# Generated by gen_sram_macros.py (FakeRAM2.0 extended: 2R1W)
VERSION 5.7 ;
BUSBITCHARS "[]" ;
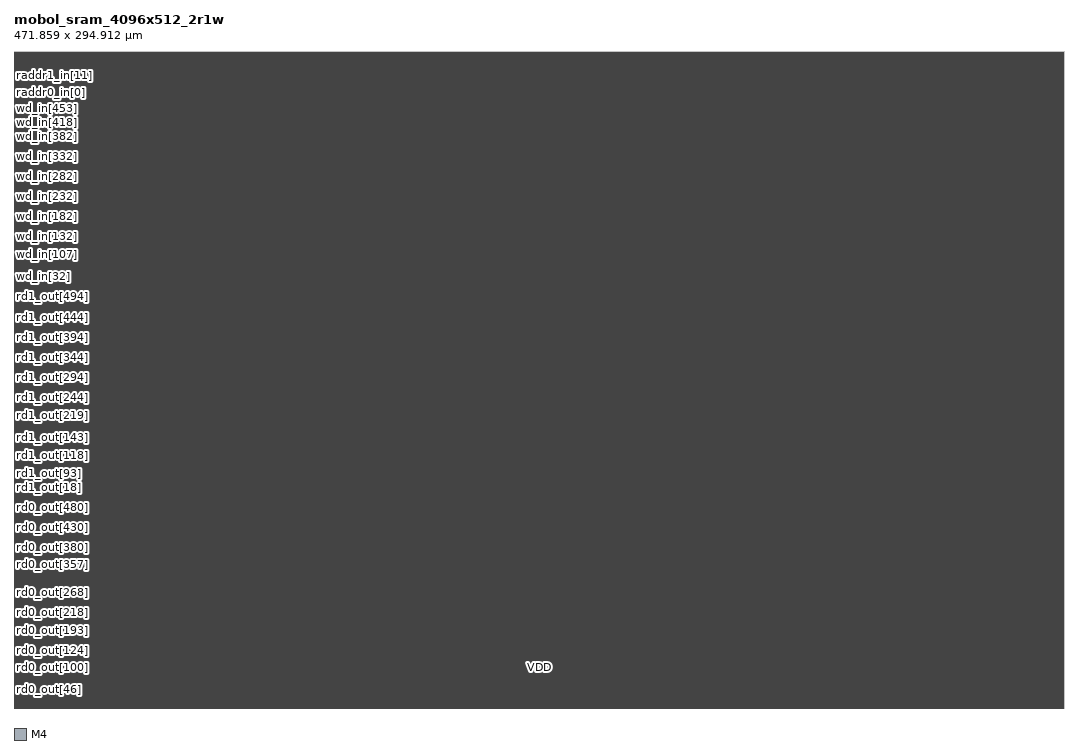
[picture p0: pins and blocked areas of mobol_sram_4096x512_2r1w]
MACRO mobol_sram_4096x512_2r1w
  FOREIGN mobol_sram_4096x512_2r1w 0 0 ;
  SYMMETRY X Y R90 ;
  SIZE 471.859 BY 294.912 ;
  CLASS BLOCK ;
  PIN rd0_out[0]
    DIRECTION OUTPUT ;
    USE SIGNAL ;
    SHAPE ABUTMENT ;
    PORT
      LAYER M4 ;
      RECT 0.000 0.036 0.018 0.054 ;
    END
  END rd0_out[0]
  PIN rd0_out[1]
    DIRECTION OUTPUT ;
    USE SIGNAL ;
    SHAPE ABUTMENT ;
    PORT
      LAYER M4 ;
      RECT 0.000 0.216 0.018 0.234 ;
    END
  END rd0_out[1]
  PIN rd0_out[2]
    DIRECTION OUTPUT ;
    USE SIGNAL ;
    SHAPE ABUTMENT ;
    PORT
      LAYER M4 ;
      RECT 0.000 0.396 0.018 0.414 ;
    END
  END rd0_out[2]
  PIN rd0_out[3]
    DIRECTION OUTPUT ;
    USE SIGNAL ;
    SHAPE ABUTMENT ;
    PORT
      LAYER M4 ;
      RECT 0.000 0.576 0.018 0.594 ;
    END
  END rd0_out[3]
  PIN rd0_out[4]
    DIRECTION OUTPUT ;
    USE SIGNAL ;
    SHAPE ABUTMENT ;
    PORT
      LAYER M4 ;
      RECT 0.000 0.756 0.018 0.774 ;
    END
  END rd0_out[4]
  PIN rd0_out[5]
    DIRECTION OUTPUT ;
    USE SIGNAL ;
    SHAPE ABUTMENT ;
    PORT
      LAYER M4 ;
      RECT 0.000 0.936 0.018 0.954 ;
    END
  END rd0_out[5]
  PIN rd0_out[6]
    DIRECTION OUTPUT ;
    USE SIGNAL ;
    SHAPE ABUTMENT ;
    PORT
      LAYER M4 ;
      RECT 0.000 1.116 0.018 1.134 ;
    END
  END rd0_out[6]
  PIN rd0_out[7]
    DIRECTION OUTPUT ;
    USE SIGNAL ;
    SHAPE ABUTMENT ;
    PORT
      LAYER M4 ;
      RECT 0.000 1.296 0.018 1.314 ;
    END
  END rd0_out[7]
  PIN rd0_out[8]
    DIRECTION OUTPUT ;
    USE SIGNAL ;
    SHAPE ABUTMENT ;
    PORT
      LAYER M4 ;
      RECT 0.000 1.476 0.018 1.494 ;
    END
  END rd0_out[8]
  PIN rd0_out[9]
    DIRECTION OUTPUT ;
    USE SIGNAL ;
    SHAPE ABUTMENT ;
    PORT
      LAYER M4 ;
      RECT 0.000 1.656 0.018 1.674 ;
    END
  END rd0_out[9]
  PIN rd0_out[10]
    DIRECTION OUTPUT ;
    USE SIGNAL ;
    SHAPE ABUTMENT ;
    PORT
      LAYER M4 ;
      RECT 0.000 1.836 0.018 1.854 ;
    END
  END rd0_out[10]
  PIN rd0_out[11]
    DIRECTION OUTPUT ;
    USE SIGNAL ;
    SHAPE ABUTMENT ;
    PORT
      LAYER M4 ;
      RECT 0.000 2.016 0.018 2.034 ;
    END
  END rd0_out[11]
  PIN rd0_out[12]
    DIRECTION OUTPUT ;
    USE SIGNAL ;
    SHAPE ABUTMENT ;
    PORT
      LAYER M4 ;
      RECT 0.000 2.196 0.018 2.214 ;
    END
  END rd0_out[12]
  PIN rd0_out[13]
    DIRECTION OUTPUT ;
    USE SIGNAL ;
    SHAPE ABUTMENT ;
    PORT
      LAYER M4 ;
      RECT 0.000 2.376 0.018 2.394 ;
    END
  END rd0_out[13]
  PIN rd0_out[14]
    DIRECTION OUTPUT ;
    USE SIGNAL ;
    SHAPE ABUTMENT ;
    PORT
      LAYER M4 ;
      RECT 0.000 2.556 0.018 2.574 ;
    END
  END rd0_out[14]
  PIN rd0_out[15]
    DIRECTION OUTPUT ;
    USE SIGNAL ;
    SHAPE ABUTMENT ;
    PORT
      LAYER M4 ;
      RECT 0.000 2.736 0.018 2.754 ;
    END
  END rd0_out[15]
  PIN rd0_out[16]
    DIRECTION OUTPUT ;
    USE SIGNAL ;
    SHAPE ABUTMENT ;
    PORT
      LAYER M4 ;
      RECT 0.000 2.916 0.018 2.934 ;
    END
  END rd0_out[16]
  PIN rd0_out[17]
    DIRECTION OUTPUT ;
    USE SIGNAL ;
    SHAPE ABUTMENT ;
    PORT
      LAYER M4 ;
      RECT 0.000 3.096 0.018 3.114 ;
    END
  END rd0_out[17]
  PIN rd0_out[18]
    DIRECTION OUTPUT ;
    USE SIGNAL ;
    SHAPE ABUTMENT ;
    PORT
      LAYER M4 ;
      RECT 0.000 3.276 0.018 3.294 ;
    END
  END rd0_out[18]
  PIN rd0_out[19]
    DIRECTION OUTPUT ;
    USE SIGNAL ;
    SHAPE ABUTMENT ;
    PORT
      LAYER M4 ;
      RECT 0.000 3.456 0.018 3.474 ;
    END
  END rd0_out[19]
  PIN rd0_out[20]
    DIRECTION OUTPUT ;
    USE SIGNAL ;
    SHAPE ABUTMENT ;
    PORT
      LAYER M4 ;
      RECT 0.000 3.636 0.018 3.654 ;
    END
  END rd0_out[20]
  PIN rd0_out[21]
    DIRECTION OUTPUT ;
    USE SIGNAL ;
    SHAPE ABUTMENT ;
    PORT
      LAYER M4 ;
      RECT 0.000 3.816 0.018 3.834 ;
    END
  END rd0_out[21]
  PIN rd0_out[22]
    DIRECTION OUTPUT ;
    USE SIGNAL ;
    SHAPE ABUTMENT ;
    PORT
      LAYER M4 ;
      RECT 0.000 3.996 0.018 4.014 ;
    END
  END rd0_out[22]
  PIN rd0_out[23]
    DIRECTION OUTPUT ;
    USE SIGNAL ;
    SHAPE ABUTMENT ;
    PORT
      LAYER M4 ;
      RECT 0.000 4.176 0.018 4.194 ;
    END
  END rd0_out[23]
  PIN rd0_out[24]
    DIRECTION OUTPUT ;
    USE SIGNAL ;
    SHAPE ABUTMENT ;
    PORT
      LAYER M4 ;
      RECT 0.000 4.356 0.018 4.374 ;
    END
  END rd0_out[24]
  PIN rd0_out[25]
    DIRECTION OUTPUT ;
    USE SIGNAL ;
    SHAPE ABUTMENT ;
    PORT
      LAYER M4 ;
      RECT 0.000 4.536 0.018 4.554 ;
    END
  END rd0_out[25]
  PIN rd0_out[26]
    DIRECTION OUTPUT ;
    USE SIGNAL ;
    SHAPE ABUTMENT ;
    PORT
      LAYER M4 ;
      RECT 0.000 4.716 0.018 4.734 ;
    END
  END rd0_out[26]
  PIN rd0_out[27]
    DIRECTION OUTPUT ;
    USE SIGNAL ;
    SHAPE ABUTMENT ;
    PORT
      LAYER M4 ;
      RECT 0.000 4.896 0.018 4.914 ;
    END
  END rd0_out[27]
  PIN rd0_out[28]
    DIRECTION OUTPUT ;
    USE SIGNAL ;
    SHAPE ABUTMENT ;
    PORT
      LAYER M4 ;
      RECT 0.000 5.076 0.018 5.094 ;
    END
  END rd0_out[28]
  PIN rd0_out[29]
    DIRECTION OUTPUT ;
    USE SIGNAL ;
    SHAPE ABUTMENT ;
    PORT
      LAYER M4 ;
      RECT 0.000 5.256 0.018 5.274 ;
    END
  END rd0_out[29]
  PIN rd0_out[30]
    DIRECTION OUTPUT ;
    USE SIGNAL ;
    SHAPE ABUTMENT ;
    PORT
      LAYER M4 ;
      RECT 0.000 5.436 0.018 5.454 ;
    END
  END rd0_out[30]
  PIN rd0_out[31]
    DIRECTION OUTPUT ;
    USE SIGNAL ;
    SHAPE ABUTMENT ;
    PORT
      LAYER M4 ;
      RECT 0.000 5.616 0.018 5.634 ;
    END
  END rd0_out[31]
  PIN rd0_out[32]
    DIRECTION OUTPUT ;
    USE SIGNAL ;
    SHAPE ABUTMENT ;
    PORT
      LAYER M4 ;
      RECT 0.000 5.796 0.018 5.814 ;
    END
  END rd0_out[32]
  PIN rd0_out[33]
    DIRECTION OUTPUT ;
    USE SIGNAL ;
    SHAPE ABUTMENT ;
    PORT
      LAYER M4 ;
      RECT 0.000 5.976 0.018 5.994 ;
    END
  END rd0_out[33]
  PIN rd0_out[34]
    DIRECTION OUTPUT ;
    USE SIGNAL ;
    SHAPE ABUTMENT ;
    PORT
      LAYER M4 ;
      RECT 0.000 6.156 0.018 6.174 ;
    END
  END rd0_out[34]
  PIN rd0_out[35]
    DIRECTION OUTPUT ;
    USE SIGNAL ;
    SHAPE ABUTMENT ;
    PORT
      LAYER M4 ;
      RECT 0.000 6.336 0.018 6.354 ;
    END
  END rd0_out[35]
  PIN rd0_out[36]
    DIRECTION OUTPUT ;
    USE SIGNAL ;
    SHAPE ABUTMENT ;
    PORT
      LAYER M4 ;
      RECT 0.000 6.516 0.018 6.534 ;
    END
  END rd0_out[36]
  PIN rd0_out[37]
    DIRECTION OUTPUT ;
    USE SIGNAL ;
    SHAPE ABUTMENT ;
    PORT
      LAYER M4 ;
      RECT 0.000 6.696 0.018 6.714 ;
    END
  END rd0_out[37]
  PIN rd0_out[38]
    DIRECTION OUTPUT ;
    USE SIGNAL ;
    SHAPE ABUTMENT ;
    PORT
      LAYER M4 ;
      RECT 0.000 6.876 0.018 6.894 ;
    END
  END rd0_out[38]
  PIN rd0_out[39]
    DIRECTION OUTPUT ;
    USE SIGNAL ;
    SHAPE ABUTMENT ;
    PORT
      LAYER M4 ;
      RECT 0.000 7.056 0.018 7.074 ;
    END
  END rd0_out[39]
  PIN rd0_out[40]
    DIRECTION OUTPUT ;
    USE SIGNAL ;
    SHAPE ABUTMENT ;
    PORT
      LAYER M4 ;
      RECT 0.000 7.236 0.018 7.254 ;
    END
  END rd0_out[40]
  PIN rd0_out[41]
    DIRECTION OUTPUT ;
    USE SIGNAL ;
    SHAPE ABUTMENT ;
    PORT
      LAYER M4 ;
      RECT 0.000 7.416 0.018 7.434 ;
    END
  END rd0_out[41]
  PIN rd0_out[42]
    DIRECTION OUTPUT ;
    USE SIGNAL ;
    SHAPE ABUTMENT ;
    PORT
      LAYER M4 ;
      RECT 0.000 7.596 0.018 7.614 ;
    END
  END rd0_out[42]
  PIN rd0_out[43]
    DIRECTION OUTPUT ;
    USE SIGNAL ;
    SHAPE ABUTMENT ;
    PORT
      LAYER M4 ;
      RECT 0.000 7.776 0.018 7.794 ;
    END
  END rd0_out[43]
  PIN rd0_out[44]
    DIRECTION OUTPUT ;
    USE SIGNAL ;
    SHAPE ABUTMENT ;
    PORT
      LAYER M4 ;
      RECT 0.000 7.956 0.018 7.974 ;
    END
  END rd0_out[44]
  PIN rd0_out[45]
    DIRECTION OUTPUT ;
    USE SIGNAL ;
    SHAPE ABUTMENT ;
    PORT
      LAYER M4 ;
      RECT 0.000 8.136 0.018 8.154 ;
    END
  END rd0_out[45]
  PIN rd0_out[46]
    DIRECTION OUTPUT ;
    USE SIGNAL ;
    SHAPE ABUTMENT ;
    PORT
      LAYER M4 ;
      RECT 0.000 8.316 0.018 8.334 ;
    END
  END rd0_out[46]
  PIN rd0_out[47]
    DIRECTION OUTPUT ;
    USE SIGNAL ;
    SHAPE ABUTMENT ;
    PORT
      LAYER M4 ;
      RECT 0.000 8.496 0.018 8.514 ;
    END
  END rd0_out[47]
  PIN rd0_out[48]
    DIRECTION OUTPUT ;
    USE SIGNAL ;
    SHAPE ABUTMENT ;
    PORT
      LAYER M4 ;
      RECT 0.000 8.676 0.018 8.694 ;
    END
  END rd0_out[48]
  PIN rd0_out[49]
    DIRECTION OUTPUT ;
    USE SIGNAL ;
    SHAPE ABUTMENT ;
    PORT
      LAYER M4 ;
      RECT 0.000 8.856 0.018 8.874 ;
    END
  END rd0_out[49]
  PIN rd0_out[50]
    DIRECTION OUTPUT ;
    USE SIGNAL ;
    SHAPE ABUTMENT ;
    PORT
      LAYER M4 ;
      RECT 0.000 9.036 0.018 9.054 ;
    END
  END rd0_out[50]
  PIN rd0_out[51]
    DIRECTION OUTPUT ;
    USE SIGNAL ;
    SHAPE ABUTMENT ;
    PORT
      LAYER M4 ;
      RECT 0.000 9.216 0.018 9.234 ;
    END
  END rd0_out[51]
  PIN rd0_out[52]
    DIRECTION OUTPUT ;
    USE SIGNAL ;
    SHAPE ABUTMENT ;
    PORT
      LAYER M4 ;
      RECT 0.000 9.396 0.018 9.414 ;
    END
  END rd0_out[52]
  PIN rd0_out[53]
    DIRECTION OUTPUT ;
    USE SIGNAL ;
    SHAPE ABUTMENT ;
    PORT
      LAYER M4 ;
      RECT 0.000 9.576 0.018 9.594 ;
    END
  END rd0_out[53]
  PIN rd0_out[54]
    DIRECTION OUTPUT ;
    USE SIGNAL ;
    SHAPE ABUTMENT ;
    PORT
      LAYER M4 ;
      RECT 0.000 9.756 0.018 9.774 ;
    END
  END rd0_out[54]
  PIN rd0_out[55]
    DIRECTION OUTPUT ;
    USE SIGNAL ;
    SHAPE ABUTMENT ;
    PORT
      LAYER M4 ;
      RECT 0.000 9.936 0.018 9.954 ;
    END
  END rd0_out[55]
  PIN rd0_out[56]
    DIRECTION OUTPUT ;
    USE SIGNAL ;
    SHAPE ABUTMENT ;
    PORT
      LAYER M4 ;
      RECT 0.000 10.116 0.018 10.134 ;
    END
  END rd0_out[56]
  PIN rd0_out[57]
    DIRECTION OUTPUT ;
    USE SIGNAL ;
    SHAPE ABUTMENT ;
    PORT
      LAYER M4 ;
      RECT 0.000 10.296 0.018 10.314 ;
    END
  END rd0_out[57]
  PIN rd0_out[58]
    DIRECTION OUTPUT ;
    USE SIGNAL ;
    SHAPE ABUTMENT ;
    PORT
      LAYER M4 ;
      RECT 0.000 10.476 0.018 10.494 ;
    END
  END rd0_out[58]
  PIN rd0_out[59]
    DIRECTION OUTPUT ;
    USE SIGNAL ;
    SHAPE ABUTMENT ;
    PORT
      LAYER M4 ;
      RECT 0.000 10.656 0.018 10.674 ;
    END
  END rd0_out[59]
  PIN rd0_out[60]
    DIRECTION OUTPUT ;
    USE SIGNAL ;
    SHAPE ABUTMENT ;
    PORT
      LAYER M4 ;
      RECT 0.000 10.836 0.018 10.854 ;
    END
  END rd0_out[60]
  PIN rd0_out[61]
    DIRECTION OUTPUT ;
    USE SIGNAL ;
    SHAPE ABUTMENT ;
    PORT
      LAYER M4 ;
      RECT 0.000 11.016 0.018 11.034 ;
    END
  END rd0_out[61]
  PIN rd0_out[62]
    DIRECTION OUTPUT ;
    USE SIGNAL ;
    SHAPE ABUTMENT ;
    PORT
      LAYER M4 ;
      RECT 0.000 11.196 0.018 11.214 ;
    END
  END rd0_out[62]
  PIN rd0_out[63]
    DIRECTION OUTPUT ;
    USE SIGNAL ;
    SHAPE ABUTMENT ;
    PORT
      LAYER M4 ;
      RECT 0.000 11.376 0.018 11.394 ;
    END
  END rd0_out[63]
  PIN rd0_out[64]
    DIRECTION OUTPUT ;
    USE SIGNAL ;
    SHAPE ABUTMENT ;
    PORT
      LAYER M4 ;
      RECT 0.000 11.556 0.018 11.574 ;
    END
  END rd0_out[64]
  PIN rd0_out[65]
    DIRECTION OUTPUT ;
    USE SIGNAL ;
    SHAPE ABUTMENT ;
    PORT
      LAYER M4 ;
      RECT 0.000 11.736 0.018 11.754 ;
    END
  END rd0_out[65]
  PIN rd0_out[66]
    DIRECTION OUTPUT ;
    USE SIGNAL ;
    SHAPE ABUTMENT ;
    PORT
      LAYER M4 ;
      RECT 0.000 11.916 0.018 11.934 ;
    END
  END rd0_out[66]
  PIN rd0_out[67]
    DIRECTION OUTPUT ;
    USE SIGNAL ;
    SHAPE ABUTMENT ;
    PORT
      LAYER M4 ;
      RECT 0.000 12.096 0.018 12.114 ;
    END
  END rd0_out[67]
  PIN rd0_out[68]
    DIRECTION OUTPUT ;
    USE SIGNAL ;
    SHAPE ABUTMENT ;
    PORT
      LAYER M4 ;
      RECT 0.000 12.276 0.018 12.294 ;
    END
  END rd0_out[68]
  PIN rd0_out[69]
    DIRECTION OUTPUT ;
    USE SIGNAL ;
    SHAPE ABUTMENT ;
    PORT
      LAYER M4 ;
      RECT 0.000 12.456 0.018 12.474 ;
    END
  END rd0_out[69]
  PIN rd0_out[70]
    DIRECTION OUTPUT ;
    USE SIGNAL ;
    SHAPE ABUTMENT ;
    PORT
      LAYER M4 ;
      RECT 0.000 12.636 0.018 12.654 ;
    END
  END rd0_out[70]
  PIN rd0_out[71]
    DIRECTION OUTPUT ;
    USE SIGNAL ;
    SHAPE ABUTMENT ;
    PORT
      LAYER M4 ;
      RECT 0.000 12.816 0.018 12.834 ;
    END
  END rd0_out[71]
  PIN rd0_out[72]
    DIRECTION OUTPUT ;
    USE SIGNAL ;
    SHAPE ABUTMENT ;
    PORT
      LAYER M4 ;
      RECT 0.000 12.996 0.018 13.014 ;
    END
  END rd0_out[72]
  PIN rd0_out[73]
    DIRECTION OUTPUT ;
    USE SIGNAL ;
    SHAPE ABUTMENT ;
    PORT
      LAYER M4 ;
      RECT 0.000 13.176 0.018 13.194 ;
    END
  END rd0_out[73]
  PIN rd0_out[74]
    DIRECTION OUTPUT ;
    USE SIGNAL ;
    SHAPE ABUTMENT ;
    PORT
      LAYER M4 ;
      RECT 0.000 13.356 0.018 13.374 ;
    END
  END rd0_out[74]
  PIN rd0_out[75]
    DIRECTION OUTPUT ;
    USE SIGNAL ;
    SHAPE ABUTMENT ;
    PORT
      LAYER M4 ;
      RECT 0.000 13.536 0.018 13.554 ;
    END
  END rd0_out[75]
  PIN rd0_out[76]
    DIRECTION OUTPUT ;
    USE SIGNAL ;
    SHAPE ABUTMENT ;
    PORT
      LAYER M4 ;
      RECT 0.000 13.716 0.018 13.734 ;
    END
  END rd0_out[76]
  PIN rd0_out[77]
    DIRECTION OUTPUT ;
    USE SIGNAL ;
    SHAPE ABUTMENT ;
    PORT
      LAYER M4 ;
      RECT 0.000 13.896 0.018 13.914 ;
    END
  END rd0_out[77]
  PIN rd0_out[78]
    DIRECTION OUTPUT ;
    USE SIGNAL ;
    SHAPE ABUTMENT ;
    PORT
      LAYER M4 ;
      RECT 0.000 14.076 0.018 14.094 ;
    END
  END rd0_out[78]
  PIN rd0_out[79]
    DIRECTION OUTPUT ;
    USE SIGNAL ;
    SHAPE ABUTMENT ;
    PORT
      LAYER M4 ;
      RECT 0.000 14.256 0.018 14.274 ;
    END
  END rd0_out[79]
  PIN rd0_out[80]
    DIRECTION OUTPUT ;
    USE SIGNAL ;
    SHAPE ABUTMENT ;
    PORT
      LAYER M4 ;
      RECT 0.000 14.436 0.018 14.454 ;
    END
  END rd0_out[80]
  PIN rd0_out[81]
    DIRECTION OUTPUT ;
    USE SIGNAL ;
    SHAPE ABUTMENT ;
    PORT
      LAYER M4 ;
      RECT 0.000 14.616 0.018 14.634 ;
    END
  END rd0_out[81]
  PIN rd0_out[82]
    DIRECTION OUTPUT ;
    USE SIGNAL ;
    SHAPE ABUTMENT ;
    PORT
      LAYER M4 ;
      RECT 0.000 14.796 0.018 14.814 ;
    END
  END rd0_out[82]
  PIN rd0_out[83]
    DIRECTION OUTPUT ;
    USE SIGNAL ;
    SHAPE ABUTMENT ;
    PORT
      LAYER M4 ;
      RECT 0.000 14.976 0.018 14.994 ;
    END
  END rd0_out[83]
  PIN rd0_out[84]
    DIRECTION OUTPUT ;
    USE SIGNAL ;
    SHAPE ABUTMENT ;
    PORT
      LAYER M4 ;
      RECT 0.000 15.156 0.018 15.174 ;
    END
  END rd0_out[84]
  PIN rd0_out[85]
    DIRECTION OUTPUT ;
    USE SIGNAL ;
    SHAPE ABUTMENT ;
    PORT
      LAYER M4 ;
      RECT 0.000 15.336 0.018 15.354 ;
    END
  END rd0_out[85]
  PIN rd0_out[86]
    DIRECTION OUTPUT ;
    USE SIGNAL ;
    SHAPE ABUTMENT ;
    PORT
      LAYER M4 ;
      RECT 0.000 15.516 0.018 15.534 ;
    END
  END rd0_out[86]
  PIN rd0_out[87]
    DIRECTION OUTPUT ;
    USE SIGNAL ;
    SHAPE ABUTMENT ;
    PORT
      LAYER M4 ;
      RECT 0.000 15.696 0.018 15.714 ;
    END
  END rd0_out[87]
  PIN rd0_out[88]
    DIRECTION OUTPUT ;
    USE SIGNAL ;
    SHAPE ABUTMENT ;
    PORT
      LAYER M4 ;
      RECT 0.000 15.876 0.018 15.894 ;
    END
  END rd0_out[88]
  PIN rd0_out[89]
    DIRECTION OUTPUT ;
    USE SIGNAL ;
    SHAPE ABUTMENT ;
    PORT
      LAYER M4 ;
      RECT 0.000 16.056 0.018 16.074 ;
    END
  END rd0_out[89]
  PIN rd0_out[90]
    DIRECTION OUTPUT ;
    USE SIGNAL ;
    SHAPE ABUTMENT ;
    PORT
      LAYER M4 ;
      RECT 0.000 16.236 0.018 16.254 ;
    END
  END rd0_out[90]
  PIN rd0_out[91]
    DIRECTION OUTPUT ;
    USE SIGNAL ;
    SHAPE ABUTMENT ;
    PORT
      LAYER M4 ;
      RECT 0.000 16.416 0.018 16.434 ;
    END
  END rd0_out[91]
  PIN rd0_out[92]
    DIRECTION OUTPUT ;
    USE SIGNAL ;
    SHAPE ABUTMENT ;
    PORT
      LAYER M4 ;
      RECT 0.000 16.596 0.018 16.614 ;
    END
  END rd0_out[92]
  PIN rd0_out[93]
    DIRECTION OUTPUT ;
    USE SIGNAL ;
    SHAPE ABUTMENT ;
    PORT
      LAYER M4 ;
      RECT 0.000 16.776 0.018 16.794 ;
    END
  END rd0_out[93]
  PIN rd0_out[94]
    DIRECTION OUTPUT ;
    USE SIGNAL ;
    SHAPE ABUTMENT ;
    PORT
      LAYER M4 ;
      RECT 0.000 16.956 0.018 16.974 ;
    END
  END rd0_out[94]
  PIN rd0_out[95]
    DIRECTION OUTPUT ;
    USE SIGNAL ;
    SHAPE ABUTMENT ;
    PORT
      LAYER M4 ;
      RECT 0.000 17.136 0.018 17.154 ;
    END
  END rd0_out[95]
  PIN rd0_out[96]
    DIRECTION OUTPUT ;
    USE SIGNAL ;
    SHAPE ABUTMENT ;
    PORT
      LAYER M4 ;
      RECT 0.000 17.316 0.018 17.334 ;
    END
  END rd0_out[96]
  PIN rd0_out[97]
    DIRECTION OUTPUT ;
    USE SIGNAL ;
    SHAPE ABUTMENT ;
    PORT
      LAYER M4 ;
      RECT 0.000 17.496 0.018 17.514 ;
    END
  END rd0_out[97]
  PIN rd0_out[98]
    DIRECTION OUTPUT ;
    USE SIGNAL ;
    SHAPE ABUTMENT ;
    PORT
      LAYER M4 ;
      RECT 0.000 17.676 0.018 17.694 ;
    END
  END rd0_out[98]
  PIN rd0_out[99]
    DIRECTION OUTPUT ;
    USE SIGNAL ;
    SHAPE ABUTMENT ;
    PORT
      LAYER M4 ;
      RECT 0.000 17.856 0.018 17.874 ;
    END
  END rd0_out[99]
  PIN rd0_out[100]
    DIRECTION OUTPUT ;
    USE SIGNAL ;
    SHAPE ABUTMENT ;
    PORT
      LAYER M4 ;
      RECT 0.000 18.036 0.018 18.054 ;
    END
  END rd0_out[100]
  PIN rd0_out[101]
    DIRECTION OUTPUT ;
    USE SIGNAL ;
    SHAPE ABUTMENT ;
    PORT
      LAYER M4 ;
      RECT 0.000 18.216 0.018 18.234 ;
    END
  END rd0_out[101]
  PIN rd0_out[102]
    DIRECTION OUTPUT ;
    USE SIGNAL ;
    SHAPE ABUTMENT ;
    PORT
      LAYER M4 ;
      RECT 0.000 18.396 0.018 18.414 ;
    END
  END rd0_out[102]
  PIN rd0_out[103]
    DIRECTION OUTPUT ;
    USE SIGNAL ;
    SHAPE ABUTMENT ;
    PORT
      LAYER M4 ;
      RECT 0.000 18.576 0.018 18.594 ;
    END
  END rd0_out[103]
  PIN rd0_out[104]
    DIRECTION OUTPUT ;
    USE SIGNAL ;
    SHAPE ABUTMENT ;
    PORT
      LAYER M4 ;
      RECT 0.000 18.756 0.018 18.774 ;
    END
  END rd0_out[104]
  PIN rd0_out[105]
    DIRECTION OUTPUT ;
    USE SIGNAL ;
    SHAPE ABUTMENT ;
    PORT
      LAYER M4 ;
      RECT 0.000 18.936 0.018 18.954 ;
    END
  END rd0_out[105]
  PIN rd0_out[106]
    DIRECTION OUTPUT ;
    USE SIGNAL ;
    SHAPE ABUTMENT ;
    PORT
      LAYER M4 ;
      RECT 0.000 19.116 0.018 19.134 ;
    END
  END rd0_out[106]
  PIN rd0_out[107]
    DIRECTION OUTPUT ;
    USE SIGNAL ;
    SHAPE ABUTMENT ;
    PORT
      LAYER M4 ;
      RECT 0.000 19.296 0.018 19.314 ;
    END
  END rd0_out[107]
  PIN rd0_out[108]
    DIRECTION OUTPUT ;
    USE SIGNAL ;
    SHAPE ABUTMENT ;
    PORT
      LAYER M4 ;
      RECT 0.000 19.476 0.018 19.494 ;
    END
  END rd0_out[108]
  PIN rd0_out[109]
    DIRECTION OUTPUT ;
    USE SIGNAL ;
    SHAPE ABUTMENT ;
    PORT
      LAYER M4 ;
      RECT 0.000 19.656 0.018 19.674 ;
    END
  END rd0_out[109]
  PIN rd0_out[110]
    DIRECTION OUTPUT ;
    USE SIGNAL ;
    SHAPE ABUTMENT ;
    PORT
      LAYER M4 ;
      RECT 0.000 19.836 0.018 19.854 ;
    END
  END rd0_out[110]
  PIN rd0_out[111]
    DIRECTION OUTPUT ;
    USE SIGNAL ;
    SHAPE ABUTMENT ;
    PORT
      LAYER M4 ;
      RECT 0.000 20.016 0.018 20.034 ;
    END
  END rd0_out[111]
  PIN rd0_out[112]
    DIRECTION OUTPUT ;
    USE SIGNAL ;
    SHAPE ABUTMENT ;
    PORT
      LAYER M4 ;
      RECT 0.000 20.196 0.018 20.214 ;
    END
  END rd0_out[112]
  PIN rd0_out[113]
    DIRECTION OUTPUT ;
    USE SIGNAL ;
    SHAPE ABUTMENT ;
    PORT
      LAYER M4 ;
      RECT 0.000 20.376 0.018 20.394 ;
    END
  END rd0_out[113]
  PIN rd0_out[114]
    DIRECTION OUTPUT ;
    USE SIGNAL ;
    SHAPE ABUTMENT ;
    PORT
      LAYER M4 ;
      RECT 0.000 20.556 0.018 20.574 ;
    END
  END rd0_out[114]
  PIN rd0_out[115]
    DIRECTION OUTPUT ;
    USE SIGNAL ;
    SHAPE ABUTMENT ;
    PORT
      LAYER M4 ;
      RECT 0.000 20.736 0.018 20.754 ;
    END
  END rd0_out[115]
  PIN rd0_out[116]
    DIRECTION OUTPUT ;
    USE SIGNAL ;
    SHAPE ABUTMENT ;
    PORT
      LAYER M4 ;
      RECT 0.000 20.916 0.018 20.934 ;
    END
  END rd0_out[116]
  PIN rd0_out[117]
    DIRECTION OUTPUT ;
    USE SIGNAL ;
    SHAPE ABUTMENT ;
    PORT
      LAYER M4 ;
      RECT 0.000 21.096 0.018 21.114 ;
    END
  END rd0_out[117]
  PIN rd0_out[118]
    DIRECTION OUTPUT ;
    USE SIGNAL ;
    SHAPE ABUTMENT ;
    PORT
      LAYER M4 ;
      RECT 0.000 21.276 0.018 21.294 ;
    END
  END rd0_out[118]
  PIN rd0_out[119]
    DIRECTION OUTPUT ;
    USE SIGNAL ;
    SHAPE ABUTMENT ;
    PORT
      LAYER M4 ;
      RECT 0.000 21.456 0.018 21.474 ;
    END
  END rd0_out[119]
  PIN rd0_out[120]
    DIRECTION OUTPUT ;
    USE SIGNAL ;
    SHAPE ABUTMENT ;
    PORT
      LAYER M4 ;
      RECT 0.000 21.636 0.018 21.654 ;
    END
  END rd0_out[120]
  PIN rd0_out[121]
    DIRECTION OUTPUT ;
    USE SIGNAL ;
    SHAPE ABUTMENT ;
    PORT
      LAYER M4 ;
      RECT 0.000 21.816 0.018 21.834 ;
    END
  END rd0_out[121]
  PIN rd0_out[122]
    DIRECTION OUTPUT ;
    USE SIGNAL ;
    SHAPE ABUTMENT ;
    PORT
      LAYER M4 ;
      RECT 0.000 21.996 0.018 22.014 ;
    END
  END rd0_out[122]
  PIN rd0_out[123]
    DIRECTION OUTPUT ;
    USE SIGNAL ;
    SHAPE ABUTMENT ;
    PORT
      LAYER M4 ;
      RECT 0.000 22.176 0.018 22.194 ;
    END
  END rd0_out[123]
  PIN rd0_out[124]
    DIRECTION OUTPUT ;
    USE SIGNAL ;
    SHAPE ABUTMENT ;
    PORT
      LAYER M4 ;
      RECT 0.000 22.356 0.018 22.374 ;
    END
  END rd0_out[124]
  PIN rd0_out[125]
    DIRECTION OUTPUT ;
    USE SIGNAL ;
    SHAPE ABUTMENT ;
    PORT
      LAYER M4 ;
      RECT 0.000 22.536 0.018 22.554 ;
    END
  END rd0_out[125]
  PIN rd0_out[126]
    DIRECTION OUTPUT ;
    USE SIGNAL ;
    SHAPE ABUTMENT ;
    PORT
      LAYER M4 ;
      RECT 0.000 22.716 0.018 22.734 ;
    END
  END rd0_out[126]
  PIN rd0_out[127]
    DIRECTION OUTPUT ;
    USE SIGNAL ;
    SHAPE ABUTMENT ;
    PORT
      LAYER M4 ;
      RECT 0.000 22.896 0.018 22.914 ;
    END
  END rd0_out[127]
  PIN rd0_out[128]
    DIRECTION OUTPUT ;
    USE SIGNAL ;
    SHAPE ABUTMENT ;
    PORT
      LAYER M4 ;
      RECT 0.000 23.076 0.018 23.094 ;
    END
  END rd0_out[128]
  PIN rd0_out[129]
    DIRECTION OUTPUT ;
    USE SIGNAL ;
    SHAPE ABUTMENT ;
    PORT
      LAYER M4 ;
      RECT 0.000 23.256 0.018 23.274 ;
    END
  END rd0_out[129]
  PIN rd0_out[130]
    DIRECTION OUTPUT ;
    USE SIGNAL ;
    SHAPE ABUTMENT ;
    PORT
      LAYER M4 ;
      RECT 0.000 23.436 0.018 23.454 ;
    END
  END rd0_out[130]
  PIN rd0_out[131]
    DIRECTION OUTPUT ;
    USE SIGNAL ;
    SHAPE ABUTMENT ;
    PORT
      LAYER M4 ;
      RECT 0.000 23.616 0.018 23.634 ;
    END
  END rd0_out[131]
  PIN rd0_out[132]
    DIRECTION OUTPUT ;
    USE SIGNAL ;
    SHAPE ABUTMENT ;
    PORT
      LAYER M4 ;
      RECT 0.000 23.796 0.018 23.814 ;
    END
  END rd0_out[132]
  PIN rd0_out[133]
    DIRECTION OUTPUT ;
    USE SIGNAL ;
    SHAPE ABUTMENT ;
    PORT
      LAYER M4 ;
      RECT 0.000 23.976 0.018 23.994 ;
    END
  END rd0_out[133]
  PIN rd0_out[134]
    DIRECTION OUTPUT ;
    USE SIGNAL ;
    SHAPE ABUTMENT ;
    PORT
      LAYER M4 ;
      RECT 0.000 24.156 0.018 24.174 ;
    END
  END rd0_out[134]
  PIN rd0_out[135]
    DIRECTION OUTPUT ;
    USE SIGNAL ;
    SHAPE ABUTMENT ;
    PORT
      LAYER M4 ;
      RECT 0.000 24.336 0.018 24.354 ;
    END
  END rd0_out[135]
  PIN rd0_out[136]
    DIRECTION OUTPUT ;
    USE SIGNAL ;
    SHAPE ABUTMENT ;
    PORT
      LAYER M4 ;
      RECT 0.000 24.516 0.018 24.534 ;
    END
  END rd0_out[136]
  PIN rd0_out[137]
    DIRECTION OUTPUT ;
    USE SIGNAL ;
    SHAPE ABUTMENT ;
    PORT
      LAYER M4 ;
      RECT 0.000 24.696 0.018 24.714 ;
    END
  END rd0_out[137]
  PIN rd0_out[138]
    DIRECTION OUTPUT ;
    USE SIGNAL ;
    SHAPE ABUTMENT ;
    PORT
      LAYER M4 ;
      RECT 0.000 24.876 0.018 24.894 ;
    END
  END rd0_out[138]
  PIN rd0_out[139]
    DIRECTION OUTPUT ;
    USE SIGNAL ;
    SHAPE ABUTMENT ;
    PORT
      LAYER M4 ;
      RECT 0.000 25.056 0.018 25.074 ;
    END
  END rd0_out[139]
  PIN rd0_out[140]
    DIRECTION OUTPUT ;
    USE SIGNAL ;
    SHAPE ABUTMENT ;
    PORT
      LAYER M4 ;
      RECT 0.000 25.236 0.018 25.254 ;
    END
  END rd0_out[140]
  PIN rd0_out[141]
    DIRECTION OUTPUT ;
    USE SIGNAL ;
    SHAPE ABUTMENT ;
    PORT
      LAYER M4 ;
      RECT 0.000 25.416 0.018 25.434 ;
    END
  END rd0_out[141]
  PIN rd0_out[142]
    DIRECTION OUTPUT ;
    USE SIGNAL ;
    SHAPE ABUTMENT ;
    PORT
      LAYER M4 ;
      RECT 0.000 25.596 0.018 25.614 ;
    END
  END rd0_out[142]
  PIN rd0_out[143]
    DIRECTION OUTPUT ;
    USE SIGNAL ;
    SHAPE ABUTMENT ;
    PORT
      LAYER M4 ;
      RECT 0.000 25.776 0.018 25.794 ;
    END
  END rd0_out[143]
  PIN rd0_out[144]
    DIRECTION OUTPUT ;
    USE SIGNAL ;
    SHAPE ABUTMENT ;
    PORT
      LAYER M4 ;
      RECT 0.000 25.956 0.018 25.974 ;
    END
  END rd0_out[144]
  PIN rd0_out[145]
    DIRECTION OUTPUT ;
    USE SIGNAL ;
    SHAPE ABUTMENT ;
    PORT
      LAYER M4 ;
      RECT 0.000 26.136 0.018 26.154 ;
    END
  END rd0_out[145]
  PIN rd0_out[146]
    DIRECTION OUTPUT ;
    USE SIGNAL ;
    SHAPE ABUTMENT ;
    PORT
      LAYER M4 ;
      RECT 0.000 26.316 0.018 26.334 ;
    END
  END rd0_out[146]
  PIN rd0_out[147]
    DIRECTION OUTPUT ;
    USE SIGNAL ;
    SHAPE ABUTMENT ;
    PORT
      LAYER M4 ;
      RECT 0.000 26.496 0.018 26.514 ;
    END
  END rd0_out[147]
  PIN rd0_out[148]
    DIRECTION OUTPUT ;
    USE SIGNAL ;
    SHAPE ABUTMENT ;
    PORT
      LAYER M4 ;
      RECT 0.000 26.676 0.018 26.694 ;
    END
  END rd0_out[148]
  PIN rd0_out[149]
    DIRECTION OUTPUT ;
    USE SIGNAL ;
    SHAPE ABUTMENT ;
    PORT
      LAYER M4 ;
      RECT 0.000 26.856 0.018 26.874 ;
    END
  END rd0_out[149]
  PIN rd0_out[150]
    DIRECTION OUTPUT ;
    USE SIGNAL ;
    SHAPE ABUTMENT ;
    PORT
      LAYER M4 ;
      RECT 0.000 27.036 0.018 27.054 ;
    END
  END rd0_out[150]
  PIN rd0_out[151]
    DIRECTION OUTPUT ;
    USE SIGNAL ;
    SHAPE ABUTMENT ;
    PORT
      LAYER M4 ;
      RECT 0.000 27.216 0.018 27.234 ;
    END
  END rd0_out[151]
  PIN rd0_out[152]
    DIRECTION OUTPUT ;
    USE SIGNAL ;
    SHAPE ABUTMENT ;
    PORT
      LAYER M4 ;
      RECT 0.000 27.396 0.018 27.414 ;
    END
  END rd0_out[152]
  PIN rd0_out[153]
    DIRECTION OUTPUT ;
    USE SIGNAL ;
    SHAPE ABUTMENT ;
    PORT
      LAYER M4 ;
      RECT 0.000 27.576 0.018 27.594 ;
    END
  END rd0_out[153]
  PIN rd0_out[154]
    DIRECTION OUTPUT ;
    USE SIGNAL ;
    SHAPE ABUTMENT ;
    PORT
      LAYER M4 ;
      RECT 0.000 27.756 0.018 27.774 ;
    END
  END rd0_out[154]
  PIN rd0_out[155]
    DIRECTION OUTPUT ;
    USE SIGNAL ;
    SHAPE ABUTMENT ;
    PORT
      LAYER M4 ;
      RECT 0.000 27.936 0.018 27.954 ;
    END
  END rd0_out[155]
  PIN rd0_out[156]
    DIRECTION OUTPUT ;
    USE SIGNAL ;
    SHAPE ABUTMENT ;
    PORT
      LAYER M4 ;
      RECT 0.000 28.116 0.018 28.134 ;
    END
  END rd0_out[156]
  PIN rd0_out[157]
    DIRECTION OUTPUT ;
    USE SIGNAL ;
    SHAPE ABUTMENT ;
    PORT
      LAYER M4 ;
      RECT 0.000 28.296 0.018 28.314 ;
    END
  END rd0_out[157]
  PIN rd0_out[158]
    DIRECTION OUTPUT ;
    USE SIGNAL ;
    SHAPE ABUTMENT ;
    PORT
      LAYER M4 ;
      RECT 0.000 28.476 0.018 28.494 ;
    END
  END rd0_out[158]
  PIN rd0_out[159]
    DIRECTION OUTPUT ;
    USE SIGNAL ;
    SHAPE ABUTMENT ;
    PORT
      LAYER M4 ;
      RECT 0.000 28.656 0.018 28.674 ;
    END
  END rd0_out[159]
  PIN rd0_out[160]
    DIRECTION OUTPUT ;
    USE SIGNAL ;
    SHAPE ABUTMENT ;
    PORT
      LAYER M4 ;
      RECT 0.000 28.836 0.018 28.854 ;
    END
  END rd0_out[160]
  PIN rd0_out[161]
    DIRECTION OUTPUT ;
    USE SIGNAL ;
    SHAPE ABUTMENT ;
    PORT
      LAYER M4 ;
      RECT 0.000 29.016 0.018 29.034 ;
    END
  END rd0_out[161]
  PIN rd0_out[162]
    DIRECTION OUTPUT ;
    USE SIGNAL ;
    SHAPE ABUTMENT ;
    PORT
      LAYER M4 ;
      RECT 0.000 29.196 0.018 29.214 ;
    END
  END rd0_out[162]
  PIN rd0_out[163]
    DIRECTION OUTPUT ;
    USE SIGNAL ;
    SHAPE ABUTMENT ;
    PORT
      LAYER M4 ;
      RECT 0.000 29.376 0.018 29.394 ;
    END
  END rd0_out[163]
  PIN rd0_out[164]
    DIRECTION OUTPUT ;
    USE SIGNAL ;
    SHAPE ABUTMENT ;
    PORT
      LAYER M4 ;
      RECT 0.000 29.556 0.018 29.574 ;
    END
  END rd0_out[164]
  PIN rd0_out[165]
    DIRECTION OUTPUT ;
    USE SIGNAL ;
    SHAPE ABUTMENT ;
    PORT
      LAYER M4 ;
      RECT 0.000 29.736 0.018 29.754 ;
    END
  END rd0_out[165]
  PIN rd0_out[166]
    DIRECTION OUTPUT ;
    USE SIGNAL ;
    SHAPE ABUTMENT ;
    PORT
      LAYER M4 ;
      RECT 0.000 29.916 0.018 29.934 ;
    END
  END rd0_out[166]
  PIN rd0_out[167]
    DIRECTION OUTPUT ;
    USE SIGNAL ;
    SHAPE ABUTMENT ;
    PORT
      LAYER M4 ;
      RECT 0.000 30.096 0.018 30.114 ;
    END
  END rd0_out[167]
  PIN rd0_out[168]
    DIRECTION OUTPUT ;
    USE SIGNAL ;
    SHAPE ABUTMENT ;
    PORT
      LAYER M4 ;
      RECT 0.000 30.276 0.018 30.294 ;
    END
  END rd0_out[168]
  PIN rd0_out[169]
    DIRECTION OUTPUT ;
    USE SIGNAL ;
    SHAPE ABUTMENT ;
    PORT
      LAYER M4 ;
      RECT 0.000 30.456 0.018 30.474 ;
    END
  END rd0_out[169]
  PIN rd0_out[170]
    DIRECTION OUTPUT ;
    USE SIGNAL ;
    SHAPE ABUTMENT ;
    PORT
      LAYER M4 ;
      RECT 0.000 30.636 0.018 30.654 ;
    END
  END rd0_out[170]
  PIN rd0_out[171]
    DIRECTION OUTPUT ;
    USE SIGNAL ;
    SHAPE ABUTMENT ;
    PORT
      LAYER M4 ;
      RECT 0.000 30.816 0.018 30.834 ;
    END
  END rd0_out[171]
  PIN rd0_out[172]
    DIRECTION OUTPUT ;
    USE SIGNAL ;
    SHAPE ABUTMENT ;
    PORT
      LAYER M4 ;
      RECT 0.000 30.996 0.018 31.014 ;
    END
  END rd0_out[172]
  PIN rd0_out[173]
    DIRECTION OUTPUT ;
    USE SIGNAL ;
    SHAPE ABUTMENT ;
    PORT
      LAYER M4 ;
      RECT 0.000 31.176 0.018 31.194 ;
    END
  END rd0_out[173]
  PIN rd0_out[174]
    DIRECTION OUTPUT ;
    USE SIGNAL ;
    SHAPE ABUTMENT ;
    PORT
      LAYER M4 ;
      RECT 0.000 31.356 0.018 31.374 ;
    END
  END rd0_out[174]
  PIN rd0_out[175]
    DIRECTION OUTPUT ;
    USE SIGNAL ;
    SHAPE ABUTMENT ;
    PORT
      LAYER M4 ;
      RECT 0.000 31.536 0.018 31.554 ;
    END
  END rd0_out[175]
  PIN rd0_out[176]
    DIRECTION OUTPUT ;
    USE SIGNAL ;
    SHAPE ABUTMENT ;
    PORT
      LAYER M4 ;
      RECT 0.000 31.716 0.018 31.734 ;
    END
  END rd0_out[176]
  PIN rd0_out[177]
    DIRECTION OUTPUT ;
    USE SIGNAL ;
    SHAPE ABUTMENT ;
    PORT
      LAYER M4 ;
      RECT 0.000 31.896 0.018 31.914 ;
    END
  END rd0_out[177]
  PIN rd0_out[178]
    DIRECTION OUTPUT ;
    USE SIGNAL ;
    SHAPE ABUTMENT ;
    PORT
      LAYER M4 ;
      RECT 0.000 32.076 0.018 32.094 ;
    END
  END rd0_out[178]
  PIN rd0_out[179]
    DIRECTION OUTPUT ;
    USE SIGNAL ;
    SHAPE ABUTMENT ;
    PORT
      LAYER M4 ;
      RECT 0.000 32.256 0.018 32.274 ;
    END
  END rd0_out[179]
  PIN rd0_out[180]
    DIRECTION OUTPUT ;
    USE SIGNAL ;
    SHAPE ABUTMENT ;
    PORT
      LAYER M4 ;
      RECT 0.000 32.436 0.018 32.454 ;
    END
  END rd0_out[180]
  PIN rd0_out[181]
    DIRECTION OUTPUT ;
    USE SIGNAL ;
    SHAPE ABUTMENT ;
    PORT
      LAYER M4 ;
      RECT 0.000 32.616 0.018 32.634 ;
    END
  END rd0_out[181]
  PIN rd0_out[182]
    DIRECTION OUTPUT ;
    USE SIGNAL ;
    SHAPE ABUTMENT ;
    PORT
      LAYER M4 ;
      RECT 0.000 32.796 0.018 32.814 ;
    END
  END rd0_out[182]
  PIN rd0_out[183]
    DIRECTION OUTPUT ;
    USE SIGNAL ;
    SHAPE ABUTMENT ;
    PORT
      LAYER M4 ;
      RECT 0.000 32.976 0.018 32.994 ;
    END
  END rd0_out[183]
  PIN rd0_out[184]
    DIRECTION OUTPUT ;
    USE SIGNAL ;
    SHAPE ABUTMENT ;
    PORT
      LAYER M4 ;
      RECT 0.000 33.156 0.018 33.174 ;
    END
  END rd0_out[184]
  PIN rd0_out[185]
    DIRECTION OUTPUT ;
    USE SIGNAL ;
    SHAPE ABUTMENT ;
    PORT
      LAYER M4 ;
      RECT 0.000 33.336 0.018 33.354 ;
    END
  END rd0_out[185]
  PIN rd0_out[186]
    DIRECTION OUTPUT ;
    USE SIGNAL ;
    SHAPE ABUTMENT ;
    PORT
      LAYER M4 ;
      RECT 0.000 33.516 0.018 33.534 ;
    END
  END rd0_out[186]
  PIN rd0_out[187]
    DIRECTION OUTPUT ;
    USE SIGNAL ;
    SHAPE ABUTMENT ;
    PORT
      LAYER M4 ;
      RECT 0.000 33.696 0.018 33.714 ;
    END
  END rd0_out[187]
  PIN rd0_out[188]
    DIRECTION OUTPUT ;
    USE SIGNAL ;
    SHAPE ABUTMENT ;
    PORT
      LAYER M4 ;
      RECT 0.000 33.876 0.018 33.894 ;
    END
  END rd0_out[188]
  PIN rd0_out[189]
    DIRECTION OUTPUT ;
    USE SIGNAL ;
    SHAPE ABUTMENT ;
    PORT
      LAYER M4 ;
      RECT 0.000 34.056 0.018 34.074 ;
    END
  END rd0_out[189]
  PIN rd0_out[190]
    DIRECTION OUTPUT ;
    USE SIGNAL ;
    SHAPE ABUTMENT ;
    PORT
      LAYER M4 ;
      RECT 0.000 34.236 0.018 34.254 ;
    END
  END rd0_out[190]
  PIN rd0_out[191]
    DIRECTION OUTPUT ;
    USE SIGNAL ;
    SHAPE ABUTMENT ;
    PORT
      LAYER M4 ;
      RECT 0.000 34.416 0.018 34.434 ;
    END
  END rd0_out[191]
  PIN rd0_out[192]
    DIRECTION OUTPUT ;
    USE SIGNAL ;
    SHAPE ABUTMENT ;
    PORT
      LAYER M4 ;
      RECT 0.000 34.596 0.018 34.614 ;
    END
  END rd0_out[192]
  PIN rd0_out[193]
    DIRECTION OUTPUT ;
    USE SIGNAL ;
    SHAPE ABUTMENT ;
    PORT
      LAYER M4 ;
      RECT 0.000 34.776 0.018 34.794 ;
    END
  END rd0_out[193]
  PIN rd0_out[194]
    DIRECTION OUTPUT ;
    USE SIGNAL ;
    SHAPE ABUTMENT ;
    PORT
      LAYER M4 ;
      RECT 0.000 34.956 0.018 34.974 ;
    END
  END rd0_out[194]
  PIN rd0_out[195]
    DIRECTION OUTPUT ;
    USE SIGNAL ;
    SHAPE ABUTMENT ;
    PORT
      LAYER M4 ;
      RECT 0.000 35.136 0.018 35.154 ;
    END
  END rd0_out[195]
  PIN rd0_out[196]
    DIRECTION OUTPUT ;
    USE SIGNAL ;
    SHAPE ABUTMENT ;
    PORT
      LAYER M4 ;
      RECT 0.000 35.316 0.018 35.334 ;
    END
  END rd0_out[196]
  PIN rd0_out[197]
    DIRECTION OUTPUT ;
    USE SIGNAL ;
    SHAPE ABUTMENT ;
    PORT
      LAYER M4 ;
      RECT 0.000 35.496 0.018 35.514 ;
    END
  END rd0_out[197]
  PIN rd0_out[198]
    DIRECTION OUTPUT ;
    USE SIGNAL ;
    SHAPE ABUTMENT ;
    PORT
      LAYER M4 ;
      RECT 0.000 35.676 0.018 35.694 ;
    END
  END rd0_out[198]
  PIN rd0_out[199]
    DIRECTION OUTPUT ;
    USE SIGNAL ;
    SHAPE ABUTMENT ;
    PORT
      LAYER M4 ;
      RECT 0.000 35.856 0.018 35.874 ;
    END
  END rd0_out[199]
  PIN rd0_out[200]
    DIRECTION OUTPUT ;
    USE SIGNAL ;
    SHAPE ABUTMENT ;
    PORT
      LAYER M4 ;
      RECT 0.000 36.036 0.018 36.054 ;
    END
  END rd0_out[200]
  PIN rd0_out[201]
    DIRECTION OUTPUT ;
    USE SIGNAL ;
    SHAPE ABUTMENT ;
    PORT
      LAYER M4 ;
      RECT 0.000 36.216 0.018 36.234 ;
    END
  END rd0_out[201]
  PIN rd0_out[202]
    DIRECTION OUTPUT ;
    USE SIGNAL ;
    SHAPE ABUTMENT ;
    PORT
      LAYER M4 ;
      RECT 0.000 36.396 0.018 36.414 ;
    END
  END rd0_out[202]
  PIN rd0_out[203]
    DIRECTION OUTPUT ;
    USE SIGNAL ;
    SHAPE ABUTMENT ;
    PORT
      LAYER M4 ;
      RECT 0.000 36.576 0.018 36.594 ;
    END
  END rd0_out[203]
  PIN rd0_out[204]
    DIRECTION OUTPUT ;
    USE SIGNAL ;
    SHAPE ABUTMENT ;
    PORT
      LAYER M4 ;
      RECT 0.000 36.756 0.018 36.774 ;
    END
  END rd0_out[204]
  PIN rd0_out[205]
    DIRECTION OUTPUT ;
    USE SIGNAL ;
    SHAPE ABUTMENT ;
    PORT
      LAYER M4 ;
      RECT 0.000 36.936 0.018 36.954 ;
    END
  END rd0_out[205]
  PIN rd0_out[206]
    DIRECTION OUTPUT ;
    USE SIGNAL ;
    SHAPE ABUTMENT ;
    PORT
      LAYER M4 ;
      RECT 0.000 37.116 0.018 37.134 ;
    END
  END rd0_out[206]
  PIN rd0_out[207]
    DIRECTION OUTPUT ;
    USE SIGNAL ;
    SHAPE ABUTMENT ;
    PORT
      LAYER M4 ;
      RECT 0.000 37.296 0.018 37.314 ;
    END
  END rd0_out[207]
  PIN rd0_out[208]
    DIRECTION OUTPUT ;
    USE SIGNAL ;
    SHAPE ABUTMENT ;
    PORT
      LAYER M4 ;
      RECT 0.000 37.476 0.018 37.494 ;
    END
  END rd0_out[208]
  PIN rd0_out[209]
    DIRECTION OUTPUT ;
    USE SIGNAL ;
    SHAPE ABUTMENT ;
    PORT
      LAYER M4 ;
      RECT 0.000 37.656 0.018 37.674 ;
    END
  END rd0_out[209]
  PIN rd0_out[210]
    DIRECTION OUTPUT ;
    USE SIGNAL ;
    SHAPE ABUTMENT ;
    PORT
      LAYER M4 ;
      RECT 0.000 37.836 0.018 37.854 ;
    END
  END rd0_out[210]
  PIN rd0_out[211]
    DIRECTION OUTPUT ;
    USE SIGNAL ;
    SHAPE ABUTMENT ;
    PORT
      LAYER M4 ;
      RECT 0.000 38.016 0.018 38.034 ;
    END
  END rd0_out[211]
  PIN rd0_out[212]
    DIRECTION OUTPUT ;
    USE SIGNAL ;
    SHAPE ABUTMENT ;
    PORT
      LAYER M4 ;
      RECT 0.000 38.196 0.018 38.214 ;
    END
  END rd0_out[212]
  PIN rd0_out[213]
    DIRECTION OUTPUT ;
    USE SIGNAL ;
    SHAPE ABUTMENT ;
    PORT
      LAYER M4 ;
      RECT 0.000 38.376 0.018 38.394 ;
    END
  END rd0_out[213]
  PIN rd0_out[214]
    DIRECTION OUTPUT ;
    USE SIGNAL ;
    SHAPE ABUTMENT ;
    PORT
      LAYER M4 ;
      RECT 0.000 38.556 0.018 38.574 ;
    END
  END rd0_out[214]
  PIN rd0_out[215]
    DIRECTION OUTPUT ;
    USE SIGNAL ;
    SHAPE ABUTMENT ;
    PORT
      LAYER M4 ;
      RECT 0.000 38.736 0.018 38.754 ;
    END
  END rd0_out[215]
  PIN rd0_out[216]
    DIRECTION OUTPUT ;
    USE SIGNAL ;
    SHAPE ABUTMENT ;
    PORT
      LAYER M4 ;
      RECT 0.000 38.916 0.018 38.934 ;
    END
  END rd0_out[216]
  PIN rd0_out[217]
    DIRECTION OUTPUT ;
    USE SIGNAL ;
    SHAPE ABUTMENT ;
    PORT
      LAYER M4 ;
      RECT 0.000 39.096 0.018 39.114 ;
    END
  END rd0_out[217]
  PIN rd0_out[218]
    DIRECTION OUTPUT ;
    USE SIGNAL ;
    SHAPE ABUTMENT ;
    PORT
      LAYER M4 ;
      RECT 0.000 39.276 0.018 39.294 ;
    END
  END rd0_out[218]
  PIN rd0_out[219]
    DIRECTION OUTPUT ;
    USE SIGNAL ;
    SHAPE ABUTMENT ;
    PORT
      LAYER M4 ;
      RECT 0.000 39.456 0.018 39.474 ;
    END
  END rd0_out[219]
  PIN rd0_out[220]
    DIRECTION OUTPUT ;
    USE SIGNAL ;
    SHAPE ABUTMENT ;
    PORT
      LAYER M4 ;
      RECT 0.000 39.636 0.018 39.654 ;
    END
  END rd0_out[220]
  PIN rd0_out[221]
    DIRECTION OUTPUT ;
    USE SIGNAL ;
    SHAPE ABUTMENT ;
    PORT
      LAYER M4 ;
      RECT 0.000 39.816 0.018 39.834 ;
    END
  END rd0_out[221]
  PIN rd0_out[222]
    DIRECTION OUTPUT ;
    USE SIGNAL ;
    SHAPE ABUTMENT ;
    PORT
      LAYER M4 ;
      RECT 0.000 39.996 0.018 40.014 ;
    END
  END rd0_out[222]
  PIN rd0_out[223]
    DIRECTION OUTPUT ;
    USE SIGNAL ;
    SHAPE ABUTMENT ;
    PORT
      LAYER M4 ;
      RECT 0.000 40.176 0.018 40.194 ;
    END
  END rd0_out[223]
  PIN rd0_out[224]
    DIRECTION OUTPUT ;
    USE SIGNAL ;
    SHAPE ABUTMENT ;
    PORT
      LAYER M4 ;
      RECT 0.000 40.356 0.018 40.374 ;
    END
  END rd0_out[224]
  PIN rd0_out[225]
    DIRECTION OUTPUT ;
    USE SIGNAL ;
    SHAPE ABUTMENT ;
    PORT
      LAYER M4 ;
      RECT 0.000 40.536 0.018 40.554 ;
    END
  END rd0_out[225]
  PIN rd0_out[226]
    DIRECTION OUTPUT ;
    USE SIGNAL ;
    SHAPE ABUTMENT ;
    PORT
      LAYER M4 ;
      RECT 0.000 40.716 0.018 40.734 ;
    END
  END rd0_out[226]
  PIN rd0_out[227]
    DIRECTION OUTPUT ;
    USE SIGNAL ;
    SHAPE ABUTMENT ;
    PORT
      LAYER M4 ;
      RECT 0.000 40.896 0.018 40.914 ;
    END
  END rd0_out[227]
  PIN rd0_out[228]
    DIRECTION OUTPUT ;
    USE SIGNAL ;
    SHAPE ABUTMENT ;
    PORT
      LAYER M4 ;
      RECT 0.000 41.076 0.018 41.094 ;
    END
  END rd0_out[228]
  PIN rd0_out[229]
    DIRECTION OUTPUT ;
    USE SIGNAL ;
    SHAPE ABUTMENT ;
    PORT
      LAYER M4 ;
      RECT 0.000 41.256 0.018 41.274 ;
    END
  END rd0_out[229]
  PIN rd0_out[230]
    DIRECTION OUTPUT ;
    USE SIGNAL ;
    SHAPE ABUTMENT ;
    PORT
      LAYER M4 ;
      RECT 0.000 41.436 0.018 41.454 ;
    END
  END rd0_out[230]
  PIN rd0_out[231]
    DIRECTION OUTPUT ;
    USE SIGNAL ;
    SHAPE ABUTMENT ;
    PORT
      LAYER M4 ;
      RECT 0.000 41.616 0.018 41.634 ;
    END
  END rd0_out[231]
  PIN rd0_out[232]
    DIRECTION OUTPUT ;
    USE SIGNAL ;
    SHAPE ABUTMENT ;
    PORT
      LAYER M4 ;
      RECT 0.000 41.796 0.018 41.814 ;
    END
  END rd0_out[232]
  PIN rd0_out[233]
    DIRECTION OUTPUT ;
    USE SIGNAL ;
    SHAPE ABUTMENT ;
    PORT
      LAYER M4 ;
      RECT 0.000 41.976 0.018 41.994 ;
    END
  END rd0_out[233]
  PIN rd0_out[234]
    DIRECTION OUTPUT ;
    USE SIGNAL ;
    SHAPE ABUTMENT ;
    PORT
      LAYER M4 ;
      RECT 0.000 42.156 0.018 42.174 ;
    END
  END rd0_out[234]
  PIN rd0_out[235]
    DIRECTION OUTPUT ;
    USE SIGNAL ;
    SHAPE ABUTMENT ;
    PORT
      LAYER M4 ;
      RECT 0.000 42.336 0.018 42.354 ;
    END
  END rd0_out[235]
  PIN rd0_out[236]
    DIRECTION OUTPUT ;
    USE SIGNAL ;
    SHAPE ABUTMENT ;
    PORT
      LAYER M4 ;
      RECT 0.000 42.516 0.018 42.534 ;
    END
  END rd0_out[236]
  PIN rd0_out[237]
    DIRECTION OUTPUT ;
    USE SIGNAL ;
    SHAPE ABUTMENT ;
    PORT
      LAYER M4 ;
      RECT 0.000 42.696 0.018 42.714 ;
    END
  END rd0_out[237]
  PIN rd0_out[238]
    DIRECTION OUTPUT ;
    USE SIGNAL ;
    SHAPE ABUTMENT ;
    PORT
      LAYER M4 ;
      RECT 0.000 42.876 0.018 42.894 ;
    END
  END rd0_out[238]
  PIN rd0_out[239]
    DIRECTION OUTPUT ;
    USE SIGNAL ;
    SHAPE ABUTMENT ;
    PORT
      LAYER M4 ;
      RECT 0.000 43.056 0.018 43.074 ;
    END
  END rd0_out[239]
  PIN rd0_out[240]
    DIRECTION OUTPUT ;
    USE SIGNAL ;
    SHAPE ABUTMENT ;
    PORT
      LAYER M4 ;
      RECT 0.000 43.236 0.018 43.254 ;
    END
  END rd0_out[240]
  PIN rd0_out[241]
    DIRECTION OUTPUT ;
    USE SIGNAL ;
    SHAPE ABUTMENT ;
    PORT
      LAYER M4 ;
      RECT 0.000 43.416 0.018 43.434 ;
    END
  END rd0_out[241]
  PIN rd0_out[242]
    DIRECTION OUTPUT ;
    USE SIGNAL ;
    SHAPE ABUTMENT ;
    PORT
      LAYER M4 ;
      RECT 0.000 43.596 0.018 43.614 ;
    END
  END rd0_out[242]
  PIN rd0_out[243]
    DIRECTION OUTPUT ;
    USE SIGNAL ;
    SHAPE ABUTMENT ;
    PORT
      LAYER M4 ;
      RECT 0.000 43.776 0.018 43.794 ;
    END
  END rd0_out[243]
  PIN rd0_out[244]
    DIRECTION OUTPUT ;
    USE SIGNAL ;
    SHAPE ABUTMENT ;
    PORT
      LAYER M4 ;
      RECT 0.000 43.956 0.018 43.974 ;
    END
  END rd0_out[244]
  PIN rd0_out[245]
    DIRECTION OUTPUT ;
    USE SIGNAL ;
    SHAPE ABUTMENT ;
    PORT
      LAYER M4 ;
      RECT 0.000 44.136 0.018 44.154 ;
    END
  END rd0_out[245]
  PIN rd0_out[246]
    DIRECTION OUTPUT ;
    USE SIGNAL ;
    SHAPE ABUTMENT ;
    PORT
      LAYER M4 ;
      RECT 0.000 44.316 0.018 44.334 ;
    END
  END rd0_out[246]
  PIN rd0_out[247]
    DIRECTION OUTPUT ;
    USE SIGNAL ;
    SHAPE ABUTMENT ;
    PORT
      LAYER M4 ;
      RECT 0.000 44.496 0.018 44.514 ;
    END
  END rd0_out[247]
  PIN rd0_out[248]
    DIRECTION OUTPUT ;
    USE SIGNAL ;
    SHAPE ABUTMENT ;
    PORT
      LAYER M4 ;
      RECT 0.000 44.676 0.018 44.694 ;
    END
  END rd0_out[248]
  PIN rd0_out[249]
    DIRECTION OUTPUT ;
    USE SIGNAL ;
    SHAPE ABUTMENT ;
    PORT
      LAYER M4 ;
      RECT 0.000 44.856 0.018 44.874 ;
    END
  END rd0_out[249]
  PIN rd0_out[250]
    DIRECTION OUTPUT ;
    USE SIGNAL ;
    SHAPE ABUTMENT ;
    PORT
      LAYER M4 ;
      RECT 0.000 45.036 0.018 45.054 ;
    END
  END rd0_out[250]
  PIN rd0_out[251]
    DIRECTION OUTPUT ;
    USE SIGNAL ;
    SHAPE ABUTMENT ;
    PORT
      LAYER M4 ;
      RECT 0.000 45.216 0.018 45.234 ;
    END
  END rd0_out[251]
  PIN rd0_out[252]
    DIRECTION OUTPUT ;
    USE SIGNAL ;
    SHAPE ABUTMENT ;
    PORT
      LAYER M4 ;
      RECT 0.000 45.396 0.018 45.414 ;
    END
  END rd0_out[252]
  PIN rd0_out[253]
    DIRECTION OUTPUT ;
    USE SIGNAL ;
    SHAPE ABUTMENT ;
    PORT
      LAYER M4 ;
      RECT 0.000 45.576 0.018 45.594 ;
    END
  END rd0_out[253]
  PIN rd0_out[254]
    DIRECTION OUTPUT ;
    USE SIGNAL ;
    SHAPE ABUTMENT ;
    PORT
      LAYER M4 ;
      RECT 0.000 45.756 0.018 45.774 ;
    END
  END rd0_out[254]
  PIN rd0_out[255]
    DIRECTION OUTPUT ;
    USE SIGNAL ;
    SHAPE ABUTMENT ;
    PORT
      LAYER M4 ;
      RECT 0.000 45.936 0.018 45.954 ;
    END
  END rd0_out[255]
  PIN rd0_out[256]
    DIRECTION OUTPUT ;
    USE SIGNAL ;
    SHAPE ABUTMENT ;
    PORT
      LAYER M4 ;
      RECT 0.000 46.116 0.018 46.134 ;
    END
  END rd0_out[256]
  PIN rd0_out[257]
    DIRECTION OUTPUT ;
    USE SIGNAL ;
    SHAPE ABUTMENT ;
    PORT
      LAYER M4 ;
      RECT 0.000 46.296 0.018 46.314 ;
    END
  END rd0_out[257]
  PIN rd0_out[258]
    DIRECTION OUTPUT ;
    USE SIGNAL ;
    SHAPE ABUTMENT ;
    PORT
      LAYER M4 ;
      RECT 0.000 46.476 0.018 46.494 ;
    END
  END rd0_out[258]
  PIN rd0_out[259]
    DIRECTION OUTPUT ;
    USE SIGNAL ;
    SHAPE ABUTMENT ;
    PORT
      LAYER M4 ;
      RECT 0.000 46.656 0.018 46.674 ;
    END
  END rd0_out[259]
  PIN rd0_out[260]
    DIRECTION OUTPUT ;
    USE SIGNAL ;
    SHAPE ABUTMENT ;
    PORT
      LAYER M4 ;
      RECT 0.000 46.836 0.018 46.854 ;
    END
  END rd0_out[260]
  PIN rd0_out[261]
    DIRECTION OUTPUT ;
    USE SIGNAL ;
    SHAPE ABUTMENT ;
    PORT
      LAYER M4 ;
      RECT 0.000 47.016 0.018 47.034 ;
    END
  END rd0_out[261]
  PIN rd0_out[262]
    DIRECTION OUTPUT ;
    USE SIGNAL ;
    SHAPE ABUTMENT ;
    PORT
      LAYER M4 ;
      RECT 0.000 47.196 0.018 47.214 ;
    END
  END rd0_out[262]
  PIN rd0_out[263]
    DIRECTION OUTPUT ;
    USE SIGNAL ;
    SHAPE ABUTMENT ;
    PORT
      LAYER M4 ;
      RECT 0.000 47.376 0.018 47.394 ;
    END
  END rd0_out[263]
  PIN rd0_out[264]
    DIRECTION OUTPUT ;
    USE SIGNAL ;
    SHAPE ABUTMENT ;
    PORT
      LAYER M4 ;
      RECT 0.000 47.556 0.018 47.574 ;
    END
  END rd0_out[264]
  PIN rd0_out[265]
    DIRECTION OUTPUT ;
    USE SIGNAL ;
    SHAPE ABUTMENT ;
    PORT
      LAYER M4 ;
      RECT 0.000 47.736 0.018 47.754 ;
    END
  END rd0_out[265]
  PIN rd0_out[266]
    DIRECTION OUTPUT ;
    USE SIGNAL ;
    SHAPE ABUTMENT ;
    PORT
      LAYER M4 ;
      RECT 0.000 47.916 0.018 47.934 ;
    END
  END rd0_out[266]
  PIN rd0_out[267]
    DIRECTION OUTPUT ;
    USE SIGNAL ;
    SHAPE ABUTMENT ;
    PORT
      LAYER M4 ;
      RECT 0.000 48.096 0.018 48.114 ;
    END
  END rd0_out[267]
  PIN rd0_out[268]
    DIRECTION OUTPUT ;
    USE SIGNAL ;
    SHAPE ABUTMENT ;
    PORT
      LAYER M4 ;
      RECT 0.000 48.276 0.018 48.294 ;
    END
  END rd0_out[268]
  PIN rd0_out[269]
    DIRECTION OUTPUT ;
    USE SIGNAL ;
    SHAPE ABUTMENT ;
    PORT
      LAYER M4 ;
      RECT 0.000 48.456 0.018 48.474 ;
    END
  END rd0_out[269]
  PIN rd0_out[270]
    DIRECTION OUTPUT ;
    USE SIGNAL ;
    SHAPE ABUTMENT ;
    PORT
      LAYER M4 ;
      RECT 0.000 48.636 0.018 48.654 ;
    END
  END rd0_out[270]
  PIN rd0_out[271]
    DIRECTION OUTPUT ;
    USE SIGNAL ;
    SHAPE ABUTMENT ;
    PORT
      LAYER M4 ;
      RECT 0.000 48.816 0.018 48.834 ;
    END
  END rd0_out[271]
  PIN rd0_out[272]
    DIRECTION OUTPUT ;
    USE SIGNAL ;
    SHAPE ABUTMENT ;
    PORT
      LAYER M4 ;
      RECT 0.000 48.996 0.018 49.014 ;
    END
  END rd0_out[272]
  PIN rd0_out[273]
    DIRECTION OUTPUT ;
    USE SIGNAL ;
    SHAPE ABUTMENT ;
    PORT
      LAYER M4 ;
      RECT 0.000 49.176 0.018 49.194 ;
    END
  END rd0_out[273]
  PIN rd0_out[274]
    DIRECTION OUTPUT ;
    USE SIGNAL ;
    SHAPE ABUTMENT ;
    PORT
      LAYER M4 ;
      RECT 0.000 49.356 0.018 49.374 ;
    END
  END rd0_out[274]
  PIN rd0_out[275]
    DIRECTION OUTPUT ;
    USE SIGNAL ;
    SHAPE ABUTMENT ;
    PORT
      LAYER M4 ;
      RECT 0.000 49.536 0.018 49.554 ;
    END
  END rd0_out[275]
  PIN rd0_out[276]
    DIRECTION OUTPUT ;
    USE SIGNAL ;
    SHAPE ABUTMENT ;
    PORT
      LAYER M4 ;
      RECT 0.000 49.716 0.018 49.734 ;
    END
  END rd0_out[276]
  PIN rd0_out[277]
    DIRECTION OUTPUT ;
    USE SIGNAL ;
    SHAPE ABUTMENT ;
    PORT
      LAYER M4 ;
      RECT 0.000 49.896 0.018 49.914 ;
    END
  END rd0_out[277]
  PIN rd0_out[278]
    DIRECTION OUTPUT ;
    USE SIGNAL ;
    SHAPE ABUTMENT ;
    PORT
      LAYER M4 ;
      RECT 0.000 50.076 0.018 50.094 ;
    END
  END rd0_out[278]
  PIN rd0_out[279]
    DIRECTION OUTPUT ;
    USE SIGNAL ;
    SHAPE ABUTMENT ;
    PORT
      LAYER M4 ;
      RECT 0.000 50.256 0.018 50.274 ;
    END
  END rd0_out[279]
  PIN rd0_out[280]
    DIRECTION OUTPUT ;
    USE SIGNAL ;
    SHAPE ABUTMENT ;
    PORT
      LAYER M4 ;
      RECT 0.000 50.436 0.018 50.454 ;
    END
  END rd0_out[280]
  PIN rd0_out[281]
    DIRECTION OUTPUT ;
    USE SIGNAL ;
    SHAPE ABUTMENT ;
    PORT
      LAYER M4 ;
      RECT 0.000 50.616 0.018 50.634 ;
    END
  END rd0_out[281]
  PIN rd0_out[282]
    DIRECTION OUTPUT ;
    USE SIGNAL ;
    SHAPE ABUTMENT ;
    PORT
      LAYER M4 ;
      RECT 0.000 50.796 0.018 50.814 ;
    END
  END rd0_out[282]
  PIN rd0_out[283]
    DIRECTION OUTPUT ;
    USE SIGNAL ;
    SHAPE ABUTMENT ;
    PORT
      LAYER M4 ;
      RECT 0.000 50.976 0.018 50.994 ;
    END
  END rd0_out[283]
  PIN rd0_out[284]
    DIRECTION OUTPUT ;
    USE SIGNAL ;
    SHAPE ABUTMENT ;
    PORT
      LAYER M4 ;
      RECT 0.000 51.156 0.018 51.174 ;
    END
  END rd0_out[284]
  PIN rd0_out[285]
    DIRECTION OUTPUT ;
    USE SIGNAL ;
    SHAPE ABUTMENT ;
    PORT
      LAYER M4 ;
      RECT 0.000 51.336 0.018 51.354 ;
    END
  END rd0_out[285]
  PIN rd0_out[286]
    DIRECTION OUTPUT ;
    USE SIGNAL ;
    SHAPE ABUTMENT ;
    PORT
      LAYER M4 ;
      RECT 0.000 51.516 0.018 51.534 ;
    END
  END rd0_out[286]
  PIN rd0_out[287]
    DIRECTION OUTPUT ;
    USE SIGNAL ;
    SHAPE ABUTMENT ;
    PORT
      LAYER M4 ;
      RECT 0.000 51.696 0.018 51.714 ;
    END
  END rd0_out[287]
  PIN rd0_out[288]
    DIRECTION OUTPUT ;
    USE SIGNAL ;
    SHAPE ABUTMENT ;
    PORT
      LAYER M4 ;
      RECT 0.000 51.876 0.018 51.894 ;
    END
  END rd0_out[288]
  PIN rd0_out[289]
    DIRECTION OUTPUT ;
    USE SIGNAL ;
    SHAPE ABUTMENT ;
    PORT
      LAYER M4 ;
      RECT 0.000 52.056 0.018 52.074 ;
    END
  END rd0_out[289]
  PIN rd0_out[290]
    DIRECTION OUTPUT ;
    USE SIGNAL ;
    SHAPE ABUTMENT ;
    PORT
      LAYER M4 ;
      RECT 0.000 52.236 0.018 52.254 ;
    END
  END rd0_out[290]
  PIN rd0_out[291]
    DIRECTION OUTPUT ;
    USE SIGNAL ;
    SHAPE ABUTMENT ;
    PORT
      LAYER M4 ;
      RECT 0.000 52.416 0.018 52.434 ;
    END
  END rd0_out[291]
  PIN rd0_out[292]
    DIRECTION OUTPUT ;
    USE SIGNAL ;
    SHAPE ABUTMENT ;
    PORT
      LAYER M4 ;
      RECT 0.000 52.596 0.018 52.614 ;
    END
  END rd0_out[292]
  PIN rd0_out[293]
    DIRECTION OUTPUT ;
    USE SIGNAL ;
    SHAPE ABUTMENT ;
    PORT
      LAYER M4 ;
      RECT 0.000 52.776 0.018 52.794 ;
    END
  END rd0_out[293]
  PIN rd0_out[294]
    DIRECTION OUTPUT ;
    USE SIGNAL ;
    SHAPE ABUTMENT ;
    PORT
      LAYER M4 ;
      RECT 0.000 52.956 0.018 52.974 ;
    END
  END rd0_out[294]
  PIN rd0_out[295]
    DIRECTION OUTPUT ;
    USE SIGNAL ;
    SHAPE ABUTMENT ;
    PORT
      LAYER M4 ;
      RECT 0.000 53.136 0.018 53.154 ;
    END
  END rd0_out[295]
  PIN rd0_out[296]
    DIRECTION OUTPUT ;
    USE SIGNAL ;
    SHAPE ABUTMENT ;
    PORT
      LAYER M4 ;
      RECT 0.000 53.316 0.018 53.334 ;
    END
  END rd0_out[296]
  PIN rd0_out[297]
    DIRECTION OUTPUT ;
    USE SIGNAL ;
    SHAPE ABUTMENT ;
    PORT
      LAYER M4 ;
      RECT 0.000 53.496 0.018 53.514 ;
    END
  END rd0_out[297]
  PIN rd0_out[298]
    DIRECTION OUTPUT ;
    USE SIGNAL ;
    SHAPE ABUTMENT ;
    PORT
      LAYER M4 ;
      RECT 0.000 53.676 0.018 53.694 ;
    END
  END rd0_out[298]
  PIN rd0_out[299]
    DIRECTION OUTPUT ;
    USE SIGNAL ;
    SHAPE ABUTMENT ;
    PORT
      LAYER M4 ;
      RECT 0.000 53.856 0.018 53.874 ;
    END
  END rd0_out[299]
  PIN rd0_out[300]
    DIRECTION OUTPUT ;
    USE SIGNAL ;
    SHAPE ABUTMENT ;
    PORT
      LAYER M4 ;
      RECT 0.000 54.036 0.018 54.054 ;
    END
  END rd0_out[300]
  PIN rd0_out[301]
    DIRECTION OUTPUT ;
    USE SIGNAL ;
    SHAPE ABUTMENT ;
    PORT
      LAYER M4 ;
      RECT 0.000 54.216 0.018 54.234 ;
    END
  END rd0_out[301]
  PIN rd0_out[302]
    DIRECTION OUTPUT ;
    USE SIGNAL ;
    SHAPE ABUTMENT ;
    PORT
      LAYER M4 ;
      RECT 0.000 54.396 0.018 54.414 ;
    END
  END rd0_out[302]
  PIN rd0_out[303]
    DIRECTION OUTPUT ;
    USE SIGNAL ;
    SHAPE ABUTMENT ;
    PORT
      LAYER M4 ;
      RECT 0.000 54.576 0.018 54.594 ;
    END
  END rd0_out[303]
  PIN rd0_out[304]
    DIRECTION OUTPUT ;
    USE SIGNAL ;
    SHAPE ABUTMENT ;
    PORT
      LAYER M4 ;
      RECT 0.000 54.756 0.018 54.774 ;
    END
  END rd0_out[304]
  PIN rd0_out[305]
    DIRECTION OUTPUT ;
    USE SIGNAL ;
    SHAPE ABUTMENT ;
    PORT
      LAYER M4 ;
      RECT 0.000 54.936 0.018 54.954 ;
    END
  END rd0_out[305]
  PIN rd0_out[306]
    DIRECTION OUTPUT ;
    USE SIGNAL ;
    SHAPE ABUTMENT ;
    PORT
      LAYER M4 ;
      RECT 0.000 55.116 0.018 55.134 ;
    END
  END rd0_out[306]
  PIN rd0_out[307]
    DIRECTION OUTPUT ;
    USE SIGNAL ;
    SHAPE ABUTMENT ;
    PORT
      LAYER M4 ;
      RECT 0.000 55.296 0.018 55.314 ;
    END
  END rd0_out[307]
  PIN rd0_out[308]
    DIRECTION OUTPUT ;
    USE SIGNAL ;
    SHAPE ABUTMENT ;
    PORT
      LAYER M4 ;
      RECT 0.000 55.476 0.018 55.494 ;
    END
  END rd0_out[308]
  PIN rd0_out[309]
    DIRECTION OUTPUT ;
    USE SIGNAL ;
    SHAPE ABUTMENT ;
    PORT
      LAYER M4 ;
      RECT 0.000 55.656 0.018 55.674 ;
    END
  END rd0_out[309]
  PIN rd0_out[310]
    DIRECTION OUTPUT ;
    USE SIGNAL ;
    SHAPE ABUTMENT ;
    PORT
      LAYER M4 ;
      RECT 0.000 55.836 0.018 55.854 ;
    END
  END rd0_out[310]
  PIN rd0_out[311]
    DIRECTION OUTPUT ;
    USE SIGNAL ;
    SHAPE ABUTMENT ;
    PORT
      LAYER M4 ;
      RECT 0.000 56.016 0.018 56.034 ;
    END
  END rd0_out[311]
  PIN rd0_out[312]
    DIRECTION OUTPUT ;
    USE SIGNAL ;
    SHAPE ABUTMENT ;
    PORT
      LAYER M4 ;
      RECT 0.000 56.196 0.018 56.214 ;
    END
  END rd0_out[312]
  PIN rd0_out[313]
    DIRECTION OUTPUT ;
    USE SIGNAL ;
    SHAPE ABUTMENT ;
    PORT
      LAYER M4 ;
      RECT 0.000 56.376 0.018 56.394 ;
    END
  END rd0_out[313]
  PIN rd0_out[314]
    DIRECTION OUTPUT ;
    USE SIGNAL ;
    SHAPE ABUTMENT ;
    PORT
      LAYER M4 ;
      RECT 0.000 56.556 0.018 56.574 ;
    END
  END rd0_out[314]
  PIN rd0_out[315]
    DIRECTION OUTPUT ;
    USE SIGNAL ;
    SHAPE ABUTMENT ;
    PORT
      LAYER M4 ;
      RECT 0.000 56.736 0.018 56.754 ;
    END
  END rd0_out[315]
  PIN rd0_out[316]
    DIRECTION OUTPUT ;
    USE SIGNAL ;
    SHAPE ABUTMENT ;
    PORT
      LAYER M4 ;
      RECT 0.000 56.916 0.018 56.934 ;
    END
  END rd0_out[316]
  PIN rd0_out[317]
    DIRECTION OUTPUT ;
    USE SIGNAL ;
    SHAPE ABUTMENT ;
    PORT
      LAYER M4 ;
      RECT 0.000 57.096 0.018 57.114 ;
    END
  END rd0_out[317]
  PIN rd0_out[318]
    DIRECTION OUTPUT ;
    USE SIGNAL ;
    SHAPE ABUTMENT ;
    PORT
      LAYER M4 ;
      RECT 0.000 57.276 0.018 57.294 ;
    END
  END rd0_out[318]
  PIN rd0_out[319]
    DIRECTION OUTPUT ;
    USE SIGNAL ;
    SHAPE ABUTMENT ;
    PORT
      LAYER M4 ;
      RECT 0.000 57.456 0.018 57.474 ;
    END
  END rd0_out[319]
  PIN rd0_out[320]
    DIRECTION OUTPUT ;
    USE SIGNAL ;
    SHAPE ABUTMENT ;
    PORT
      LAYER M4 ;
      RECT 0.000 57.636 0.018 57.654 ;
    END
  END rd0_out[320]
  PIN rd0_out[321]
    DIRECTION OUTPUT ;
    USE SIGNAL ;
    SHAPE ABUTMENT ;
    PORT
      LAYER M4 ;
      RECT 0.000 57.816 0.018 57.834 ;
    END
  END rd0_out[321]
  PIN rd0_out[322]
    DIRECTION OUTPUT ;
    USE SIGNAL ;
    SHAPE ABUTMENT ;
    PORT
      LAYER M4 ;
      RECT 0.000 57.996 0.018 58.014 ;
    END
  END rd0_out[322]
  PIN rd0_out[323]
    DIRECTION OUTPUT ;
    USE SIGNAL ;
    SHAPE ABUTMENT ;
    PORT
      LAYER M4 ;
      RECT 0.000 58.176 0.018 58.194 ;
    END
  END rd0_out[323]
  PIN rd0_out[324]
    DIRECTION OUTPUT ;
    USE SIGNAL ;
    SHAPE ABUTMENT ;
    PORT
      LAYER M4 ;
      RECT 0.000 58.356 0.018 58.374 ;
    END
  END rd0_out[324]
  PIN rd0_out[325]
    DIRECTION OUTPUT ;
    USE SIGNAL ;
    SHAPE ABUTMENT ;
    PORT
      LAYER M4 ;
      RECT 0.000 58.536 0.018 58.554 ;
    END
  END rd0_out[325]
  PIN rd0_out[326]
    DIRECTION OUTPUT ;
    USE SIGNAL ;
    SHAPE ABUTMENT ;
    PORT
      LAYER M4 ;
      RECT 0.000 58.716 0.018 58.734 ;
    END
  END rd0_out[326]
  PIN rd0_out[327]
    DIRECTION OUTPUT ;
    USE SIGNAL ;
    SHAPE ABUTMENT ;
    PORT
      LAYER M4 ;
      RECT 0.000 58.896 0.018 58.914 ;
    END
  END rd0_out[327]
  PIN rd0_out[328]
    DIRECTION OUTPUT ;
    USE SIGNAL ;
    SHAPE ABUTMENT ;
    PORT
      LAYER M4 ;
      RECT 0.000 59.076 0.018 59.094 ;
    END
  END rd0_out[328]
  PIN rd0_out[329]
    DIRECTION OUTPUT ;
    USE SIGNAL ;
    SHAPE ABUTMENT ;
    PORT
      LAYER M4 ;
      RECT 0.000 59.256 0.018 59.274 ;
    END
  END rd0_out[329]
  PIN rd0_out[330]
    DIRECTION OUTPUT ;
    USE SIGNAL ;
    SHAPE ABUTMENT ;
    PORT
      LAYER M4 ;
      RECT 0.000 59.436 0.018 59.454 ;
    END
  END rd0_out[330]
  PIN rd0_out[331]
    DIRECTION OUTPUT ;
    USE SIGNAL ;
    SHAPE ABUTMENT ;
    PORT
      LAYER M4 ;
      RECT 0.000 59.616 0.018 59.634 ;
    END
  END rd0_out[331]
  PIN rd0_out[332]
    DIRECTION OUTPUT ;
    USE SIGNAL ;
    SHAPE ABUTMENT ;
    PORT
      LAYER M4 ;
      RECT 0.000 59.796 0.018 59.814 ;
    END
  END rd0_out[332]
  PIN rd0_out[333]
    DIRECTION OUTPUT ;
    USE SIGNAL ;
    SHAPE ABUTMENT ;
    PORT
      LAYER M4 ;
      RECT 0.000 59.976 0.018 59.994 ;
    END
  END rd0_out[333]
  PIN rd0_out[334]
    DIRECTION OUTPUT ;
    USE SIGNAL ;
    SHAPE ABUTMENT ;
    PORT
      LAYER M4 ;
      RECT 0.000 60.156 0.018 60.174 ;
    END
  END rd0_out[334]
  PIN rd0_out[335]
    DIRECTION OUTPUT ;
    USE SIGNAL ;
    SHAPE ABUTMENT ;
    PORT
      LAYER M4 ;
      RECT 0.000 60.336 0.018 60.354 ;
    END
  END rd0_out[335]
  PIN rd0_out[336]
    DIRECTION OUTPUT ;
    USE SIGNAL ;
    SHAPE ABUTMENT ;
    PORT
      LAYER M4 ;
      RECT 0.000 60.516 0.018 60.534 ;
    END
  END rd0_out[336]
  PIN rd0_out[337]
    DIRECTION OUTPUT ;
    USE SIGNAL ;
    SHAPE ABUTMENT ;
    PORT
      LAYER M4 ;
      RECT 0.000 60.696 0.018 60.714 ;
    END
  END rd0_out[337]
  PIN rd0_out[338]
    DIRECTION OUTPUT ;
    USE SIGNAL ;
    SHAPE ABUTMENT ;
    PORT
      LAYER M4 ;
      RECT 0.000 60.876 0.018 60.894 ;
    END
  END rd0_out[338]
  PIN rd0_out[339]
    DIRECTION OUTPUT ;
    USE SIGNAL ;
    SHAPE ABUTMENT ;
    PORT
      LAYER M4 ;
      RECT 0.000 61.056 0.018 61.074 ;
    END
  END rd0_out[339]
  PIN rd0_out[340]
    DIRECTION OUTPUT ;
    USE SIGNAL ;
    SHAPE ABUTMENT ;
    PORT
      LAYER M4 ;
      RECT 0.000 61.236 0.018 61.254 ;
    END
  END rd0_out[340]
  PIN rd0_out[341]
    DIRECTION OUTPUT ;
    USE SIGNAL ;
    SHAPE ABUTMENT ;
    PORT
      LAYER M4 ;
      RECT 0.000 61.416 0.018 61.434 ;
    END
  END rd0_out[341]
  PIN rd0_out[342]
    DIRECTION OUTPUT ;
    USE SIGNAL ;
    SHAPE ABUTMENT ;
    PORT
      LAYER M4 ;
      RECT 0.000 61.596 0.018 61.614 ;
    END
  END rd0_out[342]
  PIN rd0_out[343]
    DIRECTION OUTPUT ;
    USE SIGNAL ;
    SHAPE ABUTMENT ;
    PORT
      LAYER M4 ;
      RECT 0.000 61.776 0.018 61.794 ;
    END
  END rd0_out[343]
  PIN rd0_out[344]
    DIRECTION OUTPUT ;
    USE SIGNAL ;
    SHAPE ABUTMENT ;
    PORT
      LAYER M4 ;
      RECT 0.000 61.956 0.018 61.974 ;
    END
  END rd0_out[344]
  PIN rd0_out[345]
    DIRECTION OUTPUT ;
    USE SIGNAL ;
    SHAPE ABUTMENT ;
    PORT
      LAYER M4 ;
      RECT 0.000 62.136 0.018 62.154 ;
    END
  END rd0_out[345]
  PIN rd0_out[346]
    DIRECTION OUTPUT ;
    USE SIGNAL ;
    SHAPE ABUTMENT ;
    PORT
      LAYER M4 ;
      RECT 0.000 62.316 0.018 62.334 ;
    END
  END rd0_out[346]
  PIN rd0_out[347]
    DIRECTION OUTPUT ;
    USE SIGNAL ;
    SHAPE ABUTMENT ;
    PORT
      LAYER M4 ;
      RECT 0.000 62.496 0.018 62.514 ;
    END
  END rd0_out[347]
  PIN rd0_out[348]
    DIRECTION OUTPUT ;
    USE SIGNAL ;
    SHAPE ABUTMENT ;
    PORT
      LAYER M4 ;
      RECT 0.000 62.676 0.018 62.694 ;
    END
  END rd0_out[348]
  PIN rd0_out[349]
    DIRECTION OUTPUT ;
    USE SIGNAL ;
    SHAPE ABUTMENT ;
    PORT
      LAYER M4 ;
      RECT 0.000 62.856 0.018 62.874 ;
    END
  END rd0_out[349]
  PIN rd0_out[350]
    DIRECTION OUTPUT ;
    USE SIGNAL ;
    SHAPE ABUTMENT ;
    PORT
      LAYER M4 ;
      RECT 0.000 63.036 0.018 63.054 ;
    END
  END rd0_out[350]
  PIN rd0_out[351]
    DIRECTION OUTPUT ;
    USE SIGNAL ;
    SHAPE ABUTMENT ;
    PORT
      LAYER M4 ;
      RECT 0.000 63.216 0.018 63.234 ;
    END
  END rd0_out[351]
  PIN rd0_out[352]
    DIRECTION OUTPUT ;
    USE SIGNAL ;
    SHAPE ABUTMENT ;
    PORT
      LAYER M4 ;
      RECT 0.000 63.396 0.018 63.414 ;
    END
  END rd0_out[352]
  PIN rd0_out[353]
    DIRECTION OUTPUT ;
    USE SIGNAL ;
    SHAPE ABUTMENT ;
    PORT
      LAYER M4 ;
      RECT 0.000 63.576 0.018 63.594 ;
    END
  END rd0_out[353]
  PIN rd0_out[354]
    DIRECTION OUTPUT ;
    USE SIGNAL ;
    SHAPE ABUTMENT ;
    PORT
      LAYER M4 ;
      RECT 0.000 63.756 0.018 63.774 ;
    END
  END rd0_out[354]
  PIN rd0_out[355]
    DIRECTION OUTPUT ;
    USE SIGNAL ;
    SHAPE ABUTMENT ;
    PORT
      LAYER M4 ;
      RECT 0.000 63.936 0.018 63.954 ;
    END
  END rd0_out[355]
  PIN rd0_out[356]
    DIRECTION OUTPUT ;
    USE SIGNAL ;
    SHAPE ABUTMENT ;
    PORT
      LAYER M4 ;
      RECT 0.000 64.116 0.018 64.134 ;
    END
  END rd0_out[356]
  PIN rd0_out[357]
    DIRECTION OUTPUT ;
    USE SIGNAL ;
    SHAPE ABUTMENT ;
    PORT
      LAYER M4 ;
      RECT 0.000 64.296 0.018 64.314 ;
    END
  END rd0_out[357]
  PIN rd0_out[358]
    DIRECTION OUTPUT ;
    USE SIGNAL ;
    SHAPE ABUTMENT ;
    PORT
      LAYER M4 ;
      RECT 0.000 64.476 0.018 64.494 ;
    END
  END rd0_out[358]
  PIN rd0_out[359]
    DIRECTION OUTPUT ;
    USE SIGNAL ;
    SHAPE ABUTMENT ;
    PORT
      LAYER M4 ;
      RECT 0.000 64.656 0.018 64.674 ;
    END
  END rd0_out[359]
  PIN rd0_out[360]
    DIRECTION OUTPUT ;
    USE SIGNAL ;
    SHAPE ABUTMENT ;
    PORT
      LAYER M4 ;
      RECT 0.000 64.836 0.018 64.854 ;
    END
  END rd0_out[360]
  PIN rd0_out[361]
    DIRECTION OUTPUT ;
    USE SIGNAL ;
    SHAPE ABUTMENT ;
    PORT
      LAYER M4 ;
      RECT 0.000 65.016 0.018 65.034 ;
    END
  END rd0_out[361]
  PIN rd0_out[362]
    DIRECTION OUTPUT ;
    USE SIGNAL ;
    SHAPE ABUTMENT ;
    PORT
      LAYER M4 ;
      RECT 0.000 65.196 0.018 65.214 ;
    END
  END rd0_out[362]
  PIN rd0_out[363]
    DIRECTION OUTPUT ;
    USE SIGNAL ;
    SHAPE ABUTMENT ;
    PORT
      LAYER M4 ;
      RECT 0.000 65.376 0.018 65.394 ;
    END
  END rd0_out[363]
  PIN rd0_out[364]
    DIRECTION OUTPUT ;
    USE SIGNAL ;
    SHAPE ABUTMENT ;
    PORT
      LAYER M4 ;
      RECT 0.000 65.556 0.018 65.574 ;
    END
  END rd0_out[364]
  PIN rd0_out[365]
    DIRECTION OUTPUT ;
    USE SIGNAL ;
    SHAPE ABUTMENT ;
    PORT
      LAYER M4 ;
      RECT 0.000 65.736 0.018 65.754 ;
    END
  END rd0_out[365]
  PIN rd0_out[366]
    DIRECTION OUTPUT ;
    USE SIGNAL ;
    SHAPE ABUTMENT ;
    PORT
      LAYER M4 ;
      RECT 0.000 65.916 0.018 65.934 ;
    END
  END rd0_out[366]
  PIN rd0_out[367]
    DIRECTION OUTPUT ;
    USE SIGNAL ;
    SHAPE ABUTMENT ;
    PORT
      LAYER M4 ;
      RECT 0.000 66.096 0.018 66.114 ;
    END
  END rd0_out[367]
  PIN rd0_out[368]
    DIRECTION OUTPUT ;
    USE SIGNAL ;
    SHAPE ABUTMENT ;
    PORT
      LAYER M4 ;
      RECT 0.000 66.276 0.018 66.294 ;
    END
  END rd0_out[368]
  PIN rd0_out[369]
    DIRECTION OUTPUT ;
    USE SIGNAL ;
    SHAPE ABUTMENT ;
    PORT
      LAYER M4 ;
      RECT 0.000 66.456 0.018 66.474 ;
    END
  END rd0_out[369]
  PIN rd0_out[370]
    DIRECTION OUTPUT ;
    USE SIGNAL ;
    SHAPE ABUTMENT ;
    PORT
      LAYER M4 ;
      RECT 0.000 66.636 0.018 66.654 ;
    END
  END rd0_out[370]
  PIN rd0_out[371]
    DIRECTION OUTPUT ;
    USE SIGNAL ;
    SHAPE ABUTMENT ;
    PORT
      LAYER M4 ;
      RECT 0.000 66.816 0.018 66.834 ;
    END
  END rd0_out[371]
  PIN rd0_out[372]
    DIRECTION OUTPUT ;
    USE SIGNAL ;
    SHAPE ABUTMENT ;
    PORT
      LAYER M4 ;
      RECT 0.000 66.996 0.018 67.014 ;
    END
  END rd0_out[372]
  PIN rd0_out[373]
    DIRECTION OUTPUT ;
    USE SIGNAL ;
    SHAPE ABUTMENT ;
    PORT
      LAYER M4 ;
      RECT 0.000 67.176 0.018 67.194 ;
    END
  END rd0_out[373]
  PIN rd0_out[374]
    DIRECTION OUTPUT ;
    USE SIGNAL ;
    SHAPE ABUTMENT ;
    PORT
      LAYER M4 ;
      RECT 0.000 67.356 0.018 67.374 ;
    END
  END rd0_out[374]
  PIN rd0_out[375]
    DIRECTION OUTPUT ;
    USE SIGNAL ;
    SHAPE ABUTMENT ;
    PORT
      LAYER M4 ;
      RECT 0.000 67.536 0.018 67.554 ;
    END
  END rd0_out[375]
  PIN rd0_out[376]
    DIRECTION OUTPUT ;
    USE SIGNAL ;
    SHAPE ABUTMENT ;
    PORT
      LAYER M4 ;
      RECT 0.000 67.716 0.018 67.734 ;
    END
  END rd0_out[376]
  PIN rd0_out[377]
    DIRECTION OUTPUT ;
    USE SIGNAL ;
    SHAPE ABUTMENT ;
    PORT
      LAYER M4 ;
      RECT 0.000 67.896 0.018 67.914 ;
    END
  END rd0_out[377]
  PIN rd0_out[378]
    DIRECTION OUTPUT ;
    USE SIGNAL ;
    SHAPE ABUTMENT ;
    PORT
      LAYER M4 ;
      RECT 0.000 68.076 0.018 68.094 ;
    END
  END rd0_out[378]
  PIN rd0_out[379]
    DIRECTION OUTPUT ;
    USE SIGNAL ;
    SHAPE ABUTMENT ;
    PORT
      LAYER M4 ;
      RECT 0.000 68.256 0.018 68.274 ;
    END
  END rd0_out[379]
  PIN rd0_out[380]
    DIRECTION OUTPUT ;
    USE SIGNAL ;
    SHAPE ABUTMENT ;
    PORT
      LAYER M4 ;
      RECT 0.000 68.436 0.018 68.454 ;
    END
  END rd0_out[380]
  PIN rd0_out[381]
    DIRECTION OUTPUT ;
    USE SIGNAL ;
    SHAPE ABUTMENT ;
    PORT
      LAYER M4 ;
      RECT 0.000 68.616 0.018 68.634 ;
    END
  END rd0_out[381]
  PIN rd0_out[382]
    DIRECTION OUTPUT ;
    USE SIGNAL ;
    SHAPE ABUTMENT ;
    PORT
      LAYER M4 ;
      RECT 0.000 68.796 0.018 68.814 ;
    END
  END rd0_out[382]
  PIN rd0_out[383]
    DIRECTION OUTPUT ;
    USE SIGNAL ;
    SHAPE ABUTMENT ;
    PORT
      LAYER M4 ;
      RECT 0.000 68.976 0.018 68.994 ;
    END
  END rd0_out[383]
  PIN rd0_out[384]
    DIRECTION OUTPUT ;
    USE SIGNAL ;
    SHAPE ABUTMENT ;
    PORT
      LAYER M4 ;
      RECT 0.000 69.156 0.018 69.174 ;
    END
  END rd0_out[384]
  PIN rd0_out[385]
    DIRECTION OUTPUT ;
    USE SIGNAL ;
    SHAPE ABUTMENT ;
    PORT
      LAYER M4 ;
      RECT 0.000 69.336 0.018 69.354 ;
    END
  END rd0_out[385]
  PIN rd0_out[386]
    DIRECTION OUTPUT ;
    USE SIGNAL ;
    SHAPE ABUTMENT ;
    PORT
      LAYER M4 ;
      RECT 0.000 69.516 0.018 69.534 ;
    END
  END rd0_out[386]
  PIN rd0_out[387]
    DIRECTION OUTPUT ;
    USE SIGNAL ;
    SHAPE ABUTMENT ;
    PORT
      LAYER M4 ;
      RECT 0.000 69.696 0.018 69.714 ;
    END
  END rd0_out[387]
  PIN rd0_out[388]
    DIRECTION OUTPUT ;
    USE SIGNAL ;
    SHAPE ABUTMENT ;
    PORT
      LAYER M4 ;
      RECT 0.000 69.876 0.018 69.894 ;
    END
  END rd0_out[388]
  PIN rd0_out[389]
    DIRECTION OUTPUT ;
    USE SIGNAL ;
    SHAPE ABUTMENT ;
    PORT
      LAYER M4 ;
      RECT 0.000 70.056 0.018 70.074 ;
    END
  END rd0_out[389]
  PIN rd0_out[390]
    DIRECTION OUTPUT ;
    USE SIGNAL ;
    SHAPE ABUTMENT ;
    PORT
      LAYER M4 ;
      RECT 0.000 70.236 0.018 70.254 ;
    END
  END rd0_out[390]
  PIN rd0_out[391]
    DIRECTION OUTPUT ;
    USE SIGNAL ;
    SHAPE ABUTMENT ;
    PORT
      LAYER M4 ;
      RECT 0.000 70.416 0.018 70.434 ;
    END
  END rd0_out[391]
  PIN rd0_out[392]
    DIRECTION OUTPUT ;
    USE SIGNAL ;
    SHAPE ABUTMENT ;
    PORT
      LAYER M4 ;
      RECT 0.000 70.596 0.018 70.614 ;
    END
  END rd0_out[392]
  PIN rd0_out[393]
    DIRECTION OUTPUT ;
    USE SIGNAL ;
    SHAPE ABUTMENT ;
    PORT
      LAYER M4 ;
      RECT 0.000 70.776 0.018 70.794 ;
    END
  END rd0_out[393]
  PIN rd0_out[394]
    DIRECTION OUTPUT ;
    USE SIGNAL ;
    SHAPE ABUTMENT ;
    PORT
      LAYER M4 ;
      RECT 0.000 70.956 0.018 70.974 ;
    END
  END rd0_out[394]
  PIN rd0_out[395]
    DIRECTION OUTPUT ;
    USE SIGNAL ;
    SHAPE ABUTMENT ;
    PORT
      LAYER M4 ;
      RECT 0.000 71.136 0.018 71.154 ;
    END
  END rd0_out[395]
  PIN rd0_out[396]
    DIRECTION OUTPUT ;
    USE SIGNAL ;
    SHAPE ABUTMENT ;
    PORT
      LAYER M4 ;
      RECT 0.000 71.316 0.018 71.334 ;
    END
  END rd0_out[396]
  PIN rd0_out[397]
    DIRECTION OUTPUT ;
    USE SIGNAL ;
    SHAPE ABUTMENT ;
    PORT
      LAYER M4 ;
      RECT 0.000 71.496 0.018 71.514 ;
    END
  END rd0_out[397]
  PIN rd0_out[398]
    DIRECTION OUTPUT ;
    USE SIGNAL ;
    SHAPE ABUTMENT ;
    PORT
      LAYER M4 ;
      RECT 0.000 71.676 0.018 71.694 ;
    END
  END rd0_out[398]
  PIN rd0_out[399]
    DIRECTION OUTPUT ;
    USE SIGNAL ;
    SHAPE ABUTMENT ;
    PORT
      LAYER M4 ;
      RECT 0.000 71.856 0.018 71.874 ;
    END
  END rd0_out[399]
  PIN rd0_out[400]
    DIRECTION OUTPUT ;
    USE SIGNAL ;
    SHAPE ABUTMENT ;
    PORT
      LAYER M4 ;
      RECT 0.000 72.036 0.018 72.054 ;
    END
  END rd0_out[400]
  PIN rd0_out[401]
    DIRECTION OUTPUT ;
    USE SIGNAL ;
    SHAPE ABUTMENT ;
    PORT
      LAYER M4 ;
      RECT 0.000 72.216 0.018 72.234 ;
    END
  END rd0_out[401]
  PIN rd0_out[402]
    DIRECTION OUTPUT ;
    USE SIGNAL ;
    SHAPE ABUTMENT ;
    PORT
      LAYER M4 ;
      RECT 0.000 72.396 0.018 72.414 ;
    END
  END rd0_out[402]
  PIN rd0_out[403]
    DIRECTION OUTPUT ;
    USE SIGNAL ;
    SHAPE ABUTMENT ;
    PORT
      LAYER M4 ;
      RECT 0.000 72.576 0.018 72.594 ;
    END
  END rd0_out[403]
  PIN rd0_out[404]
    DIRECTION OUTPUT ;
    USE SIGNAL ;
    SHAPE ABUTMENT ;
    PORT
      LAYER M4 ;
      RECT 0.000 72.756 0.018 72.774 ;
    END
  END rd0_out[404]
  PIN rd0_out[405]
    DIRECTION OUTPUT ;
    USE SIGNAL ;
    SHAPE ABUTMENT ;
    PORT
      LAYER M4 ;
      RECT 0.000 72.936 0.018 72.954 ;
    END
  END rd0_out[405]
  PIN rd0_out[406]
    DIRECTION OUTPUT ;
    USE SIGNAL ;
    SHAPE ABUTMENT ;
    PORT
      LAYER M4 ;
      RECT 0.000 73.116 0.018 73.134 ;
    END
  END rd0_out[406]
  PIN rd0_out[407]
    DIRECTION OUTPUT ;
    USE SIGNAL ;
    SHAPE ABUTMENT ;
    PORT
      LAYER M4 ;
      RECT 0.000 73.296 0.018 73.314 ;
    END
  END rd0_out[407]
  PIN rd0_out[408]
    DIRECTION OUTPUT ;
    USE SIGNAL ;
    SHAPE ABUTMENT ;
    PORT
      LAYER M4 ;
      RECT 0.000 73.476 0.018 73.494 ;
    END
  END rd0_out[408]
  PIN rd0_out[409]
    DIRECTION OUTPUT ;
    USE SIGNAL ;
    SHAPE ABUTMENT ;
    PORT
      LAYER M4 ;
      RECT 0.000 73.656 0.018 73.674 ;
    END
  END rd0_out[409]
  PIN rd0_out[410]
    DIRECTION OUTPUT ;
    USE SIGNAL ;
    SHAPE ABUTMENT ;
    PORT
      LAYER M4 ;
      RECT 0.000 73.836 0.018 73.854 ;
    END
  END rd0_out[410]
  PIN rd0_out[411]
    DIRECTION OUTPUT ;
    USE SIGNAL ;
    SHAPE ABUTMENT ;
    PORT
      LAYER M4 ;
      RECT 0.000 74.016 0.018 74.034 ;
    END
  END rd0_out[411]
  PIN rd0_out[412]
    DIRECTION OUTPUT ;
    USE SIGNAL ;
    SHAPE ABUTMENT ;
    PORT
      LAYER M4 ;
      RECT 0.000 74.196 0.018 74.214 ;
    END
  END rd0_out[412]
  PIN rd0_out[413]
    DIRECTION OUTPUT ;
    USE SIGNAL ;
    SHAPE ABUTMENT ;
    PORT
      LAYER M4 ;
      RECT 0.000 74.376 0.018 74.394 ;
    END
  END rd0_out[413]
  PIN rd0_out[414]
    DIRECTION OUTPUT ;
    USE SIGNAL ;
    SHAPE ABUTMENT ;
    PORT
      LAYER M4 ;
      RECT 0.000 74.556 0.018 74.574 ;
    END
  END rd0_out[414]
  PIN rd0_out[415]
    DIRECTION OUTPUT ;
    USE SIGNAL ;
    SHAPE ABUTMENT ;
    PORT
      LAYER M4 ;
      RECT 0.000 74.736 0.018 74.754 ;
    END
  END rd0_out[415]
  PIN rd0_out[416]
    DIRECTION OUTPUT ;
    USE SIGNAL ;
    SHAPE ABUTMENT ;
    PORT
      LAYER M4 ;
      RECT 0.000 74.916 0.018 74.934 ;
    END
  END rd0_out[416]
  PIN rd0_out[417]
    DIRECTION OUTPUT ;
    USE SIGNAL ;
    SHAPE ABUTMENT ;
    PORT
      LAYER M4 ;
      RECT 0.000 75.096 0.018 75.114 ;
    END
  END rd0_out[417]
  PIN rd0_out[418]
    DIRECTION OUTPUT ;
    USE SIGNAL ;
    SHAPE ABUTMENT ;
    PORT
      LAYER M4 ;
      RECT 0.000 75.276 0.018 75.294 ;
    END
  END rd0_out[418]
  PIN rd0_out[419]
    DIRECTION OUTPUT ;
    USE SIGNAL ;
    SHAPE ABUTMENT ;
    PORT
      LAYER M4 ;
      RECT 0.000 75.456 0.018 75.474 ;
    END
  END rd0_out[419]
  PIN rd0_out[420]
    DIRECTION OUTPUT ;
    USE SIGNAL ;
    SHAPE ABUTMENT ;
    PORT
      LAYER M4 ;
      RECT 0.000 75.636 0.018 75.654 ;
    END
  END rd0_out[420]
  PIN rd0_out[421]
    DIRECTION OUTPUT ;
    USE SIGNAL ;
    SHAPE ABUTMENT ;
    PORT
      LAYER M4 ;
      RECT 0.000 75.816 0.018 75.834 ;
    END
  END rd0_out[421]
  PIN rd0_out[422]
    DIRECTION OUTPUT ;
    USE SIGNAL ;
    SHAPE ABUTMENT ;
    PORT
      LAYER M4 ;
      RECT 0.000 75.996 0.018 76.014 ;
    END
  END rd0_out[422]
  PIN rd0_out[423]
    DIRECTION OUTPUT ;
    USE SIGNAL ;
    SHAPE ABUTMENT ;
    PORT
      LAYER M4 ;
      RECT 0.000 76.176 0.018 76.194 ;
    END
  END rd0_out[423]
  PIN rd0_out[424]
    DIRECTION OUTPUT ;
    USE SIGNAL ;
    SHAPE ABUTMENT ;
    PORT
      LAYER M4 ;
      RECT 0.000 76.356 0.018 76.374 ;
    END
  END rd0_out[424]
  PIN rd0_out[425]
    DIRECTION OUTPUT ;
    USE SIGNAL ;
    SHAPE ABUTMENT ;
    PORT
      LAYER M4 ;
      RECT 0.000 76.536 0.018 76.554 ;
    END
  END rd0_out[425]
  PIN rd0_out[426]
    DIRECTION OUTPUT ;
    USE SIGNAL ;
    SHAPE ABUTMENT ;
    PORT
      LAYER M4 ;
      RECT 0.000 76.716 0.018 76.734 ;
    END
  END rd0_out[426]
  PIN rd0_out[427]
    DIRECTION OUTPUT ;
    USE SIGNAL ;
    SHAPE ABUTMENT ;
    PORT
      LAYER M4 ;
      RECT 0.000 76.896 0.018 76.914 ;
    END
  END rd0_out[427]
  PIN rd0_out[428]
    DIRECTION OUTPUT ;
    USE SIGNAL ;
    SHAPE ABUTMENT ;
    PORT
      LAYER M4 ;
      RECT 0.000 77.076 0.018 77.094 ;
    END
  END rd0_out[428]
  PIN rd0_out[429]
    DIRECTION OUTPUT ;
    USE SIGNAL ;
    SHAPE ABUTMENT ;
    PORT
      LAYER M4 ;
      RECT 0.000 77.256 0.018 77.274 ;
    END
  END rd0_out[429]
  PIN rd0_out[430]
    DIRECTION OUTPUT ;
    USE SIGNAL ;
    SHAPE ABUTMENT ;
    PORT
      LAYER M4 ;
      RECT 0.000 77.436 0.018 77.454 ;
    END
  END rd0_out[430]
  PIN rd0_out[431]
    DIRECTION OUTPUT ;
    USE SIGNAL ;
    SHAPE ABUTMENT ;
    PORT
      LAYER M4 ;
      RECT 0.000 77.616 0.018 77.634 ;
    END
  END rd0_out[431]
  PIN rd0_out[432]
    DIRECTION OUTPUT ;
    USE SIGNAL ;
    SHAPE ABUTMENT ;
    PORT
      LAYER M4 ;
      RECT 0.000 77.796 0.018 77.814 ;
    END
  END rd0_out[432]
  PIN rd0_out[433]
    DIRECTION OUTPUT ;
    USE SIGNAL ;
    SHAPE ABUTMENT ;
    PORT
      LAYER M4 ;
      RECT 0.000 77.976 0.018 77.994 ;
    END
  END rd0_out[433]
  PIN rd0_out[434]
    DIRECTION OUTPUT ;
    USE SIGNAL ;
    SHAPE ABUTMENT ;
    PORT
      LAYER M4 ;
      RECT 0.000 78.156 0.018 78.174 ;
    END
  END rd0_out[434]
  PIN rd0_out[435]
    DIRECTION OUTPUT ;
    USE SIGNAL ;
    SHAPE ABUTMENT ;
    PORT
      LAYER M4 ;
      RECT 0.000 78.336 0.018 78.354 ;
    END
  END rd0_out[435]
  PIN rd0_out[436]
    DIRECTION OUTPUT ;
    USE SIGNAL ;
    SHAPE ABUTMENT ;
    PORT
      LAYER M4 ;
      RECT 0.000 78.516 0.018 78.534 ;
    END
  END rd0_out[436]
  PIN rd0_out[437]
    DIRECTION OUTPUT ;
    USE SIGNAL ;
    SHAPE ABUTMENT ;
    PORT
      LAYER M4 ;
      RECT 0.000 78.696 0.018 78.714 ;
    END
  END rd0_out[437]
  PIN rd0_out[438]
    DIRECTION OUTPUT ;
    USE SIGNAL ;
    SHAPE ABUTMENT ;
    PORT
      LAYER M4 ;
      RECT 0.000 78.876 0.018 78.894 ;
    END
  END rd0_out[438]
  PIN rd0_out[439]
    DIRECTION OUTPUT ;
    USE SIGNAL ;
    SHAPE ABUTMENT ;
    PORT
      LAYER M4 ;
      RECT 0.000 79.056 0.018 79.074 ;
    END
  END rd0_out[439]
  PIN rd0_out[440]
    DIRECTION OUTPUT ;
    USE SIGNAL ;
    SHAPE ABUTMENT ;
    PORT
      LAYER M4 ;
      RECT 0.000 79.236 0.018 79.254 ;
    END
  END rd0_out[440]
  PIN rd0_out[441]
    DIRECTION OUTPUT ;
    USE SIGNAL ;
    SHAPE ABUTMENT ;
    PORT
      LAYER M4 ;
      RECT 0.000 79.416 0.018 79.434 ;
    END
  END rd0_out[441]
  PIN rd0_out[442]
    DIRECTION OUTPUT ;
    USE SIGNAL ;
    SHAPE ABUTMENT ;
    PORT
      LAYER M4 ;
      RECT 0.000 79.596 0.018 79.614 ;
    END
  END rd0_out[442]
  PIN rd0_out[443]
    DIRECTION OUTPUT ;
    USE SIGNAL ;
    SHAPE ABUTMENT ;
    PORT
      LAYER M4 ;
      RECT 0.000 79.776 0.018 79.794 ;
    END
  END rd0_out[443]
  PIN rd0_out[444]
    DIRECTION OUTPUT ;
    USE SIGNAL ;
    SHAPE ABUTMENT ;
    PORT
      LAYER M4 ;
      RECT 0.000 79.956 0.018 79.974 ;
    END
  END rd0_out[444]
  PIN rd0_out[445]
    DIRECTION OUTPUT ;
    USE SIGNAL ;
    SHAPE ABUTMENT ;
    PORT
      LAYER M4 ;
      RECT 0.000 80.136 0.018 80.154 ;
    END
  END rd0_out[445]
  PIN rd0_out[446]
    DIRECTION OUTPUT ;
    USE SIGNAL ;
    SHAPE ABUTMENT ;
    PORT
      LAYER M4 ;
      RECT 0.000 80.316 0.018 80.334 ;
    END
  END rd0_out[446]
  PIN rd0_out[447]
    DIRECTION OUTPUT ;
    USE SIGNAL ;
    SHAPE ABUTMENT ;
    PORT
      LAYER M4 ;
      RECT 0.000 80.496 0.018 80.514 ;
    END
  END rd0_out[447]
  PIN rd0_out[448]
    DIRECTION OUTPUT ;
    USE SIGNAL ;
    SHAPE ABUTMENT ;
    PORT
      LAYER M4 ;
      RECT 0.000 80.676 0.018 80.694 ;
    END
  END rd0_out[448]
  PIN rd0_out[449]
    DIRECTION OUTPUT ;
    USE SIGNAL ;
    SHAPE ABUTMENT ;
    PORT
      LAYER M4 ;
      RECT 0.000 80.856 0.018 80.874 ;
    END
  END rd0_out[449]
  PIN rd0_out[450]
    DIRECTION OUTPUT ;
    USE SIGNAL ;
    SHAPE ABUTMENT ;
    PORT
      LAYER M4 ;
      RECT 0.000 81.036 0.018 81.054 ;
    END
  END rd0_out[450]
  PIN rd0_out[451]
    DIRECTION OUTPUT ;
    USE SIGNAL ;
    SHAPE ABUTMENT ;
    PORT
      LAYER M4 ;
      RECT 0.000 81.216 0.018 81.234 ;
    END
  END rd0_out[451]
  PIN rd0_out[452]
    DIRECTION OUTPUT ;
    USE SIGNAL ;
    SHAPE ABUTMENT ;
    PORT
      LAYER M4 ;
      RECT 0.000 81.396 0.018 81.414 ;
    END
  END rd0_out[452]
  PIN rd0_out[453]
    DIRECTION OUTPUT ;
    USE SIGNAL ;
    SHAPE ABUTMENT ;
    PORT
      LAYER M4 ;
      RECT 0.000 81.576 0.018 81.594 ;
    END
  END rd0_out[453]
  PIN rd0_out[454]
    DIRECTION OUTPUT ;
    USE SIGNAL ;
    SHAPE ABUTMENT ;
    PORT
      LAYER M4 ;
      RECT 0.000 81.756 0.018 81.774 ;
    END
  END rd0_out[454]
  PIN rd0_out[455]
    DIRECTION OUTPUT ;
    USE SIGNAL ;
    SHAPE ABUTMENT ;
    PORT
      LAYER M4 ;
      RECT 0.000 81.936 0.018 81.954 ;
    END
  END rd0_out[455]
  PIN rd0_out[456]
    DIRECTION OUTPUT ;
    USE SIGNAL ;
    SHAPE ABUTMENT ;
    PORT
      LAYER M4 ;
      RECT 0.000 82.116 0.018 82.134 ;
    END
  END rd0_out[456]
  PIN rd0_out[457]
    DIRECTION OUTPUT ;
    USE SIGNAL ;
    SHAPE ABUTMENT ;
    PORT
      LAYER M4 ;
      RECT 0.000 82.296 0.018 82.314 ;
    END
  END rd0_out[457]
  PIN rd0_out[458]
    DIRECTION OUTPUT ;
    USE SIGNAL ;
    SHAPE ABUTMENT ;
    PORT
      LAYER M4 ;
      RECT 0.000 82.476 0.018 82.494 ;
    END
  END rd0_out[458]
  PIN rd0_out[459]
    DIRECTION OUTPUT ;
    USE SIGNAL ;
    SHAPE ABUTMENT ;
    PORT
      LAYER M4 ;
      RECT 0.000 82.656 0.018 82.674 ;
    END
  END rd0_out[459]
  PIN rd0_out[460]
    DIRECTION OUTPUT ;
    USE SIGNAL ;
    SHAPE ABUTMENT ;
    PORT
      LAYER M4 ;
      RECT 0.000 82.836 0.018 82.854 ;
    END
  END rd0_out[460]
  PIN rd0_out[461]
    DIRECTION OUTPUT ;
    USE SIGNAL ;
    SHAPE ABUTMENT ;
    PORT
      LAYER M4 ;
      RECT 0.000 83.016 0.018 83.034 ;
    END
  END rd0_out[461]
  PIN rd0_out[462]
    DIRECTION OUTPUT ;
    USE SIGNAL ;
    SHAPE ABUTMENT ;
    PORT
      LAYER M4 ;
      RECT 0.000 83.196 0.018 83.214 ;
    END
  END rd0_out[462]
  PIN rd0_out[463]
    DIRECTION OUTPUT ;
    USE SIGNAL ;
    SHAPE ABUTMENT ;
    PORT
      LAYER M4 ;
      RECT 0.000 83.376 0.018 83.394 ;
    END
  END rd0_out[463]
  PIN rd0_out[464]
    DIRECTION OUTPUT ;
    USE SIGNAL ;
    SHAPE ABUTMENT ;
    PORT
      LAYER M4 ;
      RECT 0.000 83.556 0.018 83.574 ;
    END
  END rd0_out[464]
  PIN rd0_out[465]
    DIRECTION OUTPUT ;
    USE SIGNAL ;
    SHAPE ABUTMENT ;
    PORT
      LAYER M4 ;
      RECT 0.000 83.736 0.018 83.754 ;
    END
  END rd0_out[465]
  PIN rd0_out[466]
    DIRECTION OUTPUT ;
    USE SIGNAL ;
    SHAPE ABUTMENT ;
    PORT
      LAYER M4 ;
      RECT 0.000 83.916 0.018 83.934 ;
    END
  END rd0_out[466]
  PIN rd0_out[467]
    DIRECTION OUTPUT ;
    USE SIGNAL ;
    SHAPE ABUTMENT ;
    PORT
      LAYER M4 ;
      RECT 0.000 84.096 0.018 84.114 ;
    END
  END rd0_out[467]
  PIN rd0_out[468]
    DIRECTION OUTPUT ;
    USE SIGNAL ;
    SHAPE ABUTMENT ;
    PORT
      LAYER M4 ;
      RECT 0.000 84.276 0.018 84.294 ;
    END
  END rd0_out[468]
  PIN rd0_out[469]
    DIRECTION OUTPUT ;
    USE SIGNAL ;
    SHAPE ABUTMENT ;
    PORT
      LAYER M4 ;
      RECT 0.000 84.456 0.018 84.474 ;
    END
  END rd0_out[469]
  PIN rd0_out[470]
    DIRECTION OUTPUT ;
    USE SIGNAL ;
    SHAPE ABUTMENT ;
    PORT
      LAYER M4 ;
      RECT 0.000 84.636 0.018 84.654 ;
    END
  END rd0_out[470]
  PIN rd0_out[471]
    DIRECTION OUTPUT ;
    USE SIGNAL ;
    SHAPE ABUTMENT ;
    PORT
      LAYER M4 ;
      RECT 0.000 84.816 0.018 84.834 ;
    END
  END rd0_out[471]
  PIN rd0_out[472]
    DIRECTION OUTPUT ;
    USE SIGNAL ;
    SHAPE ABUTMENT ;
    PORT
      LAYER M4 ;
      RECT 0.000 84.996 0.018 85.014 ;
    END
  END rd0_out[472]
  PIN rd0_out[473]
    DIRECTION OUTPUT ;
    USE SIGNAL ;
    SHAPE ABUTMENT ;
    PORT
      LAYER M4 ;
      RECT 0.000 85.176 0.018 85.194 ;
    END
  END rd0_out[473]
  PIN rd0_out[474]
    DIRECTION OUTPUT ;
    USE SIGNAL ;
    SHAPE ABUTMENT ;
    PORT
      LAYER M4 ;
      RECT 0.000 85.356 0.018 85.374 ;
    END
  END rd0_out[474]
  PIN rd0_out[475]
    DIRECTION OUTPUT ;
    USE SIGNAL ;
    SHAPE ABUTMENT ;
    PORT
      LAYER M4 ;
      RECT 0.000 85.536 0.018 85.554 ;
    END
  END rd0_out[475]
  PIN rd0_out[476]
    DIRECTION OUTPUT ;
    USE SIGNAL ;
    SHAPE ABUTMENT ;
    PORT
      LAYER M4 ;
      RECT 0.000 85.716 0.018 85.734 ;
    END
  END rd0_out[476]
  PIN rd0_out[477]
    DIRECTION OUTPUT ;
    USE SIGNAL ;
    SHAPE ABUTMENT ;
    PORT
      LAYER M4 ;
      RECT 0.000 85.896 0.018 85.914 ;
    END
  END rd0_out[477]
  PIN rd0_out[478]
    DIRECTION OUTPUT ;
    USE SIGNAL ;
    SHAPE ABUTMENT ;
    PORT
      LAYER M4 ;
      RECT 0.000 86.076 0.018 86.094 ;
    END
  END rd0_out[478]
  PIN rd0_out[479]
    DIRECTION OUTPUT ;
    USE SIGNAL ;
    SHAPE ABUTMENT ;
    PORT
      LAYER M4 ;
      RECT 0.000 86.256 0.018 86.274 ;
    END
  END rd0_out[479]
  PIN rd0_out[480]
    DIRECTION OUTPUT ;
    USE SIGNAL ;
    SHAPE ABUTMENT ;
    PORT
      LAYER M4 ;
      RECT 0.000 86.436 0.018 86.454 ;
    END
  END rd0_out[480]
  PIN rd0_out[481]
    DIRECTION OUTPUT ;
    USE SIGNAL ;
    SHAPE ABUTMENT ;
    PORT
      LAYER M4 ;
      RECT 0.000 86.616 0.018 86.634 ;
    END
  END rd0_out[481]
  PIN rd0_out[482]
    DIRECTION OUTPUT ;
    USE SIGNAL ;
    SHAPE ABUTMENT ;
    PORT
      LAYER M4 ;
      RECT 0.000 86.796 0.018 86.814 ;
    END
  END rd0_out[482]
  PIN rd0_out[483]
    DIRECTION OUTPUT ;
    USE SIGNAL ;
    SHAPE ABUTMENT ;
    PORT
      LAYER M4 ;
      RECT 0.000 86.976 0.018 86.994 ;
    END
  END rd0_out[483]
  PIN rd0_out[484]
    DIRECTION OUTPUT ;
    USE SIGNAL ;
    SHAPE ABUTMENT ;
    PORT
      LAYER M4 ;
      RECT 0.000 87.156 0.018 87.174 ;
    END
  END rd0_out[484]
  PIN rd0_out[485]
    DIRECTION OUTPUT ;
    USE SIGNAL ;
    SHAPE ABUTMENT ;
    PORT
      LAYER M4 ;
      RECT 0.000 87.336 0.018 87.354 ;
    END
  END rd0_out[485]
  PIN rd0_out[486]
    DIRECTION OUTPUT ;
    USE SIGNAL ;
    SHAPE ABUTMENT ;
    PORT
      LAYER M4 ;
      RECT 0.000 87.516 0.018 87.534 ;
    END
  END rd0_out[486]
  PIN rd0_out[487]
    DIRECTION OUTPUT ;
    USE SIGNAL ;
    SHAPE ABUTMENT ;
    PORT
      LAYER M4 ;
      RECT 0.000 87.696 0.018 87.714 ;
    END
  END rd0_out[487]
  PIN rd0_out[488]
    DIRECTION OUTPUT ;
    USE SIGNAL ;
    SHAPE ABUTMENT ;
    PORT
      LAYER M4 ;
      RECT 0.000 87.876 0.018 87.894 ;
    END
  END rd0_out[488]
  PIN rd0_out[489]
    DIRECTION OUTPUT ;
    USE SIGNAL ;
    SHAPE ABUTMENT ;
    PORT
      LAYER M4 ;
      RECT 0.000 88.056 0.018 88.074 ;
    END
  END rd0_out[489]
  PIN rd0_out[490]
    DIRECTION OUTPUT ;
    USE SIGNAL ;
    SHAPE ABUTMENT ;
    PORT
      LAYER M4 ;
      RECT 0.000 88.236 0.018 88.254 ;
    END
  END rd0_out[490]
  PIN rd0_out[491]
    DIRECTION OUTPUT ;
    USE SIGNAL ;
    SHAPE ABUTMENT ;
    PORT
      LAYER M4 ;
      RECT 0.000 88.416 0.018 88.434 ;
    END
  END rd0_out[491]
  PIN rd0_out[492]
    DIRECTION OUTPUT ;
    USE SIGNAL ;
    SHAPE ABUTMENT ;
    PORT
      LAYER M4 ;
      RECT 0.000 88.596 0.018 88.614 ;
    END
  END rd0_out[492]
  PIN rd0_out[493]
    DIRECTION OUTPUT ;
    USE SIGNAL ;
    SHAPE ABUTMENT ;
    PORT
      LAYER M4 ;
      RECT 0.000 88.776 0.018 88.794 ;
    END
  END rd0_out[493]
  PIN rd0_out[494]
    DIRECTION OUTPUT ;
    USE SIGNAL ;
    SHAPE ABUTMENT ;
    PORT
      LAYER M4 ;
      RECT 0.000 88.956 0.018 88.974 ;
    END
  END rd0_out[494]
  PIN rd0_out[495]
    DIRECTION OUTPUT ;
    USE SIGNAL ;
    SHAPE ABUTMENT ;
    PORT
      LAYER M4 ;
      RECT 0.000 89.136 0.018 89.154 ;
    END
  END rd0_out[495]
  PIN rd0_out[496]
    DIRECTION OUTPUT ;
    USE SIGNAL ;
    SHAPE ABUTMENT ;
    PORT
      LAYER M4 ;
      RECT 0.000 89.316 0.018 89.334 ;
    END
  END rd0_out[496]
  PIN rd0_out[497]
    DIRECTION OUTPUT ;
    USE SIGNAL ;
    SHAPE ABUTMENT ;
    PORT
      LAYER M4 ;
      RECT 0.000 89.496 0.018 89.514 ;
    END
  END rd0_out[497]
  PIN rd0_out[498]
    DIRECTION OUTPUT ;
    USE SIGNAL ;
    SHAPE ABUTMENT ;
    PORT
      LAYER M4 ;
      RECT 0.000 89.676 0.018 89.694 ;
    END
  END rd0_out[498]
  PIN rd0_out[499]
    DIRECTION OUTPUT ;
    USE SIGNAL ;
    SHAPE ABUTMENT ;
    PORT
      LAYER M4 ;
      RECT 0.000 89.856 0.018 89.874 ;
    END
  END rd0_out[499]
  PIN rd0_out[500]
    DIRECTION OUTPUT ;
    USE SIGNAL ;
    SHAPE ABUTMENT ;
    PORT
      LAYER M4 ;
      RECT 0.000 90.036 0.018 90.054 ;
    END
  END rd0_out[500]
  PIN rd0_out[501]
    DIRECTION OUTPUT ;
    USE SIGNAL ;
    SHAPE ABUTMENT ;
    PORT
      LAYER M4 ;
      RECT 0.000 90.216 0.018 90.234 ;
    END
  END rd0_out[501]
  PIN rd0_out[502]
    DIRECTION OUTPUT ;
    USE SIGNAL ;
    SHAPE ABUTMENT ;
    PORT
      LAYER M4 ;
      RECT 0.000 90.396 0.018 90.414 ;
    END
  END rd0_out[502]
  PIN rd0_out[503]
    DIRECTION OUTPUT ;
    USE SIGNAL ;
    SHAPE ABUTMENT ;
    PORT
      LAYER M4 ;
      RECT 0.000 90.576 0.018 90.594 ;
    END
  END rd0_out[503]
  PIN rd0_out[504]
    DIRECTION OUTPUT ;
    USE SIGNAL ;
    SHAPE ABUTMENT ;
    PORT
      LAYER M4 ;
      RECT 0.000 90.756 0.018 90.774 ;
    END
  END rd0_out[504]
  PIN rd0_out[505]
    DIRECTION OUTPUT ;
    USE SIGNAL ;
    SHAPE ABUTMENT ;
    PORT
      LAYER M4 ;
      RECT 0.000 90.936 0.018 90.954 ;
    END
  END rd0_out[505]
  PIN rd0_out[506]
    DIRECTION OUTPUT ;
    USE SIGNAL ;
    SHAPE ABUTMENT ;
    PORT
      LAYER M4 ;
      RECT 0.000 91.116 0.018 91.134 ;
    END
  END rd0_out[506]
  PIN rd0_out[507]
    DIRECTION OUTPUT ;
    USE SIGNAL ;
    SHAPE ABUTMENT ;
    PORT
      LAYER M4 ;
      RECT 0.000 91.296 0.018 91.314 ;
    END
  END rd0_out[507]
  PIN rd0_out[508]
    DIRECTION OUTPUT ;
    USE SIGNAL ;
    SHAPE ABUTMENT ;
    PORT
      LAYER M4 ;
      RECT 0.000 91.476 0.018 91.494 ;
    END
  END rd0_out[508]
  PIN rd0_out[509]
    DIRECTION OUTPUT ;
    USE SIGNAL ;
    SHAPE ABUTMENT ;
    PORT
      LAYER M4 ;
      RECT 0.000 91.656 0.018 91.674 ;
    END
  END rd0_out[509]
  PIN rd0_out[510]
    DIRECTION OUTPUT ;
    USE SIGNAL ;
    SHAPE ABUTMENT ;
    PORT
      LAYER M4 ;
      RECT 0.000 91.836 0.018 91.854 ;
    END
  END rd0_out[510]
  PIN rd0_out[511]
    DIRECTION OUTPUT ;
    USE SIGNAL ;
    SHAPE ABUTMENT ;
    PORT
      LAYER M4 ;
      RECT 0.000 92.016 0.018 92.034 ;
    END
  END rd0_out[511]
  PIN rd1_out[0]
    DIRECTION OUTPUT ;
    USE SIGNAL ;
    SHAPE ABUTMENT ;
    PORT
      LAYER M4 ;
      RECT 0.000 92.196 0.018 92.214 ;
    END
  END rd1_out[0]
  PIN rd1_out[1]
    DIRECTION OUTPUT ;
    USE SIGNAL ;
    SHAPE ABUTMENT ;
    PORT
      LAYER M4 ;
      RECT 0.000 92.376 0.018 92.394 ;
    END
  END rd1_out[1]
  PIN rd1_out[2]
    DIRECTION OUTPUT ;
    USE SIGNAL ;
    SHAPE ABUTMENT ;
    PORT
      LAYER M4 ;
      RECT 0.000 92.556 0.018 92.574 ;
    END
  END rd1_out[2]
  PIN rd1_out[3]
    DIRECTION OUTPUT ;
    USE SIGNAL ;
    SHAPE ABUTMENT ;
    PORT
      LAYER M4 ;
      RECT 0.000 92.736 0.018 92.754 ;
    END
  END rd1_out[3]
  PIN rd1_out[4]
    DIRECTION OUTPUT ;
    USE SIGNAL ;
    SHAPE ABUTMENT ;
    PORT
      LAYER M4 ;
      RECT 0.000 92.916 0.018 92.934 ;
    END
  END rd1_out[4]
  PIN rd1_out[5]
    DIRECTION OUTPUT ;
    USE SIGNAL ;
    SHAPE ABUTMENT ;
    PORT
      LAYER M4 ;
      RECT 0.000 93.096 0.018 93.114 ;
    END
  END rd1_out[5]
  PIN rd1_out[6]
    DIRECTION OUTPUT ;
    USE SIGNAL ;
    SHAPE ABUTMENT ;
    PORT
      LAYER M4 ;
      RECT 0.000 93.276 0.018 93.294 ;
    END
  END rd1_out[6]
  PIN rd1_out[7]
    DIRECTION OUTPUT ;
    USE SIGNAL ;
    SHAPE ABUTMENT ;
    PORT
      LAYER M4 ;
      RECT 0.000 93.456 0.018 93.474 ;
    END
  END rd1_out[7]
  PIN rd1_out[8]
    DIRECTION OUTPUT ;
    USE SIGNAL ;
    SHAPE ABUTMENT ;
    PORT
      LAYER M4 ;
      RECT 0.000 93.636 0.018 93.654 ;
    END
  END rd1_out[8]
  PIN rd1_out[9]
    DIRECTION OUTPUT ;
    USE SIGNAL ;
    SHAPE ABUTMENT ;
    PORT
      LAYER M4 ;
      RECT 0.000 93.816 0.018 93.834 ;
    END
  END rd1_out[9]
  PIN rd1_out[10]
    DIRECTION OUTPUT ;
    USE SIGNAL ;
    SHAPE ABUTMENT ;
    PORT
      LAYER M4 ;
      RECT 0.000 93.996 0.018 94.014 ;
    END
  END rd1_out[10]
  PIN rd1_out[11]
    DIRECTION OUTPUT ;
    USE SIGNAL ;
    SHAPE ABUTMENT ;
    PORT
      LAYER M4 ;
      RECT 0.000 94.176 0.018 94.194 ;
    END
  END rd1_out[11]
  PIN rd1_out[12]
    DIRECTION OUTPUT ;
    USE SIGNAL ;
    SHAPE ABUTMENT ;
    PORT
      LAYER M4 ;
      RECT 0.000 94.356 0.018 94.374 ;
    END
  END rd1_out[12]
  PIN rd1_out[13]
    DIRECTION OUTPUT ;
    USE SIGNAL ;
    SHAPE ABUTMENT ;
    PORT
      LAYER M4 ;
      RECT 0.000 94.536 0.018 94.554 ;
    END
  END rd1_out[13]
  PIN rd1_out[14]
    DIRECTION OUTPUT ;
    USE SIGNAL ;
    SHAPE ABUTMENT ;
    PORT
      LAYER M4 ;
      RECT 0.000 94.716 0.018 94.734 ;
    END
  END rd1_out[14]
  PIN rd1_out[15]
    DIRECTION OUTPUT ;
    USE SIGNAL ;
    SHAPE ABUTMENT ;
    PORT
      LAYER M4 ;
      RECT 0.000 94.896 0.018 94.914 ;
    END
  END rd1_out[15]
  PIN rd1_out[16]
    DIRECTION OUTPUT ;
    USE SIGNAL ;
    SHAPE ABUTMENT ;
    PORT
      LAYER M4 ;
      RECT 0.000 95.076 0.018 95.094 ;
    END
  END rd1_out[16]
  PIN rd1_out[17]
    DIRECTION OUTPUT ;
    USE SIGNAL ;
    SHAPE ABUTMENT ;
    PORT
      LAYER M4 ;
      RECT 0.000 95.256 0.018 95.274 ;
    END
  END rd1_out[17]
  PIN rd1_out[18]
    DIRECTION OUTPUT ;
    USE SIGNAL ;
    SHAPE ABUTMENT ;
    PORT
      LAYER M4 ;
      RECT 0.000 95.436 0.018 95.454 ;
    END
  END rd1_out[18]
  PIN rd1_out[19]
    DIRECTION OUTPUT ;
    USE SIGNAL ;
    SHAPE ABUTMENT ;
    PORT
      LAYER M4 ;
      RECT 0.000 95.616 0.018 95.634 ;
    END
  END rd1_out[19]
  PIN rd1_out[20]
    DIRECTION OUTPUT ;
    USE SIGNAL ;
    SHAPE ABUTMENT ;
    PORT
      LAYER M4 ;
      RECT 0.000 95.796 0.018 95.814 ;
    END
  END rd1_out[20]
  PIN rd1_out[21]
    DIRECTION OUTPUT ;
    USE SIGNAL ;
    SHAPE ABUTMENT ;
    PORT
      LAYER M4 ;
      RECT 0.000 95.976 0.018 95.994 ;
    END
  END rd1_out[21]
  PIN rd1_out[22]
    DIRECTION OUTPUT ;
    USE SIGNAL ;
    SHAPE ABUTMENT ;
    PORT
      LAYER M4 ;
      RECT 0.000 96.156 0.018 96.174 ;
    END
  END rd1_out[22]
  PIN rd1_out[23]
    DIRECTION OUTPUT ;
    USE SIGNAL ;
    SHAPE ABUTMENT ;
    PORT
      LAYER M4 ;
      RECT 0.000 96.336 0.018 96.354 ;
    END
  END rd1_out[23]
  PIN rd1_out[24]
    DIRECTION OUTPUT ;
    USE SIGNAL ;
    SHAPE ABUTMENT ;
    PORT
      LAYER M4 ;
      RECT 0.000 96.516 0.018 96.534 ;
    END
  END rd1_out[24]
  PIN rd1_out[25]
    DIRECTION OUTPUT ;
    USE SIGNAL ;
    SHAPE ABUTMENT ;
    PORT
      LAYER M4 ;
      RECT 0.000 96.696 0.018 96.714 ;
    END
  END rd1_out[25]
  PIN rd1_out[26]
    DIRECTION OUTPUT ;
    USE SIGNAL ;
    SHAPE ABUTMENT ;
    PORT
      LAYER M4 ;
      RECT 0.000 96.876 0.018 96.894 ;
    END
  END rd1_out[26]
  PIN rd1_out[27]
    DIRECTION OUTPUT ;
    USE SIGNAL ;
    SHAPE ABUTMENT ;
    PORT
      LAYER M4 ;
      RECT 0.000 97.056 0.018 97.074 ;
    END
  END rd1_out[27]
  PIN rd1_out[28]
    DIRECTION OUTPUT ;
    USE SIGNAL ;
    SHAPE ABUTMENT ;
    PORT
      LAYER M4 ;
      RECT 0.000 97.236 0.018 97.254 ;
    END
  END rd1_out[28]
  PIN rd1_out[29]
    DIRECTION OUTPUT ;
    USE SIGNAL ;
    SHAPE ABUTMENT ;
    PORT
      LAYER M4 ;
      RECT 0.000 97.416 0.018 97.434 ;
    END
  END rd1_out[29]
  PIN rd1_out[30]
    DIRECTION OUTPUT ;
    USE SIGNAL ;
    SHAPE ABUTMENT ;
    PORT
      LAYER M4 ;
      RECT 0.000 97.596 0.018 97.614 ;
    END
  END rd1_out[30]
  PIN rd1_out[31]
    DIRECTION OUTPUT ;
    USE SIGNAL ;
    SHAPE ABUTMENT ;
    PORT
      LAYER M4 ;
      RECT 0.000 97.776 0.018 97.794 ;
    END
  END rd1_out[31]
  PIN rd1_out[32]
    DIRECTION OUTPUT ;
    USE SIGNAL ;
    SHAPE ABUTMENT ;
    PORT
      LAYER M4 ;
      RECT 0.000 97.956 0.018 97.974 ;
    END
  END rd1_out[32]
  PIN rd1_out[33]
    DIRECTION OUTPUT ;
    USE SIGNAL ;
    SHAPE ABUTMENT ;
    PORT
      LAYER M4 ;
      RECT 0.000 98.136 0.018 98.154 ;
    END
  END rd1_out[33]
  PIN rd1_out[34]
    DIRECTION OUTPUT ;
    USE SIGNAL ;
    SHAPE ABUTMENT ;
    PORT
      LAYER M4 ;
      RECT 0.000 98.316 0.018 98.334 ;
    END
  END rd1_out[34]
  PIN rd1_out[35]
    DIRECTION OUTPUT ;
    USE SIGNAL ;
    SHAPE ABUTMENT ;
    PORT
      LAYER M4 ;
      RECT 0.000 98.496 0.018 98.514 ;
    END
  END rd1_out[35]
  PIN rd1_out[36]
    DIRECTION OUTPUT ;
    USE SIGNAL ;
    SHAPE ABUTMENT ;
    PORT
      LAYER M4 ;
      RECT 0.000 98.676 0.018 98.694 ;
    END
  END rd1_out[36]
  PIN rd1_out[37]
    DIRECTION OUTPUT ;
    USE SIGNAL ;
    SHAPE ABUTMENT ;
    PORT
      LAYER M4 ;
      RECT 0.000 98.856 0.018 98.874 ;
    END
  END rd1_out[37]
  PIN rd1_out[38]
    DIRECTION OUTPUT ;
    USE SIGNAL ;
    SHAPE ABUTMENT ;
    PORT
      LAYER M4 ;
      RECT 0.000 99.036 0.018 99.054 ;
    END
  END rd1_out[38]
  PIN rd1_out[39]
    DIRECTION OUTPUT ;
    USE SIGNAL ;
    SHAPE ABUTMENT ;
    PORT
      LAYER M4 ;
      RECT 0.000 99.216 0.018 99.234 ;
    END
  END rd1_out[39]
  PIN rd1_out[40]
    DIRECTION OUTPUT ;
    USE SIGNAL ;
    SHAPE ABUTMENT ;
    PORT
      LAYER M4 ;
      RECT 0.000 99.396 0.018 99.414 ;
    END
  END rd1_out[40]
  PIN rd1_out[41]
    DIRECTION OUTPUT ;
    USE SIGNAL ;
    SHAPE ABUTMENT ;
    PORT
      LAYER M4 ;
      RECT 0.000 99.576 0.018 99.594 ;
    END
  END rd1_out[41]
  PIN rd1_out[42]
    DIRECTION OUTPUT ;
    USE SIGNAL ;
    SHAPE ABUTMENT ;
    PORT
      LAYER M4 ;
      RECT 0.000 99.756 0.018 99.774 ;
    END
  END rd1_out[42]
  PIN rd1_out[43]
    DIRECTION OUTPUT ;
    USE SIGNAL ;
    SHAPE ABUTMENT ;
    PORT
      LAYER M4 ;
      RECT 0.000 99.936 0.018 99.954 ;
    END
  END rd1_out[43]
  PIN rd1_out[44]
    DIRECTION OUTPUT ;
    USE SIGNAL ;
    SHAPE ABUTMENT ;
    PORT
      LAYER M4 ;
      RECT 0.000 100.116 0.018 100.134 ;
    END
  END rd1_out[44]
  PIN rd1_out[45]
    DIRECTION OUTPUT ;
    USE SIGNAL ;
    SHAPE ABUTMENT ;
    PORT
      LAYER M4 ;
      RECT 0.000 100.296 0.018 100.314 ;
    END
  END rd1_out[45]
  PIN rd1_out[46]
    DIRECTION OUTPUT ;
    USE SIGNAL ;
    SHAPE ABUTMENT ;
    PORT
      LAYER M4 ;
      RECT 0.000 100.476 0.018 100.494 ;
    END
  END rd1_out[46]
  PIN rd1_out[47]
    DIRECTION OUTPUT ;
    USE SIGNAL ;
    SHAPE ABUTMENT ;
    PORT
      LAYER M4 ;
      RECT 0.000 100.656 0.018 100.674 ;
    END
  END rd1_out[47]
  PIN rd1_out[48]
    DIRECTION OUTPUT ;
    USE SIGNAL ;
    SHAPE ABUTMENT ;
    PORT
      LAYER M4 ;
      RECT 0.000 100.836 0.018 100.854 ;
    END
  END rd1_out[48]
  PIN rd1_out[49]
    DIRECTION OUTPUT ;
    USE SIGNAL ;
    SHAPE ABUTMENT ;
    PORT
      LAYER M4 ;
      RECT 0.000 101.016 0.018 101.034 ;
    END
  END rd1_out[49]
  PIN rd1_out[50]
    DIRECTION OUTPUT ;
    USE SIGNAL ;
    SHAPE ABUTMENT ;
    PORT
      LAYER M4 ;
      RECT 0.000 101.196 0.018 101.214 ;
    END
  END rd1_out[50]
  PIN rd1_out[51]
    DIRECTION OUTPUT ;
    USE SIGNAL ;
    SHAPE ABUTMENT ;
    PORT
      LAYER M4 ;
      RECT 0.000 101.376 0.018 101.394 ;
    END
  END rd1_out[51]
  PIN rd1_out[52]
    DIRECTION OUTPUT ;
    USE SIGNAL ;
    SHAPE ABUTMENT ;
    PORT
      LAYER M4 ;
      RECT 0.000 101.556 0.018 101.574 ;
    END
  END rd1_out[52]
  PIN rd1_out[53]
    DIRECTION OUTPUT ;
    USE SIGNAL ;
    SHAPE ABUTMENT ;
    PORT
      LAYER M4 ;
      RECT 0.000 101.736 0.018 101.754 ;
    END
  END rd1_out[53]
  PIN rd1_out[54]
    DIRECTION OUTPUT ;
    USE SIGNAL ;
    SHAPE ABUTMENT ;
    PORT
      LAYER M4 ;
      RECT 0.000 101.916 0.018 101.934 ;
    END
  END rd1_out[54]
  PIN rd1_out[55]
    DIRECTION OUTPUT ;
    USE SIGNAL ;
    SHAPE ABUTMENT ;
    PORT
      LAYER M4 ;
      RECT 0.000 102.096 0.018 102.114 ;
    END
  END rd1_out[55]
  PIN rd1_out[56]
    DIRECTION OUTPUT ;
    USE SIGNAL ;
    SHAPE ABUTMENT ;
    PORT
      LAYER M4 ;
      RECT 0.000 102.276 0.018 102.294 ;
    END
  END rd1_out[56]
  PIN rd1_out[57]
    DIRECTION OUTPUT ;
    USE SIGNAL ;
    SHAPE ABUTMENT ;
    PORT
      LAYER M4 ;
      RECT 0.000 102.456 0.018 102.474 ;
    END
  END rd1_out[57]
  PIN rd1_out[58]
    DIRECTION OUTPUT ;
    USE SIGNAL ;
    SHAPE ABUTMENT ;
    PORT
      LAYER M4 ;
      RECT 0.000 102.636 0.018 102.654 ;
    END
  END rd1_out[58]
  PIN rd1_out[59]
    DIRECTION OUTPUT ;
    USE SIGNAL ;
    SHAPE ABUTMENT ;
    PORT
      LAYER M4 ;
      RECT 0.000 102.816 0.018 102.834 ;
    END
  END rd1_out[59]
  PIN rd1_out[60]
    DIRECTION OUTPUT ;
    USE SIGNAL ;
    SHAPE ABUTMENT ;
    PORT
      LAYER M4 ;
      RECT 0.000 102.996 0.018 103.014 ;
    END
  END rd1_out[60]
  PIN rd1_out[61]
    DIRECTION OUTPUT ;
    USE SIGNAL ;
    SHAPE ABUTMENT ;
    PORT
      LAYER M4 ;
      RECT 0.000 103.176 0.018 103.194 ;
    END
  END rd1_out[61]
  PIN rd1_out[62]
    DIRECTION OUTPUT ;
    USE SIGNAL ;
    SHAPE ABUTMENT ;
    PORT
      LAYER M4 ;
      RECT 0.000 103.356 0.018 103.374 ;
    END
  END rd1_out[62]
  PIN rd1_out[63]
    DIRECTION OUTPUT ;
    USE SIGNAL ;
    SHAPE ABUTMENT ;
    PORT
      LAYER M4 ;
      RECT 0.000 103.536 0.018 103.554 ;
    END
  END rd1_out[63]
  PIN rd1_out[64]
    DIRECTION OUTPUT ;
    USE SIGNAL ;
    SHAPE ABUTMENT ;
    PORT
      LAYER M4 ;
      RECT 0.000 103.716 0.018 103.734 ;
    END
  END rd1_out[64]
  PIN rd1_out[65]
    DIRECTION OUTPUT ;
    USE SIGNAL ;
    SHAPE ABUTMENT ;
    PORT
      LAYER M4 ;
      RECT 0.000 103.896 0.018 103.914 ;
    END
  END rd1_out[65]
  PIN rd1_out[66]
    DIRECTION OUTPUT ;
    USE SIGNAL ;
    SHAPE ABUTMENT ;
    PORT
      LAYER M4 ;
      RECT 0.000 104.076 0.018 104.094 ;
    END
  END rd1_out[66]
  PIN rd1_out[67]
    DIRECTION OUTPUT ;
    USE SIGNAL ;
    SHAPE ABUTMENT ;
    PORT
      LAYER M4 ;
      RECT 0.000 104.256 0.018 104.274 ;
    END
  END rd1_out[67]
  PIN rd1_out[68]
    DIRECTION OUTPUT ;
    USE SIGNAL ;
    SHAPE ABUTMENT ;
    PORT
      LAYER M4 ;
      RECT 0.000 104.436 0.018 104.454 ;
    END
  END rd1_out[68]
  PIN rd1_out[69]
    DIRECTION OUTPUT ;
    USE SIGNAL ;
    SHAPE ABUTMENT ;
    PORT
      LAYER M4 ;
      RECT 0.000 104.616 0.018 104.634 ;
    END
  END rd1_out[69]
  PIN rd1_out[70]
    DIRECTION OUTPUT ;
    USE SIGNAL ;
    SHAPE ABUTMENT ;
    PORT
      LAYER M4 ;
      RECT 0.000 104.796 0.018 104.814 ;
    END
  END rd1_out[70]
  PIN rd1_out[71]
    DIRECTION OUTPUT ;
    USE SIGNAL ;
    SHAPE ABUTMENT ;
    PORT
      LAYER M4 ;
      RECT 0.000 104.976 0.018 104.994 ;
    END
  END rd1_out[71]
  PIN rd1_out[72]
    DIRECTION OUTPUT ;
    USE SIGNAL ;
    SHAPE ABUTMENT ;
    PORT
      LAYER M4 ;
      RECT 0.000 105.156 0.018 105.174 ;
    END
  END rd1_out[72]
  PIN rd1_out[73]
    DIRECTION OUTPUT ;
    USE SIGNAL ;
    SHAPE ABUTMENT ;
    PORT
      LAYER M4 ;
      RECT 0.000 105.336 0.018 105.354 ;
    END
  END rd1_out[73]
  PIN rd1_out[74]
    DIRECTION OUTPUT ;
    USE SIGNAL ;
    SHAPE ABUTMENT ;
    PORT
      LAYER M4 ;
      RECT 0.000 105.516 0.018 105.534 ;
    END
  END rd1_out[74]
  PIN rd1_out[75]
    DIRECTION OUTPUT ;
    USE SIGNAL ;
    SHAPE ABUTMENT ;
    PORT
      LAYER M4 ;
      RECT 0.000 105.696 0.018 105.714 ;
    END
  END rd1_out[75]
  PIN rd1_out[76]
    DIRECTION OUTPUT ;
    USE SIGNAL ;
    SHAPE ABUTMENT ;
    PORT
      LAYER M4 ;
      RECT 0.000 105.876 0.018 105.894 ;
    END
  END rd1_out[76]
  PIN rd1_out[77]
    DIRECTION OUTPUT ;
    USE SIGNAL ;
    SHAPE ABUTMENT ;
    PORT
      LAYER M4 ;
      RECT 0.000 106.056 0.018 106.074 ;
    END
  END rd1_out[77]
  PIN rd1_out[78]
    DIRECTION OUTPUT ;
    USE SIGNAL ;
    SHAPE ABUTMENT ;
    PORT
      LAYER M4 ;
      RECT 0.000 106.236 0.018 106.254 ;
    END
  END rd1_out[78]
  PIN rd1_out[79]
    DIRECTION OUTPUT ;
    USE SIGNAL ;
    SHAPE ABUTMENT ;
    PORT
      LAYER M4 ;
      RECT 0.000 106.416 0.018 106.434 ;
    END
  END rd1_out[79]
  PIN rd1_out[80]
    DIRECTION OUTPUT ;
    USE SIGNAL ;
    SHAPE ABUTMENT ;
    PORT
      LAYER M4 ;
      RECT 0.000 106.596 0.018 106.614 ;
    END
  END rd1_out[80]
  PIN rd1_out[81]
    DIRECTION OUTPUT ;
    USE SIGNAL ;
    SHAPE ABUTMENT ;
    PORT
      LAYER M4 ;
      RECT 0.000 106.776 0.018 106.794 ;
    END
  END rd1_out[81]
  PIN rd1_out[82]
    DIRECTION OUTPUT ;
    USE SIGNAL ;
    SHAPE ABUTMENT ;
    PORT
      LAYER M4 ;
      RECT 0.000 106.956 0.018 106.974 ;
    END
  END rd1_out[82]
  PIN rd1_out[83]
    DIRECTION OUTPUT ;
    USE SIGNAL ;
    SHAPE ABUTMENT ;
    PORT
      LAYER M4 ;
      RECT 0.000 107.136 0.018 107.154 ;
    END
  END rd1_out[83]
  PIN rd1_out[84]
    DIRECTION OUTPUT ;
    USE SIGNAL ;
    SHAPE ABUTMENT ;
    PORT
      LAYER M4 ;
      RECT 0.000 107.316 0.018 107.334 ;
    END
  END rd1_out[84]
  PIN rd1_out[85]
    DIRECTION OUTPUT ;
    USE SIGNAL ;
    SHAPE ABUTMENT ;
    PORT
      LAYER M4 ;
      RECT 0.000 107.496 0.018 107.514 ;
    END
  END rd1_out[85]
  PIN rd1_out[86]
    DIRECTION OUTPUT ;
    USE SIGNAL ;
    SHAPE ABUTMENT ;
    PORT
      LAYER M4 ;
      RECT 0.000 107.676 0.018 107.694 ;
    END
  END rd1_out[86]
  PIN rd1_out[87]
    DIRECTION OUTPUT ;
    USE SIGNAL ;
    SHAPE ABUTMENT ;
    PORT
      LAYER M4 ;
      RECT 0.000 107.856 0.018 107.874 ;
    END
  END rd1_out[87]
  PIN rd1_out[88]
    DIRECTION OUTPUT ;
    USE SIGNAL ;
    SHAPE ABUTMENT ;
    PORT
      LAYER M4 ;
      RECT 0.000 108.036 0.018 108.054 ;
    END
  END rd1_out[88]
  PIN rd1_out[89]
    DIRECTION OUTPUT ;
    USE SIGNAL ;
    SHAPE ABUTMENT ;
    PORT
      LAYER M4 ;
      RECT 0.000 108.216 0.018 108.234 ;
    END
  END rd1_out[89]
  PIN rd1_out[90]
    DIRECTION OUTPUT ;
    USE SIGNAL ;
    SHAPE ABUTMENT ;
    PORT
      LAYER M4 ;
      RECT 0.000 108.396 0.018 108.414 ;
    END
  END rd1_out[90]
  PIN rd1_out[91]
    DIRECTION OUTPUT ;
    USE SIGNAL ;
    SHAPE ABUTMENT ;
    PORT
      LAYER M4 ;
      RECT 0.000 108.576 0.018 108.594 ;
    END
  END rd1_out[91]
  PIN rd1_out[92]
    DIRECTION OUTPUT ;
    USE SIGNAL ;
    SHAPE ABUTMENT ;
    PORT
      LAYER M4 ;
      RECT 0.000 108.756 0.018 108.774 ;
    END
  END rd1_out[92]
  PIN rd1_out[93]
    DIRECTION OUTPUT ;
    USE SIGNAL ;
    SHAPE ABUTMENT ;
    PORT
      LAYER M4 ;
      RECT 0.000 108.936 0.018 108.954 ;
    END
  END rd1_out[93]
  PIN rd1_out[94]
    DIRECTION OUTPUT ;
    USE SIGNAL ;
    SHAPE ABUTMENT ;
    PORT
      LAYER M4 ;
      RECT 0.000 109.116 0.018 109.134 ;
    END
  END rd1_out[94]
  PIN rd1_out[95]
    DIRECTION OUTPUT ;
    USE SIGNAL ;
    SHAPE ABUTMENT ;
    PORT
      LAYER M4 ;
      RECT 0.000 109.296 0.018 109.314 ;
    END
  END rd1_out[95]
  PIN rd1_out[96]
    DIRECTION OUTPUT ;
    USE SIGNAL ;
    SHAPE ABUTMENT ;
    PORT
      LAYER M4 ;
      RECT 0.000 109.476 0.018 109.494 ;
    END
  END rd1_out[96]
  PIN rd1_out[97]
    DIRECTION OUTPUT ;
    USE SIGNAL ;
    SHAPE ABUTMENT ;
    PORT
      LAYER M4 ;
      RECT 0.000 109.656 0.018 109.674 ;
    END
  END rd1_out[97]
  PIN rd1_out[98]
    DIRECTION OUTPUT ;
    USE SIGNAL ;
    SHAPE ABUTMENT ;
    PORT
      LAYER M4 ;
      RECT 0.000 109.836 0.018 109.854 ;
    END
  END rd1_out[98]
  PIN rd1_out[99]
    DIRECTION OUTPUT ;
    USE SIGNAL ;
    SHAPE ABUTMENT ;
    PORT
      LAYER M4 ;
      RECT 0.000 110.016 0.018 110.034 ;
    END
  END rd1_out[99]
  PIN rd1_out[100]
    DIRECTION OUTPUT ;
    USE SIGNAL ;
    SHAPE ABUTMENT ;
    PORT
      LAYER M4 ;
      RECT 0.000 110.196 0.018 110.214 ;
    END
  END rd1_out[100]
  PIN rd1_out[101]
    DIRECTION OUTPUT ;
    USE SIGNAL ;
    SHAPE ABUTMENT ;
    PORT
      LAYER M4 ;
      RECT 0.000 110.376 0.018 110.394 ;
    END
  END rd1_out[101]
  PIN rd1_out[102]
    DIRECTION OUTPUT ;
    USE SIGNAL ;
    SHAPE ABUTMENT ;
    PORT
      LAYER M4 ;
      RECT 0.000 110.556 0.018 110.574 ;
    END
  END rd1_out[102]
  PIN rd1_out[103]
    DIRECTION OUTPUT ;
    USE SIGNAL ;
    SHAPE ABUTMENT ;
    PORT
      LAYER M4 ;
      RECT 0.000 110.736 0.018 110.754 ;
    END
  END rd1_out[103]
  PIN rd1_out[104]
    DIRECTION OUTPUT ;
    USE SIGNAL ;
    SHAPE ABUTMENT ;
    PORT
      LAYER M4 ;
      RECT 0.000 110.916 0.018 110.934 ;
    END
  END rd1_out[104]
  PIN rd1_out[105]
    DIRECTION OUTPUT ;
    USE SIGNAL ;
    SHAPE ABUTMENT ;
    PORT
      LAYER M4 ;
      RECT 0.000 111.096 0.018 111.114 ;
    END
  END rd1_out[105]
  PIN rd1_out[106]
    DIRECTION OUTPUT ;
    USE SIGNAL ;
    SHAPE ABUTMENT ;
    PORT
      LAYER M4 ;
      RECT 0.000 111.276 0.018 111.294 ;
    END
  END rd1_out[106]
  PIN rd1_out[107]
    DIRECTION OUTPUT ;
    USE SIGNAL ;
    SHAPE ABUTMENT ;
    PORT
      LAYER M4 ;
      RECT 0.000 111.456 0.018 111.474 ;
    END
  END rd1_out[107]
  PIN rd1_out[108]
    DIRECTION OUTPUT ;
    USE SIGNAL ;
    SHAPE ABUTMENT ;
    PORT
      LAYER M4 ;
      RECT 0.000 111.636 0.018 111.654 ;
    END
  END rd1_out[108]
  PIN rd1_out[109]
    DIRECTION OUTPUT ;
    USE SIGNAL ;
    SHAPE ABUTMENT ;
    PORT
      LAYER M4 ;
      RECT 0.000 111.816 0.018 111.834 ;
    END
  END rd1_out[109]
  PIN rd1_out[110]
    DIRECTION OUTPUT ;
    USE SIGNAL ;
    SHAPE ABUTMENT ;
    PORT
      LAYER M4 ;
      RECT 0.000 111.996 0.018 112.014 ;
    END
  END rd1_out[110]
  PIN rd1_out[111]
    DIRECTION OUTPUT ;
    USE SIGNAL ;
    SHAPE ABUTMENT ;
    PORT
      LAYER M4 ;
      RECT 0.000 112.176 0.018 112.194 ;
    END
  END rd1_out[111]
  PIN rd1_out[112]
    DIRECTION OUTPUT ;
    USE SIGNAL ;
    SHAPE ABUTMENT ;
    PORT
      LAYER M4 ;
      RECT 0.000 112.356 0.018 112.374 ;
    END
  END rd1_out[112]
  PIN rd1_out[113]
    DIRECTION OUTPUT ;
    USE SIGNAL ;
    SHAPE ABUTMENT ;
    PORT
      LAYER M4 ;
      RECT 0.000 112.536 0.018 112.554 ;
    END
  END rd1_out[113]
  PIN rd1_out[114]
    DIRECTION OUTPUT ;
    USE SIGNAL ;
    SHAPE ABUTMENT ;
    PORT
      LAYER M4 ;
      RECT 0.000 112.716 0.018 112.734 ;
    END
  END rd1_out[114]
  PIN rd1_out[115]
    DIRECTION OUTPUT ;
    USE SIGNAL ;
    SHAPE ABUTMENT ;
    PORT
      LAYER M4 ;
      RECT 0.000 112.896 0.018 112.914 ;
    END
  END rd1_out[115]
  PIN rd1_out[116]
    DIRECTION OUTPUT ;
    USE SIGNAL ;
    SHAPE ABUTMENT ;
    PORT
      LAYER M4 ;
      RECT 0.000 113.076 0.018 113.094 ;
    END
  END rd1_out[116]
  PIN rd1_out[117]
    DIRECTION OUTPUT ;
    USE SIGNAL ;
    SHAPE ABUTMENT ;
    PORT
      LAYER M4 ;
      RECT 0.000 113.256 0.018 113.274 ;
    END
  END rd1_out[117]
  PIN rd1_out[118]
    DIRECTION OUTPUT ;
    USE SIGNAL ;
    SHAPE ABUTMENT ;
    PORT
      LAYER M4 ;
      RECT 0.000 113.436 0.018 113.454 ;
    END
  END rd1_out[118]
  PIN rd1_out[119]
    DIRECTION OUTPUT ;
    USE SIGNAL ;
    SHAPE ABUTMENT ;
    PORT
      LAYER M4 ;
      RECT 0.000 113.616 0.018 113.634 ;
    END
  END rd1_out[119]
  PIN rd1_out[120]
    DIRECTION OUTPUT ;
    USE SIGNAL ;
    SHAPE ABUTMENT ;
    PORT
      LAYER M4 ;
      RECT 0.000 113.796 0.018 113.814 ;
    END
  END rd1_out[120]
  PIN rd1_out[121]
    DIRECTION OUTPUT ;
    USE SIGNAL ;
    SHAPE ABUTMENT ;
    PORT
      LAYER M4 ;
      RECT 0.000 113.976 0.018 113.994 ;
    END
  END rd1_out[121]
  PIN rd1_out[122]
    DIRECTION OUTPUT ;
    USE SIGNAL ;
    SHAPE ABUTMENT ;
    PORT
      LAYER M4 ;
      RECT 0.000 114.156 0.018 114.174 ;
    END
  END rd1_out[122]
  PIN rd1_out[123]
    DIRECTION OUTPUT ;
    USE SIGNAL ;
    SHAPE ABUTMENT ;
    PORT
      LAYER M4 ;
      RECT 0.000 114.336 0.018 114.354 ;
    END
  END rd1_out[123]
  PIN rd1_out[124]
    DIRECTION OUTPUT ;
    USE SIGNAL ;
    SHAPE ABUTMENT ;
    PORT
      LAYER M4 ;
      RECT 0.000 114.516 0.018 114.534 ;
    END
  END rd1_out[124]
  PIN rd1_out[125]
    DIRECTION OUTPUT ;
    USE SIGNAL ;
    SHAPE ABUTMENT ;
    PORT
      LAYER M4 ;
      RECT 0.000 114.696 0.018 114.714 ;
    END
  END rd1_out[125]
  PIN rd1_out[126]
    DIRECTION OUTPUT ;
    USE SIGNAL ;
    SHAPE ABUTMENT ;
    PORT
      LAYER M4 ;
      RECT 0.000 114.876 0.018 114.894 ;
    END
  END rd1_out[126]
  PIN rd1_out[127]
    DIRECTION OUTPUT ;
    USE SIGNAL ;
    SHAPE ABUTMENT ;
    PORT
      LAYER M4 ;
      RECT 0.000 115.056 0.018 115.074 ;
    END
  END rd1_out[127]
  PIN rd1_out[128]
    DIRECTION OUTPUT ;
    USE SIGNAL ;
    SHAPE ABUTMENT ;
    PORT
      LAYER M4 ;
      RECT 0.000 115.236 0.018 115.254 ;
    END
  END rd1_out[128]
  PIN rd1_out[129]
    DIRECTION OUTPUT ;
    USE SIGNAL ;
    SHAPE ABUTMENT ;
    PORT
      LAYER M4 ;
      RECT 0.000 115.416 0.018 115.434 ;
    END
  END rd1_out[129]
  PIN rd1_out[130]
    DIRECTION OUTPUT ;
    USE SIGNAL ;
    SHAPE ABUTMENT ;
    PORT
      LAYER M4 ;
      RECT 0.000 115.596 0.018 115.614 ;
    END
  END rd1_out[130]
  PIN rd1_out[131]
    DIRECTION OUTPUT ;
    USE SIGNAL ;
    SHAPE ABUTMENT ;
    PORT
      LAYER M4 ;
      RECT 0.000 115.776 0.018 115.794 ;
    END
  END rd1_out[131]
  PIN rd1_out[132]
    DIRECTION OUTPUT ;
    USE SIGNAL ;
    SHAPE ABUTMENT ;
    PORT
      LAYER M4 ;
      RECT 0.000 115.956 0.018 115.974 ;
    END
  END rd1_out[132]
  PIN rd1_out[133]
    DIRECTION OUTPUT ;
    USE SIGNAL ;
    SHAPE ABUTMENT ;
    PORT
      LAYER M4 ;
      RECT 0.000 116.136 0.018 116.154 ;
    END
  END rd1_out[133]
  PIN rd1_out[134]
    DIRECTION OUTPUT ;
    USE SIGNAL ;
    SHAPE ABUTMENT ;
    PORT
      LAYER M4 ;
      RECT 0.000 116.316 0.018 116.334 ;
    END
  END rd1_out[134]
  PIN rd1_out[135]
    DIRECTION OUTPUT ;
    USE SIGNAL ;
    SHAPE ABUTMENT ;
    PORT
      LAYER M4 ;
      RECT 0.000 116.496 0.018 116.514 ;
    END
  END rd1_out[135]
  PIN rd1_out[136]
    DIRECTION OUTPUT ;
    USE SIGNAL ;
    SHAPE ABUTMENT ;
    PORT
      LAYER M4 ;
      RECT 0.000 116.676 0.018 116.694 ;
    END
  END rd1_out[136]
  PIN rd1_out[137]
    DIRECTION OUTPUT ;
    USE SIGNAL ;
    SHAPE ABUTMENT ;
    PORT
      LAYER M4 ;
      RECT 0.000 116.856 0.018 116.874 ;
    END
  END rd1_out[137]
  PIN rd1_out[138]
    DIRECTION OUTPUT ;
    USE SIGNAL ;
    SHAPE ABUTMENT ;
    PORT
      LAYER M4 ;
      RECT 0.000 117.036 0.018 117.054 ;
    END
  END rd1_out[138]
  PIN rd1_out[139]
    DIRECTION OUTPUT ;
    USE SIGNAL ;
    SHAPE ABUTMENT ;
    PORT
      LAYER M4 ;
      RECT 0.000 117.216 0.018 117.234 ;
    END
  END rd1_out[139]
  PIN rd1_out[140]
    DIRECTION OUTPUT ;
    USE SIGNAL ;
    SHAPE ABUTMENT ;
    PORT
      LAYER M4 ;
      RECT 0.000 117.396 0.018 117.414 ;
    END
  END rd1_out[140]
  PIN rd1_out[141]
    DIRECTION OUTPUT ;
    USE SIGNAL ;
    SHAPE ABUTMENT ;
    PORT
      LAYER M4 ;
      RECT 0.000 117.576 0.018 117.594 ;
    END
  END rd1_out[141]
  PIN rd1_out[142]
    DIRECTION OUTPUT ;
    USE SIGNAL ;
    SHAPE ABUTMENT ;
    PORT
      LAYER M4 ;
      RECT 0.000 117.756 0.018 117.774 ;
    END
  END rd1_out[142]
  PIN rd1_out[143]
    DIRECTION OUTPUT ;
    USE SIGNAL ;
    SHAPE ABUTMENT ;
    PORT
      LAYER M4 ;
      RECT 0.000 117.936 0.018 117.954 ;
    END
  END rd1_out[143]
  PIN rd1_out[144]
    DIRECTION OUTPUT ;
    USE SIGNAL ;
    SHAPE ABUTMENT ;
    PORT
      LAYER M4 ;
      RECT 0.000 118.116 0.018 118.134 ;
    END
  END rd1_out[144]
  PIN rd1_out[145]
    DIRECTION OUTPUT ;
    USE SIGNAL ;
    SHAPE ABUTMENT ;
    PORT
      LAYER M4 ;
      RECT 0.000 118.296 0.018 118.314 ;
    END
  END rd1_out[145]
  PIN rd1_out[146]
    DIRECTION OUTPUT ;
    USE SIGNAL ;
    SHAPE ABUTMENT ;
    PORT
      LAYER M4 ;
      RECT 0.000 118.476 0.018 118.494 ;
    END
  END rd1_out[146]
  PIN rd1_out[147]
    DIRECTION OUTPUT ;
    USE SIGNAL ;
    SHAPE ABUTMENT ;
    PORT
      LAYER M4 ;
      RECT 0.000 118.656 0.018 118.674 ;
    END
  END rd1_out[147]
  PIN rd1_out[148]
    DIRECTION OUTPUT ;
    USE SIGNAL ;
    SHAPE ABUTMENT ;
    PORT
      LAYER M4 ;
      RECT 0.000 118.836 0.018 118.854 ;
    END
  END rd1_out[148]
  PIN rd1_out[149]
    DIRECTION OUTPUT ;
    USE SIGNAL ;
    SHAPE ABUTMENT ;
    PORT
      LAYER M4 ;
      RECT 0.000 119.016 0.018 119.034 ;
    END
  END rd1_out[149]
  PIN rd1_out[150]
    DIRECTION OUTPUT ;
    USE SIGNAL ;
    SHAPE ABUTMENT ;
    PORT
      LAYER M4 ;
      RECT 0.000 119.196 0.018 119.214 ;
    END
  END rd1_out[150]
  PIN rd1_out[151]
    DIRECTION OUTPUT ;
    USE SIGNAL ;
    SHAPE ABUTMENT ;
    PORT
      LAYER M4 ;
      RECT 0.000 119.376 0.018 119.394 ;
    END
  END rd1_out[151]
  PIN rd1_out[152]
    DIRECTION OUTPUT ;
    USE SIGNAL ;
    SHAPE ABUTMENT ;
    PORT
      LAYER M4 ;
      RECT 0.000 119.556 0.018 119.574 ;
    END
  END rd1_out[152]
  PIN rd1_out[153]
    DIRECTION OUTPUT ;
    USE SIGNAL ;
    SHAPE ABUTMENT ;
    PORT
      LAYER M4 ;
      RECT 0.000 119.736 0.018 119.754 ;
    END
  END rd1_out[153]
  PIN rd1_out[154]
    DIRECTION OUTPUT ;
    USE SIGNAL ;
    SHAPE ABUTMENT ;
    PORT
      LAYER M4 ;
      RECT 0.000 119.916 0.018 119.934 ;
    END
  END rd1_out[154]
  PIN rd1_out[155]
    DIRECTION OUTPUT ;
    USE SIGNAL ;
    SHAPE ABUTMENT ;
    PORT
      LAYER M4 ;
      RECT 0.000 120.096 0.018 120.114 ;
    END
  END rd1_out[155]
  PIN rd1_out[156]
    DIRECTION OUTPUT ;
    USE SIGNAL ;
    SHAPE ABUTMENT ;
    PORT
      LAYER M4 ;
      RECT 0.000 120.276 0.018 120.294 ;
    END
  END rd1_out[156]
  PIN rd1_out[157]
    DIRECTION OUTPUT ;
    USE SIGNAL ;
    SHAPE ABUTMENT ;
    PORT
      LAYER M4 ;
      RECT 0.000 120.456 0.018 120.474 ;
    END
  END rd1_out[157]
  PIN rd1_out[158]
    DIRECTION OUTPUT ;
    USE SIGNAL ;
    SHAPE ABUTMENT ;
    PORT
      LAYER M4 ;
      RECT 0.000 120.636 0.018 120.654 ;
    END
  END rd1_out[158]
  PIN rd1_out[159]
    DIRECTION OUTPUT ;
    USE SIGNAL ;
    SHAPE ABUTMENT ;
    PORT
      LAYER M4 ;
      RECT 0.000 120.816 0.018 120.834 ;
    END
  END rd1_out[159]
  PIN rd1_out[160]
    DIRECTION OUTPUT ;
    USE SIGNAL ;
    SHAPE ABUTMENT ;
    PORT
      LAYER M4 ;
      RECT 0.000 120.996 0.018 121.014 ;
    END
  END rd1_out[160]
  PIN rd1_out[161]
    DIRECTION OUTPUT ;
    USE SIGNAL ;
    SHAPE ABUTMENT ;
    PORT
      LAYER M4 ;
      RECT 0.000 121.176 0.018 121.194 ;
    END
  END rd1_out[161]
  PIN rd1_out[162]
    DIRECTION OUTPUT ;
    USE SIGNAL ;
    SHAPE ABUTMENT ;
    PORT
      LAYER M4 ;
      RECT 0.000 121.356 0.018 121.374 ;
    END
  END rd1_out[162]
  PIN rd1_out[163]
    DIRECTION OUTPUT ;
    USE SIGNAL ;
    SHAPE ABUTMENT ;
    PORT
      LAYER M4 ;
      RECT 0.000 121.536 0.018 121.554 ;
    END
  END rd1_out[163]
  PIN rd1_out[164]
    DIRECTION OUTPUT ;
    USE SIGNAL ;
    SHAPE ABUTMENT ;
    PORT
      LAYER M4 ;
      RECT 0.000 121.716 0.018 121.734 ;
    END
  END rd1_out[164]
  PIN rd1_out[165]
    DIRECTION OUTPUT ;
    USE SIGNAL ;
    SHAPE ABUTMENT ;
    PORT
      LAYER M4 ;
      RECT 0.000 121.896 0.018 121.914 ;
    END
  END rd1_out[165]
  PIN rd1_out[166]
    DIRECTION OUTPUT ;
    USE SIGNAL ;
    SHAPE ABUTMENT ;
    PORT
      LAYER M4 ;
      RECT 0.000 122.076 0.018 122.094 ;
    END
  END rd1_out[166]
  PIN rd1_out[167]
    DIRECTION OUTPUT ;
    USE SIGNAL ;
    SHAPE ABUTMENT ;
    PORT
      LAYER M4 ;
      RECT 0.000 122.256 0.018 122.274 ;
    END
  END rd1_out[167]
  PIN rd1_out[168]
    DIRECTION OUTPUT ;
    USE SIGNAL ;
    SHAPE ABUTMENT ;
    PORT
      LAYER M4 ;
      RECT 0.000 122.436 0.018 122.454 ;
    END
  END rd1_out[168]
  PIN rd1_out[169]
    DIRECTION OUTPUT ;
    USE SIGNAL ;
    SHAPE ABUTMENT ;
    PORT
      LAYER M4 ;
      RECT 0.000 122.616 0.018 122.634 ;
    END
  END rd1_out[169]
  PIN rd1_out[170]
    DIRECTION OUTPUT ;
    USE SIGNAL ;
    SHAPE ABUTMENT ;
    PORT
      LAYER M4 ;
      RECT 0.000 122.796 0.018 122.814 ;
    END
  END rd1_out[170]
  PIN rd1_out[171]
    DIRECTION OUTPUT ;
    USE SIGNAL ;
    SHAPE ABUTMENT ;
    PORT
      LAYER M4 ;
      RECT 0.000 122.976 0.018 122.994 ;
    END
  END rd1_out[171]
  PIN rd1_out[172]
    DIRECTION OUTPUT ;
    USE SIGNAL ;
    SHAPE ABUTMENT ;
    PORT
      LAYER M4 ;
      RECT 0.000 123.156 0.018 123.174 ;
    END
  END rd1_out[172]
  PIN rd1_out[173]
    DIRECTION OUTPUT ;
    USE SIGNAL ;
    SHAPE ABUTMENT ;
    PORT
      LAYER M4 ;
      RECT 0.000 123.336 0.018 123.354 ;
    END
  END rd1_out[173]
  PIN rd1_out[174]
    DIRECTION OUTPUT ;
    USE SIGNAL ;
    SHAPE ABUTMENT ;
    PORT
      LAYER M4 ;
      RECT 0.000 123.516 0.018 123.534 ;
    END
  END rd1_out[174]
  PIN rd1_out[175]
    DIRECTION OUTPUT ;
    USE SIGNAL ;
    SHAPE ABUTMENT ;
    PORT
      LAYER M4 ;
      RECT 0.000 123.696 0.018 123.714 ;
    END
  END rd1_out[175]
  PIN rd1_out[176]
    DIRECTION OUTPUT ;
    USE SIGNAL ;
    SHAPE ABUTMENT ;
    PORT
      LAYER M4 ;
      RECT 0.000 123.876 0.018 123.894 ;
    END
  END rd1_out[176]
  PIN rd1_out[177]
    DIRECTION OUTPUT ;
    USE SIGNAL ;
    SHAPE ABUTMENT ;
    PORT
      LAYER M4 ;
      RECT 0.000 124.056 0.018 124.074 ;
    END
  END rd1_out[177]
  PIN rd1_out[178]
    DIRECTION OUTPUT ;
    USE SIGNAL ;
    SHAPE ABUTMENT ;
    PORT
      LAYER M4 ;
      RECT 0.000 124.236 0.018 124.254 ;
    END
  END rd1_out[178]
  PIN rd1_out[179]
    DIRECTION OUTPUT ;
    USE SIGNAL ;
    SHAPE ABUTMENT ;
    PORT
      LAYER M4 ;
      RECT 0.000 124.416 0.018 124.434 ;
    END
  END rd1_out[179]
  PIN rd1_out[180]
    DIRECTION OUTPUT ;
    USE SIGNAL ;
    SHAPE ABUTMENT ;
    PORT
      LAYER M4 ;
      RECT 0.000 124.596 0.018 124.614 ;
    END
  END rd1_out[180]
  PIN rd1_out[181]
    DIRECTION OUTPUT ;
    USE SIGNAL ;
    SHAPE ABUTMENT ;
    PORT
      LAYER M4 ;
      RECT 0.000 124.776 0.018 124.794 ;
    END
  END rd1_out[181]
  PIN rd1_out[182]
    DIRECTION OUTPUT ;
    USE SIGNAL ;
    SHAPE ABUTMENT ;
    PORT
      LAYER M4 ;
      RECT 0.000 124.956 0.018 124.974 ;
    END
  END rd1_out[182]
  PIN rd1_out[183]
    DIRECTION OUTPUT ;
    USE SIGNAL ;
    SHAPE ABUTMENT ;
    PORT
      LAYER M4 ;
      RECT 0.000 125.136 0.018 125.154 ;
    END
  END rd1_out[183]
  PIN rd1_out[184]
    DIRECTION OUTPUT ;
    USE SIGNAL ;
    SHAPE ABUTMENT ;
    PORT
      LAYER M4 ;
      RECT 0.000 125.316 0.018 125.334 ;
    END
  END rd1_out[184]
  PIN rd1_out[185]
    DIRECTION OUTPUT ;
    USE SIGNAL ;
    SHAPE ABUTMENT ;
    PORT
      LAYER M4 ;
      RECT 0.000 125.496 0.018 125.514 ;
    END
  END rd1_out[185]
  PIN rd1_out[186]
    DIRECTION OUTPUT ;
    USE SIGNAL ;
    SHAPE ABUTMENT ;
    PORT
      LAYER M4 ;
      RECT 0.000 125.676 0.018 125.694 ;
    END
  END rd1_out[186]
  PIN rd1_out[187]
    DIRECTION OUTPUT ;
    USE SIGNAL ;
    SHAPE ABUTMENT ;
    PORT
      LAYER M4 ;
      RECT 0.000 125.856 0.018 125.874 ;
    END
  END rd1_out[187]
  PIN rd1_out[188]
    DIRECTION OUTPUT ;
    USE SIGNAL ;
    SHAPE ABUTMENT ;
    PORT
      LAYER M4 ;
      RECT 0.000 126.036 0.018 126.054 ;
    END
  END rd1_out[188]
  PIN rd1_out[189]
    DIRECTION OUTPUT ;
    USE SIGNAL ;
    SHAPE ABUTMENT ;
    PORT
      LAYER M4 ;
      RECT 0.000 126.216 0.018 126.234 ;
    END
  END rd1_out[189]
  PIN rd1_out[190]
    DIRECTION OUTPUT ;
    USE SIGNAL ;
    SHAPE ABUTMENT ;
    PORT
      LAYER M4 ;
      RECT 0.000 126.396 0.018 126.414 ;
    END
  END rd1_out[190]
  PIN rd1_out[191]
    DIRECTION OUTPUT ;
    USE SIGNAL ;
    SHAPE ABUTMENT ;
    PORT
      LAYER M4 ;
      RECT 0.000 126.576 0.018 126.594 ;
    END
  END rd1_out[191]
  PIN rd1_out[192]
    DIRECTION OUTPUT ;
    USE SIGNAL ;
    SHAPE ABUTMENT ;
    PORT
      LAYER M4 ;
      RECT 0.000 126.756 0.018 126.774 ;
    END
  END rd1_out[192]
  PIN rd1_out[193]
    DIRECTION OUTPUT ;
    USE SIGNAL ;
    SHAPE ABUTMENT ;
    PORT
      LAYER M4 ;
      RECT 0.000 126.936 0.018 126.954 ;
    END
  END rd1_out[193]
  PIN rd1_out[194]
    DIRECTION OUTPUT ;
    USE SIGNAL ;
    SHAPE ABUTMENT ;
    PORT
      LAYER M4 ;
      RECT 0.000 127.116 0.018 127.134 ;
    END
  END rd1_out[194]
  PIN rd1_out[195]
    DIRECTION OUTPUT ;
    USE SIGNAL ;
    SHAPE ABUTMENT ;
    PORT
      LAYER M4 ;
      RECT 0.000 127.296 0.018 127.314 ;
    END
  END rd1_out[195]
  PIN rd1_out[196]
    DIRECTION OUTPUT ;
    USE SIGNAL ;
    SHAPE ABUTMENT ;
    PORT
      LAYER M4 ;
      RECT 0.000 127.476 0.018 127.494 ;
    END
  END rd1_out[196]
  PIN rd1_out[197]
    DIRECTION OUTPUT ;
    USE SIGNAL ;
    SHAPE ABUTMENT ;
    PORT
      LAYER M4 ;
      RECT 0.000 127.656 0.018 127.674 ;
    END
  END rd1_out[197]
  PIN rd1_out[198]
    DIRECTION OUTPUT ;
    USE SIGNAL ;
    SHAPE ABUTMENT ;
    PORT
      LAYER M4 ;
      RECT 0.000 127.836 0.018 127.854 ;
    END
  END rd1_out[198]
  PIN rd1_out[199]
    DIRECTION OUTPUT ;
    USE SIGNAL ;
    SHAPE ABUTMENT ;
    PORT
      LAYER M4 ;
      RECT 0.000 128.016 0.018 128.034 ;
    END
  END rd1_out[199]
  PIN rd1_out[200]
    DIRECTION OUTPUT ;
    USE SIGNAL ;
    SHAPE ABUTMENT ;
    PORT
      LAYER M4 ;
      RECT 0.000 128.196 0.018 128.214 ;
    END
  END rd1_out[200]
  PIN rd1_out[201]
    DIRECTION OUTPUT ;
    USE SIGNAL ;
    SHAPE ABUTMENT ;
    PORT
      LAYER M4 ;
      RECT 0.000 128.376 0.018 128.394 ;
    END
  END rd1_out[201]
  PIN rd1_out[202]
    DIRECTION OUTPUT ;
    USE SIGNAL ;
    SHAPE ABUTMENT ;
    PORT
      LAYER M4 ;
      RECT 0.000 128.556 0.018 128.574 ;
    END
  END rd1_out[202]
  PIN rd1_out[203]
    DIRECTION OUTPUT ;
    USE SIGNAL ;
    SHAPE ABUTMENT ;
    PORT
      LAYER M4 ;
      RECT 0.000 128.736 0.018 128.754 ;
    END
  END rd1_out[203]
  PIN rd1_out[204]
    DIRECTION OUTPUT ;
    USE SIGNAL ;
    SHAPE ABUTMENT ;
    PORT
      LAYER M4 ;
      RECT 0.000 128.916 0.018 128.934 ;
    END
  END rd1_out[204]
  PIN rd1_out[205]
    DIRECTION OUTPUT ;
    USE SIGNAL ;
    SHAPE ABUTMENT ;
    PORT
      LAYER M4 ;
      RECT 0.000 129.096 0.018 129.114 ;
    END
  END rd1_out[205]
  PIN rd1_out[206]
    DIRECTION OUTPUT ;
    USE SIGNAL ;
    SHAPE ABUTMENT ;
    PORT
      LAYER M4 ;
      RECT 0.000 129.276 0.018 129.294 ;
    END
  END rd1_out[206]
  PIN rd1_out[207]
    DIRECTION OUTPUT ;
    USE SIGNAL ;
    SHAPE ABUTMENT ;
    PORT
      LAYER M4 ;
      RECT 0.000 129.456 0.018 129.474 ;
    END
  END rd1_out[207]
  PIN rd1_out[208]
    DIRECTION OUTPUT ;
    USE SIGNAL ;
    SHAPE ABUTMENT ;
    PORT
      LAYER M4 ;
      RECT 0.000 129.636 0.018 129.654 ;
    END
  END rd1_out[208]
  PIN rd1_out[209]
    DIRECTION OUTPUT ;
    USE SIGNAL ;
    SHAPE ABUTMENT ;
    PORT
      LAYER M4 ;
      RECT 0.000 129.816 0.018 129.834 ;
    END
  END rd1_out[209]
  PIN rd1_out[210]
    DIRECTION OUTPUT ;
    USE SIGNAL ;
    SHAPE ABUTMENT ;
    PORT
      LAYER M4 ;
      RECT 0.000 129.996 0.018 130.014 ;
    END
  END rd1_out[210]
  PIN rd1_out[211]
    DIRECTION OUTPUT ;
    USE SIGNAL ;
    SHAPE ABUTMENT ;
    PORT
      LAYER M4 ;
      RECT 0.000 130.176 0.018 130.194 ;
    END
  END rd1_out[211]
  PIN rd1_out[212]
    DIRECTION OUTPUT ;
    USE SIGNAL ;
    SHAPE ABUTMENT ;
    PORT
      LAYER M4 ;
      RECT 0.000 130.356 0.018 130.374 ;
    END
  END rd1_out[212]
  PIN rd1_out[213]
    DIRECTION OUTPUT ;
    USE SIGNAL ;
    SHAPE ABUTMENT ;
    PORT
      LAYER M4 ;
      RECT 0.000 130.536 0.018 130.554 ;
    END
  END rd1_out[213]
  PIN rd1_out[214]
    DIRECTION OUTPUT ;
    USE SIGNAL ;
    SHAPE ABUTMENT ;
    PORT
      LAYER M4 ;
      RECT 0.000 130.716 0.018 130.734 ;
    END
  END rd1_out[214]
  PIN rd1_out[215]
    DIRECTION OUTPUT ;
    USE SIGNAL ;
    SHAPE ABUTMENT ;
    PORT
      LAYER M4 ;
      RECT 0.000 130.896 0.018 130.914 ;
    END
  END rd1_out[215]
  PIN rd1_out[216]
    DIRECTION OUTPUT ;
    USE SIGNAL ;
    SHAPE ABUTMENT ;
    PORT
      LAYER M4 ;
      RECT 0.000 131.076 0.018 131.094 ;
    END
  END rd1_out[216]
  PIN rd1_out[217]
    DIRECTION OUTPUT ;
    USE SIGNAL ;
    SHAPE ABUTMENT ;
    PORT
      LAYER M4 ;
      RECT 0.000 131.256 0.018 131.274 ;
    END
  END rd1_out[217]
  PIN rd1_out[218]
    DIRECTION OUTPUT ;
    USE SIGNAL ;
    SHAPE ABUTMENT ;
    PORT
      LAYER M4 ;
      RECT 0.000 131.436 0.018 131.454 ;
    END
  END rd1_out[218]
  PIN rd1_out[219]
    DIRECTION OUTPUT ;
    USE SIGNAL ;
    SHAPE ABUTMENT ;
    PORT
      LAYER M4 ;
      RECT 0.000 131.616 0.018 131.634 ;
    END
  END rd1_out[219]
  PIN rd1_out[220]
    DIRECTION OUTPUT ;
    USE SIGNAL ;
    SHAPE ABUTMENT ;
    PORT
      LAYER M4 ;
      RECT 0.000 131.796 0.018 131.814 ;
    END
  END rd1_out[220]
  PIN rd1_out[221]
    DIRECTION OUTPUT ;
    USE SIGNAL ;
    SHAPE ABUTMENT ;
    PORT
      LAYER M4 ;
      RECT 0.000 131.976 0.018 131.994 ;
    END
  END rd1_out[221]
  PIN rd1_out[222]
    DIRECTION OUTPUT ;
    USE SIGNAL ;
    SHAPE ABUTMENT ;
    PORT
      LAYER M4 ;
      RECT 0.000 132.156 0.018 132.174 ;
    END
  END rd1_out[222]
  PIN rd1_out[223]
    DIRECTION OUTPUT ;
    USE SIGNAL ;
    SHAPE ABUTMENT ;
    PORT
      LAYER M4 ;
      RECT 0.000 132.336 0.018 132.354 ;
    END
  END rd1_out[223]
  PIN rd1_out[224]
    DIRECTION OUTPUT ;
    USE SIGNAL ;
    SHAPE ABUTMENT ;
    PORT
      LAYER M4 ;
      RECT 0.000 132.516 0.018 132.534 ;
    END
  END rd1_out[224]
  PIN rd1_out[225]
    DIRECTION OUTPUT ;
    USE SIGNAL ;
    SHAPE ABUTMENT ;
    PORT
      LAYER M4 ;
      RECT 0.000 132.696 0.018 132.714 ;
    END
  END rd1_out[225]
  PIN rd1_out[226]
    DIRECTION OUTPUT ;
    USE SIGNAL ;
    SHAPE ABUTMENT ;
    PORT
      LAYER M4 ;
      RECT 0.000 132.876 0.018 132.894 ;
    END
  END rd1_out[226]
  PIN rd1_out[227]
    DIRECTION OUTPUT ;
    USE SIGNAL ;
    SHAPE ABUTMENT ;
    PORT
      LAYER M4 ;
      RECT 0.000 133.056 0.018 133.074 ;
    END
  END rd1_out[227]
  PIN rd1_out[228]
    DIRECTION OUTPUT ;
    USE SIGNAL ;
    SHAPE ABUTMENT ;
    PORT
      LAYER M4 ;
      RECT 0.000 133.236 0.018 133.254 ;
    END
  END rd1_out[228]
  PIN rd1_out[229]
    DIRECTION OUTPUT ;
    USE SIGNAL ;
    SHAPE ABUTMENT ;
    PORT
      LAYER M4 ;
      RECT 0.000 133.416 0.018 133.434 ;
    END
  END rd1_out[229]
  PIN rd1_out[230]
    DIRECTION OUTPUT ;
    USE SIGNAL ;
    SHAPE ABUTMENT ;
    PORT
      LAYER M4 ;
      RECT 0.000 133.596 0.018 133.614 ;
    END
  END rd1_out[230]
  PIN rd1_out[231]
    DIRECTION OUTPUT ;
    USE SIGNAL ;
    SHAPE ABUTMENT ;
    PORT
      LAYER M4 ;
      RECT 0.000 133.776 0.018 133.794 ;
    END
  END rd1_out[231]
  PIN rd1_out[232]
    DIRECTION OUTPUT ;
    USE SIGNAL ;
    SHAPE ABUTMENT ;
    PORT
      LAYER M4 ;
      RECT 0.000 133.956 0.018 133.974 ;
    END
  END rd1_out[232]
  PIN rd1_out[233]
    DIRECTION OUTPUT ;
    USE SIGNAL ;
    SHAPE ABUTMENT ;
    PORT
      LAYER M4 ;
      RECT 0.000 134.136 0.018 134.154 ;
    END
  END rd1_out[233]
  PIN rd1_out[234]
    DIRECTION OUTPUT ;
    USE SIGNAL ;
    SHAPE ABUTMENT ;
    PORT
      LAYER M4 ;
      RECT 0.000 134.316 0.018 134.334 ;
    END
  END rd1_out[234]
  PIN rd1_out[235]
    DIRECTION OUTPUT ;
    USE SIGNAL ;
    SHAPE ABUTMENT ;
    PORT
      LAYER M4 ;
      RECT 0.000 134.496 0.018 134.514 ;
    END
  END rd1_out[235]
  PIN rd1_out[236]
    DIRECTION OUTPUT ;
    USE SIGNAL ;
    SHAPE ABUTMENT ;
    PORT
      LAYER M4 ;
      RECT 0.000 134.676 0.018 134.694 ;
    END
  END rd1_out[236]
  PIN rd1_out[237]
    DIRECTION OUTPUT ;
    USE SIGNAL ;
    SHAPE ABUTMENT ;
    PORT
      LAYER M4 ;
      RECT 0.000 134.856 0.018 134.874 ;
    END
  END rd1_out[237]
  PIN rd1_out[238]
    DIRECTION OUTPUT ;
    USE SIGNAL ;
    SHAPE ABUTMENT ;
    PORT
      LAYER M4 ;
      RECT 0.000 135.036 0.018 135.054 ;
    END
  END rd1_out[238]
  PIN rd1_out[239]
    DIRECTION OUTPUT ;
    USE SIGNAL ;
    SHAPE ABUTMENT ;
    PORT
      LAYER M4 ;
      RECT 0.000 135.216 0.018 135.234 ;
    END
  END rd1_out[239]
  PIN rd1_out[240]
    DIRECTION OUTPUT ;
    USE SIGNAL ;
    SHAPE ABUTMENT ;
    PORT
      LAYER M4 ;
      RECT 0.000 135.396 0.018 135.414 ;
    END
  END rd1_out[240]
  PIN rd1_out[241]
    DIRECTION OUTPUT ;
    USE SIGNAL ;
    SHAPE ABUTMENT ;
    PORT
      LAYER M4 ;
      RECT 0.000 135.576 0.018 135.594 ;
    END
  END rd1_out[241]
  PIN rd1_out[242]
    DIRECTION OUTPUT ;
    USE SIGNAL ;
    SHAPE ABUTMENT ;
    PORT
      LAYER M4 ;
      RECT 0.000 135.756 0.018 135.774 ;
    END
  END rd1_out[242]
  PIN rd1_out[243]
    DIRECTION OUTPUT ;
    USE SIGNAL ;
    SHAPE ABUTMENT ;
    PORT
      LAYER M4 ;
      RECT 0.000 135.936 0.018 135.954 ;
    END
  END rd1_out[243]
  PIN rd1_out[244]
    DIRECTION OUTPUT ;
    USE SIGNAL ;
    SHAPE ABUTMENT ;
    PORT
      LAYER M4 ;
      RECT 0.000 136.116 0.018 136.134 ;
    END
  END rd1_out[244]
  PIN rd1_out[245]
    DIRECTION OUTPUT ;
    USE SIGNAL ;
    SHAPE ABUTMENT ;
    PORT
      LAYER M4 ;
      RECT 0.000 136.296 0.018 136.314 ;
    END
  END rd1_out[245]
  PIN rd1_out[246]
    DIRECTION OUTPUT ;
    USE SIGNAL ;
    SHAPE ABUTMENT ;
    PORT
      LAYER M4 ;
      RECT 0.000 136.476 0.018 136.494 ;
    END
  END rd1_out[246]
  PIN rd1_out[247]
    DIRECTION OUTPUT ;
    USE SIGNAL ;
    SHAPE ABUTMENT ;
    PORT
      LAYER M4 ;
      RECT 0.000 136.656 0.018 136.674 ;
    END
  END rd1_out[247]
  PIN rd1_out[248]
    DIRECTION OUTPUT ;
    USE SIGNAL ;
    SHAPE ABUTMENT ;
    PORT
      LAYER M4 ;
      RECT 0.000 136.836 0.018 136.854 ;
    END
  END rd1_out[248]
  PIN rd1_out[249]
    DIRECTION OUTPUT ;
    USE SIGNAL ;
    SHAPE ABUTMENT ;
    PORT
      LAYER M4 ;
      RECT 0.000 137.016 0.018 137.034 ;
    END
  END rd1_out[249]
  PIN rd1_out[250]
    DIRECTION OUTPUT ;
    USE SIGNAL ;
    SHAPE ABUTMENT ;
    PORT
      LAYER M4 ;
      RECT 0.000 137.196 0.018 137.214 ;
    END
  END rd1_out[250]
  PIN rd1_out[251]
    DIRECTION OUTPUT ;
    USE SIGNAL ;
    SHAPE ABUTMENT ;
    PORT
      LAYER M4 ;
      RECT 0.000 137.376 0.018 137.394 ;
    END
  END rd1_out[251]
  PIN rd1_out[252]
    DIRECTION OUTPUT ;
    USE SIGNAL ;
    SHAPE ABUTMENT ;
    PORT
      LAYER M4 ;
      RECT 0.000 137.556 0.018 137.574 ;
    END
  END rd1_out[252]
  PIN rd1_out[253]
    DIRECTION OUTPUT ;
    USE SIGNAL ;
    SHAPE ABUTMENT ;
    PORT
      LAYER M4 ;
      RECT 0.000 137.736 0.018 137.754 ;
    END
  END rd1_out[253]
  PIN rd1_out[254]
    DIRECTION OUTPUT ;
    USE SIGNAL ;
    SHAPE ABUTMENT ;
    PORT
      LAYER M4 ;
      RECT 0.000 137.916 0.018 137.934 ;
    END
  END rd1_out[254]
  PIN rd1_out[255]
    DIRECTION OUTPUT ;
    USE SIGNAL ;
    SHAPE ABUTMENT ;
    PORT
      LAYER M4 ;
      RECT 0.000 138.096 0.018 138.114 ;
    END
  END rd1_out[255]
  PIN rd1_out[256]
    DIRECTION OUTPUT ;
    USE SIGNAL ;
    SHAPE ABUTMENT ;
    PORT
      LAYER M4 ;
      RECT 0.000 138.276 0.018 138.294 ;
    END
  END rd1_out[256]
  PIN rd1_out[257]
    DIRECTION OUTPUT ;
    USE SIGNAL ;
    SHAPE ABUTMENT ;
    PORT
      LAYER M4 ;
      RECT 0.000 138.456 0.018 138.474 ;
    END
  END rd1_out[257]
  PIN rd1_out[258]
    DIRECTION OUTPUT ;
    USE SIGNAL ;
    SHAPE ABUTMENT ;
    PORT
      LAYER M4 ;
      RECT 0.000 138.636 0.018 138.654 ;
    END
  END rd1_out[258]
  PIN rd1_out[259]
    DIRECTION OUTPUT ;
    USE SIGNAL ;
    SHAPE ABUTMENT ;
    PORT
      LAYER M4 ;
      RECT 0.000 138.816 0.018 138.834 ;
    END
  END rd1_out[259]
  PIN rd1_out[260]
    DIRECTION OUTPUT ;
    USE SIGNAL ;
    SHAPE ABUTMENT ;
    PORT
      LAYER M4 ;
      RECT 0.000 138.996 0.018 139.014 ;
    END
  END rd1_out[260]
  PIN rd1_out[261]
    DIRECTION OUTPUT ;
    USE SIGNAL ;
    SHAPE ABUTMENT ;
    PORT
      LAYER M4 ;
      RECT 0.000 139.176 0.018 139.194 ;
    END
  END rd1_out[261]
  PIN rd1_out[262]
    DIRECTION OUTPUT ;
    USE SIGNAL ;
    SHAPE ABUTMENT ;
    PORT
      LAYER M4 ;
      RECT 0.000 139.356 0.018 139.374 ;
    END
  END rd1_out[262]
  PIN rd1_out[263]
    DIRECTION OUTPUT ;
    USE SIGNAL ;
    SHAPE ABUTMENT ;
    PORT
      LAYER M4 ;
      RECT 0.000 139.536 0.018 139.554 ;
    END
  END rd1_out[263]
  PIN rd1_out[264]
    DIRECTION OUTPUT ;
    USE SIGNAL ;
    SHAPE ABUTMENT ;
    PORT
      LAYER M4 ;
      RECT 0.000 139.716 0.018 139.734 ;
    END
  END rd1_out[264]
  PIN rd1_out[265]
    DIRECTION OUTPUT ;
    USE SIGNAL ;
    SHAPE ABUTMENT ;
    PORT
      LAYER M4 ;
      RECT 0.000 139.896 0.018 139.914 ;
    END
  END rd1_out[265]
  PIN rd1_out[266]
    DIRECTION OUTPUT ;
    USE SIGNAL ;
    SHAPE ABUTMENT ;
    PORT
      LAYER M4 ;
      RECT 0.000 140.076 0.018 140.094 ;
    END
  END rd1_out[266]
  PIN rd1_out[267]
    DIRECTION OUTPUT ;
    USE SIGNAL ;
    SHAPE ABUTMENT ;
    PORT
      LAYER M4 ;
      RECT 0.000 140.256 0.018 140.274 ;
    END
  END rd1_out[267]
  PIN rd1_out[268]
    DIRECTION OUTPUT ;
    USE SIGNAL ;
    SHAPE ABUTMENT ;
    PORT
      LAYER M4 ;
      RECT 0.000 140.436 0.018 140.454 ;
    END
  END rd1_out[268]
  PIN rd1_out[269]
    DIRECTION OUTPUT ;
    USE SIGNAL ;
    SHAPE ABUTMENT ;
    PORT
      LAYER M4 ;
      RECT 0.000 140.616 0.018 140.634 ;
    END
  END rd1_out[269]
  PIN rd1_out[270]
    DIRECTION OUTPUT ;
    USE SIGNAL ;
    SHAPE ABUTMENT ;
    PORT
      LAYER M4 ;
      RECT 0.000 140.796 0.018 140.814 ;
    END
  END rd1_out[270]
  PIN rd1_out[271]
    DIRECTION OUTPUT ;
    USE SIGNAL ;
    SHAPE ABUTMENT ;
    PORT
      LAYER M4 ;
      RECT 0.000 140.976 0.018 140.994 ;
    END
  END rd1_out[271]
  PIN rd1_out[272]
    DIRECTION OUTPUT ;
    USE SIGNAL ;
    SHAPE ABUTMENT ;
    PORT
      LAYER M4 ;
      RECT 0.000 141.156 0.018 141.174 ;
    END
  END rd1_out[272]
  PIN rd1_out[273]
    DIRECTION OUTPUT ;
    USE SIGNAL ;
    SHAPE ABUTMENT ;
    PORT
      LAYER M4 ;
      RECT 0.000 141.336 0.018 141.354 ;
    END
  END rd1_out[273]
  PIN rd1_out[274]
    DIRECTION OUTPUT ;
    USE SIGNAL ;
    SHAPE ABUTMENT ;
    PORT
      LAYER M4 ;
      RECT 0.000 141.516 0.018 141.534 ;
    END
  END rd1_out[274]
  PIN rd1_out[275]
    DIRECTION OUTPUT ;
    USE SIGNAL ;
    SHAPE ABUTMENT ;
    PORT
      LAYER M4 ;
      RECT 0.000 141.696 0.018 141.714 ;
    END
  END rd1_out[275]
  PIN rd1_out[276]
    DIRECTION OUTPUT ;
    USE SIGNAL ;
    SHAPE ABUTMENT ;
    PORT
      LAYER M4 ;
      RECT 0.000 141.876 0.018 141.894 ;
    END
  END rd1_out[276]
  PIN rd1_out[277]
    DIRECTION OUTPUT ;
    USE SIGNAL ;
    SHAPE ABUTMENT ;
    PORT
      LAYER M4 ;
      RECT 0.000 142.056 0.018 142.074 ;
    END
  END rd1_out[277]
  PIN rd1_out[278]
    DIRECTION OUTPUT ;
    USE SIGNAL ;
    SHAPE ABUTMENT ;
    PORT
      LAYER M4 ;
      RECT 0.000 142.236 0.018 142.254 ;
    END
  END rd1_out[278]
  PIN rd1_out[279]
    DIRECTION OUTPUT ;
    USE SIGNAL ;
    SHAPE ABUTMENT ;
    PORT
      LAYER M4 ;
      RECT 0.000 142.416 0.018 142.434 ;
    END
  END rd1_out[279]
  PIN rd1_out[280]
    DIRECTION OUTPUT ;
    USE SIGNAL ;
    SHAPE ABUTMENT ;
    PORT
      LAYER M4 ;
      RECT 0.000 142.596 0.018 142.614 ;
    END
  END rd1_out[280]
  PIN rd1_out[281]
    DIRECTION OUTPUT ;
    USE SIGNAL ;
    SHAPE ABUTMENT ;
    PORT
      LAYER M4 ;
      RECT 0.000 142.776 0.018 142.794 ;
    END
  END rd1_out[281]
  PIN rd1_out[282]
    DIRECTION OUTPUT ;
    USE SIGNAL ;
    SHAPE ABUTMENT ;
    PORT
      LAYER M4 ;
      RECT 0.000 142.956 0.018 142.974 ;
    END
  END rd1_out[282]
  PIN rd1_out[283]
    DIRECTION OUTPUT ;
    USE SIGNAL ;
    SHAPE ABUTMENT ;
    PORT
      LAYER M4 ;
      RECT 0.000 143.136 0.018 143.154 ;
    END
  END rd1_out[283]
  PIN rd1_out[284]
    DIRECTION OUTPUT ;
    USE SIGNAL ;
    SHAPE ABUTMENT ;
    PORT
      LAYER M4 ;
      RECT 0.000 143.316 0.018 143.334 ;
    END
  END rd1_out[284]
  PIN rd1_out[285]
    DIRECTION OUTPUT ;
    USE SIGNAL ;
    SHAPE ABUTMENT ;
    PORT
      LAYER M4 ;
      RECT 0.000 143.496 0.018 143.514 ;
    END
  END rd1_out[285]
  PIN rd1_out[286]
    DIRECTION OUTPUT ;
    USE SIGNAL ;
    SHAPE ABUTMENT ;
    PORT
      LAYER M4 ;
      RECT 0.000 143.676 0.018 143.694 ;
    END
  END rd1_out[286]
  PIN rd1_out[287]
    DIRECTION OUTPUT ;
    USE SIGNAL ;
    SHAPE ABUTMENT ;
    PORT
      LAYER M4 ;
      RECT 0.000 143.856 0.018 143.874 ;
    END
  END rd1_out[287]
  PIN rd1_out[288]
    DIRECTION OUTPUT ;
    USE SIGNAL ;
    SHAPE ABUTMENT ;
    PORT
      LAYER M4 ;
      RECT 0.000 144.036 0.018 144.054 ;
    END
  END rd1_out[288]
  PIN rd1_out[289]
    DIRECTION OUTPUT ;
    USE SIGNAL ;
    SHAPE ABUTMENT ;
    PORT
      LAYER M4 ;
      RECT 0.000 144.216 0.018 144.234 ;
    END
  END rd1_out[289]
  PIN rd1_out[290]
    DIRECTION OUTPUT ;
    USE SIGNAL ;
    SHAPE ABUTMENT ;
    PORT
      LAYER M4 ;
      RECT 0.000 144.396 0.018 144.414 ;
    END
  END rd1_out[290]
  PIN rd1_out[291]
    DIRECTION OUTPUT ;
    USE SIGNAL ;
    SHAPE ABUTMENT ;
    PORT
      LAYER M4 ;
      RECT 0.000 144.576 0.018 144.594 ;
    END
  END rd1_out[291]
  PIN rd1_out[292]
    DIRECTION OUTPUT ;
    USE SIGNAL ;
    SHAPE ABUTMENT ;
    PORT
      LAYER M4 ;
      RECT 0.000 144.756 0.018 144.774 ;
    END
  END rd1_out[292]
  PIN rd1_out[293]
    DIRECTION OUTPUT ;
    USE SIGNAL ;
    SHAPE ABUTMENT ;
    PORT
      LAYER M4 ;
      RECT 0.000 144.936 0.018 144.954 ;
    END
  END rd1_out[293]
  PIN rd1_out[294]
    DIRECTION OUTPUT ;
    USE SIGNAL ;
    SHAPE ABUTMENT ;
    PORT
      LAYER M4 ;
      RECT 0.000 145.116 0.018 145.134 ;
    END
  END rd1_out[294]
  PIN rd1_out[295]
    DIRECTION OUTPUT ;
    USE SIGNAL ;
    SHAPE ABUTMENT ;
    PORT
      LAYER M4 ;
      RECT 0.000 145.296 0.018 145.314 ;
    END
  END rd1_out[295]
  PIN rd1_out[296]
    DIRECTION OUTPUT ;
    USE SIGNAL ;
    SHAPE ABUTMENT ;
    PORT
      LAYER M4 ;
      RECT 0.000 145.476 0.018 145.494 ;
    END
  END rd1_out[296]
  PIN rd1_out[297]
    DIRECTION OUTPUT ;
    USE SIGNAL ;
    SHAPE ABUTMENT ;
    PORT
      LAYER M4 ;
      RECT 0.000 145.656 0.018 145.674 ;
    END
  END rd1_out[297]
  PIN rd1_out[298]
    DIRECTION OUTPUT ;
    USE SIGNAL ;
    SHAPE ABUTMENT ;
    PORT
      LAYER M4 ;
      RECT 0.000 145.836 0.018 145.854 ;
    END
  END rd1_out[298]
  PIN rd1_out[299]
    DIRECTION OUTPUT ;
    USE SIGNAL ;
    SHAPE ABUTMENT ;
    PORT
      LAYER M4 ;
      RECT 0.000 146.016 0.018 146.034 ;
    END
  END rd1_out[299]
  PIN rd1_out[300]
    DIRECTION OUTPUT ;
    USE SIGNAL ;
    SHAPE ABUTMENT ;
    PORT
      LAYER M4 ;
      RECT 0.000 146.196 0.018 146.214 ;
    END
  END rd1_out[300]
  PIN rd1_out[301]
    DIRECTION OUTPUT ;
    USE SIGNAL ;
    SHAPE ABUTMENT ;
    PORT
      LAYER M4 ;
      RECT 0.000 146.376 0.018 146.394 ;
    END
  END rd1_out[301]
  PIN rd1_out[302]
    DIRECTION OUTPUT ;
    USE SIGNAL ;
    SHAPE ABUTMENT ;
    PORT
      LAYER M4 ;
      RECT 0.000 146.556 0.018 146.574 ;
    END
  END rd1_out[302]
  PIN rd1_out[303]
    DIRECTION OUTPUT ;
    USE SIGNAL ;
    SHAPE ABUTMENT ;
    PORT
      LAYER M4 ;
      RECT 0.000 146.736 0.018 146.754 ;
    END
  END rd1_out[303]
  PIN rd1_out[304]
    DIRECTION OUTPUT ;
    USE SIGNAL ;
    SHAPE ABUTMENT ;
    PORT
      LAYER M4 ;
      RECT 0.000 146.916 0.018 146.934 ;
    END
  END rd1_out[304]
  PIN rd1_out[305]
    DIRECTION OUTPUT ;
    USE SIGNAL ;
    SHAPE ABUTMENT ;
    PORT
      LAYER M4 ;
      RECT 0.000 147.096 0.018 147.114 ;
    END
  END rd1_out[305]
  PIN rd1_out[306]
    DIRECTION OUTPUT ;
    USE SIGNAL ;
    SHAPE ABUTMENT ;
    PORT
      LAYER M4 ;
      RECT 0.000 147.276 0.018 147.294 ;
    END
  END rd1_out[306]
  PIN rd1_out[307]
    DIRECTION OUTPUT ;
    USE SIGNAL ;
    SHAPE ABUTMENT ;
    PORT
      LAYER M4 ;
      RECT 0.000 147.456 0.018 147.474 ;
    END
  END rd1_out[307]
  PIN rd1_out[308]
    DIRECTION OUTPUT ;
    USE SIGNAL ;
    SHAPE ABUTMENT ;
    PORT
      LAYER M4 ;
      RECT 0.000 147.636 0.018 147.654 ;
    END
  END rd1_out[308]
  PIN rd1_out[309]
    DIRECTION OUTPUT ;
    USE SIGNAL ;
    SHAPE ABUTMENT ;
    PORT
      LAYER M4 ;
      RECT 0.000 147.816 0.018 147.834 ;
    END
  END rd1_out[309]
  PIN rd1_out[310]
    DIRECTION OUTPUT ;
    USE SIGNAL ;
    SHAPE ABUTMENT ;
    PORT
      LAYER M4 ;
      RECT 0.000 147.996 0.018 148.014 ;
    END
  END rd1_out[310]
  PIN rd1_out[311]
    DIRECTION OUTPUT ;
    USE SIGNAL ;
    SHAPE ABUTMENT ;
    PORT
      LAYER M4 ;
      RECT 0.000 148.176 0.018 148.194 ;
    END
  END rd1_out[311]
  PIN rd1_out[312]
    DIRECTION OUTPUT ;
    USE SIGNAL ;
    SHAPE ABUTMENT ;
    PORT
      LAYER M4 ;
      RECT 0.000 148.356 0.018 148.374 ;
    END
  END rd1_out[312]
  PIN rd1_out[313]
    DIRECTION OUTPUT ;
    USE SIGNAL ;
    SHAPE ABUTMENT ;
    PORT
      LAYER M4 ;
      RECT 0.000 148.536 0.018 148.554 ;
    END
  END rd1_out[313]
  PIN rd1_out[314]
    DIRECTION OUTPUT ;
    USE SIGNAL ;
    SHAPE ABUTMENT ;
    PORT
      LAYER M4 ;
      RECT 0.000 148.716 0.018 148.734 ;
    END
  END rd1_out[314]
  PIN rd1_out[315]
    DIRECTION OUTPUT ;
    USE SIGNAL ;
    SHAPE ABUTMENT ;
    PORT
      LAYER M4 ;
      RECT 0.000 148.896 0.018 148.914 ;
    END
  END rd1_out[315]
  PIN rd1_out[316]
    DIRECTION OUTPUT ;
    USE SIGNAL ;
    SHAPE ABUTMENT ;
    PORT
      LAYER M4 ;
      RECT 0.000 149.076 0.018 149.094 ;
    END
  END rd1_out[316]
  PIN rd1_out[317]
    DIRECTION OUTPUT ;
    USE SIGNAL ;
    SHAPE ABUTMENT ;
    PORT
      LAYER M4 ;
      RECT 0.000 149.256 0.018 149.274 ;
    END
  END rd1_out[317]
  PIN rd1_out[318]
    DIRECTION OUTPUT ;
    USE SIGNAL ;
    SHAPE ABUTMENT ;
    PORT
      LAYER M4 ;
      RECT 0.000 149.436 0.018 149.454 ;
    END
  END rd1_out[318]
  PIN rd1_out[319]
    DIRECTION OUTPUT ;
    USE SIGNAL ;
    SHAPE ABUTMENT ;
    PORT
      LAYER M4 ;
      RECT 0.000 149.616 0.018 149.634 ;
    END
  END rd1_out[319]
  PIN rd1_out[320]
    DIRECTION OUTPUT ;
    USE SIGNAL ;
    SHAPE ABUTMENT ;
    PORT
      LAYER M4 ;
      RECT 0.000 149.796 0.018 149.814 ;
    END
  END rd1_out[320]
  PIN rd1_out[321]
    DIRECTION OUTPUT ;
    USE SIGNAL ;
    SHAPE ABUTMENT ;
    PORT
      LAYER M4 ;
      RECT 0.000 149.976 0.018 149.994 ;
    END
  END rd1_out[321]
  PIN rd1_out[322]
    DIRECTION OUTPUT ;
    USE SIGNAL ;
    SHAPE ABUTMENT ;
    PORT
      LAYER M4 ;
      RECT 0.000 150.156 0.018 150.174 ;
    END
  END rd1_out[322]
  PIN rd1_out[323]
    DIRECTION OUTPUT ;
    USE SIGNAL ;
    SHAPE ABUTMENT ;
    PORT
      LAYER M4 ;
      RECT 0.000 150.336 0.018 150.354 ;
    END
  END rd1_out[323]
  PIN rd1_out[324]
    DIRECTION OUTPUT ;
    USE SIGNAL ;
    SHAPE ABUTMENT ;
    PORT
      LAYER M4 ;
      RECT 0.000 150.516 0.018 150.534 ;
    END
  END rd1_out[324]
  PIN rd1_out[325]
    DIRECTION OUTPUT ;
    USE SIGNAL ;
    SHAPE ABUTMENT ;
    PORT
      LAYER M4 ;
      RECT 0.000 150.696 0.018 150.714 ;
    END
  END rd1_out[325]
  PIN rd1_out[326]
    DIRECTION OUTPUT ;
    USE SIGNAL ;
    SHAPE ABUTMENT ;
    PORT
      LAYER M4 ;
      RECT 0.000 150.876 0.018 150.894 ;
    END
  END rd1_out[326]
  PIN rd1_out[327]
    DIRECTION OUTPUT ;
    USE SIGNAL ;
    SHAPE ABUTMENT ;
    PORT
      LAYER M4 ;
      RECT 0.000 151.056 0.018 151.074 ;
    END
  END rd1_out[327]
  PIN rd1_out[328]
    DIRECTION OUTPUT ;
    USE SIGNAL ;
    SHAPE ABUTMENT ;
    PORT
      LAYER M4 ;
      RECT 0.000 151.236 0.018 151.254 ;
    END
  END rd1_out[328]
  PIN rd1_out[329]
    DIRECTION OUTPUT ;
    USE SIGNAL ;
    SHAPE ABUTMENT ;
    PORT
      LAYER M4 ;
      RECT 0.000 151.416 0.018 151.434 ;
    END
  END rd1_out[329]
  PIN rd1_out[330]
    DIRECTION OUTPUT ;
    USE SIGNAL ;
    SHAPE ABUTMENT ;
    PORT
      LAYER M4 ;
      RECT 0.000 151.596 0.018 151.614 ;
    END
  END rd1_out[330]
  PIN rd1_out[331]
    DIRECTION OUTPUT ;
    USE SIGNAL ;
    SHAPE ABUTMENT ;
    PORT
      LAYER M4 ;
      RECT 0.000 151.776 0.018 151.794 ;
    END
  END rd1_out[331]
  PIN rd1_out[332]
    DIRECTION OUTPUT ;
    USE SIGNAL ;
    SHAPE ABUTMENT ;
    PORT
      LAYER M4 ;
      RECT 0.000 151.956 0.018 151.974 ;
    END
  END rd1_out[332]
  PIN rd1_out[333]
    DIRECTION OUTPUT ;
    USE SIGNAL ;
    SHAPE ABUTMENT ;
    PORT
      LAYER M4 ;
      RECT 0.000 152.136 0.018 152.154 ;
    END
  END rd1_out[333]
  PIN rd1_out[334]
    DIRECTION OUTPUT ;
    USE SIGNAL ;
    SHAPE ABUTMENT ;
    PORT
      LAYER M4 ;
      RECT 0.000 152.316 0.018 152.334 ;
    END
  END rd1_out[334]
  PIN rd1_out[335]
    DIRECTION OUTPUT ;
    USE SIGNAL ;
    SHAPE ABUTMENT ;
    PORT
      LAYER M4 ;
      RECT 0.000 152.496 0.018 152.514 ;
    END
  END rd1_out[335]
  PIN rd1_out[336]
    DIRECTION OUTPUT ;
    USE SIGNAL ;
    SHAPE ABUTMENT ;
    PORT
      LAYER M4 ;
      RECT 0.000 152.676 0.018 152.694 ;
    END
  END rd1_out[336]
  PIN rd1_out[337]
    DIRECTION OUTPUT ;
    USE SIGNAL ;
    SHAPE ABUTMENT ;
    PORT
      LAYER M4 ;
      RECT 0.000 152.856 0.018 152.874 ;
    END
  END rd1_out[337]
  PIN rd1_out[338]
    DIRECTION OUTPUT ;
    USE SIGNAL ;
    SHAPE ABUTMENT ;
    PORT
      LAYER M4 ;
      RECT 0.000 153.036 0.018 153.054 ;
    END
  END rd1_out[338]
  PIN rd1_out[339]
    DIRECTION OUTPUT ;
    USE SIGNAL ;
    SHAPE ABUTMENT ;
    PORT
      LAYER M4 ;
      RECT 0.000 153.216 0.018 153.234 ;
    END
  END rd1_out[339]
  PIN rd1_out[340]
    DIRECTION OUTPUT ;
    USE SIGNAL ;
    SHAPE ABUTMENT ;
    PORT
      LAYER M4 ;
      RECT 0.000 153.396 0.018 153.414 ;
    END
  END rd1_out[340]
  PIN rd1_out[341]
    DIRECTION OUTPUT ;
    USE SIGNAL ;
    SHAPE ABUTMENT ;
    PORT
      LAYER M4 ;
      RECT 0.000 153.576 0.018 153.594 ;
    END
  END rd1_out[341]
  PIN rd1_out[342]
    DIRECTION OUTPUT ;
    USE SIGNAL ;
    SHAPE ABUTMENT ;
    PORT
      LAYER M4 ;
      RECT 0.000 153.756 0.018 153.774 ;
    END
  END rd1_out[342]
  PIN rd1_out[343]
    DIRECTION OUTPUT ;
    USE SIGNAL ;
    SHAPE ABUTMENT ;
    PORT
      LAYER M4 ;
      RECT 0.000 153.936 0.018 153.954 ;
    END
  END rd1_out[343]
  PIN rd1_out[344]
    DIRECTION OUTPUT ;
    USE SIGNAL ;
    SHAPE ABUTMENT ;
    PORT
      LAYER M4 ;
      RECT 0.000 154.116 0.018 154.134 ;
    END
  END rd1_out[344]
  PIN rd1_out[345]
    DIRECTION OUTPUT ;
    USE SIGNAL ;
    SHAPE ABUTMENT ;
    PORT
      LAYER M4 ;
      RECT 0.000 154.296 0.018 154.314 ;
    END
  END rd1_out[345]
  PIN rd1_out[346]
    DIRECTION OUTPUT ;
    USE SIGNAL ;
    SHAPE ABUTMENT ;
    PORT
      LAYER M4 ;
      RECT 0.000 154.476 0.018 154.494 ;
    END
  END rd1_out[346]
  PIN rd1_out[347]
    DIRECTION OUTPUT ;
    USE SIGNAL ;
    SHAPE ABUTMENT ;
    PORT
      LAYER M4 ;
      RECT 0.000 154.656 0.018 154.674 ;
    END
  END rd1_out[347]
  PIN rd1_out[348]
    DIRECTION OUTPUT ;
    USE SIGNAL ;
    SHAPE ABUTMENT ;
    PORT
      LAYER M4 ;
      RECT 0.000 154.836 0.018 154.854 ;
    END
  END rd1_out[348]
  PIN rd1_out[349]
    DIRECTION OUTPUT ;
    USE SIGNAL ;
    SHAPE ABUTMENT ;
    PORT
      LAYER M4 ;
      RECT 0.000 155.016 0.018 155.034 ;
    END
  END rd1_out[349]
  PIN rd1_out[350]
    DIRECTION OUTPUT ;
    USE SIGNAL ;
    SHAPE ABUTMENT ;
    PORT
      LAYER M4 ;
      RECT 0.000 155.196 0.018 155.214 ;
    END
  END rd1_out[350]
  PIN rd1_out[351]
    DIRECTION OUTPUT ;
    USE SIGNAL ;
    SHAPE ABUTMENT ;
    PORT
      LAYER M4 ;
      RECT 0.000 155.376 0.018 155.394 ;
    END
  END rd1_out[351]
  PIN rd1_out[352]
    DIRECTION OUTPUT ;
    USE SIGNAL ;
    SHAPE ABUTMENT ;
    PORT
      LAYER M4 ;
      RECT 0.000 155.556 0.018 155.574 ;
    END
  END rd1_out[352]
  PIN rd1_out[353]
    DIRECTION OUTPUT ;
    USE SIGNAL ;
    SHAPE ABUTMENT ;
    PORT
      LAYER M4 ;
      RECT 0.000 155.736 0.018 155.754 ;
    END
  END rd1_out[353]
  PIN rd1_out[354]
    DIRECTION OUTPUT ;
    USE SIGNAL ;
    SHAPE ABUTMENT ;
    PORT
      LAYER M4 ;
      RECT 0.000 155.916 0.018 155.934 ;
    END
  END rd1_out[354]
  PIN rd1_out[355]
    DIRECTION OUTPUT ;
    USE SIGNAL ;
    SHAPE ABUTMENT ;
    PORT
      LAYER M4 ;
      RECT 0.000 156.096 0.018 156.114 ;
    END
  END rd1_out[355]
  PIN rd1_out[356]
    DIRECTION OUTPUT ;
    USE SIGNAL ;
    SHAPE ABUTMENT ;
    PORT
      LAYER M4 ;
      RECT 0.000 156.276 0.018 156.294 ;
    END
  END rd1_out[356]
  PIN rd1_out[357]
    DIRECTION OUTPUT ;
    USE SIGNAL ;
    SHAPE ABUTMENT ;
    PORT
      LAYER M4 ;
      RECT 0.000 156.456 0.018 156.474 ;
    END
  END rd1_out[357]
  PIN rd1_out[358]
    DIRECTION OUTPUT ;
    USE SIGNAL ;
    SHAPE ABUTMENT ;
    PORT
      LAYER M4 ;
      RECT 0.000 156.636 0.018 156.654 ;
    END
  END rd1_out[358]
  PIN rd1_out[359]
    DIRECTION OUTPUT ;
    USE SIGNAL ;
    SHAPE ABUTMENT ;
    PORT
      LAYER M4 ;
      RECT 0.000 156.816 0.018 156.834 ;
    END
  END rd1_out[359]
  PIN rd1_out[360]
    DIRECTION OUTPUT ;
    USE SIGNAL ;
    SHAPE ABUTMENT ;
    PORT
      LAYER M4 ;
      RECT 0.000 156.996 0.018 157.014 ;
    END
  END rd1_out[360]
  PIN rd1_out[361]
    DIRECTION OUTPUT ;
    USE SIGNAL ;
    SHAPE ABUTMENT ;
    PORT
      LAYER M4 ;
      RECT 0.000 157.176 0.018 157.194 ;
    END
  END rd1_out[361]
  PIN rd1_out[362]
    DIRECTION OUTPUT ;
    USE SIGNAL ;
    SHAPE ABUTMENT ;
    PORT
      LAYER M4 ;
      RECT 0.000 157.356 0.018 157.374 ;
    END
  END rd1_out[362]
  PIN rd1_out[363]
    DIRECTION OUTPUT ;
    USE SIGNAL ;
    SHAPE ABUTMENT ;
    PORT
      LAYER M4 ;
      RECT 0.000 157.536 0.018 157.554 ;
    END
  END rd1_out[363]
  PIN rd1_out[364]
    DIRECTION OUTPUT ;
    USE SIGNAL ;
    SHAPE ABUTMENT ;
    PORT
      LAYER M4 ;
      RECT 0.000 157.716 0.018 157.734 ;
    END
  END rd1_out[364]
  PIN rd1_out[365]
    DIRECTION OUTPUT ;
    USE SIGNAL ;
    SHAPE ABUTMENT ;
    PORT
      LAYER M4 ;
      RECT 0.000 157.896 0.018 157.914 ;
    END
  END rd1_out[365]
  PIN rd1_out[366]
    DIRECTION OUTPUT ;
    USE SIGNAL ;
    SHAPE ABUTMENT ;
    PORT
      LAYER M4 ;
      RECT 0.000 158.076 0.018 158.094 ;
    END
  END rd1_out[366]
  PIN rd1_out[367]
    DIRECTION OUTPUT ;
    USE SIGNAL ;
    SHAPE ABUTMENT ;
    PORT
      LAYER M4 ;
      RECT 0.000 158.256 0.018 158.274 ;
    END
  END rd1_out[367]
  PIN rd1_out[368]
    DIRECTION OUTPUT ;
    USE SIGNAL ;
    SHAPE ABUTMENT ;
    PORT
      LAYER M4 ;
      RECT 0.000 158.436 0.018 158.454 ;
    END
  END rd1_out[368]
  PIN rd1_out[369]
    DIRECTION OUTPUT ;
    USE SIGNAL ;
    SHAPE ABUTMENT ;
    PORT
      LAYER M4 ;
      RECT 0.000 158.616 0.018 158.634 ;
    END
  END rd1_out[369]
  PIN rd1_out[370]
    DIRECTION OUTPUT ;
    USE SIGNAL ;
    SHAPE ABUTMENT ;
    PORT
      LAYER M4 ;
      RECT 0.000 158.796 0.018 158.814 ;
    END
  END rd1_out[370]
  PIN rd1_out[371]
    DIRECTION OUTPUT ;
    USE SIGNAL ;
    SHAPE ABUTMENT ;
    PORT
      LAYER M4 ;
      RECT 0.000 158.976 0.018 158.994 ;
    END
  END rd1_out[371]
  PIN rd1_out[372]
    DIRECTION OUTPUT ;
    USE SIGNAL ;
    SHAPE ABUTMENT ;
    PORT
      LAYER M4 ;
      RECT 0.000 159.156 0.018 159.174 ;
    END
  END rd1_out[372]
  PIN rd1_out[373]
    DIRECTION OUTPUT ;
    USE SIGNAL ;
    SHAPE ABUTMENT ;
    PORT
      LAYER M4 ;
      RECT 0.000 159.336 0.018 159.354 ;
    END
  END rd1_out[373]
  PIN rd1_out[374]
    DIRECTION OUTPUT ;
    USE SIGNAL ;
    SHAPE ABUTMENT ;
    PORT
      LAYER M4 ;
      RECT 0.000 159.516 0.018 159.534 ;
    END
  END rd1_out[374]
  PIN rd1_out[375]
    DIRECTION OUTPUT ;
    USE SIGNAL ;
    SHAPE ABUTMENT ;
    PORT
      LAYER M4 ;
      RECT 0.000 159.696 0.018 159.714 ;
    END
  END rd1_out[375]
  PIN rd1_out[376]
    DIRECTION OUTPUT ;
    USE SIGNAL ;
    SHAPE ABUTMENT ;
    PORT
      LAYER M4 ;
      RECT 0.000 159.876 0.018 159.894 ;
    END
  END rd1_out[376]
  PIN rd1_out[377]
    DIRECTION OUTPUT ;
    USE SIGNAL ;
    SHAPE ABUTMENT ;
    PORT
      LAYER M4 ;
      RECT 0.000 160.056 0.018 160.074 ;
    END
  END rd1_out[377]
  PIN rd1_out[378]
    DIRECTION OUTPUT ;
    USE SIGNAL ;
    SHAPE ABUTMENT ;
    PORT
      LAYER M4 ;
      RECT 0.000 160.236 0.018 160.254 ;
    END
  END rd1_out[378]
  PIN rd1_out[379]
    DIRECTION OUTPUT ;
    USE SIGNAL ;
    SHAPE ABUTMENT ;
    PORT
      LAYER M4 ;
      RECT 0.000 160.416 0.018 160.434 ;
    END
  END rd1_out[379]
  PIN rd1_out[380]
    DIRECTION OUTPUT ;
    USE SIGNAL ;
    SHAPE ABUTMENT ;
    PORT
      LAYER M4 ;
      RECT 0.000 160.596 0.018 160.614 ;
    END
  END rd1_out[380]
  PIN rd1_out[381]
    DIRECTION OUTPUT ;
    USE SIGNAL ;
    SHAPE ABUTMENT ;
    PORT
      LAYER M4 ;
      RECT 0.000 160.776 0.018 160.794 ;
    END
  END rd1_out[381]
  PIN rd1_out[382]
    DIRECTION OUTPUT ;
    USE SIGNAL ;
    SHAPE ABUTMENT ;
    PORT
      LAYER M4 ;
      RECT 0.000 160.956 0.018 160.974 ;
    END
  END rd1_out[382]
  PIN rd1_out[383]
    DIRECTION OUTPUT ;
    USE SIGNAL ;
    SHAPE ABUTMENT ;
    PORT
      LAYER M4 ;
      RECT 0.000 161.136 0.018 161.154 ;
    END
  END rd1_out[383]
  PIN rd1_out[384]
    DIRECTION OUTPUT ;
    USE SIGNAL ;
    SHAPE ABUTMENT ;
    PORT
      LAYER M4 ;
      RECT 0.000 161.316 0.018 161.334 ;
    END
  END rd1_out[384]
  PIN rd1_out[385]
    DIRECTION OUTPUT ;
    USE SIGNAL ;
    SHAPE ABUTMENT ;
    PORT
      LAYER M4 ;
      RECT 0.000 161.496 0.018 161.514 ;
    END
  END rd1_out[385]
  PIN rd1_out[386]
    DIRECTION OUTPUT ;
    USE SIGNAL ;
    SHAPE ABUTMENT ;
    PORT
      LAYER M4 ;
      RECT 0.000 161.676 0.018 161.694 ;
    END
  END rd1_out[386]
  PIN rd1_out[387]
    DIRECTION OUTPUT ;
    USE SIGNAL ;
    SHAPE ABUTMENT ;
    PORT
      LAYER M4 ;
      RECT 0.000 161.856 0.018 161.874 ;
    END
  END rd1_out[387]
  PIN rd1_out[388]
    DIRECTION OUTPUT ;
    USE SIGNAL ;
    SHAPE ABUTMENT ;
    PORT
      LAYER M4 ;
      RECT 0.000 162.036 0.018 162.054 ;
    END
  END rd1_out[388]
  PIN rd1_out[389]
    DIRECTION OUTPUT ;
    USE SIGNAL ;
    SHAPE ABUTMENT ;
    PORT
      LAYER M4 ;
      RECT 0.000 162.216 0.018 162.234 ;
    END
  END rd1_out[389]
  PIN rd1_out[390]
    DIRECTION OUTPUT ;
    USE SIGNAL ;
    SHAPE ABUTMENT ;
    PORT
      LAYER M4 ;
      RECT 0.000 162.396 0.018 162.414 ;
    END
  END rd1_out[390]
  PIN rd1_out[391]
    DIRECTION OUTPUT ;
    USE SIGNAL ;
    SHAPE ABUTMENT ;
    PORT
      LAYER M4 ;
      RECT 0.000 162.576 0.018 162.594 ;
    END
  END rd1_out[391]
  PIN rd1_out[392]
    DIRECTION OUTPUT ;
    USE SIGNAL ;
    SHAPE ABUTMENT ;
    PORT
      LAYER M4 ;
      RECT 0.000 162.756 0.018 162.774 ;
    END
  END rd1_out[392]
  PIN rd1_out[393]
    DIRECTION OUTPUT ;
    USE SIGNAL ;
    SHAPE ABUTMENT ;
    PORT
      LAYER M4 ;
      RECT 0.000 162.936 0.018 162.954 ;
    END
  END rd1_out[393]
  PIN rd1_out[394]
    DIRECTION OUTPUT ;
    USE SIGNAL ;
    SHAPE ABUTMENT ;
    PORT
      LAYER M4 ;
      RECT 0.000 163.116 0.018 163.134 ;
    END
  END rd1_out[394]
  PIN rd1_out[395]
    DIRECTION OUTPUT ;
    USE SIGNAL ;
    SHAPE ABUTMENT ;
    PORT
      LAYER M4 ;
      RECT 0.000 163.296 0.018 163.314 ;
    END
  END rd1_out[395]
  PIN rd1_out[396]
    DIRECTION OUTPUT ;
    USE SIGNAL ;
    SHAPE ABUTMENT ;
    PORT
      LAYER M4 ;
      RECT 0.000 163.476 0.018 163.494 ;
    END
  END rd1_out[396]
  PIN rd1_out[397]
    DIRECTION OUTPUT ;
    USE SIGNAL ;
    SHAPE ABUTMENT ;
    PORT
      LAYER M4 ;
      RECT 0.000 163.656 0.018 163.674 ;
    END
  END rd1_out[397]
  PIN rd1_out[398]
    DIRECTION OUTPUT ;
    USE SIGNAL ;
    SHAPE ABUTMENT ;
    PORT
      LAYER M4 ;
      RECT 0.000 163.836 0.018 163.854 ;
    END
  END rd1_out[398]
  PIN rd1_out[399]
    DIRECTION OUTPUT ;
    USE SIGNAL ;
    SHAPE ABUTMENT ;
    PORT
      LAYER M4 ;
      RECT 0.000 164.016 0.018 164.034 ;
    END
  END rd1_out[399]
  PIN rd1_out[400]
    DIRECTION OUTPUT ;
    USE SIGNAL ;
    SHAPE ABUTMENT ;
    PORT
      LAYER M4 ;
      RECT 0.000 164.196 0.018 164.214 ;
    END
  END rd1_out[400]
  PIN rd1_out[401]
    DIRECTION OUTPUT ;
    USE SIGNAL ;
    SHAPE ABUTMENT ;
    PORT
      LAYER M4 ;
      RECT 0.000 164.376 0.018 164.394 ;
    END
  END rd1_out[401]
  PIN rd1_out[402]
    DIRECTION OUTPUT ;
    USE SIGNAL ;
    SHAPE ABUTMENT ;
    PORT
      LAYER M4 ;
      RECT 0.000 164.556 0.018 164.574 ;
    END
  END rd1_out[402]
  PIN rd1_out[403]
    DIRECTION OUTPUT ;
    USE SIGNAL ;
    SHAPE ABUTMENT ;
    PORT
      LAYER M4 ;
      RECT 0.000 164.736 0.018 164.754 ;
    END
  END rd1_out[403]
  PIN rd1_out[404]
    DIRECTION OUTPUT ;
    USE SIGNAL ;
    SHAPE ABUTMENT ;
    PORT
      LAYER M4 ;
      RECT 0.000 164.916 0.018 164.934 ;
    END
  END rd1_out[404]
  PIN rd1_out[405]
    DIRECTION OUTPUT ;
    USE SIGNAL ;
    SHAPE ABUTMENT ;
    PORT
      LAYER M4 ;
      RECT 0.000 165.096 0.018 165.114 ;
    END
  END rd1_out[405]
  PIN rd1_out[406]
    DIRECTION OUTPUT ;
    USE SIGNAL ;
    SHAPE ABUTMENT ;
    PORT
      LAYER M4 ;
      RECT 0.000 165.276 0.018 165.294 ;
    END
  END rd1_out[406]
  PIN rd1_out[407]
    DIRECTION OUTPUT ;
    USE SIGNAL ;
    SHAPE ABUTMENT ;
    PORT
      LAYER M4 ;
      RECT 0.000 165.456 0.018 165.474 ;
    END
  END rd1_out[407]
  PIN rd1_out[408]
    DIRECTION OUTPUT ;
    USE SIGNAL ;
    SHAPE ABUTMENT ;
    PORT
      LAYER M4 ;
      RECT 0.000 165.636 0.018 165.654 ;
    END
  END rd1_out[408]
  PIN rd1_out[409]
    DIRECTION OUTPUT ;
    USE SIGNAL ;
    SHAPE ABUTMENT ;
    PORT
      LAYER M4 ;
      RECT 0.000 165.816 0.018 165.834 ;
    END
  END rd1_out[409]
  PIN rd1_out[410]
    DIRECTION OUTPUT ;
    USE SIGNAL ;
    SHAPE ABUTMENT ;
    PORT
      LAYER M4 ;
      RECT 0.000 165.996 0.018 166.014 ;
    END
  END rd1_out[410]
  PIN rd1_out[411]
    DIRECTION OUTPUT ;
    USE SIGNAL ;
    SHAPE ABUTMENT ;
    PORT
      LAYER M4 ;
      RECT 0.000 166.176 0.018 166.194 ;
    END
  END rd1_out[411]
  PIN rd1_out[412]
    DIRECTION OUTPUT ;
    USE SIGNAL ;
    SHAPE ABUTMENT ;
    PORT
      LAYER M4 ;
      RECT 0.000 166.356 0.018 166.374 ;
    END
  END rd1_out[412]
  PIN rd1_out[413]
    DIRECTION OUTPUT ;
    USE SIGNAL ;
    SHAPE ABUTMENT ;
    PORT
      LAYER M4 ;
      RECT 0.000 166.536 0.018 166.554 ;
    END
  END rd1_out[413]
  PIN rd1_out[414]
    DIRECTION OUTPUT ;
    USE SIGNAL ;
    SHAPE ABUTMENT ;
    PORT
      LAYER M4 ;
      RECT 0.000 166.716 0.018 166.734 ;
    END
  END rd1_out[414]
  PIN rd1_out[415]
    DIRECTION OUTPUT ;
    USE SIGNAL ;
    SHAPE ABUTMENT ;
    PORT
      LAYER M4 ;
      RECT 0.000 166.896 0.018 166.914 ;
    END
  END rd1_out[415]
  PIN rd1_out[416]
    DIRECTION OUTPUT ;
    USE SIGNAL ;
    SHAPE ABUTMENT ;
    PORT
      LAYER M4 ;
      RECT 0.000 167.076 0.018 167.094 ;
    END
  END rd1_out[416]
  PIN rd1_out[417]
    DIRECTION OUTPUT ;
    USE SIGNAL ;
    SHAPE ABUTMENT ;
    PORT
      LAYER M4 ;
      RECT 0.000 167.256 0.018 167.274 ;
    END
  END rd1_out[417]
  PIN rd1_out[418]
    DIRECTION OUTPUT ;
    USE SIGNAL ;
    SHAPE ABUTMENT ;
    PORT
      LAYER M4 ;
      RECT 0.000 167.436 0.018 167.454 ;
    END
  END rd1_out[418]
  PIN rd1_out[419]
    DIRECTION OUTPUT ;
    USE SIGNAL ;
    SHAPE ABUTMENT ;
    PORT
      LAYER M4 ;
      RECT 0.000 167.616 0.018 167.634 ;
    END
  END rd1_out[419]
  PIN rd1_out[420]
    DIRECTION OUTPUT ;
    USE SIGNAL ;
    SHAPE ABUTMENT ;
    PORT
      LAYER M4 ;
      RECT 0.000 167.796 0.018 167.814 ;
    END
  END rd1_out[420]
  PIN rd1_out[421]
    DIRECTION OUTPUT ;
    USE SIGNAL ;
    SHAPE ABUTMENT ;
    PORT
      LAYER M4 ;
      RECT 0.000 167.976 0.018 167.994 ;
    END
  END rd1_out[421]
  PIN rd1_out[422]
    DIRECTION OUTPUT ;
    USE SIGNAL ;
    SHAPE ABUTMENT ;
    PORT
      LAYER M4 ;
      RECT 0.000 168.156 0.018 168.174 ;
    END
  END rd1_out[422]
  PIN rd1_out[423]
    DIRECTION OUTPUT ;
    USE SIGNAL ;
    SHAPE ABUTMENT ;
    PORT
      LAYER M4 ;
      RECT 0.000 168.336 0.018 168.354 ;
    END
  END rd1_out[423]
  PIN rd1_out[424]
    DIRECTION OUTPUT ;
    USE SIGNAL ;
    SHAPE ABUTMENT ;
    PORT
      LAYER M4 ;
      RECT 0.000 168.516 0.018 168.534 ;
    END
  END rd1_out[424]
  PIN rd1_out[425]
    DIRECTION OUTPUT ;
    USE SIGNAL ;
    SHAPE ABUTMENT ;
    PORT
      LAYER M4 ;
      RECT 0.000 168.696 0.018 168.714 ;
    END
  END rd1_out[425]
  PIN rd1_out[426]
    DIRECTION OUTPUT ;
    USE SIGNAL ;
    SHAPE ABUTMENT ;
    PORT
      LAYER M4 ;
      RECT 0.000 168.876 0.018 168.894 ;
    END
  END rd1_out[426]
  PIN rd1_out[427]
    DIRECTION OUTPUT ;
    USE SIGNAL ;
    SHAPE ABUTMENT ;
    PORT
      LAYER M4 ;
      RECT 0.000 169.056 0.018 169.074 ;
    END
  END rd1_out[427]
  PIN rd1_out[428]
    DIRECTION OUTPUT ;
    USE SIGNAL ;
    SHAPE ABUTMENT ;
    PORT
      LAYER M4 ;
      RECT 0.000 169.236 0.018 169.254 ;
    END
  END rd1_out[428]
  PIN rd1_out[429]
    DIRECTION OUTPUT ;
    USE SIGNAL ;
    SHAPE ABUTMENT ;
    PORT
      LAYER M4 ;
      RECT 0.000 169.416 0.018 169.434 ;
    END
  END rd1_out[429]
  PIN rd1_out[430]
    DIRECTION OUTPUT ;
    USE SIGNAL ;
    SHAPE ABUTMENT ;
    PORT
      LAYER M4 ;
      RECT 0.000 169.596 0.018 169.614 ;
    END
  END rd1_out[430]
  PIN rd1_out[431]
    DIRECTION OUTPUT ;
    USE SIGNAL ;
    SHAPE ABUTMENT ;
    PORT
      LAYER M4 ;
      RECT 0.000 169.776 0.018 169.794 ;
    END
  END rd1_out[431]
  PIN rd1_out[432]
    DIRECTION OUTPUT ;
    USE SIGNAL ;
    SHAPE ABUTMENT ;
    PORT
      LAYER M4 ;
      RECT 0.000 169.956 0.018 169.974 ;
    END
  END rd1_out[432]
  PIN rd1_out[433]
    DIRECTION OUTPUT ;
    USE SIGNAL ;
    SHAPE ABUTMENT ;
    PORT
      LAYER M4 ;
      RECT 0.000 170.136 0.018 170.154 ;
    END
  END rd1_out[433]
  PIN rd1_out[434]
    DIRECTION OUTPUT ;
    USE SIGNAL ;
    SHAPE ABUTMENT ;
    PORT
      LAYER M4 ;
      RECT 0.000 170.316 0.018 170.334 ;
    END
  END rd1_out[434]
  PIN rd1_out[435]
    DIRECTION OUTPUT ;
    USE SIGNAL ;
    SHAPE ABUTMENT ;
    PORT
      LAYER M4 ;
      RECT 0.000 170.496 0.018 170.514 ;
    END
  END rd1_out[435]
  PIN rd1_out[436]
    DIRECTION OUTPUT ;
    USE SIGNAL ;
    SHAPE ABUTMENT ;
    PORT
      LAYER M4 ;
      RECT 0.000 170.676 0.018 170.694 ;
    END
  END rd1_out[436]
  PIN rd1_out[437]
    DIRECTION OUTPUT ;
    USE SIGNAL ;
    SHAPE ABUTMENT ;
    PORT
      LAYER M4 ;
      RECT 0.000 170.856 0.018 170.874 ;
    END
  END rd1_out[437]
  PIN rd1_out[438]
    DIRECTION OUTPUT ;
    USE SIGNAL ;
    SHAPE ABUTMENT ;
    PORT
      LAYER M4 ;
      RECT 0.000 171.036 0.018 171.054 ;
    END
  END rd1_out[438]
  PIN rd1_out[439]
    DIRECTION OUTPUT ;
    USE SIGNAL ;
    SHAPE ABUTMENT ;
    PORT
      LAYER M4 ;
      RECT 0.000 171.216 0.018 171.234 ;
    END
  END rd1_out[439]
  PIN rd1_out[440]
    DIRECTION OUTPUT ;
    USE SIGNAL ;
    SHAPE ABUTMENT ;
    PORT
      LAYER M4 ;
      RECT 0.000 171.396 0.018 171.414 ;
    END
  END rd1_out[440]
  PIN rd1_out[441]
    DIRECTION OUTPUT ;
    USE SIGNAL ;
    SHAPE ABUTMENT ;
    PORT
      LAYER M4 ;
      RECT 0.000 171.576 0.018 171.594 ;
    END
  END rd1_out[441]
  PIN rd1_out[442]
    DIRECTION OUTPUT ;
    USE SIGNAL ;
    SHAPE ABUTMENT ;
    PORT
      LAYER M4 ;
      RECT 0.000 171.756 0.018 171.774 ;
    END
  END rd1_out[442]
  PIN rd1_out[443]
    DIRECTION OUTPUT ;
    USE SIGNAL ;
    SHAPE ABUTMENT ;
    PORT
      LAYER M4 ;
      RECT 0.000 171.936 0.018 171.954 ;
    END
  END rd1_out[443]
  PIN rd1_out[444]
    DIRECTION OUTPUT ;
    USE SIGNAL ;
    SHAPE ABUTMENT ;
    PORT
      LAYER M4 ;
      RECT 0.000 172.116 0.018 172.134 ;
    END
  END rd1_out[444]
  PIN rd1_out[445]
    DIRECTION OUTPUT ;
    USE SIGNAL ;
    SHAPE ABUTMENT ;
    PORT
      LAYER M4 ;
      RECT 0.000 172.296 0.018 172.314 ;
    END
  END rd1_out[445]
  PIN rd1_out[446]
    DIRECTION OUTPUT ;
    USE SIGNAL ;
    SHAPE ABUTMENT ;
    PORT
      LAYER M4 ;
      RECT 0.000 172.476 0.018 172.494 ;
    END
  END rd1_out[446]
  PIN rd1_out[447]
    DIRECTION OUTPUT ;
    USE SIGNAL ;
    SHAPE ABUTMENT ;
    PORT
      LAYER M4 ;
      RECT 0.000 172.656 0.018 172.674 ;
    END
  END rd1_out[447]
  PIN rd1_out[448]
    DIRECTION OUTPUT ;
    USE SIGNAL ;
    SHAPE ABUTMENT ;
    PORT
      LAYER M4 ;
      RECT 0.000 172.836 0.018 172.854 ;
    END
  END rd1_out[448]
  PIN rd1_out[449]
    DIRECTION OUTPUT ;
    USE SIGNAL ;
    SHAPE ABUTMENT ;
    PORT
      LAYER M4 ;
      RECT 0.000 173.016 0.018 173.034 ;
    END
  END rd1_out[449]
  PIN rd1_out[450]
    DIRECTION OUTPUT ;
    USE SIGNAL ;
    SHAPE ABUTMENT ;
    PORT
      LAYER M4 ;
      RECT 0.000 173.196 0.018 173.214 ;
    END
  END rd1_out[450]
  PIN rd1_out[451]
    DIRECTION OUTPUT ;
    USE SIGNAL ;
    SHAPE ABUTMENT ;
    PORT
      LAYER M4 ;
      RECT 0.000 173.376 0.018 173.394 ;
    END
  END rd1_out[451]
  PIN rd1_out[452]
    DIRECTION OUTPUT ;
    USE SIGNAL ;
    SHAPE ABUTMENT ;
    PORT
      LAYER M4 ;
      RECT 0.000 173.556 0.018 173.574 ;
    END
  END rd1_out[452]
  PIN rd1_out[453]
    DIRECTION OUTPUT ;
    USE SIGNAL ;
    SHAPE ABUTMENT ;
    PORT
      LAYER M4 ;
      RECT 0.000 173.736 0.018 173.754 ;
    END
  END rd1_out[453]
  PIN rd1_out[454]
    DIRECTION OUTPUT ;
    USE SIGNAL ;
    SHAPE ABUTMENT ;
    PORT
      LAYER M4 ;
      RECT 0.000 173.916 0.018 173.934 ;
    END
  END rd1_out[454]
  PIN rd1_out[455]
    DIRECTION OUTPUT ;
    USE SIGNAL ;
    SHAPE ABUTMENT ;
    PORT
      LAYER M4 ;
      RECT 0.000 174.096 0.018 174.114 ;
    END
  END rd1_out[455]
  PIN rd1_out[456]
    DIRECTION OUTPUT ;
    USE SIGNAL ;
    SHAPE ABUTMENT ;
    PORT
      LAYER M4 ;
      RECT 0.000 174.276 0.018 174.294 ;
    END
  END rd1_out[456]
  PIN rd1_out[457]
    DIRECTION OUTPUT ;
    USE SIGNAL ;
    SHAPE ABUTMENT ;
    PORT
      LAYER M4 ;
      RECT 0.000 174.456 0.018 174.474 ;
    END
  END rd1_out[457]
  PIN rd1_out[458]
    DIRECTION OUTPUT ;
    USE SIGNAL ;
    SHAPE ABUTMENT ;
    PORT
      LAYER M4 ;
      RECT 0.000 174.636 0.018 174.654 ;
    END
  END rd1_out[458]
  PIN rd1_out[459]
    DIRECTION OUTPUT ;
    USE SIGNAL ;
    SHAPE ABUTMENT ;
    PORT
      LAYER M4 ;
      RECT 0.000 174.816 0.018 174.834 ;
    END
  END rd1_out[459]
  PIN rd1_out[460]
    DIRECTION OUTPUT ;
    USE SIGNAL ;
    SHAPE ABUTMENT ;
    PORT
      LAYER M4 ;
      RECT 0.000 174.996 0.018 175.014 ;
    END
  END rd1_out[460]
  PIN rd1_out[461]
    DIRECTION OUTPUT ;
    USE SIGNAL ;
    SHAPE ABUTMENT ;
    PORT
      LAYER M4 ;
      RECT 0.000 175.176 0.018 175.194 ;
    END
  END rd1_out[461]
  PIN rd1_out[462]
    DIRECTION OUTPUT ;
    USE SIGNAL ;
    SHAPE ABUTMENT ;
    PORT
      LAYER M4 ;
      RECT 0.000 175.356 0.018 175.374 ;
    END
  END rd1_out[462]
  PIN rd1_out[463]
    DIRECTION OUTPUT ;
    USE SIGNAL ;
    SHAPE ABUTMENT ;
    PORT
      LAYER M4 ;
      RECT 0.000 175.536 0.018 175.554 ;
    END
  END rd1_out[463]
  PIN rd1_out[464]
    DIRECTION OUTPUT ;
    USE SIGNAL ;
    SHAPE ABUTMENT ;
    PORT
      LAYER M4 ;
      RECT 0.000 175.716 0.018 175.734 ;
    END
  END rd1_out[464]
  PIN rd1_out[465]
    DIRECTION OUTPUT ;
    USE SIGNAL ;
    SHAPE ABUTMENT ;
    PORT
      LAYER M4 ;
      RECT 0.000 175.896 0.018 175.914 ;
    END
  END rd1_out[465]
  PIN rd1_out[466]
    DIRECTION OUTPUT ;
    USE SIGNAL ;
    SHAPE ABUTMENT ;
    PORT
      LAYER M4 ;
      RECT 0.000 176.076 0.018 176.094 ;
    END
  END rd1_out[466]
  PIN rd1_out[467]
    DIRECTION OUTPUT ;
    USE SIGNAL ;
    SHAPE ABUTMENT ;
    PORT
      LAYER M4 ;
      RECT 0.000 176.256 0.018 176.274 ;
    END
  END rd1_out[467]
  PIN rd1_out[468]
    DIRECTION OUTPUT ;
    USE SIGNAL ;
    SHAPE ABUTMENT ;
    PORT
      LAYER M4 ;
      RECT 0.000 176.436 0.018 176.454 ;
    END
  END rd1_out[468]
  PIN rd1_out[469]
    DIRECTION OUTPUT ;
    USE SIGNAL ;
    SHAPE ABUTMENT ;
    PORT
      LAYER M4 ;
      RECT 0.000 176.616 0.018 176.634 ;
    END
  END rd1_out[469]
  PIN rd1_out[470]
    DIRECTION OUTPUT ;
    USE SIGNAL ;
    SHAPE ABUTMENT ;
    PORT
      LAYER M4 ;
      RECT 0.000 176.796 0.018 176.814 ;
    END
  END rd1_out[470]
  PIN rd1_out[471]
    DIRECTION OUTPUT ;
    USE SIGNAL ;
    SHAPE ABUTMENT ;
    PORT
      LAYER M4 ;
      RECT 0.000 176.976 0.018 176.994 ;
    END
  END rd1_out[471]
  PIN rd1_out[472]
    DIRECTION OUTPUT ;
    USE SIGNAL ;
    SHAPE ABUTMENT ;
    PORT
      LAYER M4 ;
      RECT 0.000 177.156 0.018 177.174 ;
    END
  END rd1_out[472]
  PIN rd1_out[473]
    DIRECTION OUTPUT ;
    USE SIGNAL ;
    SHAPE ABUTMENT ;
    PORT
      LAYER M4 ;
      RECT 0.000 177.336 0.018 177.354 ;
    END
  END rd1_out[473]
  PIN rd1_out[474]
    DIRECTION OUTPUT ;
    USE SIGNAL ;
    SHAPE ABUTMENT ;
    PORT
      LAYER M4 ;
      RECT 0.000 177.516 0.018 177.534 ;
    END
  END rd1_out[474]
  PIN rd1_out[475]
    DIRECTION OUTPUT ;
    USE SIGNAL ;
    SHAPE ABUTMENT ;
    PORT
      LAYER M4 ;
      RECT 0.000 177.696 0.018 177.714 ;
    END
  END rd1_out[475]
  PIN rd1_out[476]
    DIRECTION OUTPUT ;
    USE SIGNAL ;
    SHAPE ABUTMENT ;
    PORT
      LAYER M4 ;
      RECT 0.000 177.876 0.018 177.894 ;
    END
  END rd1_out[476]
  PIN rd1_out[477]
    DIRECTION OUTPUT ;
    USE SIGNAL ;
    SHAPE ABUTMENT ;
    PORT
      LAYER M4 ;
      RECT 0.000 178.056 0.018 178.074 ;
    END
  END rd1_out[477]
  PIN rd1_out[478]
    DIRECTION OUTPUT ;
    USE SIGNAL ;
    SHAPE ABUTMENT ;
    PORT
      LAYER M4 ;
      RECT 0.000 178.236 0.018 178.254 ;
    END
  END rd1_out[478]
  PIN rd1_out[479]
    DIRECTION OUTPUT ;
    USE SIGNAL ;
    SHAPE ABUTMENT ;
    PORT
      LAYER M4 ;
      RECT 0.000 178.416 0.018 178.434 ;
    END
  END rd1_out[479]
  PIN rd1_out[480]
    DIRECTION OUTPUT ;
    USE SIGNAL ;
    SHAPE ABUTMENT ;
    PORT
      LAYER M4 ;
      RECT 0.000 178.596 0.018 178.614 ;
    END
  END rd1_out[480]
  PIN rd1_out[481]
    DIRECTION OUTPUT ;
    USE SIGNAL ;
    SHAPE ABUTMENT ;
    PORT
      LAYER M4 ;
      RECT 0.000 178.776 0.018 178.794 ;
    END
  END rd1_out[481]
  PIN rd1_out[482]
    DIRECTION OUTPUT ;
    USE SIGNAL ;
    SHAPE ABUTMENT ;
    PORT
      LAYER M4 ;
      RECT 0.000 178.956 0.018 178.974 ;
    END
  END rd1_out[482]
  PIN rd1_out[483]
    DIRECTION OUTPUT ;
    USE SIGNAL ;
    SHAPE ABUTMENT ;
    PORT
      LAYER M4 ;
      RECT 0.000 179.136 0.018 179.154 ;
    END
  END rd1_out[483]
  PIN rd1_out[484]
    DIRECTION OUTPUT ;
    USE SIGNAL ;
    SHAPE ABUTMENT ;
    PORT
      LAYER M4 ;
      RECT 0.000 179.316 0.018 179.334 ;
    END
  END rd1_out[484]
  PIN rd1_out[485]
    DIRECTION OUTPUT ;
    USE SIGNAL ;
    SHAPE ABUTMENT ;
    PORT
      LAYER M4 ;
      RECT 0.000 179.496 0.018 179.514 ;
    END
  END rd1_out[485]
  PIN rd1_out[486]
    DIRECTION OUTPUT ;
    USE SIGNAL ;
    SHAPE ABUTMENT ;
    PORT
      LAYER M4 ;
      RECT 0.000 179.676 0.018 179.694 ;
    END
  END rd1_out[486]
  PIN rd1_out[487]
    DIRECTION OUTPUT ;
    USE SIGNAL ;
    SHAPE ABUTMENT ;
    PORT
      LAYER M4 ;
      RECT 0.000 179.856 0.018 179.874 ;
    END
  END rd1_out[487]
  PIN rd1_out[488]
    DIRECTION OUTPUT ;
    USE SIGNAL ;
    SHAPE ABUTMENT ;
    PORT
      LAYER M4 ;
      RECT 0.000 180.036 0.018 180.054 ;
    END
  END rd1_out[488]
  PIN rd1_out[489]
    DIRECTION OUTPUT ;
    USE SIGNAL ;
    SHAPE ABUTMENT ;
    PORT
      LAYER M4 ;
      RECT 0.000 180.216 0.018 180.234 ;
    END
  END rd1_out[489]
  PIN rd1_out[490]
    DIRECTION OUTPUT ;
    USE SIGNAL ;
    SHAPE ABUTMENT ;
    PORT
      LAYER M4 ;
      RECT 0.000 180.396 0.018 180.414 ;
    END
  END rd1_out[490]
  PIN rd1_out[491]
    DIRECTION OUTPUT ;
    USE SIGNAL ;
    SHAPE ABUTMENT ;
    PORT
      LAYER M4 ;
      RECT 0.000 180.576 0.018 180.594 ;
    END
  END rd1_out[491]
  PIN rd1_out[492]
    DIRECTION OUTPUT ;
    USE SIGNAL ;
    SHAPE ABUTMENT ;
    PORT
      LAYER M4 ;
      RECT 0.000 180.756 0.018 180.774 ;
    END
  END rd1_out[492]
  PIN rd1_out[493]
    DIRECTION OUTPUT ;
    USE SIGNAL ;
    SHAPE ABUTMENT ;
    PORT
      LAYER M4 ;
      RECT 0.000 180.936 0.018 180.954 ;
    END
  END rd1_out[493]
  PIN rd1_out[494]
    DIRECTION OUTPUT ;
    USE SIGNAL ;
    SHAPE ABUTMENT ;
    PORT
      LAYER M4 ;
      RECT 0.000 181.116 0.018 181.134 ;
    END
  END rd1_out[494]
  PIN rd1_out[495]
    DIRECTION OUTPUT ;
    USE SIGNAL ;
    SHAPE ABUTMENT ;
    PORT
      LAYER M4 ;
      RECT 0.000 181.296 0.018 181.314 ;
    END
  END rd1_out[495]
  PIN rd1_out[496]
    DIRECTION OUTPUT ;
    USE SIGNAL ;
    SHAPE ABUTMENT ;
    PORT
      LAYER M4 ;
      RECT 0.000 181.476 0.018 181.494 ;
    END
  END rd1_out[496]
  PIN rd1_out[497]
    DIRECTION OUTPUT ;
    USE SIGNAL ;
    SHAPE ABUTMENT ;
    PORT
      LAYER M4 ;
      RECT 0.000 181.656 0.018 181.674 ;
    END
  END rd1_out[497]
  PIN rd1_out[498]
    DIRECTION OUTPUT ;
    USE SIGNAL ;
    SHAPE ABUTMENT ;
    PORT
      LAYER M4 ;
      RECT 0.000 181.836 0.018 181.854 ;
    END
  END rd1_out[498]
  PIN rd1_out[499]
    DIRECTION OUTPUT ;
    USE SIGNAL ;
    SHAPE ABUTMENT ;
    PORT
      LAYER M4 ;
      RECT 0.000 182.016 0.018 182.034 ;
    END
  END rd1_out[499]
  PIN rd1_out[500]
    DIRECTION OUTPUT ;
    USE SIGNAL ;
    SHAPE ABUTMENT ;
    PORT
      LAYER M4 ;
      RECT 0.000 182.196 0.018 182.214 ;
    END
  END rd1_out[500]
  PIN rd1_out[501]
    DIRECTION OUTPUT ;
    USE SIGNAL ;
    SHAPE ABUTMENT ;
    PORT
      LAYER M4 ;
      RECT 0.000 182.376 0.018 182.394 ;
    END
  END rd1_out[501]
  PIN rd1_out[502]
    DIRECTION OUTPUT ;
    USE SIGNAL ;
    SHAPE ABUTMENT ;
    PORT
      LAYER M4 ;
      RECT 0.000 182.556 0.018 182.574 ;
    END
  END rd1_out[502]
  PIN rd1_out[503]
    DIRECTION OUTPUT ;
    USE SIGNAL ;
    SHAPE ABUTMENT ;
    PORT
      LAYER M4 ;
      RECT 0.000 182.736 0.018 182.754 ;
    END
  END rd1_out[503]
  PIN rd1_out[504]
    DIRECTION OUTPUT ;
    USE SIGNAL ;
    SHAPE ABUTMENT ;
    PORT
      LAYER M4 ;
      RECT 0.000 182.916 0.018 182.934 ;
    END
  END rd1_out[504]
  PIN rd1_out[505]
    DIRECTION OUTPUT ;
    USE SIGNAL ;
    SHAPE ABUTMENT ;
    PORT
      LAYER M4 ;
      RECT 0.000 183.096 0.018 183.114 ;
    END
  END rd1_out[505]
  PIN rd1_out[506]
    DIRECTION OUTPUT ;
    USE SIGNAL ;
    SHAPE ABUTMENT ;
    PORT
      LAYER M4 ;
      RECT 0.000 183.276 0.018 183.294 ;
    END
  END rd1_out[506]
  PIN rd1_out[507]
    DIRECTION OUTPUT ;
    USE SIGNAL ;
    SHAPE ABUTMENT ;
    PORT
      LAYER M4 ;
      RECT 0.000 183.456 0.018 183.474 ;
    END
  END rd1_out[507]
  PIN rd1_out[508]
    DIRECTION OUTPUT ;
    USE SIGNAL ;
    SHAPE ABUTMENT ;
    PORT
      LAYER M4 ;
      RECT 0.000 183.636 0.018 183.654 ;
    END
  END rd1_out[508]
  PIN rd1_out[509]
    DIRECTION OUTPUT ;
    USE SIGNAL ;
    SHAPE ABUTMENT ;
    PORT
      LAYER M4 ;
      RECT 0.000 183.816 0.018 183.834 ;
    END
  END rd1_out[509]
  PIN rd1_out[510]
    DIRECTION OUTPUT ;
    USE SIGNAL ;
    SHAPE ABUTMENT ;
    PORT
      LAYER M4 ;
      RECT 0.000 183.996 0.018 184.014 ;
    END
  END rd1_out[510]
  PIN rd1_out[511]
    DIRECTION OUTPUT ;
    USE SIGNAL ;
    SHAPE ABUTMENT ;
    PORT
      LAYER M4 ;
      RECT 0.000 184.176 0.018 184.194 ;
    END
  END rd1_out[511]
  PIN wd_in[0]
    DIRECTION INPUT ;
    USE SIGNAL ;
    SHAPE ABUTMENT ;
    PORT
      LAYER M4 ;
      RECT 0.000 184.356 0.018 184.374 ;
    END
  END wd_in[0]
  PIN wd_in[1]
    DIRECTION INPUT ;
    USE SIGNAL ;
    SHAPE ABUTMENT ;
    PORT
      LAYER M4 ;
      RECT 0.000 184.536 0.018 184.554 ;
    END
  END wd_in[1]
  PIN wd_in[2]
    DIRECTION INPUT ;
    USE SIGNAL ;
    SHAPE ABUTMENT ;
    PORT
      LAYER M4 ;
      RECT 0.000 184.716 0.018 184.734 ;
    END
  END wd_in[2]
  PIN wd_in[3]
    DIRECTION INPUT ;
    USE SIGNAL ;
    SHAPE ABUTMENT ;
    PORT
      LAYER M4 ;
      RECT 0.000 184.896 0.018 184.914 ;
    END
  END wd_in[3]
  PIN wd_in[4]
    DIRECTION INPUT ;
    USE SIGNAL ;
    SHAPE ABUTMENT ;
    PORT
      LAYER M4 ;
      RECT 0.000 185.076 0.018 185.094 ;
    END
  END wd_in[4]
  PIN wd_in[5]
    DIRECTION INPUT ;
    USE SIGNAL ;
    SHAPE ABUTMENT ;
    PORT
      LAYER M4 ;
      RECT 0.000 185.256 0.018 185.274 ;
    END
  END wd_in[5]
  PIN wd_in[6]
    DIRECTION INPUT ;
    USE SIGNAL ;
    SHAPE ABUTMENT ;
    PORT
      LAYER M4 ;
      RECT 0.000 185.436 0.018 185.454 ;
    END
  END wd_in[6]
  PIN wd_in[7]
    DIRECTION INPUT ;
    USE SIGNAL ;
    SHAPE ABUTMENT ;
    PORT
      LAYER M4 ;
      RECT 0.000 185.616 0.018 185.634 ;
    END
  END wd_in[7]
  PIN wd_in[8]
    DIRECTION INPUT ;
    USE SIGNAL ;
    SHAPE ABUTMENT ;
    PORT
      LAYER M4 ;
      RECT 0.000 185.796 0.018 185.814 ;
    END
  END wd_in[8]
  PIN wd_in[9]
    DIRECTION INPUT ;
    USE SIGNAL ;
    SHAPE ABUTMENT ;
    PORT
      LAYER M4 ;
      RECT 0.000 185.976 0.018 185.994 ;
    END
  END wd_in[9]
  PIN wd_in[10]
    DIRECTION INPUT ;
    USE SIGNAL ;
    SHAPE ABUTMENT ;
    PORT
      LAYER M4 ;
      RECT 0.000 186.156 0.018 186.174 ;
    END
  END wd_in[10]
  PIN wd_in[11]
    DIRECTION INPUT ;
    USE SIGNAL ;
    SHAPE ABUTMENT ;
    PORT
      LAYER M4 ;
      RECT 0.000 186.336 0.018 186.354 ;
    END
  END wd_in[11]
  PIN wd_in[12]
    DIRECTION INPUT ;
    USE SIGNAL ;
    SHAPE ABUTMENT ;
    PORT
      LAYER M4 ;
      RECT 0.000 186.516 0.018 186.534 ;
    END
  END wd_in[12]
  PIN wd_in[13]
    DIRECTION INPUT ;
    USE SIGNAL ;
    SHAPE ABUTMENT ;
    PORT
      LAYER M4 ;
      RECT 0.000 186.696 0.018 186.714 ;
    END
  END wd_in[13]
  PIN wd_in[14]
    DIRECTION INPUT ;
    USE SIGNAL ;
    SHAPE ABUTMENT ;
    PORT
      LAYER M4 ;
      RECT 0.000 186.876 0.018 186.894 ;
    END
  END wd_in[14]
  PIN wd_in[15]
    DIRECTION INPUT ;
    USE SIGNAL ;
    SHAPE ABUTMENT ;
    PORT
      LAYER M4 ;
      RECT 0.000 187.056 0.018 187.074 ;
    END
  END wd_in[15]
  PIN wd_in[16]
    DIRECTION INPUT ;
    USE SIGNAL ;
    SHAPE ABUTMENT ;
    PORT
      LAYER M4 ;
      RECT 0.000 187.236 0.018 187.254 ;
    END
  END wd_in[16]
  PIN wd_in[17]
    DIRECTION INPUT ;
    USE SIGNAL ;
    SHAPE ABUTMENT ;
    PORT
      LAYER M4 ;
      RECT 0.000 187.416 0.018 187.434 ;
    END
  END wd_in[17]
  PIN wd_in[18]
    DIRECTION INPUT ;
    USE SIGNAL ;
    SHAPE ABUTMENT ;
    PORT
      LAYER M4 ;
      RECT 0.000 187.596 0.018 187.614 ;
    END
  END wd_in[18]
  PIN wd_in[19]
    DIRECTION INPUT ;
    USE SIGNAL ;
    SHAPE ABUTMENT ;
    PORT
      LAYER M4 ;
      RECT 0.000 187.776 0.018 187.794 ;
    END
  END wd_in[19]
  PIN wd_in[20]
    DIRECTION INPUT ;
    USE SIGNAL ;
    SHAPE ABUTMENT ;
    PORT
      LAYER M4 ;
      RECT 0.000 187.956 0.018 187.974 ;
    END
  END wd_in[20]
  PIN wd_in[21]
    DIRECTION INPUT ;
    USE SIGNAL ;
    SHAPE ABUTMENT ;
    PORT
      LAYER M4 ;
      RECT 0.000 188.136 0.018 188.154 ;
    END
  END wd_in[21]
  PIN wd_in[22]
    DIRECTION INPUT ;
    USE SIGNAL ;
    SHAPE ABUTMENT ;
    PORT
      LAYER M4 ;
      RECT 0.000 188.316 0.018 188.334 ;
    END
  END wd_in[22]
  PIN wd_in[23]
    DIRECTION INPUT ;
    USE SIGNAL ;
    SHAPE ABUTMENT ;
    PORT
      LAYER M4 ;
      RECT 0.000 188.496 0.018 188.514 ;
    END
  END wd_in[23]
  PIN wd_in[24]
    DIRECTION INPUT ;
    USE SIGNAL ;
    SHAPE ABUTMENT ;
    PORT
      LAYER M4 ;
      RECT 0.000 188.676 0.018 188.694 ;
    END
  END wd_in[24]
  PIN wd_in[25]
    DIRECTION INPUT ;
    USE SIGNAL ;
    SHAPE ABUTMENT ;
    PORT
      LAYER M4 ;
      RECT 0.000 188.856 0.018 188.874 ;
    END
  END wd_in[25]
  PIN wd_in[26]
    DIRECTION INPUT ;
    USE SIGNAL ;
    SHAPE ABUTMENT ;
    PORT
      LAYER M4 ;
      RECT 0.000 189.036 0.018 189.054 ;
    END
  END wd_in[26]
  PIN wd_in[27]
    DIRECTION INPUT ;
    USE SIGNAL ;
    SHAPE ABUTMENT ;
    PORT
      LAYER M4 ;
      RECT 0.000 189.216 0.018 189.234 ;
    END
  END wd_in[27]
  PIN wd_in[28]
    DIRECTION INPUT ;
    USE SIGNAL ;
    SHAPE ABUTMENT ;
    PORT
      LAYER M4 ;
      RECT 0.000 189.396 0.018 189.414 ;
    END
  END wd_in[28]
  PIN wd_in[29]
    DIRECTION INPUT ;
    USE SIGNAL ;
    SHAPE ABUTMENT ;
    PORT
      LAYER M4 ;
      RECT 0.000 189.576 0.018 189.594 ;
    END
  END wd_in[29]
  PIN wd_in[30]
    DIRECTION INPUT ;
    USE SIGNAL ;
    SHAPE ABUTMENT ;
    PORT
      LAYER M4 ;
      RECT 0.000 189.756 0.018 189.774 ;
    END
  END wd_in[30]
  PIN wd_in[31]
    DIRECTION INPUT ;
    USE SIGNAL ;
    SHAPE ABUTMENT ;
    PORT
      LAYER M4 ;
      RECT 0.000 189.936 0.018 189.954 ;
    END
  END wd_in[31]
  PIN wd_in[32]
    DIRECTION INPUT ;
    USE SIGNAL ;
    SHAPE ABUTMENT ;
    PORT
      LAYER M4 ;
      RECT 0.000 190.116 0.018 190.134 ;
    END
  END wd_in[32]
  PIN wd_in[33]
    DIRECTION INPUT ;
    USE SIGNAL ;
    SHAPE ABUTMENT ;
    PORT
      LAYER M4 ;
      RECT 0.000 190.296 0.018 190.314 ;
    END
  END wd_in[33]
  PIN wd_in[34]
    DIRECTION INPUT ;
    USE SIGNAL ;
    SHAPE ABUTMENT ;
    PORT
      LAYER M4 ;
      RECT 0.000 190.476 0.018 190.494 ;
    END
  END wd_in[34]
  PIN wd_in[35]
    DIRECTION INPUT ;
    USE SIGNAL ;
    SHAPE ABUTMENT ;
    PORT
      LAYER M4 ;
      RECT 0.000 190.656 0.018 190.674 ;
    END
  END wd_in[35]
  PIN wd_in[36]
    DIRECTION INPUT ;
    USE SIGNAL ;
    SHAPE ABUTMENT ;
    PORT
      LAYER M4 ;
      RECT 0.000 190.836 0.018 190.854 ;
    END
  END wd_in[36]
  PIN wd_in[37]
    DIRECTION INPUT ;
    USE SIGNAL ;
    SHAPE ABUTMENT ;
    PORT
      LAYER M4 ;
      RECT 0.000 191.016 0.018 191.034 ;
    END
  END wd_in[37]
  PIN wd_in[38]
    DIRECTION INPUT ;
    USE SIGNAL ;
    SHAPE ABUTMENT ;
    PORT
      LAYER M4 ;
      RECT 0.000 191.196 0.018 191.214 ;
    END
  END wd_in[38]
  PIN wd_in[39]
    DIRECTION INPUT ;
    USE SIGNAL ;
    SHAPE ABUTMENT ;
    PORT
      LAYER M4 ;
      RECT 0.000 191.376 0.018 191.394 ;
    END
  END wd_in[39]
  PIN wd_in[40]
    DIRECTION INPUT ;
    USE SIGNAL ;
    SHAPE ABUTMENT ;
    PORT
      LAYER M4 ;
      RECT 0.000 191.556 0.018 191.574 ;
    END
  END wd_in[40]
  PIN wd_in[41]
    DIRECTION INPUT ;
    USE SIGNAL ;
    SHAPE ABUTMENT ;
    PORT
      LAYER M4 ;
      RECT 0.000 191.736 0.018 191.754 ;
    END
  END wd_in[41]
  PIN wd_in[42]
    DIRECTION INPUT ;
    USE SIGNAL ;
    SHAPE ABUTMENT ;
    PORT
      LAYER M4 ;
      RECT 0.000 191.916 0.018 191.934 ;
    END
  END wd_in[42]
  PIN wd_in[43]
    DIRECTION INPUT ;
    USE SIGNAL ;
    SHAPE ABUTMENT ;
    PORT
      LAYER M4 ;
      RECT 0.000 192.096 0.018 192.114 ;
    END
  END wd_in[43]
  PIN wd_in[44]
    DIRECTION INPUT ;
    USE SIGNAL ;
    SHAPE ABUTMENT ;
    PORT
      LAYER M4 ;
      RECT 0.000 192.276 0.018 192.294 ;
    END
  END wd_in[44]
  PIN wd_in[45]
    DIRECTION INPUT ;
    USE SIGNAL ;
    SHAPE ABUTMENT ;
    PORT
      LAYER M4 ;
      RECT 0.000 192.456 0.018 192.474 ;
    END
  END wd_in[45]
  PIN wd_in[46]
    DIRECTION INPUT ;
    USE SIGNAL ;
    SHAPE ABUTMENT ;
    PORT
      LAYER M4 ;
      RECT 0.000 192.636 0.018 192.654 ;
    END
  END wd_in[46]
  PIN wd_in[47]
    DIRECTION INPUT ;
    USE SIGNAL ;
    SHAPE ABUTMENT ;
    PORT
      LAYER M4 ;
      RECT 0.000 192.816 0.018 192.834 ;
    END
  END wd_in[47]
  PIN wd_in[48]
    DIRECTION INPUT ;
    USE SIGNAL ;
    SHAPE ABUTMENT ;
    PORT
      LAYER M4 ;
      RECT 0.000 192.996 0.018 193.014 ;
    END
  END wd_in[48]
  PIN wd_in[49]
    DIRECTION INPUT ;
    USE SIGNAL ;
    SHAPE ABUTMENT ;
    PORT
      LAYER M4 ;
      RECT 0.000 193.176 0.018 193.194 ;
    END
  END wd_in[49]
  PIN wd_in[50]
    DIRECTION INPUT ;
    USE SIGNAL ;
    SHAPE ABUTMENT ;
    PORT
      LAYER M4 ;
      RECT 0.000 193.356 0.018 193.374 ;
    END
  END wd_in[50]
  PIN wd_in[51]
    DIRECTION INPUT ;
    USE SIGNAL ;
    SHAPE ABUTMENT ;
    PORT
      LAYER M4 ;
      RECT 0.000 193.536 0.018 193.554 ;
    END
  END wd_in[51]
  PIN wd_in[52]
    DIRECTION INPUT ;
    USE SIGNAL ;
    SHAPE ABUTMENT ;
    PORT
      LAYER M4 ;
      RECT 0.000 193.716 0.018 193.734 ;
    END
  END wd_in[52]
  PIN wd_in[53]
    DIRECTION INPUT ;
    USE SIGNAL ;
    SHAPE ABUTMENT ;
    PORT
      LAYER M4 ;
      RECT 0.000 193.896 0.018 193.914 ;
    END
  END wd_in[53]
  PIN wd_in[54]
    DIRECTION INPUT ;
    USE SIGNAL ;
    SHAPE ABUTMENT ;
    PORT
      LAYER M4 ;
      RECT 0.000 194.076 0.018 194.094 ;
    END
  END wd_in[54]
  PIN wd_in[55]
    DIRECTION INPUT ;
    USE SIGNAL ;
    SHAPE ABUTMENT ;
    PORT
      LAYER M4 ;
      RECT 0.000 194.256 0.018 194.274 ;
    END
  END wd_in[55]
  PIN wd_in[56]
    DIRECTION INPUT ;
    USE SIGNAL ;
    SHAPE ABUTMENT ;
    PORT
      LAYER M4 ;
      RECT 0.000 194.436 0.018 194.454 ;
    END
  END wd_in[56]
  PIN wd_in[57]
    DIRECTION INPUT ;
    USE SIGNAL ;
    SHAPE ABUTMENT ;
    PORT
      LAYER M4 ;
      RECT 0.000 194.616 0.018 194.634 ;
    END
  END wd_in[57]
  PIN wd_in[58]
    DIRECTION INPUT ;
    USE SIGNAL ;
    SHAPE ABUTMENT ;
    PORT
      LAYER M4 ;
      RECT 0.000 194.796 0.018 194.814 ;
    END
  END wd_in[58]
  PIN wd_in[59]
    DIRECTION INPUT ;
    USE SIGNAL ;
    SHAPE ABUTMENT ;
    PORT
      LAYER M4 ;
      RECT 0.000 194.976 0.018 194.994 ;
    END
  END wd_in[59]
  PIN wd_in[60]
    DIRECTION INPUT ;
    USE SIGNAL ;
    SHAPE ABUTMENT ;
    PORT
      LAYER M4 ;
      RECT 0.000 195.156 0.018 195.174 ;
    END
  END wd_in[60]
  PIN wd_in[61]
    DIRECTION INPUT ;
    USE SIGNAL ;
    SHAPE ABUTMENT ;
    PORT
      LAYER M4 ;
      RECT 0.000 195.336 0.018 195.354 ;
    END
  END wd_in[61]
  PIN wd_in[62]
    DIRECTION INPUT ;
    USE SIGNAL ;
    SHAPE ABUTMENT ;
    PORT
      LAYER M4 ;
      RECT 0.000 195.516 0.018 195.534 ;
    END
  END wd_in[62]
  PIN wd_in[63]
    DIRECTION INPUT ;
    USE SIGNAL ;
    SHAPE ABUTMENT ;
    PORT
      LAYER M4 ;
      RECT 0.000 195.696 0.018 195.714 ;
    END
  END wd_in[63]
  PIN wd_in[64]
    DIRECTION INPUT ;
    USE SIGNAL ;
    SHAPE ABUTMENT ;
    PORT
      LAYER M4 ;
      RECT 0.000 195.876 0.018 195.894 ;
    END
  END wd_in[64]
  PIN wd_in[65]
    DIRECTION INPUT ;
    USE SIGNAL ;
    SHAPE ABUTMENT ;
    PORT
      LAYER M4 ;
      RECT 0.000 196.056 0.018 196.074 ;
    END
  END wd_in[65]
  PIN wd_in[66]
    DIRECTION INPUT ;
    USE SIGNAL ;
    SHAPE ABUTMENT ;
    PORT
      LAYER M4 ;
      RECT 0.000 196.236 0.018 196.254 ;
    END
  END wd_in[66]
  PIN wd_in[67]
    DIRECTION INPUT ;
    USE SIGNAL ;
    SHAPE ABUTMENT ;
    PORT
      LAYER M4 ;
      RECT 0.000 196.416 0.018 196.434 ;
    END
  END wd_in[67]
  PIN wd_in[68]
    DIRECTION INPUT ;
    USE SIGNAL ;
    SHAPE ABUTMENT ;
    PORT
      LAYER M4 ;
      RECT 0.000 196.596 0.018 196.614 ;
    END
  END wd_in[68]
  PIN wd_in[69]
    DIRECTION INPUT ;
    USE SIGNAL ;
    SHAPE ABUTMENT ;
    PORT
      LAYER M4 ;
      RECT 0.000 196.776 0.018 196.794 ;
    END
  END wd_in[69]
  PIN wd_in[70]
    DIRECTION INPUT ;
    USE SIGNAL ;
    SHAPE ABUTMENT ;
    PORT
      LAYER M4 ;
      RECT 0.000 196.956 0.018 196.974 ;
    END
  END wd_in[70]
  PIN wd_in[71]
    DIRECTION INPUT ;
    USE SIGNAL ;
    SHAPE ABUTMENT ;
    PORT
      LAYER M4 ;
      RECT 0.000 197.136 0.018 197.154 ;
    END
  END wd_in[71]
  PIN wd_in[72]
    DIRECTION INPUT ;
    USE SIGNAL ;
    SHAPE ABUTMENT ;
    PORT
      LAYER M4 ;
      RECT 0.000 197.316 0.018 197.334 ;
    END
  END wd_in[72]
  PIN wd_in[73]
    DIRECTION INPUT ;
    USE SIGNAL ;
    SHAPE ABUTMENT ;
    PORT
      LAYER M4 ;
      RECT 0.000 197.496 0.018 197.514 ;
    END
  END wd_in[73]
  PIN wd_in[74]
    DIRECTION INPUT ;
    USE SIGNAL ;
    SHAPE ABUTMENT ;
    PORT
      LAYER M4 ;
      RECT 0.000 197.676 0.018 197.694 ;
    END
  END wd_in[74]
  PIN wd_in[75]
    DIRECTION INPUT ;
    USE SIGNAL ;
    SHAPE ABUTMENT ;
    PORT
      LAYER M4 ;
      RECT 0.000 197.856 0.018 197.874 ;
    END
  END wd_in[75]
  PIN wd_in[76]
    DIRECTION INPUT ;
    USE SIGNAL ;
    SHAPE ABUTMENT ;
    PORT
      LAYER M4 ;
      RECT 0.000 198.036 0.018 198.054 ;
    END
  END wd_in[76]
  PIN wd_in[77]
    DIRECTION INPUT ;
    USE SIGNAL ;
    SHAPE ABUTMENT ;
    PORT
      LAYER M4 ;
      RECT 0.000 198.216 0.018 198.234 ;
    END
  END wd_in[77]
  PIN wd_in[78]
    DIRECTION INPUT ;
    USE SIGNAL ;
    SHAPE ABUTMENT ;
    PORT
      LAYER M4 ;
      RECT 0.000 198.396 0.018 198.414 ;
    END
  END wd_in[78]
  PIN wd_in[79]
    DIRECTION INPUT ;
    USE SIGNAL ;
    SHAPE ABUTMENT ;
    PORT
      LAYER M4 ;
      RECT 0.000 198.576 0.018 198.594 ;
    END
  END wd_in[79]
  PIN wd_in[80]
    DIRECTION INPUT ;
    USE SIGNAL ;
    SHAPE ABUTMENT ;
    PORT
      LAYER M4 ;
      RECT 0.000 198.756 0.018 198.774 ;
    END
  END wd_in[80]
  PIN wd_in[81]
    DIRECTION INPUT ;
    USE SIGNAL ;
    SHAPE ABUTMENT ;
    PORT
      LAYER M4 ;
      RECT 0.000 198.936 0.018 198.954 ;
    END
  END wd_in[81]
  PIN wd_in[82]
    DIRECTION INPUT ;
    USE SIGNAL ;
    SHAPE ABUTMENT ;
    PORT
      LAYER M4 ;
      RECT 0.000 199.116 0.018 199.134 ;
    END
  END wd_in[82]
  PIN wd_in[83]
    DIRECTION INPUT ;
    USE SIGNAL ;
    SHAPE ABUTMENT ;
    PORT
      LAYER M4 ;
      RECT 0.000 199.296 0.018 199.314 ;
    END
  END wd_in[83]
  PIN wd_in[84]
    DIRECTION INPUT ;
    USE SIGNAL ;
    SHAPE ABUTMENT ;
    PORT
      LAYER M4 ;
      RECT 0.000 199.476 0.018 199.494 ;
    END
  END wd_in[84]
  PIN wd_in[85]
    DIRECTION INPUT ;
    USE SIGNAL ;
    SHAPE ABUTMENT ;
    PORT
      LAYER M4 ;
      RECT 0.000 199.656 0.018 199.674 ;
    END
  END wd_in[85]
  PIN wd_in[86]
    DIRECTION INPUT ;
    USE SIGNAL ;
    SHAPE ABUTMENT ;
    PORT
      LAYER M4 ;
      RECT 0.000 199.836 0.018 199.854 ;
    END
  END wd_in[86]
  PIN wd_in[87]
    DIRECTION INPUT ;
    USE SIGNAL ;
    SHAPE ABUTMENT ;
    PORT
      LAYER M4 ;
      RECT 0.000 200.016 0.018 200.034 ;
    END
  END wd_in[87]
  PIN wd_in[88]
    DIRECTION INPUT ;
    USE SIGNAL ;
    SHAPE ABUTMENT ;
    PORT
      LAYER M4 ;
      RECT 0.000 200.196 0.018 200.214 ;
    END
  END wd_in[88]
  PIN wd_in[89]
    DIRECTION INPUT ;
    USE SIGNAL ;
    SHAPE ABUTMENT ;
    PORT
      LAYER M4 ;
      RECT 0.000 200.376 0.018 200.394 ;
    END
  END wd_in[89]
  PIN wd_in[90]
    DIRECTION INPUT ;
    USE SIGNAL ;
    SHAPE ABUTMENT ;
    PORT
      LAYER M4 ;
      RECT 0.000 200.556 0.018 200.574 ;
    END
  END wd_in[90]
  PIN wd_in[91]
    DIRECTION INPUT ;
    USE SIGNAL ;
    SHAPE ABUTMENT ;
    PORT
      LAYER M4 ;
      RECT 0.000 200.736 0.018 200.754 ;
    END
  END wd_in[91]
  PIN wd_in[92]
    DIRECTION INPUT ;
    USE SIGNAL ;
    SHAPE ABUTMENT ;
    PORT
      LAYER M4 ;
      RECT 0.000 200.916 0.018 200.934 ;
    END
  END wd_in[92]
  PIN wd_in[93]
    DIRECTION INPUT ;
    USE SIGNAL ;
    SHAPE ABUTMENT ;
    PORT
      LAYER M4 ;
      RECT 0.000 201.096 0.018 201.114 ;
    END
  END wd_in[93]
  PIN wd_in[94]
    DIRECTION INPUT ;
    USE SIGNAL ;
    SHAPE ABUTMENT ;
    PORT
      LAYER M4 ;
      RECT 0.000 201.276 0.018 201.294 ;
    END
  END wd_in[94]
  PIN wd_in[95]
    DIRECTION INPUT ;
    USE SIGNAL ;
    SHAPE ABUTMENT ;
    PORT
      LAYER M4 ;
      RECT 0.000 201.456 0.018 201.474 ;
    END
  END wd_in[95]
  PIN wd_in[96]
    DIRECTION INPUT ;
    USE SIGNAL ;
    SHAPE ABUTMENT ;
    PORT
      LAYER M4 ;
      RECT 0.000 201.636 0.018 201.654 ;
    END
  END wd_in[96]
  PIN wd_in[97]
    DIRECTION INPUT ;
    USE SIGNAL ;
    SHAPE ABUTMENT ;
    PORT
      LAYER M4 ;
      RECT 0.000 201.816 0.018 201.834 ;
    END
  END wd_in[97]
  PIN wd_in[98]
    DIRECTION INPUT ;
    USE SIGNAL ;
    SHAPE ABUTMENT ;
    PORT
      LAYER M4 ;
      RECT 0.000 201.996 0.018 202.014 ;
    END
  END wd_in[98]
  PIN wd_in[99]
    DIRECTION INPUT ;
    USE SIGNAL ;
    SHAPE ABUTMENT ;
    PORT
      LAYER M4 ;
      RECT 0.000 202.176 0.018 202.194 ;
    END
  END wd_in[99]
  PIN wd_in[100]
    DIRECTION INPUT ;
    USE SIGNAL ;
    SHAPE ABUTMENT ;
    PORT
      LAYER M4 ;
      RECT 0.000 202.356 0.018 202.374 ;
    END
  END wd_in[100]
  PIN wd_in[101]
    DIRECTION INPUT ;
    USE SIGNAL ;
    SHAPE ABUTMENT ;
    PORT
      LAYER M4 ;
      RECT 0.000 202.536 0.018 202.554 ;
    END
  END wd_in[101]
  PIN wd_in[102]
    DIRECTION INPUT ;
    USE SIGNAL ;
    SHAPE ABUTMENT ;
    PORT
      LAYER M4 ;
      RECT 0.000 202.716 0.018 202.734 ;
    END
  END wd_in[102]
  PIN wd_in[103]
    DIRECTION INPUT ;
    USE SIGNAL ;
    SHAPE ABUTMENT ;
    PORT
      LAYER M4 ;
      RECT 0.000 202.896 0.018 202.914 ;
    END
  END wd_in[103]
  PIN wd_in[104]
    DIRECTION INPUT ;
    USE SIGNAL ;
    SHAPE ABUTMENT ;
    PORT
      LAYER M4 ;
      RECT 0.000 203.076 0.018 203.094 ;
    END
  END wd_in[104]
  PIN wd_in[105]
    DIRECTION INPUT ;
    USE SIGNAL ;
    SHAPE ABUTMENT ;
    PORT
      LAYER M4 ;
      RECT 0.000 203.256 0.018 203.274 ;
    END
  END wd_in[105]
  PIN wd_in[106]
    DIRECTION INPUT ;
    USE SIGNAL ;
    SHAPE ABUTMENT ;
    PORT
      LAYER M4 ;
      RECT 0.000 203.436 0.018 203.454 ;
    END
  END wd_in[106]
  PIN wd_in[107]
    DIRECTION INPUT ;
    USE SIGNAL ;
    SHAPE ABUTMENT ;
    PORT
      LAYER M4 ;
      RECT 0.000 203.616 0.018 203.634 ;
    END
  END wd_in[107]
  PIN wd_in[108]
    DIRECTION INPUT ;
    USE SIGNAL ;
    SHAPE ABUTMENT ;
    PORT
      LAYER M4 ;
      RECT 0.000 203.796 0.018 203.814 ;
    END
  END wd_in[108]
  PIN wd_in[109]
    DIRECTION INPUT ;
    USE SIGNAL ;
    SHAPE ABUTMENT ;
    PORT
      LAYER M4 ;
      RECT 0.000 203.976 0.018 203.994 ;
    END
  END wd_in[109]
  PIN wd_in[110]
    DIRECTION INPUT ;
    USE SIGNAL ;
    SHAPE ABUTMENT ;
    PORT
      LAYER M4 ;
      RECT 0.000 204.156 0.018 204.174 ;
    END
  END wd_in[110]
  PIN wd_in[111]
    DIRECTION INPUT ;
    USE SIGNAL ;
    SHAPE ABUTMENT ;
    PORT
      LAYER M4 ;
      RECT 0.000 204.336 0.018 204.354 ;
    END
  END wd_in[111]
  PIN wd_in[112]
    DIRECTION INPUT ;
    USE SIGNAL ;
    SHAPE ABUTMENT ;
    PORT
      LAYER M4 ;
      RECT 0.000 204.516 0.018 204.534 ;
    END
  END wd_in[112]
  PIN wd_in[113]
    DIRECTION INPUT ;
    USE SIGNAL ;
    SHAPE ABUTMENT ;
    PORT
      LAYER M4 ;
      RECT 0.000 204.696 0.018 204.714 ;
    END
  END wd_in[113]
  PIN wd_in[114]
    DIRECTION INPUT ;
    USE SIGNAL ;
    SHAPE ABUTMENT ;
    PORT
      LAYER M4 ;
      RECT 0.000 204.876 0.018 204.894 ;
    END
  END wd_in[114]
  PIN wd_in[115]
    DIRECTION INPUT ;
    USE SIGNAL ;
    SHAPE ABUTMENT ;
    PORT
      LAYER M4 ;
      RECT 0.000 205.056 0.018 205.074 ;
    END
  END wd_in[115]
  PIN wd_in[116]
    DIRECTION INPUT ;
    USE SIGNAL ;
    SHAPE ABUTMENT ;
    PORT
      LAYER M4 ;
      RECT 0.000 205.236 0.018 205.254 ;
    END
  END wd_in[116]
  PIN wd_in[117]
    DIRECTION INPUT ;
    USE SIGNAL ;
    SHAPE ABUTMENT ;
    PORT
      LAYER M4 ;
      RECT 0.000 205.416 0.018 205.434 ;
    END
  END wd_in[117]
  PIN wd_in[118]
    DIRECTION INPUT ;
    USE SIGNAL ;
    SHAPE ABUTMENT ;
    PORT
      LAYER M4 ;
      RECT 0.000 205.596 0.018 205.614 ;
    END
  END wd_in[118]
  PIN wd_in[119]
    DIRECTION INPUT ;
    USE SIGNAL ;
    SHAPE ABUTMENT ;
    PORT
      LAYER M4 ;
      RECT 0.000 205.776 0.018 205.794 ;
    END
  END wd_in[119]
  PIN wd_in[120]
    DIRECTION INPUT ;
    USE SIGNAL ;
    SHAPE ABUTMENT ;
    PORT
      LAYER M4 ;
      RECT 0.000 205.956 0.018 205.974 ;
    END
  END wd_in[120]
  PIN wd_in[121]
    DIRECTION INPUT ;
    USE SIGNAL ;
    SHAPE ABUTMENT ;
    PORT
      LAYER M4 ;
      RECT 0.000 206.136 0.018 206.154 ;
    END
  END wd_in[121]
  PIN wd_in[122]
    DIRECTION INPUT ;
    USE SIGNAL ;
    SHAPE ABUTMENT ;
    PORT
      LAYER M4 ;
      RECT 0.000 206.316 0.018 206.334 ;
    END
  END wd_in[122]
  PIN wd_in[123]
    DIRECTION INPUT ;
    USE SIGNAL ;
    SHAPE ABUTMENT ;
    PORT
      LAYER M4 ;
      RECT 0.000 206.496 0.018 206.514 ;
    END
  END wd_in[123]
  PIN wd_in[124]
    DIRECTION INPUT ;
    USE SIGNAL ;
    SHAPE ABUTMENT ;
    PORT
      LAYER M4 ;
      RECT 0.000 206.676 0.018 206.694 ;
    END
  END wd_in[124]
  PIN wd_in[125]
    DIRECTION INPUT ;
    USE SIGNAL ;
    SHAPE ABUTMENT ;
    PORT
      LAYER M4 ;
      RECT 0.000 206.856 0.018 206.874 ;
    END
  END wd_in[125]
  PIN wd_in[126]
    DIRECTION INPUT ;
    USE SIGNAL ;
    SHAPE ABUTMENT ;
    PORT
      LAYER M4 ;
      RECT 0.000 207.036 0.018 207.054 ;
    END
  END wd_in[126]
  PIN wd_in[127]
    DIRECTION INPUT ;
    USE SIGNAL ;
    SHAPE ABUTMENT ;
    PORT
      LAYER M4 ;
      RECT 0.000 207.216 0.018 207.234 ;
    END
  END wd_in[127]
  PIN wd_in[128]
    DIRECTION INPUT ;
    USE SIGNAL ;
    SHAPE ABUTMENT ;
    PORT
      LAYER M4 ;
      RECT 0.000 207.396 0.018 207.414 ;
    END
  END wd_in[128]
  PIN wd_in[129]
    DIRECTION INPUT ;
    USE SIGNAL ;
    SHAPE ABUTMENT ;
    PORT
      LAYER M4 ;
      RECT 0.000 207.576 0.018 207.594 ;
    END
  END wd_in[129]
  PIN wd_in[130]
    DIRECTION INPUT ;
    USE SIGNAL ;
    SHAPE ABUTMENT ;
    PORT
      LAYER M4 ;
      RECT 0.000 207.756 0.018 207.774 ;
    END
  END wd_in[130]
  PIN wd_in[131]
    DIRECTION INPUT ;
    USE SIGNAL ;
    SHAPE ABUTMENT ;
    PORT
      LAYER M4 ;
      RECT 0.000 207.936 0.018 207.954 ;
    END
  END wd_in[131]
  PIN wd_in[132]
    DIRECTION INPUT ;
    USE SIGNAL ;
    SHAPE ABUTMENT ;
    PORT
      LAYER M4 ;
      RECT 0.000 208.116 0.018 208.134 ;
    END
  END wd_in[132]
  PIN wd_in[133]
    DIRECTION INPUT ;
    USE SIGNAL ;
    SHAPE ABUTMENT ;
    PORT
      LAYER M4 ;
      RECT 0.000 208.296 0.018 208.314 ;
    END
  END wd_in[133]
  PIN wd_in[134]
    DIRECTION INPUT ;
    USE SIGNAL ;
    SHAPE ABUTMENT ;
    PORT
      LAYER M4 ;
      RECT 0.000 208.476 0.018 208.494 ;
    END
  END wd_in[134]
  PIN wd_in[135]
    DIRECTION INPUT ;
    USE SIGNAL ;
    SHAPE ABUTMENT ;
    PORT
      LAYER M4 ;
      RECT 0.000 208.656 0.018 208.674 ;
    END
  END wd_in[135]
  PIN wd_in[136]
    DIRECTION INPUT ;
    USE SIGNAL ;
    SHAPE ABUTMENT ;
    PORT
      LAYER M4 ;
      RECT 0.000 208.836 0.018 208.854 ;
    END
  END wd_in[136]
  PIN wd_in[137]
    DIRECTION INPUT ;
    USE SIGNAL ;
    SHAPE ABUTMENT ;
    PORT
      LAYER M4 ;
      RECT 0.000 209.016 0.018 209.034 ;
    END
  END wd_in[137]
  PIN wd_in[138]
    DIRECTION INPUT ;
    USE SIGNAL ;
    SHAPE ABUTMENT ;
    PORT
      LAYER M4 ;
      RECT 0.000 209.196 0.018 209.214 ;
    END
  END wd_in[138]
  PIN wd_in[139]
    DIRECTION INPUT ;
    USE SIGNAL ;
    SHAPE ABUTMENT ;
    PORT
      LAYER M4 ;
      RECT 0.000 209.376 0.018 209.394 ;
    END
  END wd_in[139]
  PIN wd_in[140]
    DIRECTION INPUT ;
    USE SIGNAL ;
    SHAPE ABUTMENT ;
    PORT
      LAYER M4 ;
      RECT 0.000 209.556 0.018 209.574 ;
    END
  END wd_in[140]
  PIN wd_in[141]
    DIRECTION INPUT ;
    USE SIGNAL ;
    SHAPE ABUTMENT ;
    PORT
      LAYER M4 ;
      RECT 0.000 209.736 0.018 209.754 ;
    END
  END wd_in[141]
  PIN wd_in[142]
    DIRECTION INPUT ;
    USE SIGNAL ;
    SHAPE ABUTMENT ;
    PORT
      LAYER M4 ;
      RECT 0.000 209.916 0.018 209.934 ;
    END
  END wd_in[142]
  PIN wd_in[143]
    DIRECTION INPUT ;
    USE SIGNAL ;
    SHAPE ABUTMENT ;
    PORT
      LAYER M4 ;
      RECT 0.000 210.096 0.018 210.114 ;
    END
  END wd_in[143]
  PIN wd_in[144]
    DIRECTION INPUT ;
    USE SIGNAL ;
    SHAPE ABUTMENT ;
    PORT
      LAYER M4 ;
      RECT 0.000 210.276 0.018 210.294 ;
    END
  END wd_in[144]
  PIN wd_in[145]
    DIRECTION INPUT ;
    USE SIGNAL ;
    SHAPE ABUTMENT ;
    PORT
      LAYER M4 ;
      RECT 0.000 210.456 0.018 210.474 ;
    END
  END wd_in[145]
  PIN wd_in[146]
    DIRECTION INPUT ;
    USE SIGNAL ;
    SHAPE ABUTMENT ;
    PORT
      LAYER M4 ;
      RECT 0.000 210.636 0.018 210.654 ;
    END
  END wd_in[146]
  PIN wd_in[147]
    DIRECTION INPUT ;
    USE SIGNAL ;
    SHAPE ABUTMENT ;
    PORT
      LAYER M4 ;
      RECT 0.000 210.816 0.018 210.834 ;
    END
  END wd_in[147]
  PIN wd_in[148]
    DIRECTION INPUT ;
    USE SIGNAL ;
    SHAPE ABUTMENT ;
    PORT
      LAYER M4 ;
      RECT 0.000 210.996 0.018 211.014 ;
    END
  END wd_in[148]
  PIN wd_in[149]
    DIRECTION INPUT ;
    USE SIGNAL ;
    SHAPE ABUTMENT ;
    PORT
      LAYER M4 ;
      RECT 0.000 211.176 0.018 211.194 ;
    END
  END wd_in[149]
  PIN wd_in[150]
    DIRECTION INPUT ;
    USE SIGNAL ;
    SHAPE ABUTMENT ;
    PORT
      LAYER M4 ;
      RECT 0.000 211.356 0.018 211.374 ;
    END
  END wd_in[150]
  PIN wd_in[151]
    DIRECTION INPUT ;
    USE SIGNAL ;
    SHAPE ABUTMENT ;
    PORT
      LAYER M4 ;
      RECT 0.000 211.536 0.018 211.554 ;
    END
  END wd_in[151]
  PIN wd_in[152]
    DIRECTION INPUT ;
    USE SIGNAL ;
    SHAPE ABUTMENT ;
    PORT
      LAYER M4 ;
      RECT 0.000 211.716 0.018 211.734 ;
    END
  END wd_in[152]
  PIN wd_in[153]
    DIRECTION INPUT ;
    USE SIGNAL ;
    SHAPE ABUTMENT ;
    PORT
      LAYER M4 ;
      RECT 0.000 211.896 0.018 211.914 ;
    END
  END wd_in[153]
  PIN wd_in[154]
    DIRECTION INPUT ;
    USE SIGNAL ;
    SHAPE ABUTMENT ;
    PORT
      LAYER M4 ;
      RECT 0.000 212.076 0.018 212.094 ;
    END
  END wd_in[154]
  PIN wd_in[155]
    DIRECTION INPUT ;
    USE SIGNAL ;
    SHAPE ABUTMENT ;
    PORT
      LAYER M4 ;
      RECT 0.000 212.256 0.018 212.274 ;
    END
  END wd_in[155]
  PIN wd_in[156]
    DIRECTION INPUT ;
    USE SIGNAL ;
    SHAPE ABUTMENT ;
    PORT
      LAYER M4 ;
      RECT 0.000 212.436 0.018 212.454 ;
    END
  END wd_in[156]
  PIN wd_in[157]
    DIRECTION INPUT ;
    USE SIGNAL ;
    SHAPE ABUTMENT ;
    PORT
      LAYER M4 ;
      RECT 0.000 212.616 0.018 212.634 ;
    END
  END wd_in[157]
  PIN wd_in[158]
    DIRECTION INPUT ;
    USE SIGNAL ;
    SHAPE ABUTMENT ;
    PORT
      LAYER M4 ;
      RECT 0.000 212.796 0.018 212.814 ;
    END
  END wd_in[158]
  PIN wd_in[159]
    DIRECTION INPUT ;
    USE SIGNAL ;
    SHAPE ABUTMENT ;
    PORT
      LAYER M4 ;
      RECT 0.000 212.976 0.018 212.994 ;
    END
  END wd_in[159]
  PIN wd_in[160]
    DIRECTION INPUT ;
    USE SIGNAL ;
    SHAPE ABUTMENT ;
    PORT
      LAYER M4 ;
      RECT 0.000 213.156 0.018 213.174 ;
    END
  END wd_in[160]
  PIN wd_in[161]
    DIRECTION INPUT ;
    USE SIGNAL ;
    SHAPE ABUTMENT ;
    PORT
      LAYER M4 ;
      RECT 0.000 213.336 0.018 213.354 ;
    END
  END wd_in[161]
  PIN wd_in[162]
    DIRECTION INPUT ;
    USE SIGNAL ;
    SHAPE ABUTMENT ;
    PORT
      LAYER M4 ;
      RECT 0.000 213.516 0.018 213.534 ;
    END
  END wd_in[162]
  PIN wd_in[163]
    DIRECTION INPUT ;
    USE SIGNAL ;
    SHAPE ABUTMENT ;
    PORT
      LAYER M4 ;
      RECT 0.000 213.696 0.018 213.714 ;
    END
  END wd_in[163]
  PIN wd_in[164]
    DIRECTION INPUT ;
    USE SIGNAL ;
    SHAPE ABUTMENT ;
    PORT
      LAYER M4 ;
      RECT 0.000 213.876 0.018 213.894 ;
    END
  END wd_in[164]
  PIN wd_in[165]
    DIRECTION INPUT ;
    USE SIGNAL ;
    SHAPE ABUTMENT ;
    PORT
      LAYER M4 ;
      RECT 0.000 214.056 0.018 214.074 ;
    END
  END wd_in[165]
  PIN wd_in[166]
    DIRECTION INPUT ;
    USE SIGNAL ;
    SHAPE ABUTMENT ;
    PORT
      LAYER M4 ;
      RECT 0.000 214.236 0.018 214.254 ;
    END
  END wd_in[166]
  PIN wd_in[167]
    DIRECTION INPUT ;
    USE SIGNAL ;
    SHAPE ABUTMENT ;
    PORT
      LAYER M4 ;
      RECT 0.000 214.416 0.018 214.434 ;
    END
  END wd_in[167]
  PIN wd_in[168]
    DIRECTION INPUT ;
    USE SIGNAL ;
    SHAPE ABUTMENT ;
    PORT
      LAYER M4 ;
      RECT 0.000 214.596 0.018 214.614 ;
    END
  END wd_in[168]
  PIN wd_in[169]
    DIRECTION INPUT ;
    USE SIGNAL ;
    SHAPE ABUTMENT ;
    PORT
      LAYER M4 ;
      RECT 0.000 214.776 0.018 214.794 ;
    END
  END wd_in[169]
  PIN wd_in[170]
    DIRECTION INPUT ;
    USE SIGNAL ;
    SHAPE ABUTMENT ;
    PORT
      LAYER M4 ;
      RECT 0.000 214.956 0.018 214.974 ;
    END
  END wd_in[170]
  PIN wd_in[171]
    DIRECTION INPUT ;
    USE SIGNAL ;
    SHAPE ABUTMENT ;
    PORT
      LAYER M4 ;
      RECT 0.000 215.136 0.018 215.154 ;
    END
  END wd_in[171]
  PIN wd_in[172]
    DIRECTION INPUT ;
    USE SIGNAL ;
    SHAPE ABUTMENT ;
    PORT
      LAYER M4 ;
      RECT 0.000 215.316 0.018 215.334 ;
    END
  END wd_in[172]
  PIN wd_in[173]
    DIRECTION INPUT ;
    USE SIGNAL ;
    SHAPE ABUTMENT ;
    PORT
      LAYER M4 ;
      RECT 0.000 215.496 0.018 215.514 ;
    END
  END wd_in[173]
  PIN wd_in[174]
    DIRECTION INPUT ;
    USE SIGNAL ;
    SHAPE ABUTMENT ;
    PORT
      LAYER M4 ;
      RECT 0.000 215.676 0.018 215.694 ;
    END
  END wd_in[174]
  PIN wd_in[175]
    DIRECTION INPUT ;
    USE SIGNAL ;
    SHAPE ABUTMENT ;
    PORT
      LAYER M4 ;
      RECT 0.000 215.856 0.018 215.874 ;
    END
  END wd_in[175]
  PIN wd_in[176]
    DIRECTION INPUT ;
    USE SIGNAL ;
    SHAPE ABUTMENT ;
    PORT
      LAYER M4 ;
      RECT 0.000 216.036 0.018 216.054 ;
    END
  END wd_in[176]
  PIN wd_in[177]
    DIRECTION INPUT ;
    USE SIGNAL ;
    SHAPE ABUTMENT ;
    PORT
      LAYER M4 ;
      RECT 0.000 216.216 0.018 216.234 ;
    END
  END wd_in[177]
  PIN wd_in[178]
    DIRECTION INPUT ;
    USE SIGNAL ;
    SHAPE ABUTMENT ;
    PORT
      LAYER M4 ;
      RECT 0.000 216.396 0.018 216.414 ;
    END
  END wd_in[178]
  PIN wd_in[179]
    DIRECTION INPUT ;
    USE SIGNAL ;
    SHAPE ABUTMENT ;
    PORT
      LAYER M4 ;
      RECT 0.000 216.576 0.018 216.594 ;
    END
  END wd_in[179]
  PIN wd_in[180]
    DIRECTION INPUT ;
    USE SIGNAL ;
    SHAPE ABUTMENT ;
    PORT
      LAYER M4 ;
      RECT 0.000 216.756 0.018 216.774 ;
    END
  END wd_in[180]
  PIN wd_in[181]
    DIRECTION INPUT ;
    USE SIGNAL ;
    SHAPE ABUTMENT ;
    PORT
      LAYER M4 ;
      RECT 0.000 216.936 0.018 216.954 ;
    END
  END wd_in[181]
  PIN wd_in[182]
    DIRECTION INPUT ;
    USE SIGNAL ;
    SHAPE ABUTMENT ;
    PORT
      LAYER M4 ;
      RECT 0.000 217.116 0.018 217.134 ;
    END
  END wd_in[182]
  PIN wd_in[183]
    DIRECTION INPUT ;
    USE SIGNAL ;
    SHAPE ABUTMENT ;
    PORT
      LAYER M4 ;
      RECT 0.000 217.296 0.018 217.314 ;
    END
  END wd_in[183]
  PIN wd_in[184]
    DIRECTION INPUT ;
    USE SIGNAL ;
    SHAPE ABUTMENT ;
    PORT
      LAYER M4 ;
      RECT 0.000 217.476 0.018 217.494 ;
    END
  END wd_in[184]
  PIN wd_in[185]
    DIRECTION INPUT ;
    USE SIGNAL ;
    SHAPE ABUTMENT ;
    PORT
      LAYER M4 ;
      RECT 0.000 217.656 0.018 217.674 ;
    END
  END wd_in[185]
  PIN wd_in[186]
    DIRECTION INPUT ;
    USE SIGNAL ;
    SHAPE ABUTMENT ;
    PORT
      LAYER M4 ;
      RECT 0.000 217.836 0.018 217.854 ;
    END
  END wd_in[186]
  PIN wd_in[187]
    DIRECTION INPUT ;
    USE SIGNAL ;
    SHAPE ABUTMENT ;
    PORT
      LAYER M4 ;
      RECT 0.000 218.016 0.018 218.034 ;
    END
  END wd_in[187]
  PIN wd_in[188]
    DIRECTION INPUT ;
    USE SIGNAL ;
    SHAPE ABUTMENT ;
    PORT
      LAYER M4 ;
      RECT 0.000 218.196 0.018 218.214 ;
    END
  END wd_in[188]
  PIN wd_in[189]
    DIRECTION INPUT ;
    USE SIGNAL ;
    SHAPE ABUTMENT ;
    PORT
      LAYER M4 ;
      RECT 0.000 218.376 0.018 218.394 ;
    END
  END wd_in[189]
  PIN wd_in[190]
    DIRECTION INPUT ;
    USE SIGNAL ;
    SHAPE ABUTMENT ;
    PORT
      LAYER M4 ;
      RECT 0.000 218.556 0.018 218.574 ;
    END
  END wd_in[190]
  PIN wd_in[191]
    DIRECTION INPUT ;
    USE SIGNAL ;
    SHAPE ABUTMENT ;
    PORT
      LAYER M4 ;
      RECT 0.000 218.736 0.018 218.754 ;
    END
  END wd_in[191]
  PIN wd_in[192]
    DIRECTION INPUT ;
    USE SIGNAL ;
    SHAPE ABUTMENT ;
    PORT
      LAYER M4 ;
      RECT 0.000 218.916 0.018 218.934 ;
    END
  END wd_in[192]
  PIN wd_in[193]
    DIRECTION INPUT ;
    USE SIGNAL ;
    SHAPE ABUTMENT ;
    PORT
      LAYER M4 ;
      RECT 0.000 219.096 0.018 219.114 ;
    END
  END wd_in[193]
  PIN wd_in[194]
    DIRECTION INPUT ;
    USE SIGNAL ;
    SHAPE ABUTMENT ;
    PORT
      LAYER M4 ;
      RECT 0.000 219.276 0.018 219.294 ;
    END
  END wd_in[194]
  PIN wd_in[195]
    DIRECTION INPUT ;
    USE SIGNAL ;
    SHAPE ABUTMENT ;
    PORT
      LAYER M4 ;
      RECT 0.000 219.456 0.018 219.474 ;
    END
  END wd_in[195]
  PIN wd_in[196]
    DIRECTION INPUT ;
    USE SIGNAL ;
    SHAPE ABUTMENT ;
    PORT
      LAYER M4 ;
      RECT 0.000 219.636 0.018 219.654 ;
    END
  END wd_in[196]
  PIN wd_in[197]
    DIRECTION INPUT ;
    USE SIGNAL ;
    SHAPE ABUTMENT ;
    PORT
      LAYER M4 ;
      RECT 0.000 219.816 0.018 219.834 ;
    END
  END wd_in[197]
  PIN wd_in[198]
    DIRECTION INPUT ;
    USE SIGNAL ;
    SHAPE ABUTMENT ;
    PORT
      LAYER M4 ;
      RECT 0.000 219.996 0.018 220.014 ;
    END
  END wd_in[198]
  PIN wd_in[199]
    DIRECTION INPUT ;
    USE SIGNAL ;
    SHAPE ABUTMENT ;
    PORT
      LAYER M4 ;
      RECT 0.000 220.176 0.018 220.194 ;
    END
  END wd_in[199]
  PIN wd_in[200]
    DIRECTION INPUT ;
    USE SIGNAL ;
    SHAPE ABUTMENT ;
    PORT
      LAYER M4 ;
      RECT 0.000 220.356 0.018 220.374 ;
    END
  END wd_in[200]
  PIN wd_in[201]
    DIRECTION INPUT ;
    USE SIGNAL ;
    SHAPE ABUTMENT ;
    PORT
      LAYER M4 ;
      RECT 0.000 220.536 0.018 220.554 ;
    END
  END wd_in[201]
  PIN wd_in[202]
    DIRECTION INPUT ;
    USE SIGNAL ;
    SHAPE ABUTMENT ;
    PORT
      LAYER M4 ;
      RECT 0.000 220.716 0.018 220.734 ;
    END
  END wd_in[202]
  PIN wd_in[203]
    DIRECTION INPUT ;
    USE SIGNAL ;
    SHAPE ABUTMENT ;
    PORT
      LAYER M4 ;
      RECT 0.000 220.896 0.018 220.914 ;
    END
  END wd_in[203]
  PIN wd_in[204]
    DIRECTION INPUT ;
    USE SIGNAL ;
    SHAPE ABUTMENT ;
    PORT
      LAYER M4 ;
      RECT 0.000 221.076 0.018 221.094 ;
    END
  END wd_in[204]
  PIN wd_in[205]
    DIRECTION INPUT ;
    USE SIGNAL ;
    SHAPE ABUTMENT ;
    PORT
      LAYER M4 ;
      RECT 0.000 221.256 0.018 221.274 ;
    END
  END wd_in[205]
  PIN wd_in[206]
    DIRECTION INPUT ;
    USE SIGNAL ;
    SHAPE ABUTMENT ;
    PORT
      LAYER M4 ;
      RECT 0.000 221.436 0.018 221.454 ;
    END
  END wd_in[206]
  PIN wd_in[207]
    DIRECTION INPUT ;
    USE SIGNAL ;
    SHAPE ABUTMENT ;
    PORT
      LAYER M4 ;
      RECT 0.000 221.616 0.018 221.634 ;
    END
  END wd_in[207]
  PIN wd_in[208]
    DIRECTION INPUT ;
    USE SIGNAL ;
    SHAPE ABUTMENT ;
    PORT
      LAYER M4 ;
      RECT 0.000 221.796 0.018 221.814 ;
    END
  END wd_in[208]
  PIN wd_in[209]
    DIRECTION INPUT ;
    USE SIGNAL ;
    SHAPE ABUTMENT ;
    PORT
      LAYER M4 ;
      RECT 0.000 221.976 0.018 221.994 ;
    END
  END wd_in[209]
  PIN wd_in[210]
    DIRECTION INPUT ;
    USE SIGNAL ;
    SHAPE ABUTMENT ;
    PORT
      LAYER M4 ;
      RECT 0.000 222.156 0.018 222.174 ;
    END
  END wd_in[210]
  PIN wd_in[211]
    DIRECTION INPUT ;
    USE SIGNAL ;
    SHAPE ABUTMENT ;
    PORT
      LAYER M4 ;
      RECT 0.000 222.336 0.018 222.354 ;
    END
  END wd_in[211]
  PIN wd_in[212]
    DIRECTION INPUT ;
    USE SIGNAL ;
    SHAPE ABUTMENT ;
    PORT
      LAYER M4 ;
      RECT 0.000 222.516 0.018 222.534 ;
    END
  END wd_in[212]
  PIN wd_in[213]
    DIRECTION INPUT ;
    USE SIGNAL ;
    SHAPE ABUTMENT ;
    PORT
      LAYER M4 ;
      RECT 0.000 222.696 0.018 222.714 ;
    END
  END wd_in[213]
  PIN wd_in[214]
    DIRECTION INPUT ;
    USE SIGNAL ;
    SHAPE ABUTMENT ;
    PORT
      LAYER M4 ;
      RECT 0.000 222.876 0.018 222.894 ;
    END
  END wd_in[214]
  PIN wd_in[215]
    DIRECTION INPUT ;
    USE SIGNAL ;
    SHAPE ABUTMENT ;
    PORT
      LAYER M4 ;
      RECT 0.000 223.056 0.018 223.074 ;
    END
  END wd_in[215]
  PIN wd_in[216]
    DIRECTION INPUT ;
    USE SIGNAL ;
    SHAPE ABUTMENT ;
    PORT
      LAYER M4 ;
      RECT 0.000 223.236 0.018 223.254 ;
    END
  END wd_in[216]
  PIN wd_in[217]
    DIRECTION INPUT ;
    USE SIGNAL ;
    SHAPE ABUTMENT ;
    PORT
      LAYER M4 ;
      RECT 0.000 223.416 0.018 223.434 ;
    END
  END wd_in[217]
  PIN wd_in[218]
    DIRECTION INPUT ;
    USE SIGNAL ;
    SHAPE ABUTMENT ;
    PORT
      LAYER M4 ;
      RECT 0.000 223.596 0.018 223.614 ;
    END
  END wd_in[218]
  PIN wd_in[219]
    DIRECTION INPUT ;
    USE SIGNAL ;
    SHAPE ABUTMENT ;
    PORT
      LAYER M4 ;
      RECT 0.000 223.776 0.018 223.794 ;
    END
  END wd_in[219]
  PIN wd_in[220]
    DIRECTION INPUT ;
    USE SIGNAL ;
    SHAPE ABUTMENT ;
    PORT
      LAYER M4 ;
      RECT 0.000 223.956 0.018 223.974 ;
    END
  END wd_in[220]
  PIN wd_in[221]
    DIRECTION INPUT ;
    USE SIGNAL ;
    SHAPE ABUTMENT ;
    PORT
      LAYER M4 ;
      RECT 0.000 224.136 0.018 224.154 ;
    END
  END wd_in[221]
  PIN wd_in[222]
    DIRECTION INPUT ;
    USE SIGNAL ;
    SHAPE ABUTMENT ;
    PORT
      LAYER M4 ;
      RECT 0.000 224.316 0.018 224.334 ;
    END
  END wd_in[222]
  PIN wd_in[223]
    DIRECTION INPUT ;
    USE SIGNAL ;
    SHAPE ABUTMENT ;
    PORT
      LAYER M4 ;
      RECT 0.000 224.496 0.018 224.514 ;
    END
  END wd_in[223]
  PIN wd_in[224]
    DIRECTION INPUT ;
    USE SIGNAL ;
    SHAPE ABUTMENT ;
    PORT
      LAYER M4 ;
      RECT 0.000 224.676 0.018 224.694 ;
    END
  END wd_in[224]
  PIN wd_in[225]
    DIRECTION INPUT ;
    USE SIGNAL ;
    SHAPE ABUTMENT ;
    PORT
      LAYER M4 ;
      RECT 0.000 224.856 0.018 224.874 ;
    END
  END wd_in[225]
  PIN wd_in[226]
    DIRECTION INPUT ;
    USE SIGNAL ;
    SHAPE ABUTMENT ;
    PORT
      LAYER M4 ;
      RECT 0.000 225.036 0.018 225.054 ;
    END
  END wd_in[226]
  PIN wd_in[227]
    DIRECTION INPUT ;
    USE SIGNAL ;
    SHAPE ABUTMENT ;
    PORT
      LAYER M4 ;
      RECT 0.000 225.216 0.018 225.234 ;
    END
  END wd_in[227]
  PIN wd_in[228]
    DIRECTION INPUT ;
    USE SIGNAL ;
    SHAPE ABUTMENT ;
    PORT
      LAYER M4 ;
      RECT 0.000 225.396 0.018 225.414 ;
    END
  END wd_in[228]
  PIN wd_in[229]
    DIRECTION INPUT ;
    USE SIGNAL ;
    SHAPE ABUTMENT ;
    PORT
      LAYER M4 ;
      RECT 0.000 225.576 0.018 225.594 ;
    END
  END wd_in[229]
  PIN wd_in[230]
    DIRECTION INPUT ;
    USE SIGNAL ;
    SHAPE ABUTMENT ;
    PORT
      LAYER M4 ;
      RECT 0.000 225.756 0.018 225.774 ;
    END
  END wd_in[230]
  PIN wd_in[231]
    DIRECTION INPUT ;
    USE SIGNAL ;
    SHAPE ABUTMENT ;
    PORT
      LAYER M4 ;
      RECT 0.000 225.936 0.018 225.954 ;
    END
  END wd_in[231]
  PIN wd_in[232]
    DIRECTION INPUT ;
    USE SIGNAL ;
    SHAPE ABUTMENT ;
    PORT
      LAYER M4 ;
      RECT 0.000 226.116 0.018 226.134 ;
    END
  END wd_in[232]
  PIN wd_in[233]
    DIRECTION INPUT ;
    USE SIGNAL ;
    SHAPE ABUTMENT ;
    PORT
      LAYER M4 ;
      RECT 0.000 226.296 0.018 226.314 ;
    END
  END wd_in[233]
  PIN wd_in[234]
    DIRECTION INPUT ;
    USE SIGNAL ;
    SHAPE ABUTMENT ;
    PORT
      LAYER M4 ;
      RECT 0.000 226.476 0.018 226.494 ;
    END
  END wd_in[234]
  PIN wd_in[235]
    DIRECTION INPUT ;
    USE SIGNAL ;
    SHAPE ABUTMENT ;
    PORT
      LAYER M4 ;
      RECT 0.000 226.656 0.018 226.674 ;
    END
  END wd_in[235]
  PIN wd_in[236]
    DIRECTION INPUT ;
    USE SIGNAL ;
    SHAPE ABUTMENT ;
    PORT
      LAYER M4 ;
      RECT 0.000 226.836 0.018 226.854 ;
    END
  END wd_in[236]
  PIN wd_in[237]
    DIRECTION INPUT ;
    USE SIGNAL ;
    SHAPE ABUTMENT ;
    PORT
      LAYER M4 ;
      RECT 0.000 227.016 0.018 227.034 ;
    END
  END wd_in[237]
  PIN wd_in[238]
    DIRECTION INPUT ;
    USE SIGNAL ;
    SHAPE ABUTMENT ;
    PORT
      LAYER M4 ;
      RECT 0.000 227.196 0.018 227.214 ;
    END
  END wd_in[238]
  PIN wd_in[239]
    DIRECTION INPUT ;
    USE SIGNAL ;
    SHAPE ABUTMENT ;
    PORT
      LAYER M4 ;
      RECT 0.000 227.376 0.018 227.394 ;
    END
  END wd_in[239]
  PIN wd_in[240]
    DIRECTION INPUT ;
    USE SIGNAL ;
    SHAPE ABUTMENT ;
    PORT
      LAYER M4 ;
      RECT 0.000 227.556 0.018 227.574 ;
    END
  END wd_in[240]
  PIN wd_in[241]
    DIRECTION INPUT ;
    USE SIGNAL ;
    SHAPE ABUTMENT ;
    PORT
      LAYER M4 ;
      RECT 0.000 227.736 0.018 227.754 ;
    END
  END wd_in[241]
  PIN wd_in[242]
    DIRECTION INPUT ;
    USE SIGNAL ;
    SHAPE ABUTMENT ;
    PORT
      LAYER M4 ;
      RECT 0.000 227.916 0.018 227.934 ;
    END
  END wd_in[242]
  PIN wd_in[243]
    DIRECTION INPUT ;
    USE SIGNAL ;
    SHAPE ABUTMENT ;
    PORT
      LAYER M4 ;
      RECT 0.000 228.096 0.018 228.114 ;
    END
  END wd_in[243]
  PIN wd_in[244]
    DIRECTION INPUT ;
    USE SIGNAL ;
    SHAPE ABUTMENT ;
    PORT
      LAYER M4 ;
      RECT 0.000 228.276 0.018 228.294 ;
    END
  END wd_in[244]
  PIN wd_in[245]
    DIRECTION INPUT ;
    USE SIGNAL ;
    SHAPE ABUTMENT ;
    PORT
      LAYER M4 ;
      RECT 0.000 228.456 0.018 228.474 ;
    END
  END wd_in[245]
  PIN wd_in[246]
    DIRECTION INPUT ;
    USE SIGNAL ;
    SHAPE ABUTMENT ;
    PORT
      LAYER M4 ;
      RECT 0.000 228.636 0.018 228.654 ;
    END
  END wd_in[246]
  PIN wd_in[247]
    DIRECTION INPUT ;
    USE SIGNAL ;
    SHAPE ABUTMENT ;
    PORT
      LAYER M4 ;
      RECT 0.000 228.816 0.018 228.834 ;
    END
  END wd_in[247]
  PIN wd_in[248]
    DIRECTION INPUT ;
    USE SIGNAL ;
    SHAPE ABUTMENT ;
    PORT
      LAYER M4 ;
      RECT 0.000 228.996 0.018 229.014 ;
    END
  END wd_in[248]
  PIN wd_in[249]
    DIRECTION INPUT ;
    USE SIGNAL ;
    SHAPE ABUTMENT ;
    PORT
      LAYER M4 ;
      RECT 0.000 229.176 0.018 229.194 ;
    END
  END wd_in[249]
  PIN wd_in[250]
    DIRECTION INPUT ;
    USE SIGNAL ;
    SHAPE ABUTMENT ;
    PORT
      LAYER M4 ;
      RECT 0.000 229.356 0.018 229.374 ;
    END
  END wd_in[250]
  PIN wd_in[251]
    DIRECTION INPUT ;
    USE SIGNAL ;
    SHAPE ABUTMENT ;
    PORT
      LAYER M4 ;
      RECT 0.000 229.536 0.018 229.554 ;
    END
  END wd_in[251]
  PIN wd_in[252]
    DIRECTION INPUT ;
    USE SIGNAL ;
    SHAPE ABUTMENT ;
    PORT
      LAYER M4 ;
      RECT 0.000 229.716 0.018 229.734 ;
    END
  END wd_in[252]
  PIN wd_in[253]
    DIRECTION INPUT ;
    USE SIGNAL ;
    SHAPE ABUTMENT ;
    PORT
      LAYER M4 ;
      RECT 0.000 229.896 0.018 229.914 ;
    END
  END wd_in[253]
  PIN wd_in[254]
    DIRECTION INPUT ;
    USE SIGNAL ;
    SHAPE ABUTMENT ;
    PORT
      LAYER M4 ;
      RECT 0.000 230.076 0.018 230.094 ;
    END
  END wd_in[254]
  PIN wd_in[255]
    DIRECTION INPUT ;
    USE SIGNAL ;
    SHAPE ABUTMENT ;
    PORT
      LAYER M4 ;
      RECT 0.000 230.256 0.018 230.274 ;
    END
  END wd_in[255]
  PIN wd_in[256]
    DIRECTION INPUT ;
    USE SIGNAL ;
    SHAPE ABUTMENT ;
    PORT
      LAYER M4 ;
      RECT 0.000 230.436 0.018 230.454 ;
    END
  END wd_in[256]
  PIN wd_in[257]
    DIRECTION INPUT ;
    USE SIGNAL ;
    SHAPE ABUTMENT ;
    PORT
      LAYER M4 ;
      RECT 0.000 230.616 0.018 230.634 ;
    END
  END wd_in[257]
  PIN wd_in[258]
    DIRECTION INPUT ;
    USE SIGNAL ;
    SHAPE ABUTMENT ;
    PORT
      LAYER M4 ;
      RECT 0.000 230.796 0.018 230.814 ;
    END
  END wd_in[258]
  PIN wd_in[259]
    DIRECTION INPUT ;
    USE SIGNAL ;
    SHAPE ABUTMENT ;
    PORT
      LAYER M4 ;
      RECT 0.000 230.976 0.018 230.994 ;
    END
  END wd_in[259]
  PIN wd_in[260]
    DIRECTION INPUT ;
    USE SIGNAL ;
    SHAPE ABUTMENT ;
    PORT
      LAYER M4 ;
      RECT 0.000 231.156 0.018 231.174 ;
    END
  END wd_in[260]
  PIN wd_in[261]
    DIRECTION INPUT ;
    USE SIGNAL ;
    SHAPE ABUTMENT ;
    PORT
      LAYER M4 ;
      RECT 0.000 231.336 0.018 231.354 ;
    END
  END wd_in[261]
  PIN wd_in[262]
    DIRECTION INPUT ;
    USE SIGNAL ;
    SHAPE ABUTMENT ;
    PORT
      LAYER M4 ;
      RECT 0.000 231.516 0.018 231.534 ;
    END
  END wd_in[262]
  PIN wd_in[263]
    DIRECTION INPUT ;
    USE SIGNAL ;
    SHAPE ABUTMENT ;
    PORT
      LAYER M4 ;
      RECT 0.000 231.696 0.018 231.714 ;
    END
  END wd_in[263]
  PIN wd_in[264]
    DIRECTION INPUT ;
    USE SIGNAL ;
    SHAPE ABUTMENT ;
    PORT
      LAYER M4 ;
      RECT 0.000 231.876 0.018 231.894 ;
    END
  END wd_in[264]
  PIN wd_in[265]
    DIRECTION INPUT ;
    USE SIGNAL ;
    SHAPE ABUTMENT ;
    PORT
      LAYER M4 ;
      RECT 0.000 232.056 0.018 232.074 ;
    END
  END wd_in[265]
  PIN wd_in[266]
    DIRECTION INPUT ;
    USE SIGNAL ;
    SHAPE ABUTMENT ;
    PORT
      LAYER M4 ;
      RECT 0.000 232.236 0.018 232.254 ;
    END
  END wd_in[266]
  PIN wd_in[267]
    DIRECTION INPUT ;
    USE SIGNAL ;
    SHAPE ABUTMENT ;
    PORT
      LAYER M4 ;
      RECT 0.000 232.416 0.018 232.434 ;
    END
  END wd_in[267]
  PIN wd_in[268]
    DIRECTION INPUT ;
    USE SIGNAL ;
    SHAPE ABUTMENT ;
    PORT
      LAYER M4 ;
      RECT 0.000 232.596 0.018 232.614 ;
    END
  END wd_in[268]
  PIN wd_in[269]
    DIRECTION INPUT ;
    USE SIGNAL ;
    SHAPE ABUTMENT ;
    PORT
      LAYER M4 ;
      RECT 0.000 232.776 0.018 232.794 ;
    END
  END wd_in[269]
  PIN wd_in[270]
    DIRECTION INPUT ;
    USE SIGNAL ;
    SHAPE ABUTMENT ;
    PORT
      LAYER M4 ;
      RECT 0.000 232.956 0.018 232.974 ;
    END
  END wd_in[270]
  PIN wd_in[271]
    DIRECTION INPUT ;
    USE SIGNAL ;
    SHAPE ABUTMENT ;
    PORT
      LAYER M4 ;
      RECT 0.000 233.136 0.018 233.154 ;
    END
  END wd_in[271]
  PIN wd_in[272]
    DIRECTION INPUT ;
    USE SIGNAL ;
    SHAPE ABUTMENT ;
    PORT
      LAYER M4 ;
      RECT 0.000 233.316 0.018 233.334 ;
    END
  END wd_in[272]
  PIN wd_in[273]
    DIRECTION INPUT ;
    USE SIGNAL ;
    SHAPE ABUTMENT ;
    PORT
      LAYER M4 ;
      RECT 0.000 233.496 0.018 233.514 ;
    END
  END wd_in[273]
  PIN wd_in[274]
    DIRECTION INPUT ;
    USE SIGNAL ;
    SHAPE ABUTMENT ;
    PORT
      LAYER M4 ;
      RECT 0.000 233.676 0.018 233.694 ;
    END
  END wd_in[274]
  PIN wd_in[275]
    DIRECTION INPUT ;
    USE SIGNAL ;
    SHAPE ABUTMENT ;
    PORT
      LAYER M4 ;
      RECT 0.000 233.856 0.018 233.874 ;
    END
  END wd_in[275]
  PIN wd_in[276]
    DIRECTION INPUT ;
    USE SIGNAL ;
    SHAPE ABUTMENT ;
    PORT
      LAYER M4 ;
      RECT 0.000 234.036 0.018 234.054 ;
    END
  END wd_in[276]
  PIN wd_in[277]
    DIRECTION INPUT ;
    USE SIGNAL ;
    SHAPE ABUTMENT ;
    PORT
      LAYER M4 ;
      RECT 0.000 234.216 0.018 234.234 ;
    END
  END wd_in[277]
  PIN wd_in[278]
    DIRECTION INPUT ;
    USE SIGNAL ;
    SHAPE ABUTMENT ;
    PORT
      LAYER M4 ;
      RECT 0.000 234.396 0.018 234.414 ;
    END
  END wd_in[278]
  PIN wd_in[279]
    DIRECTION INPUT ;
    USE SIGNAL ;
    SHAPE ABUTMENT ;
    PORT
      LAYER M4 ;
      RECT 0.000 234.576 0.018 234.594 ;
    END
  END wd_in[279]
  PIN wd_in[280]
    DIRECTION INPUT ;
    USE SIGNAL ;
    SHAPE ABUTMENT ;
    PORT
      LAYER M4 ;
      RECT 0.000 234.756 0.018 234.774 ;
    END
  END wd_in[280]
  PIN wd_in[281]
    DIRECTION INPUT ;
    USE SIGNAL ;
    SHAPE ABUTMENT ;
    PORT
      LAYER M4 ;
      RECT 0.000 234.936 0.018 234.954 ;
    END
  END wd_in[281]
  PIN wd_in[282]
    DIRECTION INPUT ;
    USE SIGNAL ;
    SHAPE ABUTMENT ;
    PORT
      LAYER M4 ;
      RECT 0.000 235.116 0.018 235.134 ;
    END
  END wd_in[282]
  PIN wd_in[283]
    DIRECTION INPUT ;
    USE SIGNAL ;
    SHAPE ABUTMENT ;
    PORT
      LAYER M4 ;
      RECT 0.000 235.296 0.018 235.314 ;
    END
  END wd_in[283]
  PIN wd_in[284]
    DIRECTION INPUT ;
    USE SIGNAL ;
    SHAPE ABUTMENT ;
    PORT
      LAYER M4 ;
      RECT 0.000 235.476 0.018 235.494 ;
    END
  END wd_in[284]
  PIN wd_in[285]
    DIRECTION INPUT ;
    USE SIGNAL ;
    SHAPE ABUTMENT ;
    PORT
      LAYER M4 ;
      RECT 0.000 235.656 0.018 235.674 ;
    END
  END wd_in[285]
  PIN wd_in[286]
    DIRECTION INPUT ;
    USE SIGNAL ;
    SHAPE ABUTMENT ;
    PORT
      LAYER M4 ;
      RECT 0.000 235.836 0.018 235.854 ;
    END
  END wd_in[286]
  PIN wd_in[287]
    DIRECTION INPUT ;
    USE SIGNAL ;
    SHAPE ABUTMENT ;
    PORT
      LAYER M4 ;
      RECT 0.000 236.016 0.018 236.034 ;
    END
  END wd_in[287]
  PIN wd_in[288]
    DIRECTION INPUT ;
    USE SIGNAL ;
    SHAPE ABUTMENT ;
    PORT
      LAYER M4 ;
      RECT 0.000 236.196 0.018 236.214 ;
    END
  END wd_in[288]
  PIN wd_in[289]
    DIRECTION INPUT ;
    USE SIGNAL ;
    SHAPE ABUTMENT ;
    PORT
      LAYER M4 ;
      RECT 0.000 236.376 0.018 236.394 ;
    END
  END wd_in[289]
  PIN wd_in[290]
    DIRECTION INPUT ;
    USE SIGNAL ;
    SHAPE ABUTMENT ;
    PORT
      LAYER M4 ;
      RECT 0.000 236.556 0.018 236.574 ;
    END
  END wd_in[290]
  PIN wd_in[291]
    DIRECTION INPUT ;
    USE SIGNAL ;
    SHAPE ABUTMENT ;
    PORT
      LAYER M4 ;
      RECT 0.000 236.736 0.018 236.754 ;
    END
  END wd_in[291]
  PIN wd_in[292]
    DIRECTION INPUT ;
    USE SIGNAL ;
    SHAPE ABUTMENT ;
    PORT
      LAYER M4 ;
      RECT 0.000 236.916 0.018 236.934 ;
    END
  END wd_in[292]
  PIN wd_in[293]
    DIRECTION INPUT ;
    USE SIGNAL ;
    SHAPE ABUTMENT ;
    PORT
      LAYER M4 ;
      RECT 0.000 237.096 0.018 237.114 ;
    END
  END wd_in[293]
  PIN wd_in[294]
    DIRECTION INPUT ;
    USE SIGNAL ;
    SHAPE ABUTMENT ;
    PORT
      LAYER M4 ;
      RECT 0.000 237.276 0.018 237.294 ;
    END
  END wd_in[294]
  PIN wd_in[295]
    DIRECTION INPUT ;
    USE SIGNAL ;
    SHAPE ABUTMENT ;
    PORT
      LAYER M4 ;
      RECT 0.000 237.456 0.018 237.474 ;
    END
  END wd_in[295]
  PIN wd_in[296]
    DIRECTION INPUT ;
    USE SIGNAL ;
    SHAPE ABUTMENT ;
    PORT
      LAYER M4 ;
      RECT 0.000 237.636 0.018 237.654 ;
    END
  END wd_in[296]
  PIN wd_in[297]
    DIRECTION INPUT ;
    USE SIGNAL ;
    SHAPE ABUTMENT ;
    PORT
      LAYER M4 ;
      RECT 0.000 237.816 0.018 237.834 ;
    END
  END wd_in[297]
  PIN wd_in[298]
    DIRECTION INPUT ;
    USE SIGNAL ;
    SHAPE ABUTMENT ;
    PORT
      LAYER M4 ;
      RECT 0.000 237.996 0.018 238.014 ;
    END
  END wd_in[298]
  PIN wd_in[299]
    DIRECTION INPUT ;
    USE SIGNAL ;
    SHAPE ABUTMENT ;
    PORT
      LAYER M4 ;
      RECT 0.000 238.176 0.018 238.194 ;
    END
  END wd_in[299]
  PIN wd_in[300]
    DIRECTION INPUT ;
    USE SIGNAL ;
    SHAPE ABUTMENT ;
    PORT
      LAYER M4 ;
      RECT 0.000 238.356 0.018 238.374 ;
    END
  END wd_in[300]
  PIN wd_in[301]
    DIRECTION INPUT ;
    USE SIGNAL ;
    SHAPE ABUTMENT ;
    PORT
      LAYER M4 ;
      RECT 0.000 238.536 0.018 238.554 ;
    END
  END wd_in[301]
  PIN wd_in[302]
    DIRECTION INPUT ;
    USE SIGNAL ;
    SHAPE ABUTMENT ;
    PORT
      LAYER M4 ;
      RECT 0.000 238.716 0.018 238.734 ;
    END
  END wd_in[302]
  PIN wd_in[303]
    DIRECTION INPUT ;
    USE SIGNAL ;
    SHAPE ABUTMENT ;
    PORT
      LAYER M4 ;
      RECT 0.000 238.896 0.018 238.914 ;
    END
  END wd_in[303]
  PIN wd_in[304]
    DIRECTION INPUT ;
    USE SIGNAL ;
    SHAPE ABUTMENT ;
    PORT
      LAYER M4 ;
      RECT 0.000 239.076 0.018 239.094 ;
    END
  END wd_in[304]
  PIN wd_in[305]
    DIRECTION INPUT ;
    USE SIGNAL ;
    SHAPE ABUTMENT ;
    PORT
      LAYER M4 ;
      RECT 0.000 239.256 0.018 239.274 ;
    END
  END wd_in[305]
  PIN wd_in[306]
    DIRECTION INPUT ;
    USE SIGNAL ;
    SHAPE ABUTMENT ;
    PORT
      LAYER M4 ;
      RECT 0.000 239.436 0.018 239.454 ;
    END
  END wd_in[306]
  PIN wd_in[307]
    DIRECTION INPUT ;
    USE SIGNAL ;
    SHAPE ABUTMENT ;
    PORT
      LAYER M4 ;
      RECT 0.000 239.616 0.018 239.634 ;
    END
  END wd_in[307]
  PIN wd_in[308]
    DIRECTION INPUT ;
    USE SIGNAL ;
    SHAPE ABUTMENT ;
    PORT
      LAYER M4 ;
      RECT 0.000 239.796 0.018 239.814 ;
    END
  END wd_in[308]
  PIN wd_in[309]
    DIRECTION INPUT ;
    USE SIGNAL ;
    SHAPE ABUTMENT ;
    PORT
      LAYER M4 ;
      RECT 0.000 239.976 0.018 239.994 ;
    END
  END wd_in[309]
  PIN wd_in[310]
    DIRECTION INPUT ;
    USE SIGNAL ;
    SHAPE ABUTMENT ;
    PORT
      LAYER M4 ;
      RECT 0.000 240.156 0.018 240.174 ;
    END
  END wd_in[310]
  PIN wd_in[311]
    DIRECTION INPUT ;
    USE SIGNAL ;
    SHAPE ABUTMENT ;
    PORT
      LAYER M4 ;
      RECT 0.000 240.336 0.018 240.354 ;
    END
  END wd_in[311]
  PIN wd_in[312]
    DIRECTION INPUT ;
    USE SIGNAL ;
    SHAPE ABUTMENT ;
    PORT
      LAYER M4 ;
      RECT 0.000 240.516 0.018 240.534 ;
    END
  END wd_in[312]
  PIN wd_in[313]
    DIRECTION INPUT ;
    USE SIGNAL ;
    SHAPE ABUTMENT ;
    PORT
      LAYER M4 ;
      RECT 0.000 240.696 0.018 240.714 ;
    END
  END wd_in[313]
  PIN wd_in[314]
    DIRECTION INPUT ;
    USE SIGNAL ;
    SHAPE ABUTMENT ;
    PORT
      LAYER M4 ;
      RECT 0.000 240.876 0.018 240.894 ;
    END
  END wd_in[314]
  PIN wd_in[315]
    DIRECTION INPUT ;
    USE SIGNAL ;
    SHAPE ABUTMENT ;
    PORT
      LAYER M4 ;
      RECT 0.000 241.056 0.018 241.074 ;
    END
  END wd_in[315]
  PIN wd_in[316]
    DIRECTION INPUT ;
    USE SIGNAL ;
    SHAPE ABUTMENT ;
    PORT
      LAYER M4 ;
      RECT 0.000 241.236 0.018 241.254 ;
    END
  END wd_in[316]
  PIN wd_in[317]
    DIRECTION INPUT ;
    USE SIGNAL ;
    SHAPE ABUTMENT ;
    PORT
      LAYER M4 ;
      RECT 0.000 241.416 0.018 241.434 ;
    END
  END wd_in[317]
  PIN wd_in[318]
    DIRECTION INPUT ;
    USE SIGNAL ;
    SHAPE ABUTMENT ;
    PORT
      LAYER M4 ;
      RECT 0.000 241.596 0.018 241.614 ;
    END
  END wd_in[318]
  PIN wd_in[319]
    DIRECTION INPUT ;
    USE SIGNAL ;
    SHAPE ABUTMENT ;
    PORT
      LAYER M4 ;
      RECT 0.000 241.776 0.018 241.794 ;
    END
  END wd_in[319]
  PIN wd_in[320]
    DIRECTION INPUT ;
    USE SIGNAL ;
    SHAPE ABUTMENT ;
    PORT
      LAYER M4 ;
      RECT 0.000 241.956 0.018 241.974 ;
    END
  END wd_in[320]
  PIN wd_in[321]
    DIRECTION INPUT ;
    USE SIGNAL ;
    SHAPE ABUTMENT ;
    PORT
      LAYER M4 ;
      RECT 0.000 242.136 0.018 242.154 ;
    END
  END wd_in[321]
  PIN wd_in[322]
    DIRECTION INPUT ;
    USE SIGNAL ;
    SHAPE ABUTMENT ;
    PORT
      LAYER M4 ;
      RECT 0.000 242.316 0.018 242.334 ;
    END
  END wd_in[322]
  PIN wd_in[323]
    DIRECTION INPUT ;
    USE SIGNAL ;
    SHAPE ABUTMENT ;
    PORT
      LAYER M4 ;
      RECT 0.000 242.496 0.018 242.514 ;
    END
  END wd_in[323]
  PIN wd_in[324]
    DIRECTION INPUT ;
    USE SIGNAL ;
    SHAPE ABUTMENT ;
    PORT
      LAYER M4 ;
      RECT 0.000 242.676 0.018 242.694 ;
    END
  END wd_in[324]
  PIN wd_in[325]
    DIRECTION INPUT ;
    USE SIGNAL ;
    SHAPE ABUTMENT ;
    PORT
      LAYER M4 ;
      RECT 0.000 242.856 0.018 242.874 ;
    END
  END wd_in[325]
  PIN wd_in[326]
    DIRECTION INPUT ;
    USE SIGNAL ;
    SHAPE ABUTMENT ;
    PORT
      LAYER M4 ;
      RECT 0.000 243.036 0.018 243.054 ;
    END
  END wd_in[326]
  PIN wd_in[327]
    DIRECTION INPUT ;
    USE SIGNAL ;
    SHAPE ABUTMENT ;
    PORT
      LAYER M4 ;
      RECT 0.000 243.216 0.018 243.234 ;
    END
  END wd_in[327]
  PIN wd_in[328]
    DIRECTION INPUT ;
    USE SIGNAL ;
    SHAPE ABUTMENT ;
    PORT
      LAYER M4 ;
      RECT 0.000 243.396 0.018 243.414 ;
    END
  END wd_in[328]
  PIN wd_in[329]
    DIRECTION INPUT ;
    USE SIGNAL ;
    SHAPE ABUTMENT ;
    PORT
      LAYER M4 ;
      RECT 0.000 243.576 0.018 243.594 ;
    END
  END wd_in[329]
  PIN wd_in[330]
    DIRECTION INPUT ;
    USE SIGNAL ;
    SHAPE ABUTMENT ;
    PORT
      LAYER M4 ;
      RECT 0.000 243.756 0.018 243.774 ;
    END
  END wd_in[330]
  PIN wd_in[331]
    DIRECTION INPUT ;
    USE SIGNAL ;
    SHAPE ABUTMENT ;
    PORT
      LAYER M4 ;
      RECT 0.000 243.936 0.018 243.954 ;
    END
  END wd_in[331]
  PIN wd_in[332]
    DIRECTION INPUT ;
    USE SIGNAL ;
    SHAPE ABUTMENT ;
    PORT
      LAYER M4 ;
      RECT 0.000 244.116 0.018 244.134 ;
    END
  END wd_in[332]
  PIN wd_in[333]
    DIRECTION INPUT ;
    USE SIGNAL ;
    SHAPE ABUTMENT ;
    PORT
      LAYER M4 ;
      RECT 0.000 244.296 0.018 244.314 ;
    END
  END wd_in[333]
  PIN wd_in[334]
    DIRECTION INPUT ;
    USE SIGNAL ;
    SHAPE ABUTMENT ;
    PORT
      LAYER M4 ;
      RECT 0.000 244.476 0.018 244.494 ;
    END
  END wd_in[334]
  PIN wd_in[335]
    DIRECTION INPUT ;
    USE SIGNAL ;
    SHAPE ABUTMENT ;
    PORT
      LAYER M4 ;
      RECT 0.000 244.656 0.018 244.674 ;
    END
  END wd_in[335]
  PIN wd_in[336]
    DIRECTION INPUT ;
    USE SIGNAL ;
    SHAPE ABUTMENT ;
    PORT
      LAYER M4 ;
      RECT 0.000 244.836 0.018 244.854 ;
    END
  END wd_in[336]
  PIN wd_in[337]
    DIRECTION INPUT ;
    USE SIGNAL ;
    SHAPE ABUTMENT ;
    PORT
      LAYER M4 ;
      RECT 0.000 245.016 0.018 245.034 ;
    END
  END wd_in[337]
  PIN wd_in[338]
    DIRECTION INPUT ;
    USE SIGNAL ;
    SHAPE ABUTMENT ;
    PORT
      LAYER M4 ;
      RECT 0.000 245.196 0.018 245.214 ;
    END
  END wd_in[338]
  PIN wd_in[339]
    DIRECTION INPUT ;
    USE SIGNAL ;
    SHAPE ABUTMENT ;
    PORT
      LAYER M4 ;
      RECT 0.000 245.376 0.018 245.394 ;
    END
  END wd_in[339]
  PIN wd_in[340]
    DIRECTION INPUT ;
    USE SIGNAL ;
    SHAPE ABUTMENT ;
    PORT
      LAYER M4 ;
      RECT 0.000 245.556 0.018 245.574 ;
    END
  END wd_in[340]
  PIN wd_in[341]
    DIRECTION INPUT ;
    USE SIGNAL ;
    SHAPE ABUTMENT ;
    PORT
      LAYER M4 ;
      RECT 0.000 245.736 0.018 245.754 ;
    END
  END wd_in[341]
  PIN wd_in[342]
    DIRECTION INPUT ;
    USE SIGNAL ;
    SHAPE ABUTMENT ;
    PORT
      LAYER M4 ;
      RECT 0.000 245.916 0.018 245.934 ;
    END
  END wd_in[342]
  PIN wd_in[343]
    DIRECTION INPUT ;
    USE SIGNAL ;
    SHAPE ABUTMENT ;
    PORT
      LAYER M4 ;
      RECT 0.000 246.096 0.018 246.114 ;
    END
  END wd_in[343]
  PIN wd_in[344]
    DIRECTION INPUT ;
    USE SIGNAL ;
    SHAPE ABUTMENT ;
    PORT
      LAYER M4 ;
      RECT 0.000 246.276 0.018 246.294 ;
    END
  END wd_in[344]
  PIN wd_in[345]
    DIRECTION INPUT ;
    USE SIGNAL ;
    SHAPE ABUTMENT ;
    PORT
      LAYER M4 ;
      RECT 0.000 246.456 0.018 246.474 ;
    END
  END wd_in[345]
  PIN wd_in[346]
    DIRECTION INPUT ;
    USE SIGNAL ;
    SHAPE ABUTMENT ;
    PORT
      LAYER M4 ;
      RECT 0.000 246.636 0.018 246.654 ;
    END
  END wd_in[346]
  PIN wd_in[347]
    DIRECTION INPUT ;
    USE SIGNAL ;
    SHAPE ABUTMENT ;
    PORT
      LAYER M4 ;
      RECT 0.000 246.816 0.018 246.834 ;
    END
  END wd_in[347]
  PIN wd_in[348]
    DIRECTION INPUT ;
    USE SIGNAL ;
    SHAPE ABUTMENT ;
    PORT
      LAYER M4 ;
      RECT 0.000 246.996 0.018 247.014 ;
    END
  END wd_in[348]
  PIN wd_in[349]
    DIRECTION INPUT ;
    USE SIGNAL ;
    SHAPE ABUTMENT ;
    PORT
      LAYER M4 ;
      RECT 0.000 247.176 0.018 247.194 ;
    END
  END wd_in[349]
  PIN wd_in[350]
    DIRECTION INPUT ;
    USE SIGNAL ;
    SHAPE ABUTMENT ;
    PORT
      LAYER M4 ;
      RECT 0.000 247.356 0.018 247.374 ;
    END
  END wd_in[350]
  PIN wd_in[351]
    DIRECTION INPUT ;
    USE SIGNAL ;
    SHAPE ABUTMENT ;
    PORT
      LAYER M4 ;
      RECT 0.000 247.536 0.018 247.554 ;
    END
  END wd_in[351]
  PIN wd_in[352]
    DIRECTION INPUT ;
    USE SIGNAL ;
    SHAPE ABUTMENT ;
    PORT
      LAYER M4 ;
      RECT 0.000 247.716 0.018 247.734 ;
    END
  END wd_in[352]
  PIN wd_in[353]
    DIRECTION INPUT ;
    USE SIGNAL ;
    SHAPE ABUTMENT ;
    PORT
      LAYER M4 ;
      RECT 0.000 247.896 0.018 247.914 ;
    END
  END wd_in[353]
  PIN wd_in[354]
    DIRECTION INPUT ;
    USE SIGNAL ;
    SHAPE ABUTMENT ;
    PORT
      LAYER M4 ;
      RECT 0.000 248.076 0.018 248.094 ;
    END
  END wd_in[354]
  PIN wd_in[355]
    DIRECTION INPUT ;
    USE SIGNAL ;
    SHAPE ABUTMENT ;
    PORT
      LAYER M4 ;
      RECT 0.000 248.256 0.018 248.274 ;
    END
  END wd_in[355]
  PIN wd_in[356]
    DIRECTION INPUT ;
    USE SIGNAL ;
    SHAPE ABUTMENT ;
    PORT
      LAYER M4 ;
      RECT 0.000 248.436 0.018 248.454 ;
    END
  END wd_in[356]
  PIN wd_in[357]
    DIRECTION INPUT ;
    USE SIGNAL ;
    SHAPE ABUTMENT ;
    PORT
      LAYER M4 ;
      RECT 0.000 248.616 0.018 248.634 ;
    END
  END wd_in[357]
  PIN wd_in[358]
    DIRECTION INPUT ;
    USE SIGNAL ;
    SHAPE ABUTMENT ;
    PORT
      LAYER M4 ;
      RECT 0.000 248.796 0.018 248.814 ;
    END
  END wd_in[358]
  PIN wd_in[359]
    DIRECTION INPUT ;
    USE SIGNAL ;
    SHAPE ABUTMENT ;
    PORT
      LAYER M4 ;
      RECT 0.000 248.976 0.018 248.994 ;
    END
  END wd_in[359]
  PIN wd_in[360]
    DIRECTION INPUT ;
    USE SIGNAL ;
    SHAPE ABUTMENT ;
    PORT
      LAYER M4 ;
      RECT 0.000 249.156 0.018 249.174 ;
    END
  END wd_in[360]
  PIN wd_in[361]
    DIRECTION INPUT ;
    USE SIGNAL ;
    SHAPE ABUTMENT ;
    PORT
      LAYER M4 ;
      RECT 0.000 249.336 0.018 249.354 ;
    END
  END wd_in[361]
  PIN wd_in[362]
    DIRECTION INPUT ;
    USE SIGNAL ;
    SHAPE ABUTMENT ;
    PORT
      LAYER M4 ;
      RECT 0.000 249.516 0.018 249.534 ;
    END
  END wd_in[362]
  PIN wd_in[363]
    DIRECTION INPUT ;
    USE SIGNAL ;
    SHAPE ABUTMENT ;
    PORT
      LAYER M4 ;
      RECT 0.000 249.696 0.018 249.714 ;
    END
  END wd_in[363]
  PIN wd_in[364]
    DIRECTION INPUT ;
    USE SIGNAL ;
    SHAPE ABUTMENT ;
    PORT
      LAYER M4 ;
      RECT 0.000 249.876 0.018 249.894 ;
    END
  END wd_in[364]
  PIN wd_in[365]
    DIRECTION INPUT ;
    USE SIGNAL ;
    SHAPE ABUTMENT ;
    PORT
      LAYER M4 ;
      RECT 0.000 250.056 0.018 250.074 ;
    END
  END wd_in[365]
  PIN wd_in[366]
    DIRECTION INPUT ;
    USE SIGNAL ;
    SHAPE ABUTMENT ;
    PORT
      LAYER M4 ;
      RECT 0.000 250.236 0.018 250.254 ;
    END
  END wd_in[366]
  PIN wd_in[367]
    DIRECTION INPUT ;
    USE SIGNAL ;
    SHAPE ABUTMENT ;
    PORT
      LAYER M4 ;
      RECT 0.000 250.416 0.018 250.434 ;
    END
  END wd_in[367]
  PIN wd_in[368]
    DIRECTION INPUT ;
    USE SIGNAL ;
    SHAPE ABUTMENT ;
    PORT
      LAYER M4 ;
      RECT 0.000 250.596 0.018 250.614 ;
    END
  END wd_in[368]
  PIN wd_in[369]
    DIRECTION INPUT ;
    USE SIGNAL ;
    SHAPE ABUTMENT ;
    PORT
      LAYER M4 ;
      RECT 0.000 250.776 0.018 250.794 ;
    END
  END wd_in[369]
  PIN wd_in[370]
    DIRECTION INPUT ;
    USE SIGNAL ;
    SHAPE ABUTMENT ;
    PORT
      LAYER M4 ;
      RECT 0.000 250.956 0.018 250.974 ;
    END
  END wd_in[370]
  PIN wd_in[371]
    DIRECTION INPUT ;
    USE SIGNAL ;
    SHAPE ABUTMENT ;
    PORT
      LAYER M4 ;
      RECT 0.000 251.136 0.018 251.154 ;
    END
  END wd_in[371]
  PIN wd_in[372]
    DIRECTION INPUT ;
    USE SIGNAL ;
    SHAPE ABUTMENT ;
    PORT
      LAYER M4 ;
      RECT 0.000 251.316 0.018 251.334 ;
    END
  END wd_in[372]
  PIN wd_in[373]
    DIRECTION INPUT ;
    USE SIGNAL ;
    SHAPE ABUTMENT ;
    PORT
      LAYER M4 ;
      RECT 0.000 251.496 0.018 251.514 ;
    END
  END wd_in[373]
  PIN wd_in[374]
    DIRECTION INPUT ;
    USE SIGNAL ;
    SHAPE ABUTMENT ;
    PORT
      LAYER M4 ;
      RECT 0.000 251.676 0.018 251.694 ;
    END
  END wd_in[374]
  PIN wd_in[375]
    DIRECTION INPUT ;
    USE SIGNAL ;
    SHAPE ABUTMENT ;
    PORT
      LAYER M4 ;
      RECT 0.000 251.856 0.018 251.874 ;
    END
  END wd_in[375]
  PIN wd_in[376]
    DIRECTION INPUT ;
    USE SIGNAL ;
    SHAPE ABUTMENT ;
    PORT
      LAYER M4 ;
      RECT 0.000 252.036 0.018 252.054 ;
    END
  END wd_in[376]
  PIN wd_in[377]
    DIRECTION INPUT ;
    USE SIGNAL ;
    SHAPE ABUTMENT ;
    PORT
      LAYER M4 ;
      RECT 0.000 252.216 0.018 252.234 ;
    END
  END wd_in[377]
  PIN wd_in[378]
    DIRECTION INPUT ;
    USE SIGNAL ;
    SHAPE ABUTMENT ;
    PORT
      LAYER M4 ;
      RECT 0.000 252.396 0.018 252.414 ;
    END
  END wd_in[378]
  PIN wd_in[379]
    DIRECTION INPUT ;
    USE SIGNAL ;
    SHAPE ABUTMENT ;
    PORT
      LAYER M4 ;
      RECT 0.000 252.576 0.018 252.594 ;
    END
  END wd_in[379]
  PIN wd_in[380]
    DIRECTION INPUT ;
    USE SIGNAL ;
    SHAPE ABUTMENT ;
    PORT
      LAYER M4 ;
      RECT 0.000 252.756 0.018 252.774 ;
    END
  END wd_in[380]
  PIN wd_in[381]
    DIRECTION INPUT ;
    USE SIGNAL ;
    SHAPE ABUTMENT ;
    PORT
      LAYER M4 ;
      RECT 0.000 252.936 0.018 252.954 ;
    END
  END wd_in[381]
  PIN wd_in[382]
    DIRECTION INPUT ;
    USE SIGNAL ;
    SHAPE ABUTMENT ;
    PORT
      LAYER M4 ;
      RECT 0.000 253.116 0.018 253.134 ;
    END
  END wd_in[382]
  PIN wd_in[383]
    DIRECTION INPUT ;
    USE SIGNAL ;
    SHAPE ABUTMENT ;
    PORT
      LAYER M4 ;
      RECT 0.000 253.296 0.018 253.314 ;
    END
  END wd_in[383]
  PIN wd_in[384]
    DIRECTION INPUT ;
    USE SIGNAL ;
    SHAPE ABUTMENT ;
    PORT
      LAYER M4 ;
      RECT 0.000 253.476 0.018 253.494 ;
    END
  END wd_in[384]
  PIN wd_in[385]
    DIRECTION INPUT ;
    USE SIGNAL ;
    SHAPE ABUTMENT ;
    PORT
      LAYER M4 ;
      RECT 0.000 253.656 0.018 253.674 ;
    END
  END wd_in[385]
  PIN wd_in[386]
    DIRECTION INPUT ;
    USE SIGNAL ;
    SHAPE ABUTMENT ;
    PORT
      LAYER M4 ;
      RECT 0.000 253.836 0.018 253.854 ;
    END
  END wd_in[386]
  PIN wd_in[387]
    DIRECTION INPUT ;
    USE SIGNAL ;
    SHAPE ABUTMENT ;
    PORT
      LAYER M4 ;
      RECT 0.000 254.016 0.018 254.034 ;
    END
  END wd_in[387]
  PIN wd_in[388]
    DIRECTION INPUT ;
    USE SIGNAL ;
    SHAPE ABUTMENT ;
    PORT
      LAYER M4 ;
      RECT 0.000 254.196 0.018 254.214 ;
    END
  END wd_in[388]
  PIN wd_in[389]
    DIRECTION INPUT ;
    USE SIGNAL ;
    SHAPE ABUTMENT ;
    PORT
      LAYER M4 ;
      RECT 0.000 254.376 0.018 254.394 ;
    END
  END wd_in[389]
  PIN wd_in[390]
    DIRECTION INPUT ;
    USE SIGNAL ;
    SHAPE ABUTMENT ;
    PORT
      LAYER M4 ;
      RECT 0.000 254.556 0.018 254.574 ;
    END
  END wd_in[390]
  PIN wd_in[391]
    DIRECTION INPUT ;
    USE SIGNAL ;
    SHAPE ABUTMENT ;
    PORT
      LAYER M4 ;
      RECT 0.000 254.736 0.018 254.754 ;
    END
  END wd_in[391]
  PIN wd_in[392]
    DIRECTION INPUT ;
    USE SIGNAL ;
    SHAPE ABUTMENT ;
    PORT
      LAYER M4 ;
      RECT 0.000 254.916 0.018 254.934 ;
    END
  END wd_in[392]
  PIN wd_in[393]
    DIRECTION INPUT ;
    USE SIGNAL ;
    SHAPE ABUTMENT ;
    PORT
      LAYER M4 ;
      RECT 0.000 255.096 0.018 255.114 ;
    END
  END wd_in[393]
  PIN wd_in[394]
    DIRECTION INPUT ;
    USE SIGNAL ;
    SHAPE ABUTMENT ;
    PORT
      LAYER M4 ;
      RECT 0.000 255.276 0.018 255.294 ;
    END
  END wd_in[394]
  PIN wd_in[395]
    DIRECTION INPUT ;
    USE SIGNAL ;
    SHAPE ABUTMENT ;
    PORT
      LAYER M4 ;
      RECT 0.000 255.456 0.018 255.474 ;
    END
  END wd_in[395]
  PIN wd_in[396]
    DIRECTION INPUT ;
    USE SIGNAL ;
    SHAPE ABUTMENT ;
    PORT
      LAYER M4 ;
      RECT 0.000 255.636 0.018 255.654 ;
    END
  END wd_in[396]
  PIN wd_in[397]
    DIRECTION INPUT ;
    USE SIGNAL ;
    SHAPE ABUTMENT ;
    PORT
      LAYER M4 ;
      RECT 0.000 255.816 0.018 255.834 ;
    END
  END wd_in[397]
  PIN wd_in[398]
    DIRECTION INPUT ;
    USE SIGNAL ;
    SHAPE ABUTMENT ;
    PORT
      LAYER M4 ;
      RECT 0.000 255.996 0.018 256.014 ;
    END
  END wd_in[398]
  PIN wd_in[399]
    DIRECTION INPUT ;
    USE SIGNAL ;
    SHAPE ABUTMENT ;
    PORT
      LAYER M4 ;
      RECT 0.000 256.176 0.018 256.194 ;
    END
  END wd_in[399]
  PIN wd_in[400]
    DIRECTION INPUT ;
    USE SIGNAL ;
    SHAPE ABUTMENT ;
    PORT
      LAYER M4 ;
      RECT 0.000 256.356 0.018 256.374 ;
    END
  END wd_in[400]
  PIN wd_in[401]
    DIRECTION INPUT ;
    USE SIGNAL ;
    SHAPE ABUTMENT ;
    PORT
      LAYER M4 ;
      RECT 0.000 256.536 0.018 256.554 ;
    END
  END wd_in[401]
  PIN wd_in[402]
    DIRECTION INPUT ;
    USE SIGNAL ;
    SHAPE ABUTMENT ;
    PORT
      LAYER M4 ;
      RECT 0.000 256.716 0.018 256.734 ;
    END
  END wd_in[402]
  PIN wd_in[403]
    DIRECTION INPUT ;
    USE SIGNAL ;
    SHAPE ABUTMENT ;
    PORT
      LAYER M4 ;
      RECT 0.000 256.896 0.018 256.914 ;
    END
  END wd_in[403]
  PIN wd_in[404]
    DIRECTION INPUT ;
    USE SIGNAL ;
    SHAPE ABUTMENT ;
    PORT
      LAYER M4 ;
      RECT 0.000 257.076 0.018 257.094 ;
    END
  END wd_in[404]
  PIN wd_in[405]
    DIRECTION INPUT ;
    USE SIGNAL ;
    SHAPE ABUTMENT ;
    PORT
      LAYER M4 ;
      RECT 0.000 257.256 0.018 257.274 ;
    END
  END wd_in[405]
  PIN wd_in[406]
    DIRECTION INPUT ;
    USE SIGNAL ;
    SHAPE ABUTMENT ;
    PORT
      LAYER M4 ;
      RECT 0.000 257.436 0.018 257.454 ;
    END
  END wd_in[406]
  PIN wd_in[407]
    DIRECTION INPUT ;
    USE SIGNAL ;
    SHAPE ABUTMENT ;
    PORT
      LAYER M4 ;
      RECT 0.000 257.616 0.018 257.634 ;
    END
  END wd_in[407]
  PIN wd_in[408]
    DIRECTION INPUT ;
    USE SIGNAL ;
    SHAPE ABUTMENT ;
    PORT
      LAYER M4 ;
      RECT 0.000 257.796 0.018 257.814 ;
    END
  END wd_in[408]
  PIN wd_in[409]
    DIRECTION INPUT ;
    USE SIGNAL ;
    SHAPE ABUTMENT ;
    PORT
      LAYER M4 ;
      RECT 0.000 257.976 0.018 257.994 ;
    END
  END wd_in[409]
  PIN wd_in[410]
    DIRECTION INPUT ;
    USE SIGNAL ;
    SHAPE ABUTMENT ;
    PORT
      LAYER M4 ;
      RECT 0.000 258.156 0.018 258.174 ;
    END
  END wd_in[410]
  PIN wd_in[411]
    DIRECTION INPUT ;
    USE SIGNAL ;
    SHAPE ABUTMENT ;
    PORT
      LAYER M4 ;
      RECT 0.000 258.336 0.018 258.354 ;
    END
  END wd_in[411]
  PIN wd_in[412]
    DIRECTION INPUT ;
    USE SIGNAL ;
    SHAPE ABUTMENT ;
    PORT
      LAYER M4 ;
      RECT 0.000 258.516 0.018 258.534 ;
    END
  END wd_in[412]
  PIN wd_in[413]
    DIRECTION INPUT ;
    USE SIGNAL ;
    SHAPE ABUTMENT ;
    PORT
      LAYER M4 ;
      RECT 0.000 258.696 0.018 258.714 ;
    END
  END wd_in[413]
  PIN wd_in[414]
    DIRECTION INPUT ;
    USE SIGNAL ;
    SHAPE ABUTMENT ;
    PORT
      LAYER M4 ;
      RECT 0.000 258.876 0.018 258.894 ;
    END
  END wd_in[414]
  PIN wd_in[415]
    DIRECTION INPUT ;
    USE SIGNAL ;
    SHAPE ABUTMENT ;
    PORT
      LAYER M4 ;
      RECT 0.000 259.056 0.018 259.074 ;
    END
  END wd_in[415]
  PIN wd_in[416]
    DIRECTION INPUT ;
    USE SIGNAL ;
    SHAPE ABUTMENT ;
    PORT
      LAYER M4 ;
      RECT 0.000 259.236 0.018 259.254 ;
    END
  END wd_in[416]
  PIN wd_in[417]
    DIRECTION INPUT ;
    USE SIGNAL ;
    SHAPE ABUTMENT ;
    PORT
      LAYER M4 ;
      RECT 0.000 259.416 0.018 259.434 ;
    END
  END wd_in[417]
  PIN wd_in[418]
    DIRECTION INPUT ;
    USE SIGNAL ;
    SHAPE ABUTMENT ;
    PORT
      LAYER M4 ;
      RECT 0.000 259.596 0.018 259.614 ;
    END
  END wd_in[418]
  PIN wd_in[419]
    DIRECTION INPUT ;
    USE SIGNAL ;
    SHAPE ABUTMENT ;
    PORT
      LAYER M4 ;
      RECT 0.000 259.776 0.018 259.794 ;
    END
  END wd_in[419]
  PIN wd_in[420]
    DIRECTION INPUT ;
    USE SIGNAL ;
    SHAPE ABUTMENT ;
    PORT
      LAYER M4 ;
      RECT 0.000 259.956 0.018 259.974 ;
    END
  END wd_in[420]
  PIN wd_in[421]
    DIRECTION INPUT ;
    USE SIGNAL ;
    SHAPE ABUTMENT ;
    PORT
      LAYER M4 ;
      RECT 0.000 260.136 0.018 260.154 ;
    END
  END wd_in[421]
  PIN wd_in[422]
    DIRECTION INPUT ;
    USE SIGNAL ;
    SHAPE ABUTMENT ;
    PORT
      LAYER M4 ;
      RECT 0.000 260.316 0.018 260.334 ;
    END
  END wd_in[422]
  PIN wd_in[423]
    DIRECTION INPUT ;
    USE SIGNAL ;
    SHAPE ABUTMENT ;
    PORT
      LAYER M4 ;
      RECT 0.000 260.496 0.018 260.514 ;
    END
  END wd_in[423]
  PIN wd_in[424]
    DIRECTION INPUT ;
    USE SIGNAL ;
    SHAPE ABUTMENT ;
    PORT
      LAYER M4 ;
      RECT 0.000 260.676 0.018 260.694 ;
    END
  END wd_in[424]
  PIN wd_in[425]
    DIRECTION INPUT ;
    USE SIGNAL ;
    SHAPE ABUTMENT ;
    PORT
      LAYER M4 ;
      RECT 0.000 260.856 0.018 260.874 ;
    END
  END wd_in[425]
  PIN wd_in[426]
    DIRECTION INPUT ;
    USE SIGNAL ;
    SHAPE ABUTMENT ;
    PORT
      LAYER M4 ;
      RECT 0.000 261.036 0.018 261.054 ;
    END
  END wd_in[426]
  PIN wd_in[427]
    DIRECTION INPUT ;
    USE SIGNAL ;
    SHAPE ABUTMENT ;
    PORT
      LAYER M4 ;
      RECT 0.000 261.216 0.018 261.234 ;
    END
  END wd_in[427]
  PIN wd_in[428]
    DIRECTION INPUT ;
    USE SIGNAL ;
    SHAPE ABUTMENT ;
    PORT
      LAYER M4 ;
      RECT 0.000 261.396 0.018 261.414 ;
    END
  END wd_in[428]
  PIN wd_in[429]
    DIRECTION INPUT ;
    USE SIGNAL ;
    SHAPE ABUTMENT ;
    PORT
      LAYER M4 ;
      RECT 0.000 261.576 0.018 261.594 ;
    END
  END wd_in[429]
  PIN wd_in[430]
    DIRECTION INPUT ;
    USE SIGNAL ;
    SHAPE ABUTMENT ;
    PORT
      LAYER M4 ;
      RECT 0.000 261.756 0.018 261.774 ;
    END
  END wd_in[430]
  PIN wd_in[431]
    DIRECTION INPUT ;
    USE SIGNAL ;
    SHAPE ABUTMENT ;
    PORT
      LAYER M4 ;
      RECT 0.000 261.936 0.018 261.954 ;
    END
  END wd_in[431]
  PIN wd_in[432]
    DIRECTION INPUT ;
    USE SIGNAL ;
    SHAPE ABUTMENT ;
    PORT
      LAYER M4 ;
      RECT 0.000 262.116 0.018 262.134 ;
    END
  END wd_in[432]
  PIN wd_in[433]
    DIRECTION INPUT ;
    USE SIGNAL ;
    SHAPE ABUTMENT ;
    PORT
      LAYER M4 ;
      RECT 0.000 262.296 0.018 262.314 ;
    END
  END wd_in[433]
  PIN wd_in[434]
    DIRECTION INPUT ;
    USE SIGNAL ;
    SHAPE ABUTMENT ;
    PORT
      LAYER M4 ;
      RECT 0.000 262.476 0.018 262.494 ;
    END
  END wd_in[434]
  PIN wd_in[435]
    DIRECTION INPUT ;
    USE SIGNAL ;
    SHAPE ABUTMENT ;
    PORT
      LAYER M4 ;
      RECT 0.000 262.656 0.018 262.674 ;
    END
  END wd_in[435]
  PIN wd_in[436]
    DIRECTION INPUT ;
    USE SIGNAL ;
    SHAPE ABUTMENT ;
    PORT
      LAYER M4 ;
      RECT 0.000 262.836 0.018 262.854 ;
    END
  END wd_in[436]
  PIN wd_in[437]
    DIRECTION INPUT ;
    USE SIGNAL ;
    SHAPE ABUTMENT ;
    PORT
      LAYER M4 ;
      RECT 0.000 263.016 0.018 263.034 ;
    END
  END wd_in[437]
  PIN wd_in[438]
    DIRECTION INPUT ;
    USE SIGNAL ;
    SHAPE ABUTMENT ;
    PORT
      LAYER M4 ;
      RECT 0.000 263.196 0.018 263.214 ;
    END
  END wd_in[438]
  PIN wd_in[439]
    DIRECTION INPUT ;
    USE SIGNAL ;
    SHAPE ABUTMENT ;
    PORT
      LAYER M4 ;
      RECT 0.000 263.376 0.018 263.394 ;
    END
  END wd_in[439]
  PIN wd_in[440]
    DIRECTION INPUT ;
    USE SIGNAL ;
    SHAPE ABUTMENT ;
    PORT
      LAYER M4 ;
      RECT 0.000 263.556 0.018 263.574 ;
    END
  END wd_in[440]
  PIN wd_in[441]
    DIRECTION INPUT ;
    USE SIGNAL ;
    SHAPE ABUTMENT ;
    PORT
      LAYER M4 ;
      RECT 0.000 263.736 0.018 263.754 ;
    END
  END wd_in[441]
  PIN wd_in[442]
    DIRECTION INPUT ;
    USE SIGNAL ;
    SHAPE ABUTMENT ;
    PORT
      LAYER M4 ;
      RECT 0.000 263.916 0.018 263.934 ;
    END
  END wd_in[442]
  PIN wd_in[443]
    DIRECTION INPUT ;
    USE SIGNAL ;
    SHAPE ABUTMENT ;
    PORT
      LAYER M4 ;
      RECT 0.000 264.096 0.018 264.114 ;
    END
  END wd_in[443]
  PIN wd_in[444]
    DIRECTION INPUT ;
    USE SIGNAL ;
    SHAPE ABUTMENT ;
    PORT
      LAYER M4 ;
      RECT 0.000 264.276 0.018 264.294 ;
    END
  END wd_in[444]
  PIN wd_in[445]
    DIRECTION INPUT ;
    USE SIGNAL ;
    SHAPE ABUTMENT ;
    PORT
      LAYER M4 ;
      RECT 0.000 264.456 0.018 264.474 ;
    END
  END wd_in[445]
  PIN wd_in[446]
    DIRECTION INPUT ;
    USE SIGNAL ;
    SHAPE ABUTMENT ;
    PORT
      LAYER M4 ;
      RECT 0.000 264.636 0.018 264.654 ;
    END
  END wd_in[446]
  PIN wd_in[447]
    DIRECTION INPUT ;
    USE SIGNAL ;
    SHAPE ABUTMENT ;
    PORT
      LAYER M4 ;
      RECT 0.000 264.816 0.018 264.834 ;
    END
  END wd_in[447]
  PIN wd_in[448]
    DIRECTION INPUT ;
    USE SIGNAL ;
    SHAPE ABUTMENT ;
    PORT
      LAYER M4 ;
      RECT 0.000 264.996 0.018 265.014 ;
    END
  END wd_in[448]
  PIN wd_in[449]
    DIRECTION INPUT ;
    USE SIGNAL ;
    SHAPE ABUTMENT ;
    PORT
      LAYER M4 ;
      RECT 0.000 265.176 0.018 265.194 ;
    END
  END wd_in[449]
  PIN wd_in[450]
    DIRECTION INPUT ;
    USE SIGNAL ;
    SHAPE ABUTMENT ;
    PORT
      LAYER M4 ;
      RECT 0.000 265.356 0.018 265.374 ;
    END
  END wd_in[450]
  PIN wd_in[451]
    DIRECTION INPUT ;
    USE SIGNAL ;
    SHAPE ABUTMENT ;
    PORT
      LAYER M4 ;
      RECT 0.000 265.536 0.018 265.554 ;
    END
  END wd_in[451]
  PIN wd_in[452]
    DIRECTION INPUT ;
    USE SIGNAL ;
    SHAPE ABUTMENT ;
    PORT
      LAYER M4 ;
      RECT 0.000 265.716 0.018 265.734 ;
    END
  END wd_in[452]
  PIN wd_in[453]
    DIRECTION INPUT ;
    USE SIGNAL ;
    SHAPE ABUTMENT ;
    PORT
      LAYER M4 ;
      RECT 0.000 265.896 0.018 265.914 ;
    END
  END wd_in[453]
  PIN wd_in[454]
    DIRECTION INPUT ;
    USE SIGNAL ;
    SHAPE ABUTMENT ;
    PORT
      LAYER M4 ;
      RECT 0.000 266.076 0.018 266.094 ;
    END
  END wd_in[454]
  PIN wd_in[455]
    DIRECTION INPUT ;
    USE SIGNAL ;
    SHAPE ABUTMENT ;
    PORT
      LAYER M4 ;
      RECT 0.000 266.256 0.018 266.274 ;
    END
  END wd_in[455]
  PIN wd_in[456]
    DIRECTION INPUT ;
    USE SIGNAL ;
    SHAPE ABUTMENT ;
    PORT
      LAYER M4 ;
      RECT 0.000 266.436 0.018 266.454 ;
    END
  END wd_in[456]
  PIN wd_in[457]
    DIRECTION INPUT ;
    USE SIGNAL ;
    SHAPE ABUTMENT ;
    PORT
      LAYER M4 ;
      RECT 0.000 266.616 0.018 266.634 ;
    END
  END wd_in[457]
  PIN wd_in[458]
    DIRECTION INPUT ;
    USE SIGNAL ;
    SHAPE ABUTMENT ;
    PORT
      LAYER M4 ;
      RECT 0.000 266.796 0.018 266.814 ;
    END
  END wd_in[458]
  PIN wd_in[459]
    DIRECTION INPUT ;
    USE SIGNAL ;
    SHAPE ABUTMENT ;
    PORT
      LAYER M4 ;
      RECT 0.000 266.976 0.018 266.994 ;
    END
  END wd_in[459]
  PIN wd_in[460]
    DIRECTION INPUT ;
    USE SIGNAL ;
    SHAPE ABUTMENT ;
    PORT
      LAYER M4 ;
      RECT 0.000 267.156 0.018 267.174 ;
    END
  END wd_in[460]
  PIN wd_in[461]
    DIRECTION INPUT ;
    USE SIGNAL ;
    SHAPE ABUTMENT ;
    PORT
      LAYER M4 ;
      RECT 0.000 267.336 0.018 267.354 ;
    END
  END wd_in[461]
  PIN wd_in[462]
    DIRECTION INPUT ;
    USE SIGNAL ;
    SHAPE ABUTMENT ;
    PORT
      LAYER M4 ;
      RECT 0.000 267.516 0.018 267.534 ;
    END
  END wd_in[462]
  PIN wd_in[463]
    DIRECTION INPUT ;
    USE SIGNAL ;
    SHAPE ABUTMENT ;
    PORT
      LAYER M4 ;
      RECT 0.000 267.696 0.018 267.714 ;
    END
  END wd_in[463]
  PIN wd_in[464]
    DIRECTION INPUT ;
    USE SIGNAL ;
    SHAPE ABUTMENT ;
    PORT
      LAYER M4 ;
      RECT 0.000 267.876 0.018 267.894 ;
    END
  END wd_in[464]
  PIN wd_in[465]
    DIRECTION INPUT ;
    USE SIGNAL ;
    SHAPE ABUTMENT ;
    PORT
      LAYER M4 ;
      RECT 0.000 268.056 0.018 268.074 ;
    END
  END wd_in[465]
  PIN wd_in[466]
    DIRECTION INPUT ;
    USE SIGNAL ;
    SHAPE ABUTMENT ;
    PORT
      LAYER M4 ;
      RECT 0.000 268.236 0.018 268.254 ;
    END
  END wd_in[466]
  PIN wd_in[467]
    DIRECTION INPUT ;
    USE SIGNAL ;
    SHAPE ABUTMENT ;
    PORT
      LAYER M4 ;
      RECT 0.000 268.416 0.018 268.434 ;
    END
  END wd_in[467]
  PIN wd_in[468]
    DIRECTION INPUT ;
    USE SIGNAL ;
    SHAPE ABUTMENT ;
    PORT
      LAYER M4 ;
      RECT 0.000 268.596 0.018 268.614 ;
    END
  END wd_in[468]
  PIN wd_in[469]
    DIRECTION INPUT ;
    USE SIGNAL ;
    SHAPE ABUTMENT ;
    PORT
      LAYER M4 ;
      RECT 0.000 268.776 0.018 268.794 ;
    END
  END wd_in[469]
  PIN wd_in[470]
    DIRECTION INPUT ;
    USE SIGNAL ;
    SHAPE ABUTMENT ;
    PORT
      LAYER M4 ;
      RECT 0.000 268.956 0.018 268.974 ;
    END
  END wd_in[470]
  PIN wd_in[471]
    DIRECTION INPUT ;
    USE SIGNAL ;
    SHAPE ABUTMENT ;
    PORT
      LAYER M4 ;
      RECT 0.000 269.136 0.018 269.154 ;
    END
  END wd_in[471]
  PIN wd_in[472]
    DIRECTION INPUT ;
    USE SIGNAL ;
    SHAPE ABUTMENT ;
    PORT
      LAYER M4 ;
      RECT 0.000 269.316 0.018 269.334 ;
    END
  END wd_in[472]
  PIN wd_in[473]
    DIRECTION INPUT ;
    USE SIGNAL ;
    SHAPE ABUTMENT ;
    PORT
      LAYER M4 ;
      RECT 0.000 269.496 0.018 269.514 ;
    END
  END wd_in[473]
  PIN wd_in[474]
    DIRECTION INPUT ;
    USE SIGNAL ;
    SHAPE ABUTMENT ;
    PORT
      LAYER M4 ;
      RECT 0.000 269.676 0.018 269.694 ;
    END
  END wd_in[474]
  PIN wd_in[475]
    DIRECTION INPUT ;
    USE SIGNAL ;
    SHAPE ABUTMENT ;
    PORT
      LAYER M4 ;
      RECT 0.000 269.856 0.018 269.874 ;
    END
  END wd_in[475]
  PIN wd_in[476]
    DIRECTION INPUT ;
    USE SIGNAL ;
    SHAPE ABUTMENT ;
    PORT
      LAYER M4 ;
      RECT 0.000 270.036 0.018 270.054 ;
    END
  END wd_in[476]
  PIN wd_in[477]
    DIRECTION INPUT ;
    USE SIGNAL ;
    SHAPE ABUTMENT ;
    PORT
      LAYER M4 ;
      RECT 0.000 270.216 0.018 270.234 ;
    END
  END wd_in[477]
  PIN wd_in[478]
    DIRECTION INPUT ;
    USE SIGNAL ;
    SHAPE ABUTMENT ;
    PORT
      LAYER M4 ;
      RECT 0.000 270.396 0.018 270.414 ;
    END
  END wd_in[478]
  PIN wd_in[479]
    DIRECTION INPUT ;
    USE SIGNAL ;
    SHAPE ABUTMENT ;
    PORT
      LAYER M4 ;
      RECT 0.000 270.576 0.018 270.594 ;
    END
  END wd_in[479]
  PIN wd_in[480]
    DIRECTION INPUT ;
    USE SIGNAL ;
    SHAPE ABUTMENT ;
    PORT
      LAYER M4 ;
      RECT 0.000 270.756 0.018 270.774 ;
    END
  END wd_in[480]
  PIN wd_in[481]
    DIRECTION INPUT ;
    USE SIGNAL ;
    SHAPE ABUTMENT ;
    PORT
      LAYER M4 ;
      RECT 0.000 270.936 0.018 270.954 ;
    END
  END wd_in[481]
  PIN wd_in[482]
    DIRECTION INPUT ;
    USE SIGNAL ;
    SHAPE ABUTMENT ;
    PORT
      LAYER M4 ;
      RECT 0.000 271.116 0.018 271.134 ;
    END
  END wd_in[482]
  PIN wd_in[483]
    DIRECTION INPUT ;
    USE SIGNAL ;
    SHAPE ABUTMENT ;
    PORT
      LAYER M4 ;
      RECT 0.000 271.296 0.018 271.314 ;
    END
  END wd_in[483]
  PIN wd_in[484]
    DIRECTION INPUT ;
    USE SIGNAL ;
    SHAPE ABUTMENT ;
    PORT
      LAYER M4 ;
      RECT 0.000 271.476 0.018 271.494 ;
    END
  END wd_in[484]
  PIN wd_in[485]
    DIRECTION INPUT ;
    USE SIGNAL ;
    SHAPE ABUTMENT ;
    PORT
      LAYER M4 ;
      RECT 0.000 271.656 0.018 271.674 ;
    END
  END wd_in[485]
  PIN wd_in[486]
    DIRECTION INPUT ;
    USE SIGNAL ;
    SHAPE ABUTMENT ;
    PORT
      LAYER M4 ;
      RECT 0.000 271.836 0.018 271.854 ;
    END
  END wd_in[486]
  PIN wd_in[487]
    DIRECTION INPUT ;
    USE SIGNAL ;
    SHAPE ABUTMENT ;
    PORT
      LAYER M4 ;
      RECT 0.000 272.016 0.018 272.034 ;
    END
  END wd_in[487]
  PIN wd_in[488]
    DIRECTION INPUT ;
    USE SIGNAL ;
    SHAPE ABUTMENT ;
    PORT
      LAYER M4 ;
      RECT 0.000 272.196 0.018 272.214 ;
    END
  END wd_in[488]
  PIN wd_in[489]
    DIRECTION INPUT ;
    USE SIGNAL ;
    SHAPE ABUTMENT ;
    PORT
      LAYER M4 ;
      RECT 0.000 272.376 0.018 272.394 ;
    END
  END wd_in[489]
  PIN wd_in[490]
    DIRECTION INPUT ;
    USE SIGNAL ;
    SHAPE ABUTMENT ;
    PORT
      LAYER M4 ;
      RECT 0.000 272.556 0.018 272.574 ;
    END
  END wd_in[490]
  PIN wd_in[491]
    DIRECTION INPUT ;
    USE SIGNAL ;
    SHAPE ABUTMENT ;
    PORT
      LAYER M4 ;
      RECT 0.000 272.736 0.018 272.754 ;
    END
  END wd_in[491]
  PIN wd_in[492]
    DIRECTION INPUT ;
    USE SIGNAL ;
    SHAPE ABUTMENT ;
    PORT
      LAYER M4 ;
      RECT 0.000 272.916 0.018 272.934 ;
    END
  END wd_in[492]
  PIN wd_in[493]
    DIRECTION INPUT ;
    USE SIGNAL ;
    SHAPE ABUTMENT ;
    PORT
      LAYER M4 ;
      RECT 0.000 273.096 0.018 273.114 ;
    END
  END wd_in[493]
  PIN wd_in[494]
    DIRECTION INPUT ;
    USE SIGNAL ;
    SHAPE ABUTMENT ;
    PORT
      LAYER M4 ;
      RECT 0.000 273.276 0.018 273.294 ;
    END
  END wd_in[494]
  PIN wd_in[495]
    DIRECTION INPUT ;
    USE SIGNAL ;
    SHAPE ABUTMENT ;
    PORT
      LAYER M4 ;
      RECT 0.000 273.456 0.018 273.474 ;
    END
  END wd_in[495]
  PIN wd_in[496]
    DIRECTION INPUT ;
    USE SIGNAL ;
    SHAPE ABUTMENT ;
    PORT
      LAYER M4 ;
      RECT 0.000 273.636 0.018 273.654 ;
    END
  END wd_in[496]
  PIN wd_in[497]
    DIRECTION INPUT ;
    USE SIGNAL ;
    SHAPE ABUTMENT ;
    PORT
      LAYER M4 ;
      RECT 0.000 273.816 0.018 273.834 ;
    END
  END wd_in[497]
  PIN wd_in[498]
    DIRECTION INPUT ;
    USE SIGNAL ;
    SHAPE ABUTMENT ;
    PORT
      LAYER M4 ;
      RECT 0.000 273.996 0.018 274.014 ;
    END
  END wd_in[498]
  PIN wd_in[499]
    DIRECTION INPUT ;
    USE SIGNAL ;
    SHAPE ABUTMENT ;
    PORT
      LAYER M4 ;
      RECT 0.000 274.176 0.018 274.194 ;
    END
  END wd_in[499]
  PIN wd_in[500]
    DIRECTION INPUT ;
    USE SIGNAL ;
    SHAPE ABUTMENT ;
    PORT
      LAYER M4 ;
      RECT 0.000 274.356 0.018 274.374 ;
    END
  END wd_in[500]
  PIN wd_in[501]
    DIRECTION INPUT ;
    USE SIGNAL ;
    SHAPE ABUTMENT ;
    PORT
      LAYER M4 ;
      RECT 0.000 274.536 0.018 274.554 ;
    END
  END wd_in[501]
  PIN wd_in[502]
    DIRECTION INPUT ;
    USE SIGNAL ;
    SHAPE ABUTMENT ;
    PORT
      LAYER M4 ;
      RECT 0.000 274.716 0.018 274.734 ;
    END
  END wd_in[502]
  PIN wd_in[503]
    DIRECTION INPUT ;
    USE SIGNAL ;
    SHAPE ABUTMENT ;
    PORT
      LAYER M4 ;
      RECT 0.000 274.896 0.018 274.914 ;
    END
  END wd_in[503]
  PIN wd_in[504]
    DIRECTION INPUT ;
    USE SIGNAL ;
    SHAPE ABUTMENT ;
    PORT
      LAYER M4 ;
      RECT 0.000 275.076 0.018 275.094 ;
    END
  END wd_in[504]
  PIN wd_in[505]
    DIRECTION INPUT ;
    USE SIGNAL ;
    SHAPE ABUTMENT ;
    PORT
      LAYER M4 ;
      RECT 0.000 275.256 0.018 275.274 ;
    END
  END wd_in[505]
  PIN wd_in[506]
    DIRECTION INPUT ;
    USE SIGNAL ;
    SHAPE ABUTMENT ;
    PORT
      LAYER M4 ;
      RECT 0.000 275.436 0.018 275.454 ;
    END
  END wd_in[506]
  PIN wd_in[507]
    DIRECTION INPUT ;
    USE SIGNAL ;
    SHAPE ABUTMENT ;
    PORT
      LAYER M4 ;
      RECT 0.000 275.616 0.018 275.634 ;
    END
  END wd_in[507]
  PIN wd_in[508]
    DIRECTION INPUT ;
    USE SIGNAL ;
    SHAPE ABUTMENT ;
    PORT
      LAYER M4 ;
      RECT 0.000 275.796 0.018 275.814 ;
    END
  END wd_in[508]
  PIN wd_in[509]
    DIRECTION INPUT ;
    USE SIGNAL ;
    SHAPE ABUTMENT ;
    PORT
      LAYER M4 ;
      RECT 0.000 275.976 0.018 275.994 ;
    END
  END wd_in[509]
  PIN wd_in[510]
    DIRECTION INPUT ;
    USE SIGNAL ;
    SHAPE ABUTMENT ;
    PORT
      LAYER M4 ;
      RECT 0.000 276.156 0.018 276.174 ;
    END
  END wd_in[510]
  PIN wd_in[511]
    DIRECTION INPUT ;
    USE SIGNAL ;
    SHAPE ABUTMENT ;
    PORT
      LAYER M4 ;
      RECT 0.000 276.336 0.018 276.354 ;
    END
  END wd_in[511]
  PIN raddr0_in[0]
    DIRECTION INPUT ;
    USE SIGNAL ;
    SHAPE ABUTMENT ;
    PORT
      LAYER M4 ;
      RECT 0.000 276.516 0.018 276.534 ;
    END
  END raddr0_in[0]
  PIN raddr0_in[1]
    DIRECTION INPUT ;
    USE SIGNAL ;
    SHAPE ABUTMENT ;
    PORT
      LAYER M4 ;
      RECT 0.000 276.696 0.018 276.714 ;
    END
  END raddr0_in[1]
  PIN raddr0_in[2]
    DIRECTION INPUT ;
    USE SIGNAL ;
    SHAPE ABUTMENT ;
    PORT
      LAYER M4 ;
      RECT 0.000 276.876 0.018 276.894 ;
    END
  END raddr0_in[2]
  PIN raddr0_in[3]
    DIRECTION INPUT ;
    USE SIGNAL ;
    SHAPE ABUTMENT ;
    PORT
      LAYER M4 ;
      RECT 0.000 277.056 0.018 277.074 ;
    END
  END raddr0_in[3]
  PIN raddr0_in[4]
    DIRECTION INPUT ;
    USE SIGNAL ;
    SHAPE ABUTMENT ;
    PORT
      LAYER M4 ;
      RECT 0.000 277.236 0.018 277.254 ;
    END
  END raddr0_in[4]
  PIN raddr0_in[5]
    DIRECTION INPUT ;
    USE SIGNAL ;
    SHAPE ABUTMENT ;
    PORT
      LAYER M4 ;
      RECT 0.000 277.416 0.018 277.434 ;
    END
  END raddr0_in[5]
  PIN raddr0_in[6]
    DIRECTION INPUT ;
    USE SIGNAL ;
    SHAPE ABUTMENT ;
    PORT
      LAYER M4 ;
      RECT 0.000 277.596 0.018 277.614 ;
    END
  END raddr0_in[6]
  PIN raddr0_in[7]
    DIRECTION INPUT ;
    USE SIGNAL ;
    SHAPE ABUTMENT ;
    PORT
      LAYER M4 ;
      RECT 0.000 277.776 0.018 277.794 ;
    END
  END raddr0_in[7]
  PIN raddr0_in[8]
    DIRECTION INPUT ;
    USE SIGNAL ;
    SHAPE ABUTMENT ;
    PORT
      LAYER M4 ;
      RECT 0.000 277.956 0.018 277.974 ;
    END
  END raddr0_in[8]
  PIN raddr0_in[9]
    DIRECTION INPUT ;
    USE SIGNAL ;
    SHAPE ABUTMENT ;
    PORT
      LAYER M4 ;
      RECT 0.000 278.136 0.018 278.154 ;
    END
  END raddr0_in[9]
  PIN raddr0_in[10]
    DIRECTION INPUT ;
    USE SIGNAL ;
    SHAPE ABUTMENT ;
    PORT
      LAYER M4 ;
      RECT 0.000 278.316 0.018 278.334 ;
    END
  END raddr0_in[10]
  PIN raddr0_in[11]
    DIRECTION INPUT ;
    USE SIGNAL ;
    SHAPE ABUTMENT ;
    PORT
      LAYER M4 ;
      RECT 0.000 278.496 0.018 278.514 ;
    END
  END raddr0_in[11]
  PIN raddr1_in[0]
    DIRECTION INPUT ;
    USE SIGNAL ;
    SHAPE ABUTMENT ;
    PORT
      LAYER M4 ;
      RECT 0.000 278.676 0.018 278.694 ;
    END
  END raddr1_in[0]
  PIN raddr1_in[1]
    DIRECTION INPUT ;
    USE SIGNAL ;
    SHAPE ABUTMENT ;
    PORT
      LAYER M4 ;
      RECT 0.000 278.856 0.018 278.874 ;
    END
  END raddr1_in[1]
  PIN raddr1_in[2]
    DIRECTION INPUT ;
    USE SIGNAL ;
    SHAPE ABUTMENT ;
    PORT
      LAYER M4 ;
      RECT 0.000 279.036 0.018 279.054 ;
    END
  END raddr1_in[2]
  PIN raddr1_in[3]
    DIRECTION INPUT ;
    USE SIGNAL ;
    SHAPE ABUTMENT ;
    PORT
      LAYER M4 ;
      RECT 0.000 279.216 0.018 279.234 ;
    END
  END raddr1_in[3]
  PIN raddr1_in[4]
    DIRECTION INPUT ;
    USE SIGNAL ;
    SHAPE ABUTMENT ;
    PORT
      LAYER M4 ;
      RECT 0.000 279.396 0.018 279.414 ;
    END
  END raddr1_in[4]
  PIN raddr1_in[5]
    DIRECTION INPUT ;
    USE SIGNAL ;
    SHAPE ABUTMENT ;
    PORT
      LAYER M4 ;
      RECT 0.000 279.576 0.018 279.594 ;
    END
  END raddr1_in[5]
  PIN raddr1_in[6]
    DIRECTION INPUT ;
    USE SIGNAL ;
    SHAPE ABUTMENT ;
    PORT
      LAYER M4 ;
      RECT 0.000 279.756 0.018 279.774 ;
    END
  END raddr1_in[6]
  PIN raddr1_in[7]
    DIRECTION INPUT ;
    USE SIGNAL ;
    SHAPE ABUTMENT ;
    PORT
      LAYER M4 ;
      RECT 0.000 279.936 0.018 279.954 ;
    END
  END raddr1_in[7]
  PIN raddr1_in[8]
    DIRECTION INPUT ;
    USE SIGNAL ;
    SHAPE ABUTMENT ;
    PORT
      LAYER M4 ;
      RECT 0.000 280.116 0.018 280.134 ;
    END
  END raddr1_in[8]
  PIN raddr1_in[9]
    DIRECTION INPUT ;
    USE SIGNAL ;
    SHAPE ABUTMENT ;
    PORT
      LAYER M4 ;
      RECT 0.000 280.296 0.018 280.314 ;
    END
  END raddr1_in[9]
  PIN raddr1_in[10]
    DIRECTION INPUT ;
    USE SIGNAL ;
    SHAPE ABUTMENT ;
    PORT
      LAYER M4 ;
      RECT 0.000 280.476 0.018 280.494 ;
    END
  END raddr1_in[10]
  PIN raddr1_in[11]
    DIRECTION INPUT ;
    USE SIGNAL ;
    SHAPE ABUTMENT ;
    PORT
      LAYER M4 ;
      RECT 0.000 280.656 0.018 280.674 ;
    END
  END raddr1_in[11]
  PIN waddr_in[0]
    DIRECTION INPUT ;
    USE SIGNAL ;
    SHAPE ABUTMENT ;
    PORT
      LAYER M4 ;
      RECT 0.000 280.836 0.018 280.854 ;
    END
  END waddr_in[0]
  PIN waddr_in[1]
    DIRECTION INPUT ;
    USE SIGNAL ;
    SHAPE ABUTMENT ;
    PORT
      LAYER M4 ;
      RECT 0.000 281.016 0.018 281.034 ;
    END
  END waddr_in[1]
  PIN waddr_in[2]
    DIRECTION INPUT ;
    USE SIGNAL ;
    SHAPE ABUTMENT ;
    PORT
      LAYER M4 ;
      RECT 0.000 281.196 0.018 281.214 ;
    END
  END waddr_in[2]
  PIN waddr_in[3]
    DIRECTION INPUT ;
    USE SIGNAL ;
    SHAPE ABUTMENT ;
    PORT
      LAYER M4 ;
      RECT 0.000 281.376 0.018 281.394 ;
    END
  END waddr_in[3]
  PIN waddr_in[4]
    DIRECTION INPUT ;
    USE SIGNAL ;
    SHAPE ABUTMENT ;
    PORT
      LAYER M4 ;
      RECT 0.000 281.556 0.018 281.574 ;
    END
  END waddr_in[4]
  PIN waddr_in[5]
    DIRECTION INPUT ;
    USE SIGNAL ;
    SHAPE ABUTMENT ;
    PORT
      LAYER M4 ;
      RECT 0.000 281.736 0.018 281.754 ;
    END
  END waddr_in[5]
  PIN waddr_in[6]
    DIRECTION INPUT ;
    USE SIGNAL ;
    SHAPE ABUTMENT ;
    PORT
      LAYER M4 ;
      RECT 0.000 281.916 0.018 281.934 ;
    END
  END waddr_in[6]
  PIN waddr_in[7]
    DIRECTION INPUT ;
    USE SIGNAL ;
    SHAPE ABUTMENT ;
    PORT
      LAYER M4 ;
      RECT 0.000 282.096 0.018 282.114 ;
    END
  END waddr_in[7]
  PIN waddr_in[8]
    DIRECTION INPUT ;
    USE SIGNAL ;
    SHAPE ABUTMENT ;
    PORT
      LAYER M4 ;
      RECT 0.000 282.276 0.018 282.294 ;
    END
  END waddr_in[8]
  PIN waddr_in[9]
    DIRECTION INPUT ;
    USE SIGNAL ;
    SHAPE ABUTMENT ;
    PORT
      LAYER M4 ;
      RECT 0.000 282.456 0.018 282.474 ;
    END
  END waddr_in[9]
  PIN waddr_in[10]
    DIRECTION INPUT ;
    USE SIGNAL ;
    SHAPE ABUTMENT ;
    PORT
      LAYER M4 ;
      RECT 0.000 282.636 0.018 282.654 ;
    END
  END waddr_in[10]
  PIN waddr_in[11]
    DIRECTION INPUT ;
    USE SIGNAL ;
    SHAPE ABUTMENT ;
    PORT
      LAYER M4 ;
      RECT 0.000 282.816 0.018 282.834 ;
    END
  END waddr_in[11]
  PIN we_in
    DIRECTION INPUT ;
    USE SIGNAL ;
    SHAPE ABUTMENT ;
    PORT
      LAYER M4 ;
      RECT 0.000 282.996 0.018 283.014 ;
    END
  END we_in
  PIN ce_in
    DIRECTION INPUT ;
    USE SIGNAL ;
    SHAPE ABUTMENT ;
    PORT
      LAYER M4 ;
      RECT 0.000 283.176 0.018 283.194 ;
    END
  END ce_in
  PIN clk
    DIRECTION INPUT ;
    USE SIGNAL ;
    SHAPE ABUTMENT ;
    PORT
      LAYER M4 ;
      RECT 0.000 283.356 0.018 283.374 ;
    END
  END clk
  PIN VSS
    DIRECTION INOUT ;
    USE GROUND ;
    PORT
      LAYER M4 ;
      RECT 0.036 0.000 471.823 0.072 ;
      RECT 0.036 0.576 471.823 0.648 ;
      RECT 0.036 1.152 471.823 1.224 ;
      RECT 0.036 1.728 471.823 1.800 ;
      RECT 0.036 2.304 471.823 2.376 ;
      RECT 0.036 2.880 471.823 2.952 ;
      RECT 0.036 3.456 471.823 3.528 ;
      RECT 0.036 4.032 471.823 4.104 ;
      RECT 0.036 4.608 471.823 4.680 ;
      RECT 0.036 5.184 471.823 5.256 ;
      RECT 0.036 5.760 471.823 5.832 ;
      RECT 0.036 6.336 471.823 6.408 ;
      RECT 0.036 6.912 471.823 6.984 ;
      RECT 0.036 7.488 471.823 7.560 ;
      RECT 0.036 8.064 471.823 8.136 ;
      RECT 0.036 8.640 471.823 8.712 ;
      RECT 0.036 9.216 471.823 9.288 ;
      RECT 0.036 9.792 471.823 9.864 ;
      RECT 0.036 10.368 471.823 10.440 ;
      RECT 0.036 10.944 471.823 11.016 ;
      RECT 0.036 11.520 471.823 11.592 ;
      RECT 0.036 12.096 471.823 12.168 ;
      RECT 0.036 12.672 471.823 12.744 ;
      RECT 0.036 13.248 471.823 13.320 ;
      RECT 0.036 13.824 471.823 13.896 ;
      RECT 0.036 14.400 471.823 14.472 ;
      RECT 0.036 14.976 471.823 15.048 ;
      RECT 0.036 15.552 471.823 15.624 ;
      RECT 0.036 16.128 471.823 16.200 ;
      RECT 0.036 16.704 471.823 16.776 ;
      RECT 0.036 17.280 471.823 17.352 ;
      RECT 0.036 17.856 471.823 17.928 ;
      RECT 0.036 18.432 471.823 18.504 ;
      RECT 0.036 19.008 471.823 19.080 ;
      RECT 0.036 19.584 471.823 19.656 ;
      RECT 0.036 20.160 471.823 20.232 ;
      RECT 0.036 20.736 471.823 20.808 ;
      RECT 0.036 21.312 471.823 21.384 ;
      RECT 0.036 21.888 471.823 21.960 ;
      RECT 0.036 22.464 471.823 22.536 ;
      RECT 0.036 23.040 471.823 23.112 ;
      RECT 0.036 23.616 471.823 23.688 ;
      RECT 0.036 24.192 471.823 24.264 ;
      RECT 0.036 24.768 471.823 24.840 ;
      RECT 0.036 25.344 471.823 25.416 ;
      RECT 0.036 25.920 471.823 25.992 ;
      RECT 0.036 26.496 471.823 26.568 ;
      RECT 0.036 27.072 471.823 27.144 ;
      RECT 0.036 27.648 471.823 27.720 ;
      RECT 0.036 28.224 471.823 28.296 ;
      RECT 0.036 28.800 471.823 28.872 ;
      RECT 0.036 29.376 471.823 29.448 ;
      RECT 0.036 29.952 471.823 30.024 ;
      RECT 0.036 30.528 471.823 30.600 ;
      RECT 0.036 31.104 471.823 31.176 ;
      RECT 0.036 31.680 471.823 31.752 ;
      RECT 0.036 32.256 471.823 32.328 ;
      RECT 0.036 32.832 471.823 32.904 ;
      RECT 0.036 33.408 471.823 33.480 ;
      RECT 0.036 33.984 471.823 34.056 ;
      RECT 0.036 34.560 471.823 34.632 ;
      RECT 0.036 35.136 471.823 35.208 ;
      RECT 0.036 35.712 471.823 35.784 ;
      RECT 0.036 36.288 471.823 36.360 ;
      RECT 0.036 36.864 471.823 36.936 ;
      RECT 0.036 37.440 471.823 37.512 ;
      RECT 0.036 38.016 471.823 38.088 ;
      RECT 0.036 38.592 471.823 38.664 ;
      RECT 0.036 39.168 471.823 39.240 ;
      RECT 0.036 39.744 471.823 39.816 ;
      RECT 0.036 40.320 471.823 40.392 ;
      RECT 0.036 40.896 471.823 40.968 ;
      RECT 0.036 41.472 471.823 41.544 ;
      RECT 0.036 42.048 471.823 42.120 ;
      RECT 0.036 42.624 471.823 42.696 ;
      RECT 0.036 43.200 471.823 43.272 ;
      RECT 0.036 43.776 471.823 43.848 ;
      RECT 0.036 44.352 471.823 44.424 ;
      RECT 0.036 44.928 471.823 45.000 ;
      RECT 0.036 45.504 471.823 45.576 ;
      RECT 0.036 46.080 471.823 46.152 ;
      RECT 0.036 46.656 471.823 46.728 ;
      RECT 0.036 47.232 471.823 47.304 ;
      RECT 0.036 47.808 471.823 47.880 ;
      RECT 0.036 48.384 471.823 48.456 ;
      RECT 0.036 48.960 471.823 49.032 ;
      RECT 0.036 49.536 471.823 49.608 ;
      RECT 0.036 50.112 471.823 50.184 ;
      RECT 0.036 50.688 471.823 50.760 ;
      RECT 0.036 51.264 471.823 51.336 ;
      RECT 0.036 51.840 471.823 51.912 ;
      RECT 0.036 52.416 471.823 52.488 ;
      RECT 0.036 52.992 471.823 53.064 ;
      RECT 0.036 53.568 471.823 53.640 ;
      RECT 0.036 54.144 471.823 54.216 ;
      RECT 0.036 54.720 471.823 54.792 ;
      RECT 0.036 55.296 471.823 55.368 ;
      RECT 0.036 55.872 471.823 55.944 ;
      RECT 0.036 56.448 471.823 56.520 ;
      RECT 0.036 57.024 471.823 57.096 ;
      RECT 0.036 57.600 471.823 57.672 ;
      RECT 0.036 58.176 471.823 58.248 ;
      RECT 0.036 58.752 471.823 58.824 ;
      RECT 0.036 59.328 471.823 59.400 ;
      RECT 0.036 59.904 471.823 59.976 ;
      RECT 0.036 60.480 471.823 60.552 ;
      RECT 0.036 61.056 471.823 61.128 ;
      RECT 0.036 61.632 471.823 61.704 ;
      RECT 0.036 62.208 471.823 62.280 ;
      RECT 0.036 62.784 471.823 62.856 ;
      RECT 0.036 63.360 471.823 63.432 ;
      RECT 0.036 63.936 471.823 64.008 ;
      RECT 0.036 64.512 471.823 64.584 ;
      RECT 0.036 65.088 471.823 65.160 ;
      RECT 0.036 65.664 471.823 65.736 ;
      RECT 0.036 66.240 471.823 66.312 ;
      RECT 0.036 66.816 471.823 66.888 ;
      RECT 0.036 67.392 471.823 67.464 ;
      RECT 0.036 67.968 471.823 68.040 ;
      RECT 0.036 68.544 471.823 68.616 ;
      RECT 0.036 69.120 471.823 69.192 ;
      RECT 0.036 69.696 471.823 69.768 ;
      RECT 0.036 70.272 471.823 70.344 ;
      RECT 0.036 70.848 471.823 70.920 ;
      RECT 0.036 71.424 471.823 71.496 ;
      RECT 0.036 72.000 471.823 72.072 ;
      RECT 0.036 72.576 471.823 72.648 ;
      RECT 0.036 73.152 471.823 73.224 ;
      RECT 0.036 73.728 471.823 73.800 ;
      RECT 0.036 74.304 471.823 74.376 ;
      RECT 0.036 74.880 471.823 74.952 ;
      RECT 0.036 75.456 471.823 75.528 ;
      RECT 0.036 76.032 471.823 76.104 ;
      RECT 0.036 76.608 471.823 76.680 ;
      RECT 0.036 77.184 471.823 77.256 ;
      RECT 0.036 77.760 471.823 77.832 ;
      RECT 0.036 78.336 471.823 78.408 ;
      RECT 0.036 78.912 471.823 78.984 ;
      RECT 0.036 79.488 471.823 79.560 ;
      RECT 0.036 80.064 471.823 80.136 ;
      RECT 0.036 80.640 471.823 80.712 ;
      RECT 0.036 81.216 471.823 81.288 ;
      RECT 0.036 81.792 471.823 81.864 ;
      RECT 0.036 82.368 471.823 82.440 ;
      RECT 0.036 82.944 471.823 83.016 ;
      RECT 0.036 83.520 471.823 83.592 ;
      RECT 0.036 84.096 471.823 84.168 ;
      RECT 0.036 84.672 471.823 84.744 ;
      RECT 0.036 85.248 471.823 85.320 ;
      RECT 0.036 85.824 471.823 85.896 ;
      RECT 0.036 86.400 471.823 86.472 ;
      RECT 0.036 86.976 471.823 87.048 ;
      RECT 0.036 87.552 471.823 87.624 ;
      RECT 0.036 88.128 471.823 88.200 ;
      RECT 0.036 88.704 471.823 88.776 ;
      RECT 0.036 89.280 471.823 89.352 ;
      RECT 0.036 89.856 471.823 89.928 ;
      RECT 0.036 90.432 471.823 90.504 ;
      RECT 0.036 91.008 471.823 91.080 ;
      RECT 0.036 91.584 471.823 91.656 ;
      RECT 0.036 92.160 471.823 92.232 ;
      RECT 0.036 92.736 471.823 92.808 ;
      RECT 0.036 93.312 471.823 93.384 ;
      RECT 0.036 93.888 471.823 93.960 ;
      RECT 0.036 94.464 471.823 94.536 ;
      RECT 0.036 95.040 471.823 95.112 ;
      RECT 0.036 95.616 471.823 95.688 ;
      RECT 0.036 96.192 471.823 96.264 ;
      RECT 0.036 96.768 471.823 96.840 ;
      RECT 0.036 97.344 471.823 97.416 ;
      RECT 0.036 97.920 471.823 97.992 ;
      RECT 0.036 98.496 471.823 98.568 ;
      RECT 0.036 99.072 471.823 99.144 ;
      RECT 0.036 99.648 471.823 99.720 ;
      RECT 0.036 100.224 471.823 100.296 ;
      RECT 0.036 100.800 471.823 100.872 ;
      RECT 0.036 101.376 471.823 101.448 ;
      RECT 0.036 101.952 471.823 102.024 ;
      RECT 0.036 102.528 471.823 102.600 ;
      RECT 0.036 103.104 471.823 103.176 ;
      RECT 0.036 103.680 471.823 103.752 ;
      RECT 0.036 104.256 471.823 104.328 ;
      RECT 0.036 104.832 471.823 104.904 ;
      RECT 0.036 105.408 471.823 105.480 ;
      RECT 0.036 105.984 471.823 106.056 ;
      RECT 0.036 106.560 471.823 106.632 ;
      RECT 0.036 107.136 471.823 107.208 ;
      RECT 0.036 107.712 471.823 107.784 ;
      RECT 0.036 108.288 471.823 108.360 ;
      RECT 0.036 108.864 471.823 108.936 ;
      RECT 0.036 109.440 471.823 109.512 ;
      RECT 0.036 110.016 471.823 110.088 ;
      RECT 0.036 110.592 471.823 110.664 ;
      RECT 0.036 111.168 471.823 111.240 ;
      RECT 0.036 111.744 471.823 111.816 ;
      RECT 0.036 112.320 471.823 112.392 ;
      RECT 0.036 112.896 471.823 112.968 ;
      RECT 0.036 113.472 471.823 113.544 ;
      RECT 0.036 114.048 471.823 114.120 ;
      RECT 0.036 114.624 471.823 114.696 ;
      RECT 0.036 115.200 471.823 115.272 ;
      RECT 0.036 115.776 471.823 115.848 ;
      RECT 0.036 116.352 471.823 116.424 ;
      RECT 0.036 116.928 471.823 117.000 ;
      RECT 0.036 117.504 471.823 117.576 ;
      RECT 0.036 118.080 471.823 118.152 ;
      RECT 0.036 118.656 471.823 118.728 ;
      RECT 0.036 119.232 471.823 119.304 ;
      RECT 0.036 119.808 471.823 119.880 ;
      RECT 0.036 120.384 471.823 120.456 ;
      RECT 0.036 120.960 471.823 121.032 ;
      RECT 0.036 121.536 471.823 121.608 ;
      RECT 0.036 122.112 471.823 122.184 ;
      RECT 0.036 122.688 471.823 122.760 ;
      RECT 0.036 123.264 471.823 123.336 ;
      RECT 0.036 123.840 471.823 123.912 ;
      RECT 0.036 124.416 471.823 124.488 ;
      RECT 0.036 124.992 471.823 125.064 ;
      RECT 0.036 125.568 471.823 125.640 ;
      RECT 0.036 126.144 471.823 126.216 ;
      RECT 0.036 126.720 471.823 126.792 ;
      RECT 0.036 127.296 471.823 127.368 ;
      RECT 0.036 127.872 471.823 127.944 ;
      RECT 0.036 128.448 471.823 128.520 ;
      RECT 0.036 129.024 471.823 129.096 ;
      RECT 0.036 129.600 471.823 129.672 ;
      RECT 0.036 130.176 471.823 130.248 ;
      RECT 0.036 130.752 471.823 130.824 ;
      RECT 0.036 131.328 471.823 131.400 ;
      RECT 0.036 131.904 471.823 131.976 ;
      RECT 0.036 132.480 471.823 132.552 ;
      RECT 0.036 133.056 471.823 133.128 ;
      RECT 0.036 133.632 471.823 133.704 ;
      RECT 0.036 134.208 471.823 134.280 ;
      RECT 0.036 134.784 471.823 134.856 ;
      RECT 0.036 135.360 471.823 135.432 ;
      RECT 0.036 135.936 471.823 136.008 ;
      RECT 0.036 136.512 471.823 136.584 ;
      RECT 0.036 137.088 471.823 137.160 ;
      RECT 0.036 137.664 471.823 137.736 ;
      RECT 0.036 138.240 471.823 138.312 ;
      RECT 0.036 138.816 471.823 138.888 ;
      RECT 0.036 139.392 471.823 139.464 ;
      RECT 0.036 139.968 471.823 140.040 ;
      RECT 0.036 140.544 471.823 140.616 ;
      RECT 0.036 141.120 471.823 141.192 ;
      RECT 0.036 141.696 471.823 141.768 ;
      RECT 0.036 142.272 471.823 142.344 ;
      RECT 0.036 142.848 471.823 142.920 ;
      RECT 0.036 143.424 471.823 143.496 ;
      RECT 0.036 144.000 471.823 144.072 ;
      RECT 0.036 144.576 471.823 144.648 ;
      RECT 0.036 145.152 471.823 145.224 ;
      RECT 0.036 145.728 471.823 145.800 ;
      RECT 0.036 146.304 471.823 146.376 ;
      RECT 0.036 146.880 471.823 146.952 ;
      RECT 0.036 147.456 471.823 147.528 ;
      RECT 0.036 148.032 471.823 148.104 ;
      RECT 0.036 148.608 471.823 148.680 ;
      RECT 0.036 149.184 471.823 149.256 ;
      RECT 0.036 149.760 471.823 149.832 ;
      RECT 0.036 150.336 471.823 150.408 ;
      RECT 0.036 150.912 471.823 150.984 ;
      RECT 0.036 151.488 471.823 151.560 ;
      RECT 0.036 152.064 471.823 152.136 ;
      RECT 0.036 152.640 471.823 152.712 ;
      RECT 0.036 153.216 471.823 153.288 ;
      RECT 0.036 153.792 471.823 153.864 ;
      RECT 0.036 154.368 471.823 154.440 ;
      RECT 0.036 154.944 471.823 155.016 ;
      RECT 0.036 155.520 471.823 155.592 ;
      RECT 0.036 156.096 471.823 156.168 ;
      RECT 0.036 156.672 471.823 156.744 ;
      RECT 0.036 157.248 471.823 157.320 ;
      RECT 0.036 157.824 471.823 157.896 ;
      RECT 0.036 158.400 471.823 158.472 ;
      RECT 0.036 158.976 471.823 159.048 ;
      RECT 0.036 159.552 471.823 159.624 ;
      RECT 0.036 160.128 471.823 160.200 ;
      RECT 0.036 160.704 471.823 160.776 ;
      RECT 0.036 161.280 471.823 161.352 ;
      RECT 0.036 161.856 471.823 161.928 ;
      RECT 0.036 162.432 471.823 162.504 ;
      RECT 0.036 163.008 471.823 163.080 ;
      RECT 0.036 163.584 471.823 163.656 ;
      RECT 0.036 164.160 471.823 164.232 ;
      RECT 0.036 164.736 471.823 164.808 ;
      RECT 0.036 165.312 471.823 165.384 ;
      RECT 0.036 165.888 471.823 165.960 ;
      RECT 0.036 166.464 471.823 166.536 ;
      RECT 0.036 167.040 471.823 167.112 ;
      RECT 0.036 167.616 471.823 167.688 ;
      RECT 0.036 168.192 471.823 168.264 ;
      RECT 0.036 168.768 471.823 168.840 ;
      RECT 0.036 169.344 471.823 169.416 ;
      RECT 0.036 169.920 471.823 169.992 ;
      RECT 0.036 170.496 471.823 170.568 ;
      RECT 0.036 171.072 471.823 171.144 ;
      RECT 0.036 171.648 471.823 171.720 ;
      RECT 0.036 172.224 471.823 172.296 ;
      RECT 0.036 172.800 471.823 172.872 ;
      RECT 0.036 173.376 471.823 173.448 ;
      RECT 0.036 173.952 471.823 174.024 ;
      RECT 0.036 174.528 471.823 174.600 ;
      RECT 0.036 175.104 471.823 175.176 ;
      RECT 0.036 175.680 471.823 175.752 ;
      RECT 0.036 176.256 471.823 176.328 ;
      RECT 0.036 176.832 471.823 176.904 ;
      RECT 0.036 177.408 471.823 177.480 ;
      RECT 0.036 177.984 471.823 178.056 ;
      RECT 0.036 178.560 471.823 178.632 ;
      RECT 0.036 179.136 471.823 179.208 ;
      RECT 0.036 179.712 471.823 179.784 ;
      RECT 0.036 180.288 471.823 180.360 ;
      RECT 0.036 180.864 471.823 180.936 ;
      RECT 0.036 181.440 471.823 181.512 ;
      RECT 0.036 182.016 471.823 182.088 ;
      RECT 0.036 182.592 471.823 182.664 ;
      RECT 0.036 183.168 471.823 183.240 ;
      RECT 0.036 183.744 471.823 183.816 ;
      RECT 0.036 184.320 471.823 184.392 ;
      RECT 0.036 184.896 471.823 184.968 ;
      RECT 0.036 185.472 471.823 185.544 ;
      RECT 0.036 186.048 471.823 186.120 ;
      RECT 0.036 186.624 471.823 186.696 ;
      RECT 0.036 187.200 471.823 187.272 ;
      RECT 0.036 187.776 471.823 187.848 ;
      RECT 0.036 188.352 471.823 188.424 ;
      RECT 0.036 188.928 471.823 189.000 ;
      RECT 0.036 189.504 471.823 189.576 ;
      RECT 0.036 190.080 471.823 190.152 ;
      RECT 0.036 190.656 471.823 190.728 ;
      RECT 0.036 191.232 471.823 191.304 ;
      RECT 0.036 191.808 471.823 191.880 ;
      RECT 0.036 192.384 471.823 192.456 ;
      RECT 0.036 192.960 471.823 193.032 ;
      RECT 0.036 193.536 471.823 193.608 ;
      RECT 0.036 194.112 471.823 194.184 ;
      RECT 0.036 194.688 471.823 194.760 ;
      RECT 0.036 195.264 471.823 195.336 ;
      RECT 0.036 195.840 471.823 195.912 ;
      RECT 0.036 196.416 471.823 196.488 ;
      RECT 0.036 196.992 471.823 197.064 ;
      RECT 0.036 197.568 471.823 197.640 ;
      RECT 0.036 198.144 471.823 198.216 ;
      RECT 0.036 198.720 471.823 198.792 ;
      RECT 0.036 199.296 471.823 199.368 ;
      RECT 0.036 199.872 471.823 199.944 ;
      RECT 0.036 200.448 471.823 200.520 ;
      RECT 0.036 201.024 471.823 201.096 ;
      RECT 0.036 201.600 471.823 201.672 ;
      RECT 0.036 202.176 471.823 202.248 ;
      RECT 0.036 202.752 471.823 202.824 ;
      RECT 0.036 203.328 471.823 203.400 ;
      RECT 0.036 203.904 471.823 203.976 ;
      RECT 0.036 204.480 471.823 204.552 ;
      RECT 0.036 205.056 471.823 205.128 ;
      RECT 0.036 205.632 471.823 205.704 ;
      RECT 0.036 206.208 471.823 206.280 ;
      RECT 0.036 206.784 471.823 206.856 ;
      RECT 0.036 207.360 471.823 207.432 ;
      RECT 0.036 207.936 471.823 208.008 ;
      RECT 0.036 208.512 471.823 208.584 ;
      RECT 0.036 209.088 471.823 209.160 ;
      RECT 0.036 209.664 471.823 209.736 ;
      RECT 0.036 210.240 471.823 210.312 ;
      RECT 0.036 210.816 471.823 210.888 ;
      RECT 0.036 211.392 471.823 211.464 ;
      RECT 0.036 211.968 471.823 212.040 ;
      RECT 0.036 212.544 471.823 212.616 ;
      RECT 0.036 213.120 471.823 213.192 ;
      RECT 0.036 213.696 471.823 213.768 ;
      RECT 0.036 214.272 471.823 214.344 ;
      RECT 0.036 214.848 471.823 214.920 ;
      RECT 0.036 215.424 471.823 215.496 ;
      RECT 0.036 216.000 471.823 216.072 ;
      RECT 0.036 216.576 471.823 216.648 ;
      RECT 0.036 217.152 471.823 217.224 ;
      RECT 0.036 217.728 471.823 217.800 ;
      RECT 0.036 218.304 471.823 218.376 ;
      RECT 0.036 218.880 471.823 218.952 ;
      RECT 0.036 219.456 471.823 219.528 ;
      RECT 0.036 220.032 471.823 220.104 ;
      RECT 0.036 220.608 471.823 220.680 ;
      RECT 0.036 221.184 471.823 221.256 ;
      RECT 0.036 221.760 471.823 221.832 ;
      RECT 0.036 222.336 471.823 222.408 ;
      RECT 0.036 222.912 471.823 222.984 ;
      RECT 0.036 223.488 471.823 223.560 ;
      RECT 0.036 224.064 471.823 224.136 ;
      RECT 0.036 224.640 471.823 224.712 ;
      RECT 0.036 225.216 471.823 225.288 ;
      RECT 0.036 225.792 471.823 225.864 ;
      RECT 0.036 226.368 471.823 226.440 ;
      RECT 0.036 226.944 471.823 227.016 ;
      RECT 0.036 227.520 471.823 227.592 ;
      RECT 0.036 228.096 471.823 228.168 ;
      RECT 0.036 228.672 471.823 228.744 ;
      RECT 0.036 229.248 471.823 229.320 ;
      RECT 0.036 229.824 471.823 229.896 ;
      RECT 0.036 230.400 471.823 230.472 ;
      RECT 0.036 230.976 471.823 231.048 ;
      RECT 0.036 231.552 471.823 231.624 ;
      RECT 0.036 232.128 471.823 232.200 ;
      RECT 0.036 232.704 471.823 232.776 ;
      RECT 0.036 233.280 471.823 233.352 ;
      RECT 0.036 233.856 471.823 233.928 ;
      RECT 0.036 234.432 471.823 234.504 ;
      RECT 0.036 235.008 471.823 235.080 ;
      RECT 0.036 235.584 471.823 235.656 ;
      RECT 0.036 236.160 471.823 236.232 ;
      RECT 0.036 236.736 471.823 236.808 ;
      RECT 0.036 237.312 471.823 237.384 ;
      RECT 0.036 237.888 471.823 237.960 ;
      RECT 0.036 238.464 471.823 238.536 ;
      RECT 0.036 239.040 471.823 239.112 ;
      RECT 0.036 239.616 471.823 239.688 ;
      RECT 0.036 240.192 471.823 240.264 ;
      RECT 0.036 240.768 471.823 240.840 ;
      RECT 0.036 241.344 471.823 241.416 ;
      RECT 0.036 241.920 471.823 241.992 ;
      RECT 0.036 242.496 471.823 242.568 ;
      RECT 0.036 243.072 471.823 243.144 ;
      RECT 0.036 243.648 471.823 243.720 ;
      RECT 0.036 244.224 471.823 244.296 ;
      RECT 0.036 244.800 471.823 244.872 ;
      RECT 0.036 245.376 471.823 245.448 ;
      RECT 0.036 245.952 471.823 246.024 ;
      RECT 0.036 246.528 471.823 246.600 ;
      RECT 0.036 247.104 471.823 247.176 ;
      RECT 0.036 247.680 471.823 247.752 ;
      RECT 0.036 248.256 471.823 248.328 ;
      RECT 0.036 248.832 471.823 248.904 ;
      RECT 0.036 249.408 471.823 249.480 ;
      RECT 0.036 249.984 471.823 250.056 ;
      RECT 0.036 250.560 471.823 250.632 ;
      RECT 0.036 251.136 471.823 251.208 ;
      RECT 0.036 251.712 471.823 251.784 ;
      RECT 0.036 252.288 471.823 252.360 ;
      RECT 0.036 252.864 471.823 252.936 ;
      RECT 0.036 253.440 471.823 253.512 ;
      RECT 0.036 254.016 471.823 254.088 ;
      RECT 0.036 254.592 471.823 254.664 ;
      RECT 0.036 255.168 471.823 255.240 ;
      RECT 0.036 255.744 471.823 255.816 ;
      RECT 0.036 256.320 471.823 256.392 ;
      RECT 0.036 256.896 471.823 256.968 ;
      RECT 0.036 257.472 471.823 257.544 ;
      RECT 0.036 258.048 471.823 258.120 ;
      RECT 0.036 258.624 471.823 258.696 ;
      RECT 0.036 259.200 471.823 259.272 ;
      RECT 0.036 259.776 471.823 259.848 ;
      RECT 0.036 260.352 471.823 260.424 ;
      RECT 0.036 260.928 471.823 261.000 ;
      RECT 0.036 261.504 471.823 261.576 ;
      RECT 0.036 262.080 471.823 262.152 ;
      RECT 0.036 262.656 471.823 262.728 ;
      RECT 0.036 263.232 471.823 263.304 ;
      RECT 0.036 263.808 471.823 263.880 ;
      RECT 0.036 264.384 471.823 264.456 ;
      RECT 0.036 264.960 471.823 265.032 ;
      RECT 0.036 265.536 471.823 265.608 ;
      RECT 0.036 266.112 471.823 266.184 ;
      RECT 0.036 266.688 471.823 266.760 ;
      RECT 0.036 267.264 471.823 267.336 ;
      RECT 0.036 267.840 471.823 267.912 ;
      RECT 0.036 268.416 471.823 268.488 ;
      RECT 0.036 268.992 471.823 269.064 ;
      RECT 0.036 269.568 471.823 269.640 ;
      RECT 0.036 270.144 471.823 270.216 ;
      RECT 0.036 270.720 471.823 270.792 ;
      RECT 0.036 271.296 471.823 271.368 ;
      RECT 0.036 271.872 471.823 271.944 ;
      RECT 0.036 272.448 471.823 272.520 ;
      RECT 0.036 273.024 471.823 273.096 ;
      RECT 0.036 273.600 471.823 273.672 ;
      RECT 0.036 274.176 471.823 274.248 ;
      RECT 0.036 274.752 471.823 274.824 ;
      RECT 0.036 275.328 471.823 275.400 ;
      RECT 0.036 275.904 471.823 275.976 ;
      RECT 0.036 276.480 471.823 276.552 ;
      RECT 0.036 277.056 471.823 277.128 ;
      RECT 0.036 277.632 471.823 277.704 ;
      RECT 0.036 278.208 471.823 278.280 ;
      RECT 0.036 278.784 471.823 278.856 ;
      RECT 0.036 279.360 471.823 279.432 ;
      RECT 0.036 279.936 471.823 280.008 ;
      RECT 0.036 280.512 471.823 280.584 ;
      RECT 0.036 281.088 471.823 281.160 ;
      RECT 0.036 281.664 471.823 281.736 ;
      RECT 0.036 282.240 471.823 282.312 ;
      RECT 0.036 282.816 471.823 282.888 ;
      RECT 0.036 283.392 471.823 283.464 ;
      RECT 0.036 283.968 471.823 284.040 ;
      RECT 0.036 284.544 471.823 284.616 ;
      RECT 0.036 285.120 471.823 285.192 ;
      RECT 0.036 285.696 471.823 285.768 ;
      RECT 0.036 286.272 471.823 286.344 ;
      RECT 0.036 286.848 471.823 286.920 ;
      RECT 0.036 287.424 471.823 287.496 ;
      RECT 0.036 288.000 471.823 288.072 ;
      RECT 0.036 288.576 471.823 288.648 ;
      RECT 0.036 289.152 471.823 289.224 ;
      RECT 0.036 289.728 471.823 289.800 ;
      RECT 0.036 290.304 471.823 290.376 ;
      RECT 0.036 290.880 471.823 290.952 ;
      RECT 0.036 291.456 471.823 291.528 ;
      RECT 0.036 292.032 471.823 292.104 ;
      RECT 0.036 292.608 471.823 292.680 ;
      RECT 0.036 293.184 471.823 293.256 ;
      RECT 0.036 293.760 471.823 293.832 ;
      RECT 0.036 294.336 471.823 294.408 ;
    END
  END VSS
  PIN VDD
    DIRECTION INOUT ;
    USE POWER ;
    PORT
      LAYER M4 ;
      RECT 0.036 0.288 471.823 0.360 ;
      RECT 0.036 0.864 471.823 0.936 ;
      RECT 0.036 1.440 471.823 1.512 ;
      RECT 0.036 2.016 471.823 2.088 ;
      RECT 0.036 2.592 471.823 2.664 ;
      RECT 0.036 3.168 471.823 3.240 ;
      RECT 0.036 3.744 471.823 3.816 ;
      RECT 0.036 4.320 471.823 4.392 ;
      RECT 0.036 4.896 471.823 4.968 ;
      RECT 0.036 5.472 471.823 5.544 ;
      RECT 0.036 6.048 471.823 6.120 ;
      RECT 0.036 6.624 471.823 6.696 ;
      RECT 0.036 7.200 471.823 7.272 ;
      RECT 0.036 7.776 471.823 7.848 ;
      RECT 0.036 8.352 471.823 8.424 ;
      RECT 0.036 8.928 471.823 9.000 ;
      RECT 0.036 9.504 471.823 9.576 ;
      RECT 0.036 10.080 471.823 10.152 ;
      RECT 0.036 10.656 471.823 10.728 ;
      RECT 0.036 11.232 471.823 11.304 ;
      RECT 0.036 11.808 471.823 11.880 ;
      RECT 0.036 12.384 471.823 12.456 ;
      RECT 0.036 12.960 471.823 13.032 ;
      RECT 0.036 13.536 471.823 13.608 ;
      RECT 0.036 14.112 471.823 14.184 ;
      RECT 0.036 14.688 471.823 14.760 ;
      RECT 0.036 15.264 471.823 15.336 ;
      RECT 0.036 15.840 471.823 15.912 ;
      RECT 0.036 16.416 471.823 16.488 ;
      RECT 0.036 16.992 471.823 17.064 ;
      RECT 0.036 17.568 471.823 17.640 ;
      RECT 0.036 18.144 471.823 18.216 ;
      RECT 0.036 18.720 471.823 18.792 ;
      RECT 0.036 19.296 471.823 19.368 ;
      RECT 0.036 19.872 471.823 19.944 ;
      RECT 0.036 20.448 471.823 20.520 ;
      RECT 0.036 21.024 471.823 21.096 ;
      RECT 0.036 21.600 471.823 21.672 ;
      RECT 0.036 22.176 471.823 22.248 ;
      RECT 0.036 22.752 471.823 22.824 ;
      RECT 0.036 23.328 471.823 23.400 ;
      RECT 0.036 23.904 471.823 23.976 ;
      RECT 0.036 24.480 471.823 24.552 ;
      RECT 0.036 25.056 471.823 25.128 ;
      RECT 0.036 25.632 471.823 25.704 ;
      RECT 0.036 26.208 471.823 26.280 ;
      RECT 0.036 26.784 471.823 26.856 ;
      RECT 0.036 27.360 471.823 27.432 ;
      RECT 0.036 27.936 471.823 28.008 ;
      RECT 0.036 28.512 471.823 28.584 ;
      RECT 0.036 29.088 471.823 29.160 ;
      RECT 0.036 29.664 471.823 29.736 ;
      RECT 0.036 30.240 471.823 30.312 ;
      RECT 0.036 30.816 471.823 30.888 ;
      RECT 0.036 31.392 471.823 31.464 ;
      RECT 0.036 31.968 471.823 32.040 ;
      RECT 0.036 32.544 471.823 32.616 ;
      RECT 0.036 33.120 471.823 33.192 ;
      RECT 0.036 33.696 471.823 33.768 ;
      RECT 0.036 34.272 471.823 34.344 ;
      RECT 0.036 34.848 471.823 34.920 ;
      RECT 0.036 35.424 471.823 35.496 ;
      RECT 0.036 36.000 471.823 36.072 ;
      RECT 0.036 36.576 471.823 36.648 ;
      RECT 0.036 37.152 471.823 37.224 ;
      RECT 0.036 37.728 471.823 37.800 ;
      RECT 0.036 38.304 471.823 38.376 ;
      RECT 0.036 38.880 471.823 38.952 ;
      RECT 0.036 39.456 471.823 39.528 ;
      RECT 0.036 40.032 471.823 40.104 ;
      RECT 0.036 40.608 471.823 40.680 ;
      RECT 0.036 41.184 471.823 41.256 ;
      RECT 0.036 41.760 471.823 41.832 ;
      RECT 0.036 42.336 471.823 42.408 ;
      RECT 0.036 42.912 471.823 42.984 ;
      RECT 0.036 43.488 471.823 43.560 ;
      RECT 0.036 44.064 471.823 44.136 ;
      RECT 0.036 44.640 471.823 44.712 ;
      RECT 0.036 45.216 471.823 45.288 ;
      RECT 0.036 45.792 471.823 45.864 ;
      RECT 0.036 46.368 471.823 46.440 ;
      RECT 0.036 46.944 471.823 47.016 ;
      RECT 0.036 47.520 471.823 47.592 ;
      RECT 0.036 48.096 471.823 48.168 ;
      RECT 0.036 48.672 471.823 48.744 ;
      RECT 0.036 49.248 471.823 49.320 ;
      RECT 0.036 49.824 471.823 49.896 ;
      RECT 0.036 50.400 471.823 50.472 ;
      RECT 0.036 50.976 471.823 51.048 ;
      RECT 0.036 51.552 471.823 51.624 ;
      RECT 0.036 52.128 471.823 52.200 ;
      RECT 0.036 52.704 471.823 52.776 ;
      RECT 0.036 53.280 471.823 53.352 ;
      RECT 0.036 53.856 471.823 53.928 ;
      RECT 0.036 54.432 471.823 54.504 ;
      RECT 0.036 55.008 471.823 55.080 ;
      RECT 0.036 55.584 471.823 55.656 ;
      RECT 0.036 56.160 471.823 56.232 ;
      RECT 0.036 56.736 471.823 56.808 ;
      RECT 0.036 57.312 471.823 57.384 ;
      RECT 0.036 57.888 471.823 57.960 ;
      RECT 0.036 58.464 471.823 58.536 ;
      RECT 0.036 59.040 471.823 59.112 ;
      RECT 0.036 59.616 471.823 59.688 ;
      RECT 0.036 60.192 471.823 60.264 ;
      RECT 0.036 60.768 471.823 60.840 ;
      RECT 0.036 61.344 471.823 61.416 ;
      RECT 0.036 61.920 471.823 61.992 ;
      RECT 0.036 62.496 471.823 62.568 ;
      RECT 0.036 63.072 471.823 63.144 ;
      RECT 0.036 63.648 471.823 63.720 ;
      RECT 0.036 64.224 471.823 64.296 ;
      RECT 0.036 64.800 471.823 64.872 ;
      RECT 0.036 65.376 471.823 65.448 ;
      RECT 0.036 65.952 471.823 66.024 ;
      RECT 0.036 66.528 471.823 66.600 ;
      RECT 0.036 67.104 471.823 67.176 ;
      RECT 0.036 67.680 471.823 67.752 ;
      RECT 0.036 68.256 471.823 68.328 ;
      RECT 0.036 68.832 471.823 68.904 ;
      RECT 0.036 69.408 471.823 69.480 ;
      RECT 0.036 69.984 471.823 70.056 ;
      RECT 0.036 70.560 471.823 70.632 ;
      RECT 0.036 71.136 471.823 71.208 ;
      RECT 0.036 71.712 471.823 71.784 ;
      RECT 0.036 72.288 471.823 72.360 ;
      RECT 0.036 72.864 471.823 72.936 ;
      RECT 0.036 73.440 471.823 73.512 ;
      RECT 0.036 74.016 471.823 74.088 ;
      RECT 0.036 74.592 471.823 74.664 ;
      RECT 0.036 75.168 471.823 75.240 ;
      RECT 0.036 75.744 471.823 75.816 ;
      RECT 0.036 76.320 471.823 76.392 ;
      RECT 0.036 76.896 471.823 76.968 ;
      RECT 0.036 77.472 471.823 77.544 ;
      RECT 0.036 78.048 471.823 78.120 ;
      RECT 0.036 78.624 471.823 78.696 ;
      RECT 0.036 79.200 471.823 79.272 ;
      RECT 0.036 79.776 471.823 79.848 ;
      RECT 0.036 80.352 471.823 80.424 ;
      RECT 0.036 80.928 471.823 81.000 ;
      RECT 0.036 81.504 471.823 81.576 ;
      RECT 0.036 82.080 471.823 82.152 ;
      RECT 0.036 82.656 471.823 82.728 ;
      RECT 0.036 83.232 471.823 83.304 ;
      RECT 0.036 83.808 471.823 83.880 ;
      RECT 0.036 84.384 471.823 84.456 ;
      RECT 0.036 84.960 471.823 85.032 ;
      RECT 0.036 85.536 471.823 85.608 ;
      RECT 0.036 86.112 471.823 86.184 ;
      RECT 0.036 86.688 471.823 86.760 ;
      RECT 0.036 87.264 471.823 87.336 ;
      RECT 0.036 87.840 471.823 87.912 ;
      RECT 0.036 88.416 471.823 88.488 ;
      RECT 0.036 88.992 471.823 89.064 ;
      RECT 0.036 89.568 471.823 89.640 ;
      RECT 0.036 90.144 471.823 90.216 ;
      RECT 0.036 90.720 471.823 90.792 ;
      RECT 0.036 91.296 471.823 91.368 ;
      RECT 0.036 91.872 471.823 91.944 ;
      RECT 0.036 92.448 471.823 92.520 ;
      RECT 0.036 93.024 471.823 93.096 ;
      RECT 0.036 93.600 471.823 93.672 ;
      RECT 0.036 94.176 471.823 94.248 ;
      RECT 0.036 94.752 471.823 94.824 ;
      RECT 0.036 95.328 471.823 95.400 ;
      RECT 0.036 95.904 471.823 95.976 ;
      RECT 0.036 96.480 471.823 96.552 ;
      RECT 0.036 97.056 471.823 97.128 ;
      RECT 0.036 97.632 471.823 97.704 ;
      RECT 0.036 98.208 471.823 98.280 ;
      RECT 0.036 98.784 471.823 98.856 ;
      RECT 0.036 99.360 471.823 99.432 ;
      RECT 0.036 99.936 471.823 100.008 ;
      RECT 0.036 100.512 471.823 100.584 ;
      RECT 0.036 101.088 471.823 101.160 ;
      RECT 0.036 101.664 471.823 101.736 ;
      RECT 0.036 102.240 471.823 102.312 ;
      RECT 0.036 102.816 471.823 102.888 ;
      RECT 0.036 103.392 471.823 103.464 ;
      RECT 0.036 103.968 471.823 104.040 ;
      RECT 0.036 104.544 471.823 104.616 ;
      RECT 0.036 105.120 471.823 105.192 ;
      RECT 0.036 105.696 471.823 105.768 ;
      RECT 0.036 106.272 471.823 106.344 ;
      RECT 0.036 106.848 471.823 106.920 ;
      RECT 0.036 107.424 471.823 107.496 ;
      RECT 0.036 108.000 471.823 108.072 ;
      RECT 0.036 108.576 471.823 108.648 ;
      RECT 0.036 109.152 471.823 109.224 ;
      RECT 0.036 109.728 471.823 109.800 ;
      RECT 0.036 110.304 471.823 110.376 ;
      RECT 0.036 110.880 471.823 110.952 ;
      RECT 0.036 111.456 471.823 111.528 ;
      RECT 0.036 112.032 471.823 112.104 ;
      RECT 0.036 112.608 471.823 112.680 ;
      RECT 0.036 113.184 471.823 113.256 ;
      RECT 0.036 113.760 471.823 113.832 ;
      RECT 0.036 114.336 471.823 114.408 ;
      RECT 0.036 114.912 471.823 114.984 ;
      RECT 0.036 115.488 471.823 115.560 ;
      RECT 0.036 116.064 471.823 116.136 ;
      RECT 0.036 116.640 471.823 116.712 ;
      RECT 0.036 117.216 471.823 117.288 ;
      RECT 0.036 117.792 471.823 117.864 ;
      RECT 0.036 118.368 471.823 118.440 ;
      RECT 0.036 118.944 471.823 119.016 ;
      RECT 0.036 119.520 471.823 119.592 ;
      RECT 0.036 120.096 471.823 120.168 ;
      RECT 0.036 120.672 471.823 120.744 ;
      RECT 0.036 121.248 471.823 121.320 ;
      RECT 0.036 121.824 471.823 121.896 ;
      RECT 0.036 122.400 471.823 122.472 ;
      RECT 0.036 122.976 471.823 123.048 ;
      RECT 0.036 123.552 471.823 123.624 ;
      RECT 0.036 124.128 471.823 124.200 ;
      RECT 0.036 124.704 471.823 124.776 ;
      RECT 0.036 125.280 471.823 125.352 ;
      RECT 0.036 125.856 471.823 125.928 ;
      RECT 0.036 126.432 471.823 126.504 ;
      RECT 0.036 127.008 471.823 127.080 ;
      RECT 0.036 127.584 471.823 127.656 ;
      RECT 0.036 128.160 471.823 128.232 ;
      RECT 0.036 128.736 471.823 128.808 ;
      RECT 0.036 129.312 471.823 129.384 ;
      RECT 0.036 129.888 471.823 129.960 ;
      RECT 0.036 130.464 471.823 130.536 ;
      RECT 0.036 131.040 471.823 131.112 ;
      RECT 0.036 131.616 471.823 131.688 ;
      RECT 0.036 132.192 471.823 132.264 ;
      RECT 0.036 132.768 471.823 132.840 ;
      RECT 0.036 133.344 471.823 133.416 ;
      RECT 0.036 133.920 471.823 133.992 ;
      RECT 0.036 134.496 471.823 134.568 ;
      RECT 0.036 135.072 471.823 135.144 ;
      RECT 0.036 135.648 471.823 135.720 ;
      RECT 0.036 136.224 471.823 136.296 ;
      RECT 0.036 136.800 471.823 136.872 ;
      RECT 0.036 137.376 471.823 137.448 ;
      RECT 0.036 137.952 471.823 138.024 ;
      RECT 0.036 138.528 471.823 138.600 ;
      RECT 0.036 139.104 471.823 139.176 ;
      RECT 0.036 139.680 471.823 139.752 ;
      RECT 0.036 140.256 471.823 140.328 ;
      RECT 0.036 140.832 471.823 140.904 ;
      RECT 0.036 141.408 471.823 141.480 ;
      RECT 0.036 141.984 471.823 142.056 ;
      RECT 0.036 142.560 471.823 142.632 ;
      RECT 0.036 143.136 471.823 143.208 ;
      RECT 0.036 143.712 471.823 143.784 ;
      RECT 0.036 144.288 471.823 144.360 ;
      RECT 0.036 144.864 471.823 144.936 ;
      RECT 0.036 145.440 471.823 145.512 ;
      RECT 0.036 146.016 471.823 146.088 ;
      RECT 0.036 146.592 471.823 146.664 ;
      RECT 0.036 147.168 471.823 147.240 ;
      RECT 0.036 147.744 471.823 147.816 ;
      RECT 0.036 148.320 471.823 148.392 ;
      RECT 0.036 148.896 471.823 148.968 ;
      RECT 0.036 149.472 471.823 149.544 ;
      RECT 0.036 150.048 471.823 150.120 ;
      RECT 0.036 150.624 471.823 150.696 ;
      RECT 0.036 151.200 471.823 151.272 ;
      RECT 0.036 151.776 471.823 151.848 ;
      RECT 0.036 152.352 471.823 152.424 ;
      RECT 0.036 152.928 471.823 153.000 ;
      RECT 0.036 153.504 471.823 153.576 ;
      RECT 0.036 154.080 471.823 154.152 ;
      RECT 0.036 154.656 471.823 154.728 ;
      RECT 0.036 155.232 471.823 155.304 ;
      RECT 0.036 155.808 471.823 155.880 ;
      RECT 0.036 156.384 471.823 156.456 ;
      RECT 0.036 156.960 471.823 157.032 ;
      RECT 0.036 157.536 471.823 157.608 ;
      RECT 0.036 158.112 471.823 158.184 ;
      RECT 0.036 158.688 471.823 158.760 ;
      RECT 0.036 159.264 471.823 159.336 ;
      RECT 0.036 159.840 471.823 159.912 ;
      RECT 0.036 160.416 471.823 160.488 ;
      RECT 0.036 160.992 471.823 161.064 ;
      RECT 0.036 161.568 471.823 161.640 ;
      RECT 0.036 162.144 471.823 162.216 ;
      RECT 0.036 162.720 471.823 162.792 ;
      RECT 0.036 163.296 471.823 163.368 ;
      RECT 0.036 163.872 471.823 163.944 ;
      RECT 0.036 164.448 471.823 164.520 ;
      RECT 0.036 165.024 471.823 165.096 ;
      RECT 0.036 165.600 471.823 165.672 ;
      RECT 0.036 166.176 471.823 166.248 ;
      RECT 0.036 166.752 471.823 166.824 ;
      RECT 0.036 167.328 471.823 167.400 ;
      RECT 0.036 167.904 471.823 167.976 ;
      RECT 0.036 168.480 471.823 168.552 ;
      RECT 0.036 169.056 471.823 169.128 ;
      RECT 0.036 169.632 471.823 169.704 ;
      RECT 0.036 170.208 471.823 170.280 ;
      RECT 0.036 170.784 471.823 170.856 ;
      RECT 0.036 171.360 471.823 171.432 ;
      RECT 0.036 171.936 471.823 172.008 ;
      RECT 0.036 172.512 471.823 172.584 ;
      RECT 0.036 173.088 471.823 173.160 ;
      RECT 0.036 173.664 471.823 173.736 ;
      RECT 0.036 174.240 471.823 174.312 ;
      RECT 0.036 174.816 471.823 174.888 ;
      RECT 0.036 175.392 471.823 175.464 ;
      RECT 0.036 175.968 471.823 176.040 ;
      RECT 0.036 176.544 471.823 176.616 ;
      RECT 0.036 177.120 471.823 177.192 ;
      RECT 0.036 177.696 471.823 177.768 ;
      RECT 0.036 178.272 471.823 178.344 ;
      RECT 0.036 178.848 471.823 178.920 ;
      RECT 0.036 179.424 471.823 179.496 ;
      RECT 0.036 180.000 471.823 180.072 ;
      RECT 0.036 180.576 471.823 180.648 ;
      RECT 0.036 181.152 471.823 181.224 ;
      RECT 0.036 181.728 471.823 181.800 ;
      RECT 0.036 182.304 471.823 182.376 ;
      RECT 0.036 182.880 471.823 182.952 ;
      RECT 0.036 183.456 471.823 183.528 ;
      RECT 0.036 184.032 471.823 184.104 ;
      RECT 0.036 184.608 471.823 184.680 ;
      RECT 0.036 185.184 471.823 185.256 ;
      RECT 0.036 185.760 471.823 185.832 ;
      RECT 0.036 186.336 471.823 186.408 ;
      RECT 0.036 186.912 471.823 186.984 ;
      RECT 0.036 187.488 471.823 187.560 ;
      RECT 0.036 188.064 471.823 188.136 ;
      RECT 0.036 188.640 471.823 188.712 ;
      RECT 0.036 189.216 471.823 189.288 ;
      RECT 0.036 189.792 471.823 189.864 ;
      RECT 0.036 190.368 471.823 190.440 ;
      RECT 0.036 190.944 471.823 191.016 ;
      RECT 0.036 191.520 471.823 191.592 ;
      RECT 0.036 192.096 471.823 192.168 ;
      RECT 0.036 192.672 471.823 192.744 ;
      RECT 0.036 193.248 471.823 193.320 ;
      RECT 0.036 193.824 471.823 193.896 ;
      RECT 0.036 194.400 471.823 194.472 ;
      RECT 0.036 194.976 471.823 195.048 ;
      RECT 0.036 195.552 471.823 195.624 ;
      RECT 0.036 196.128 471.823 196.200 ;
      RECT 0.036 196.704 471.823 196.776 ;
      RECT 0.036 197.280 471.823 197.352 ;
      RECT 0.036 197.856 471.823 197.928 ;
      RECT 0.036 198.432 471.823 198.504 ;
      RECT 0.036 199.008 471.823 199.080 ;
      RECT 0.036 199.584 471.823 199.656 ;
      RECT 0.036 200.160 471.823 200.232 ;
      RECT 0.036 200.736 471.823 200.808 ;
      RECT 0.036 201.312 471.823 201.384 ;
      RECT 0.036 201.888 471.823 201.960 ;
      RECT 0.036 202.464 471.823 202.536 ;
      RECT 0.036 203.040 471.823 203.112 ;
      RECT 0.036 203.616 471.823 203.688 ;
      RECT 0.036 204.192 471.823 204.264 ;
      RECT 0.036 204.768 471.823 204.840 ;
      RECT 0.036 205.344 471.823 205.416 ;
      RECT 0.036 205.920 471.823 205.992 ;
      RECT 0.036 206.496 471.823 206.568 ;
      RECT 0.036 207.072 471.823 207.144 ;
      RECT 0.036 207.648 471.823 207.720 ;
      RECT 0.036 208.224 471.823 208.296 ;
      RECT 0.036 208.800 471.823 208.872 ;
      RECT 0.036 209.376 471.823 209.448 ;
      RECT 0.036 209.952 471.823 210.024 ;
      RECT 0.036 210.528 471.823 210.600 ;
      RECT 0.036 211.104 471.823 211.176 ;
      RECT 0.036 211.680 471.823 211.752 ;
      RECT 0.036 212.256 471.823 212.328 ;
      RECT 0.036 212.832 471.823 212.904 ;
      RECT 0.036 213.408 471.823 213.480 ;
      RECT 0.036 213.984 471.823 214.056 ;
      RECT 0.036 214.560 471.823 214.632 ;
      RECT 0.036 215.136 471.823 215.208 ;
      RECT 0.036 215.712 471.823 215.784 ;
      RECT 0.036 216.288 471.823 216.360 ;
      RECT 0.036 216.864 471.823 216.936 ;
      RECT 0.036 217.440 471.823 217.512 ;
      RECT 0.036 218.016 471.823 218.088 ;
      RECT 0.036 218.592 471.823 218.664 ;
      RECT 0.036 219.168 471.823 219.240 ;
      RECT 0.036 219.744 471.823 219.816 ;
      RECT 0.036 220.320 471.823 220.392 ;
      RECT 0.036 220.896 471.823 220.968 ;
      RECT 0.036 221.472 471.823 221.544 ;
      RECT 0.036 222.048 471.823 222.120 ;
      RECT 0.036 222.624 471.823 222.696 ;
      RECT 0.036 223.200 471.823 223.272 ;
      RECT 0.036 223.776 471.823 223.848 ;
      RECT 0.036 224.352 471.823 224.424 ;
      RECT 0.036 224.928 471.823 225.000 ;
      RECT 0.036 225.504 471.823 225.576 ;
      RECT 0.036 226.080 471.823 226.152 ;
      RECT 0.036 226.656 471.823 226.728 ;
      RECT 0.036 227.232 471.823 227.304 ;
      RECT 0.036 227.808 471.823 227.880 ;
      RECT 0.036 228.384 471.823 228.456 ;
      RECT 0.036 228.960 471.823 229.032 ;
      RECT 0.036 229.536 471.823 229.608 ;
      RECT 0.036 230.112 471.823 230.184 ;
      RECT 0.036 230.688 471.823 230.760 ;
      RECT 0.036 231.264 471.823 231.336 ;
      RECT 0.036 231.840 471.823 231.912 ;
      RECT 0.036 232.416 471.823 232.488 ;
      RECT 0.036 232.992 471.823 233.064 ;
      RECT 0.036 233.568 471.823 233.640 ;
      RECT 0.036 234.144 471.823 234.216 ;
      RECT 0.036 234.720 471.823 234.792 ;
      RECT 0.036 235.296 471.823 235.368 ;
      RECT 0.036 235.872 471.823 235.944 ;
      RECT 0.036 236.448 471.823 236.520 ;
      RECT 0.036 237.024 471.823 237.096 ;
      RECT 0.036 237.600 471.823 237.672 ;
      RECT 0.036 238.176 471.823 238.248 ;
      RECT 0.036 238.752 471.823 238.824 ;
      RECT 0.036 239.328 471.823 239.400 ;
      RECT 0.036 239.904 471.823 239.976 ;
      RECT 0.036 240.480 471.823 240.552 ;
      RECT 0.036 241.056 471.823 241.128 ;
      RECT 0.036 241.632 471.823 241.704 ;
      RECT 0.036 242.208 471.823 242.280 ;
      RECT 0.036 242.784 471.823 242.856 ;
      RECT 0.036 243.360 471.823 243.432 ;
      RECT 0.036 243.936 471.823 244.008 ;
      RECT 0.036 244.512 471.823 244.584 ;
      RECT 0.036 245.088 471.823 245.160 ;
      RECT 0.036 245.664 471.823 245.736 ;
      RECT 0.036 246.240 471.823 246.312 ;
      RECT 0.036 246.816 471.823 246.888 ;
      RECT 0.036 247.392 471.823 247.464 ;
      RECT 0.036 247.968 471.823 248.040 ;
      RECT 0.036 248.544 471.823 248.616 ;
      RECT 0.036 249.120 471.823 249.192 ;
      RECT 0.036 249.696 471.823 249.768 ;
      RECT 0.036 250.272 471.823 250.344 ;
      RECT 0.036 250.848 471.823 250.920 ;
      RECT 0.036 251.424 471.823 251.496 ;
      RECT 0.036 252.000 471.823 252.072 ;
      RECT 0.036 252.576 471.823 252.648 ;
      RECT 0.036 253.152 471.823 253.224 ;
      RECT 0.036 253.728 471.823 253.800 ;
      RECT 0.036 254.304 471.823 254.376 ;
      RECT 0.036 254.880 471.823 254.952 ;
      RECT 0.036 255.456 471.823 255.528 ;
      RECT 0.036 256.032 471.823 256.104 ;
      RECT 0.036 256.608 471.823 256.680 ;
      RECT 0.036 257.184 471.823 257.256 ;
      RECT 0.036 257.760 471.823 257.832 ;
      RECT 0.036 258.336 471.823 258.408 ;
      RECT 0.036 258.912 471.823 258.984 ;
      RECT 0.036 259.488 471.823 259.560 ;
      RECT 0.036 260.064 471.823 260.136 ;
      RECT 0.036 260.640 471.823 260.712 ;
      RECT 0.036 261.216 471.823 261.288 ;
      RECT 0.036 261.792 471.823 261.864 ;
      RECT 0.036 262.368 471.823 262.440 ;
      RECT 0.036 262.944 471.823 263.016 ;
      RECT 0.036 263.520 471.823 263.592 ;
      RECT 0.036 264.096 471.823 264.168 ;
      RECT 0.036 264.672 471.823 264.744 ;
      RECT 0.036 265.248 471.823 265.320 ;
      RECT 0.036 265.824 471.823 265.896 ;
      RECT 0.036 266.400 471.823 266.472 ;
      RECT 0.036 266.976 471.823 267.048 ;
      RECT 0.036 267.552 471.823 267.624 ;
      RECT 0.036 268.128 471.823 268.200 ;
      RECT 0.036 268.704 471.823 268.776 ;
      RECT 0.036 269.280 471.823 269.352 ;
      RECT 0.036 269.856 471.823 269.928 ;
      RECT 0.036 270.432 471.823 270.504 ;
      RECT 0.036 271.008 471.823 271.080 ;
      RECT 0.036 271.584 471.823 271.656 ;
      RECT 0.036 272.160 471.823 272.232 ;
      RECT 0.036 272.736 471.823 272.808 ;
      RECT 0.036 273.312 471.823 273.384 ;
      RECT 0.036 273.888 471.823 273.960 ;
      RECT 0.036 274.464 471.823 274.536 ;
      RECT 0.036 275.040 471.823 275.112 ;
      RECT 0.036 275.616 471.823 275.688 ;
      RECT 0.036 276.192 471.823 276.264 ;
      RECT 0.036 276.768 471.823 276.840 ;
      RECT 0.036 277.344 471.823 277.416 ;
      RECT 0.036 277.920 471.823 277.992 ;
      RECT 0.036 278.496 471.823 278.568 ;
      RECT 0.036 279.072 471.823 279.144 ;
      RECT 0.036 279.648 471.823 279.720 ;
      RECT 0.036 280.224 471.823 280.296 ;
      RECT 0.036 280.800 471.823 280.872 ;
      RECT 0.036 281.376 471.823 281.448 ;
      RECT 0.036 281.952 471.823 282.024 ;
      RECT 0.036 282.528 471.823 282.600 ;
      RECT 0.036 283.104 471.823 283.176 ;
      RECT 0.036 283.680 471.823 283.752 ;
      RECT 0.036 284.256 471.823 284.328 ;
      RECT 0.036 284.832 471.823 284.904 ;
      RECT 0.036 285.408 471.823 285.480 ;
      RECT 0.036 285.984 471.823 286.056 ;
      RECT 0.036 286.560 471.823 286.632 ;
      RECT 0.036 287.136 471.823 287.208 ;
      RECT 0.036 287.712 471.823 287.784 ;
      RECT 0.036 288.288 471.823 288.360 ;
      RECT 0.036 288.864 471.823 288.936 ;
      RECT 0.036 289.440 471.823 289.512 ;
      RECT 0.036 290.016 471.823 290.088 ;
      RECT 0.036 290.592 471.823 290.664 ;
      RECT 0.036 291.168 471.823 291.240 ;
      RECT 0.036 291.744 471.823 291.816 ;
      RECT 0.036 292.320 471.823 292.392 ;
      RECT 0.036 292.896 471.823 292.968 ;
      RECT 0.036 293.472 471.823 293.544 ;
      RECT 0.036 294.048 471.823 294.120 ;
      RECT 0.036 294.624 471.823 294.696 ;
    END
  END VDD
  OBS
    LAYER M1 ;
    RECT 0 0 471.859 294.912 ;
    LAYER M2 ;
    RECT 0 0 471.859 294.912 ;
    LAYER M3 ;
    RECT 0 0 471.859 294.912 ;
    LAYER M4 ;
    RECT 0 0 471.859 294.912 ;
  END
END mobol_sram_4096x512_2r1w

END LIBRARY
